VERSION 5.8 ;
BUSBITCHARS "[]" ;
DIVIDERCHAR "/" ;
UNITS
    DATABASE MICRONS 1000 ;
END UNITS

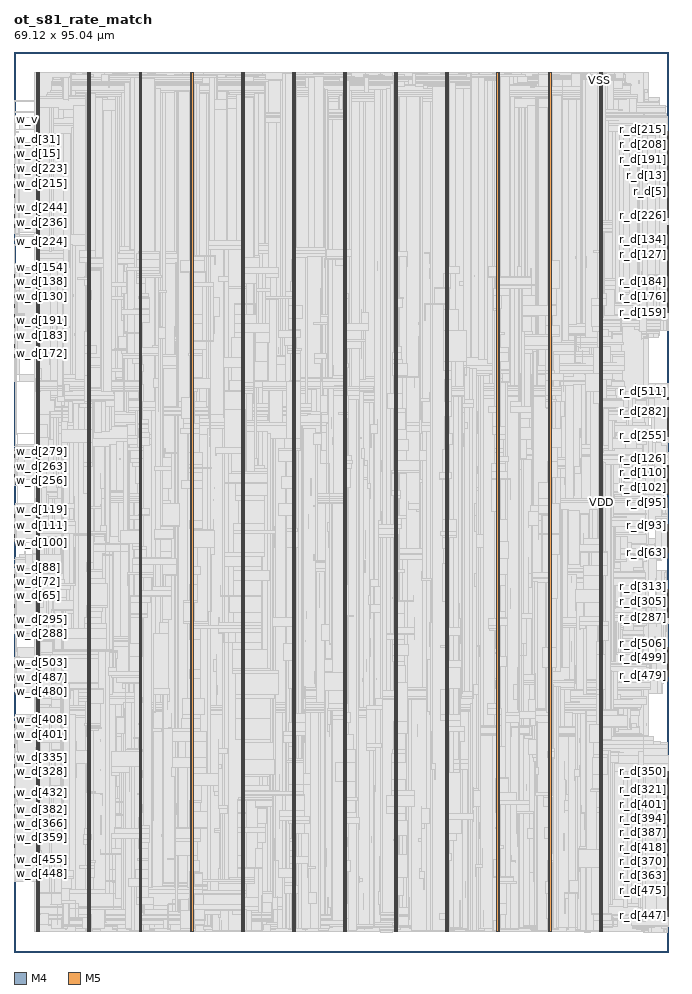
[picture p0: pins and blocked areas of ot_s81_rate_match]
MACRO ot_s81_rate_match
  FOREIGN ot_s81_rate_match 0 0 ;
  CLASS BLOCK ;
  SIZE 69.12 BY 95.04 ;
  PIN fault
    DIRECTION OUTPUT ;
    USE SIGNAL ;
    PORT
      LAYER M4 ;
        RECT  69.036 80.592 69.12 80.616 ;
    END
  END fault
  PIN r_d[0]
    DIRECTION OUTPUT ;
    USE SIGNAL ;
    PORT
      LAYER M4 ;
        RECT  69.036 80.688 69.12 80.712 ;
    END
  END r_d[0]
  PIN r_d[100]
    DIRECTION OUTPUT ;
    USE SIGNAL ;
    PORT
      LAYER M4 ;
        RECT  69.036 48.816 69.12 48.84 ;
    END
  END r_d[100]
  PIN r_d[101]
    DIRECTION OUTPUT ;
    USE SIGNAL ;
    PORT
      LAYER M4 ;
        RECT  69.036 48.912 69.12 48.936 ;
    END
  END r_d[101]
  PIN r_d[102]
    DIRECTION OUTPUT ;
    USE SIGNAL ;
    PORT
      LAYER M4 ;
        RECT  69.036 49.008 69.12 49.032 ;
    END
  END r_d[102]
  PIN r_d[103]
    DIRECTION OUTPUT ;
    USE SIGNAL ;
    PORT
      LAYER M4 ;
        RECT  69.036 49.104 69.12 49.128 ;
    END
  END r_d[103]
  PIN r_d[104]
    DIRECTION OUTPUT ;
    USE SIGNAL ;
    PORT
      LAYER M4 ;
        RECT  69.036 49.2 69.12 49.224 ;
    END
  END r_d[104]
  PIN r_d[105]
    DIRECTION OUTPUT ;
    USE SIGNAL ;
    PORT
      LAYER M4 ;
        RECT  69.036 49.296 69.12 49.32 ;
    END
  END r_d[105]
  PIN r_d[106]
    DIRECTION OUTPUT ;
    USE SIGNAL ;
    PORT
      LAYER M4 ;
        RECT  69.036 49.392 69.12 49.416 ;
    END
  END r_d[106]
  PIN r_d[107]
    DIRECTION OUTPUT ;
    USE SIGNAL ;
    PORT
      LAYER M4 ;
        RECT  69.036 49.488 69.12 49.512 ;
    END
  END r_d[107]
  PIN r_d[108]
    DIRECTION OUTPUT ;
    USE SIGNAL ;
    PORT
      LAYER M4 ;
        RECT  69.036 49.584 69.12 49.608 ;
    END
  END r_d[108]
  PIN r_d[109]
    DIRECTION OUTPUT ;
    USE SIGNAL ;
    PORT
      LAYER M4 ;
        RECT  69.036 49.68 69.12 49.704 ;
    END
  END r_d[109]
  PIN r_d[10]
    DIRECTION OUTPUT ;
    USE SIGNAL ;
    PORT
      LAYER M4 ;
        RECT  69.036 81.648 69.12 81.672 ;
    END
  END r_d[10]
  PIN r_d[110]
    DIRECTION OUTPUT ;
    USE SIGNAL ;
    PORT
      LAYER M4 ;
        RECT  69.036 49.776 69.12 49.8 ;
    END
  END r_d[110]
  PIN r_d[111]
    DIRECTION OUTPUT ;
    USE SIGNAL ;
    PORT
      LAYER M4 ;
        RECT  69.036 49.872 69.12 49.896 ;
    END
  END r_d[111]
  PIN r_d[112]
    DIRECTION OUTPUT ;
    USE SIGNAL ;
    PORT
      LAYER M4 ;
        RECT  69.036 49.968 69.12 49.992 ;
    END
  END r_d[112]
  PIN r_d[113]
    DIRECTION OUTPUT ;
    USE SIGNAL ;
    PORT
      LAYER M4 ;
        RECT  69.036 50.064 69.12 50.088 ;
    END
  END r_d[113]
  PIN r_d[114]
    DIRECTION OUTPUT ;
    USE SIGNAL ;
    PORT
      LAYER M4 ;
        RECT  69.036 50.16 69.12 50.184 ;
    END
  END r_d[114]
  PIN r_d[115]
    DIRECTION OUTPUT ;
    USE SIGNAL ;
    PORT
      LAYER M4 ;
        RECT  69.036 50.256 69.12 50.28 ;
    END
  END r_d[115]
  PIN r_d[116]
    DIRECTION OUTPUT ;
    USE SIGNAL ;
    PORT
      LAYER M4 ;
        RECT  69.036 50.352 69.12 50.376 ;
    END
  END r_d[116]
  PIN r_d[117]
    DIRECTION OUTPUT ;
    USE SIGNAL ;
    PORT
      LAYER M4 ;
        RECT  69.036 50.448 69.12 50.472 ;
    END
  END r_d[117]
  PIN r_d[118]
    DIRECTION OUTPUT ;
    USE SIGNAL ;
    PORT
      LAYER M4 ;
        RECT  69.036 50.544 69.12 50.568 ;
    END
  END r_d[118]
  PIN r_d[119]
    DIRECTION OUTPUT ;
    USE SIGNAL ;
    PORT
      LAYER M4 ;
        RECT  69.036 50.64 69.12 50.664 ;
    END
  END r_d[119]
  PIN r_d[11]
    DIRECTION OUTPUT ;
    USE SIGNAL ;
    PORT
      LAYER M4 ;
        RECT  69.036 81.744 69.12 81.768 ;
    END
  END r_d[11]
  PIN r_d[120]
    DIRECTION OUTPUT ;
    USE SIGNAL ;
    PORT
      LAYER M4 ;
        RECT  69.036 50.736 69.12 50.76 ;
    END
  END r_d[120]
  PIN r_d[121]
    DIRECTION OUTPUT ;
    USE SIGNAL ;
    PORT
      LAYER M4 ;
        RECT  69.036 50.832 69.12 50.856 ;
    END
  END r_d[121]
  PIN r_d[122]
    DIRECTION OUTPUT ;
    USE SIGNAL ;
    PORT
      LAYER M4 ;
        RECT  69.036 50.928 69.12 50.952 ;
    END
  END r_d[122]
  PIN r_d[123]
    DIRECTION OUTPUT ;
    USE SIGNAL ;
    PORT
      LAYER M4 ;
        RECT  69.036 51.024 69.12 51.048 ;
    END
  END r_d[123]
  PIN r_d[124]
    DIRECTION OUTPUT ;
    USE SIGNAL ;
    PORT
      LAYER M4 ;
        RECT  69.036 51.12 69.12 51.144 ;
    END
  END r_d[124]
  PIN r_d[125]
    DIRECTION OUTPUT ;
    USE SIGNAL ;
    PORT
      LAYER M4 ;
        RECT  69.036 51.216 69.12 51.24 ;
    END
  END r_d[125]
  PIN r_d[126]
    DIRECTION OUTPUT ;
    USE SIGNAL ;
    PORT
      LAYER M4 ;
        RECT  69.036 51.312 69.12 51.336 ;
    END
  END r_d[126]
  PIN r_d[127]
    DIRECTION OUTPUT ;
    USE SIGNAL ;
    PORT
      LAYER M4 ;
        RECT  69.036 73.68 69.12 73.704 ;
    END
  END r_d[127]
  PIN r_d[128]
    DIRECTION OUTPUT ;
    USE SIGNAL ;
    PORT
      LAYER M4 ;
        RECT  69.036 73.776 69.12 73.8 ;
    END
  END r_d[128]
  PIN r_d[129]
    DIRECTION OUTPUT ;
    USE SIGNAL ;
    PORT
      LAYER M4 ;
        RECT  69.036 73.872 69.12 73.896 ;
    END
  END r_d[129]
  PIN r_d[12]
    DIRECTION OUTPUT ;
    USE SIGNAL ;
    PORT
      LAYER M4 ;
        RECT  69.036 81.84 69.12 81.864 ;
    END
  END r_d[12]
  PIN r_d[130]
    DIRECTION OUTPUT ;
    USE SIGNAL ;
    PORT
      LAYER M4 ;
        RECT  69.036 73.968 69.12 73.992 ;
    END
  END r_d[130]
  PIN r_d[131]
    DIRECTION OUTPUT ;
    USE SIGNAL ;
    PORT
      LAYER M4 ;
        RECT  69.036 74.064 69.12 74.088 ;
    END
  END r_d[131]
  PIN r_d[132]
    DIRECTION OUTPUT ;
    USE SIGNAL ;
    PORT
      LAYER M4 ;
        RECT  69.036 74.16 69.12 74.184 ;
    END
  END r_d[132]
  PIN r_d[133]
    DIRECTION OUTPUT ;
    USE SIGNAL ;
    PORT
      LAYER M4 ;
        RECT  69.036 74.256 69.12 74.28 ;
    END
  END r_d[133]
  PIN r_d[134]
    DIRECTION OUTPUT ;
    USE SIGNAL ;
    PORT
      LAYER M4 ;
        RECT  69.036 74.352 69.12 74.376 ;
    END
  END r_d[134]
  PIN r_d[135]
    DIRECTION OUTPUT ;
    USE SIGNAL ;
    PORT
      LAYER M4 ;
        RECT  69.036 74.448 69.12 74.472 ;
    END
  END r_d[135]
  PIN r_d[136]
    DIRECTION OUTPUT ;
    USE SIGNAL ;
    PORT
      LAYER M4 ;
        RECT  69.036 74.544 69.12 74.568 ;
    END
  END r_d[136]
  PIN r_d[137]
    DIRECTION OUTPUT ;
    USE SIGNAL ;
    PORT
      LAYER M4 ;
        RECT  69.036 74.64 69.12 74.664 ;
    END
  END r_d[137]
  PIN r_d[138]
    DIRECTION OUTPUT ;
    USE SIGNAL ;
    PORT
      LAYER M4 ;
        RECT  69.036 74.736 69.12 74.76 ;
    END
  END r_d[138]
  PIN r_d[139]
    DIRECTION OUTPUT ;
    USE SIGNAL ;
    PORT
      LAYER M4 ;
        RECT  69.036 74.832 69.12 74.856 ;
    END
  END r_d[139]
  PIN r_d[13]
    DIRECTION OUTPUT ;
    USE SIGNAL ;
    PORT
      LAYER M4 ;
        RECT  69.036 81.936 69.12 81.96 ;
    END
  END r_d[13]
  PIN r_d[140]
    DIRECTION OUTPUT ;
    USE SIGNAL ;
    PORT
      LAYER M4 ;
        RECT  69.036 74.928 69.12 74.952 ;
    END
  END r_d[140]
  PIN r_d[141]
    DIRECTION OUTPUT ;
    USE SIGNAL ;
    PORT
      LAYER M4 ;
        RECT  69.036 75.024 69.12 75.048 ;
    END
  END r_d[141]
  PIN r_d[142]
    DIRECTION OUTPUT ;
    USE SIGNAL ;
    PORT
      LAYER M4 ;
        RECT  69.036 75.12 69.12 75.144 ;
    END
  END r_d[142]
  PIN r_d[143]
    DIRECTION OUTPUT ;
    USE SIGNAL ;
    PORT
      LAYER M4 ;
        RECT  69.036 75.216 69.12 75.24 ;
    END
  END r_d[143]
  PIN r_d[144]
    DIRECTION OUTPUT ;
    USE SIGNAL ;
    PORT
      LAYER M4 ;
        RECT  69.036 75.312 69.12 75.336 ;
    END
  END r_d[144]
  PIN r_d[145]
    DIRECTION OUTPUT ;
    USE SIGNAL ;
    PORT
      LAYER M4 ;
        RECT  69.036 75.408 69.12 75.432 ;
    END
  END r_d[145]
  PIN r_d[146]
    DIRECTION OUTPUT ;
    USE SIGNAL ;
    PORT
      LAYER M4 ;
        RECT  69.036 75.504 69.12 75.528 ;
    END
  END r_d[146]
  PIN r_d[147]
    DIRECTION OUTPUT ;
    USE SIGNAL ;
    PORT
      LAYER M4 ;
        RECT  69.036 75.6 69.12 75.624 ;
    END
  END r_d[147]
  PIN r_d[148]
    DIRECTION OUTPUT ;
    USE SIGNAL ;
    PORT
      LAYER M4 ;
        RECT  69.036 75.696 69.12 75.72 ;
    END
  END r_d[148]
  PIN r_d[149]
    DIRECTION OUTPUT ;
    USE SIGNAL ;
    PORT
      LAYER M4 ;
        RECT  69.036 75.792 69.12 75.816 ;
    END
  END r_d[149]
  PIN r_d[14]
    DIRECTION OUTPUT ;
    USE SIGNAL ;
    PORT
      LAYER M4 ;
        RECT  69.036 82.032 69.12 82.056 ;
    END
  END r_d[14]
  PIN r_d[150]
    DIRECTION OUTPUT ;
    USE SIGNAL ;
    PORT
      LAYER M4 ;
        RECT  69.036 75.888 69.12 75.912 ;
    END
  END r_d[150]
  PIN r_d[151]
    DIRECTION OUTPUT ;
    USE SIGNAL ;
    PORT
      LAYER M4 ;
        RECT  69.036 75.984 69.12 76.008 ;
    END
  END r_d[151]
  PIN r_d[152]
    DIRECTION OUTPUT ;
    USE SIGNAL ;
    PORT
      LAYER M4 ;
        RECT  69.036 76.08 69.12 76.104 ;
    END
  END r_d[152]
  PIN r_d[153]
    DIRECTION OUTPUT ;
    USE SIGNAL ;
    PORT
      LAYER M4 ;
        RECT  69.036 76.176 69.12 76.2 ;
    END
  END r_d[153]
  PIN r_d[154]
    DIRECTION OUTPUT ;
    USE SIGNAL ;
    PORT
      LAYER M4 ;
        RECT  69.036 76.272 69.12 76.296 ;
    END
  END r_d[154]
  PIN r_d[155]
    DIRECTION OUTPUT ;
    USE SIGNAL ;
    PORT
      LAYER M4 ;
        RECT  69.036 76.368 69.12 76.392 ;
    END
  END r_d[155]
  PIN r_d[156]
    DIRECTION OUTPUT ;
    USE SIGNAL ;
    PORT
      LAYER M4 ;
        RECT  69.036 76.464 69.12 76.488 ;
    END
  END r_d[156]
  PIN r_d[157]
    DIRECTION OUTPUT ;
    USE SIGNAL ;
    PORT
      LAYER M4 ;
        RECT  69.036 76.56 69.12 76.584 ;
    END
  END r_d[157]
  PIN r_d[158]
    DIRECTION OUTPUT ;
    USE SIGNAL ;
    PORT
      LAYER M4 ;
        RECT  69.036 76.656 69.12 76.68 ;
    END
  END r_d[158]
  PIN r_d[159]
    DIRECTION OUTPUT ;
    USE SIGNAL ;
    PORT
      LAYER M4 ;
        RECT  69.036 67.536 69.12 67.56 ;
    END
  END r_d[159]
  PIN r_d[15]
    DIRECTION OUTPUT ;
    USE SIGNAL ;
    PORT
      LAYER M4 ;
        RECT  69.036 82.128 69.12 82.152 ;
    END
  END r_d[15]
  PIN r_d[160]
    DIRECTION OUTPUT ;
    USE SIGNAL ;
    PORT
      LAYER M4 ;
        RECT  69.036 67.632 69.12 67.656 ;
    END
  END r_d[160]
  PIN r_d[161]
    DIRECTION OUTPUT ;
    USE SIGNAL ;
    PORT
      LAYER M4 ;
        RECT  69.036 67.728 69.12 67.752 ;
    END
  END r_d[161]
  PIN r_d[162]
    DIRECTION OUTPUT ;
    USE SIGNAL ;
    PORT
      LAYER M4 ;
        RECT  69.036 67.824 69.12 67.848 ;
    END
  END r_d[162]
  PIN r_d[163]
    DIRECTION OUTPUT ;
    USE SIGNAL ;
    PORT
      LAYER M4 ;
        RECT  69.036 67.92 69.12 67.944 ;
    END
  END r_d[163]
  PIN r_d[164]
    DIRECTION OUTPUT ;
    USE SIGNAL ;
    PORT
      LAYER M4 ;
        RECT  69.036 68.016 69.12 68.04 ;
    END
  END r_d[164]
  PIN r_d[165]
    DIRECTION OUTPUT ;
    USE SIGNAL ;
    PORT
      LAYER M4 ;
        RECT  69.036 68.112 69.12 68.136 ;
    END
  END r_d[165]
  PIN r_d[166]
    DIRECTION OUTPUT ;
    USE SIGNAL ;
    PORT
      LAYER M4 ;
        RECT  69.036 68.208 69.12 68.232 ;
    END
  END r_d[166]
  PIN r_d[167]
    DIRECTION OUTPUT ;
    USE SIGNAL ;
    PORT
      LAYER M4 ;
        RECT  69.036 68.304 69.12 68.328 ;
    END
  END r_d[167]
  PIN r_d[168]
    DIRECTION OUTPUT ;
    USE SIGNAL ;
    PORT
      LAYER M4 ;
        RECT  69.036 68.4 69.12 68.424 ;
    END
  END r_d[168]
  PIN r_d[169]
    DIRECTION OUTPUT ;
    USE SIGNAL ;
    PORT
      LAYER M4 ;
        RECT  69.036 68.496 69.12 68.52 ;
    END
  END r_d[169]
  PIN r_d[16]
    DIRECTION OUTPUT ;
    USE SIGNAL ;
    PORT
      LAYER M4 ;
        RECT  69.036 82.224 69.12 82.248 ;
    END
  END r_d[16]
  PIN r_d[170]
    DIRECTION OUTPUT ;
    USE SIGNAL ;
    PORT
      LAYER M4 ;
        RECT  69.036 68.592 69.12 68.616 ;
    END
  END r_d[170]
  PIN r_d[171]
    DIRECTION OUTPUT ;
    USE SIGNAL ;
    PORT
      LAYER M4 ;
        RECT  69.036 68.688 69.12 68.712 ;
    END
  END r_d[171]
  PIN r_d[172]
    DIRECTION OUTPUT ;
    USE SIGNAL ;
    PORT
      LAYER M4 ;
        RECT  69.036 68.784 69.12 68.808 ;
    END
  END r_d[172]
  PIN r_d[173]
    DIRECTION OUTPUT ;
    USE SIGNAL ;
    PORT
      LAYER M4 ;
        RECT  69.036 68.88 69.12 68.904 ;
    END
  END r_d[173]
  PIN r_d[174]
    DIRECTION OUTPUT ;
    USE SIGNAL ;
    PORT
      LAYER M4 ;
        RECT  69.036 68.976 69.12 69 ;
    END
  END r_d[174]
  PIN r_d[175]
    DIRECTION OUTPUT ;
    USE SIGNAL ;
    PORT
      LAYER M4 ;
        RECT  69.036 69.072 69.12 69.096 ;
    END
  END r_d[175]
  PIN r_d[176]
    DIRECTION OUTPUT ;
    USE SIGNAL ;
    PORT
      LAYER M4 ;
        RECT  69.036 69.168 69.12 69.192 ;
    END
  END r_d[176]
  PIN r_d[177]
    DIRECTION OUTPUT ;
    USE SIGNAL ;
    PORT
      LAYER M4 ;
        RECT  69.036 69.264 69.12 69.288 ;
    END
  END r_d[177]
  PIN r_d[178]
    DIRECTION OUTPUT ;
    USE SIGNAL ;
    PORT
      LAYER M4 ;
        RECT  69.036 69.36 69.12 69.384 ;
    END
  END r_d[178]
  PIN r_d[179]
    DIRECTION OUTPUT ;
    USE SIGNAL ;
    PORT
      LAYER M4 ;
        RECT  69.036 69.456 69.12 69.48 ;
    END
  END r_d[179]
  PIN r_d[17]
    DIRECTION OUTPUT ;
    USE SIGNAL ;
    PORT
      LAYER M4 ;
        RECT  69.036 82.32 69.12 82.344 ;
    END
  END r_d[17]
  PIN r_d[180]
    DIRECTION OUTPUT ;
    USE SIGNAL ;
    PORT
      LAYER M4 ;
        RECT  69.036 69.552 69.12 69.576 ;
    END
  END r_d[180]
  PIN r_d[181]
    DIRECTION OUTPUT ;
    USE SIGNAL ;
    PORT
      LAYER M4 ;
        RECT  69.036 69.648 69.12 69.672 ;
    END
  END r_d[181]
  PIN r_d[182]
    DIRECTION OUTPUT ;
    USE SIGNAL ;
    PORT
      LAYER M4 ;
        RECT  69.036 69.744 69.12 69.768 ;
    END
  END r_d[182]
  PIN r_d[183]
    DIRECTION OUTPUT ;
    USE SIGNAL ;
    PORT
      LAYER M4 ;
        RECT  69.036 69.84 69.12 69.864 ;
    END
  END r_d[183]
  PIN r_d[184]
    DIRECTION OUTPUT ;
    USE SIGNAL ;
    PORT
      LAYER M4 ;
        RECT  69.036 69.936 69.12 69.96 ;
    END
  END r_d[184]
  PIN r_d[185]
    DIRECTION OUTPUT ;
    USE SIGNAL ;
    PORT
      LAYER M4 ;
        RECT  69.036 70.032 69.12 70.056 ;
    END
  END r_d[185]
  PIN r_d[186]
    DIRECTION OUTPUT ;
    USE SIGNAL ;
    PORT
      LAYER M4 ;
        RECT  69.036 70.128 69.12 70.152 ;
    END
  END r_d[186]
  PIN r_d[187]
    DIRECTION OUTPUT ;
    USE SIGNAL ;
    PORT
      LAYER M4 ;
        RECT  69.036 70.224 69.12 70.248 ;
    END
  END r_d[187]
  PIN r_d[188]
    DIRECTION OUTPUT ;
    USE SIGNAL ;
    PORT
      LAYER M4 ;
        RECT  69.036 70.32 69.12 70.344 ;
    END
  END r_d[188]
  PIN r_d[189]
    DIRECTION OUTPUT ;
    USE SIGNAL ;
    PORT
      LAYER M4 ;
        RECT  69.036 70.416 69.12 70.44 ;
    END
  END r_d[189]
  PIN r_d[18]
    DIRECTION OUTPUT ;
    USE SIGNAL ;
    PORT
      LAYER M4 ;
        RECT  69.036 82.416 69.12 82.44 ;
    END
  END r_d[18]
  PIN r_d[190]
    DIRECTION OUTPUT ;
    USE SIGNAL ;
    PORT
      LAYER M4 ;
        RECT  69.036 70.512 69.12 70.536 ;
    END
  END r_d[190]
  PIN r_d[191]
    DIRECTION OUTPUT ;
    USE SIGNAL ;
    PORT
      LAYER M4 ;
        RECT  69.036 83.664 69.12 83.688 ;
    END
  END r_d[191]
  PIN r_d[192]
    DIRECTION OUTPUT ;
    USE SIGNAL ;
    PORT
      LAYER M4 ;
        RECT  69.036 83.76 69.12 83.784 ;
    END
  END r_d[192]
  PIN r_d[193]
    DIRECTION OUTPUT ;
    USE SIGNAL ;
    PORT
      LAYER M4 ;
        RECT  69.036 83.856 69.12 83.88 ;
    END
  END r_d[193]
  PIN r_d[194]
    DIRECTION OUTPUT ;
    USE SIGNAL ;
    PORT
      LAYER M4 ;
        RECT  69.036 83.952 69.12 83.976 ;
    END
  END r_d[194]
  PIN r_d[195]
    DIRECTION OUTPUT ;
    USE SIGNAL ;
    PORT
      LAYER M4 ;
        RECT  69.036 84.048 69.12 84.072 ;
    END
  END r_d[195]
  PIN r_d[196]
    DIRECTION OUTPUT ;
    USE SIGNAL ;
    PORT
      LAYER M4 ;
        RECT  69.036 84.144 69.12 84.168 ;
    END
  END r_d[196]
  PIN r_d[197]
    DIRECTION OUTPUT ;
    USE SIGNAL ;
    PORT
      LAYER M4 ;
        RECT  69.036 84.24 69.12 84.264 ;
    END
  END r_d[197]
  PIN r_d[198]
    DIRECTION OUTPUT ;
    USE SIGNAL ;
    PORT
      LAYER M4 ;
        RECT  69.036 84.336 69.12 84.36 ;
    END
  END r_d[198]
  PIN r_d[199]
    DIRECTION OUTPUT ;
    USE SIGNAL ;
    PORT
      LAYER M4 ;
        RECT  69.036 84.432 69.12 84.456 ;
    END
  END r_d[199]
  PIN r_d[19]
    DIRECTION OUTPUT ;
    USE SIGNAL ;
    PORT
      LAYER M4 ;
        RECT  69.036 82.512 69.12 82.536 ;
    END
  END r_d[19]
  PIN r_d[1]
    DIRECTION OUTPUT ;
    USE SIGNAL ;
    PORT
      LAYER M4 ;
        RECT  69.036 80.784 69.12 80.808 ;
    END
  END r_d[1]
  PIN r_d[200]
    DIRECTION OUTPUT ;
    USE SIGNAL ;
    PORT
      LAYER M4 ;
        RECT  69.036 84.528 69.12 84.552 ;
    END
  END r_d[200]
  PIN r_d[201]
    DIRECTION OUTPUT ;
    USE SIGNAL ;
    PORT
      LAYER M4 ;
        RECT  69.036 84.624 69.12 84.648 ;
    END
  END r_d[201]
  PIN r_d[202]
    DIRECTION OUTPUT ;
    USE SIGNAL ;
    PORT
      LAYER M4 ;
        RECT  69.036 84.72 69.12 84.744 ;
    END
  END r_d[202]
  PIN r_d[203]
    DIRECTION OUTPUT ;
    USE SIGNAL ;
    PORT
      LAYER M4 ;
        RECT  69.036 84.816 69.12 84.84 ;
    END
  END r_d[203]
  PIN r_d[204]
    DIRECTION OUTPUT ;
    USE SIGNAL ;
    PORT
      LAYER M4 ;
        RECT  69.036 84.912 69.12 84.936 ;
    END
  END r_d[204]
  PIN r_d[205]
    DIRECTION OUTPUT ;
    USE SIGNAL ;
    PORT
      LAYER M4 ;
        RECT  69.036 85.008 69.12 85.032 ;
    END
  END r_d[205]
  PIN r_d[206]
    DIRECTION OUTPUT ;
    USE SIGNAL ;
    PORT
      LAYER M4 ;
        RECT  69.036 85.104 69.12 85.128 ;
    END
  END r_d[206]
  PIN r_d[207]
    DIRECTION OUTPUT ;
    USE SIGNAL ;
    PORT
      LAYER M4 ;
        RECT  69.036 85.2 69.12 85.224 ;
    END
  END r_d[207]
  PIN r_d[208]
    DIRECTION OUTPUT ;
    USE SIGNAL ;
    PORT
      LAYER M4 ;
        RECT  69.036 85.296 69.12 85.32 ;
    END
  END r_d[208]
  PIN r_d[209]
    DIRECTION OUTPUT ;
    USE SIGNAL ;
    PORT
      LAYER M4 ;
        RECT  69.036 85.392 69.12 85.416 ;
    END
  END r_d[209]
  PIN r_d[20]
    DIRECTION OUTPUT ;
    USE SIGNAL ;
    PORT
      LAYER M4 ;
        RECT  69.036 82.608 69.12 82.632 ;
    END
  END r_d[20]
  PIN r_d[210]
    DIRECTION OUTPUT ;
    USE SIGNAL ;
    PORT
      LAYER M4 ;
        RECT  69.036 85.488 69.12 85.512 ;
    END
  END r_d[210]
  PIN r_d[211]
    DIRECTION OUTPUT ;
    USE SIGNAL ;
    PORT
      LAYER M4 ;
        RECT  69.036 85.584 69.12 85.608 ;
    END
  END r_d[211]
  PIN r_d[212]
    DIRECTION OUTPUT ;
    USE SIGNAL ;
    PORT
      LAYER M4 ;
        RECT  69.036 85.68 69.12 85.704 ;
    END
  END r_d[212]
  PIN r_d[213]
    DIRECTION OUTPUT ;
    USE SIGNAL ;
    PORT
      LAYER M4 ;
        RECT  69.036 85.776 69.12 85.8 ;
    END
  END r_d[213]
  PIN r_d[214]
    DIRECTION OUTPUT ;
    USE SIGNAL ;
    PORT
      LAYER M4 ;
        RECT  69.036 85.872 69.12 85.896 ;
    END
  END r_d[214]
  PIN r_d[215]
    DIRECTION OUTPUT ;
    USE SIGNAL ;
    PORT
      LAYER M4 ;
        RECT  69.036 85.968 69.12 85.992 ;
    END
  END r_d[215]
  PIN r_d[216]
    DIRECTION OUTPUT ;
    USE SIGNAL ;
    PORT
      LAYER M4 ;
        RECT  69.036 86.064 69.12 86.088 ;
    END
  END r_d[216]
  PIN r_d[217]
    DIRECTION OUTPUT ;
    USE SIGNAL ;
    PORT
      LAYER M4 ;
        RECT  69.036 86.16 69.12 86.184 ;
    END
  END r_d[217]
  PIN r_d[218]
    DIRECTION OUTPUT ;
    USE SIGNAL ;
    PORT
      LAYER M4 ;
        RECT  69.036 86.256 69.12 86.28 ;
    END
  END r_d[218]
  PIN r_d[219]
    DIRECTION OUTPUT ;
    USE SIGNAL ;
    PORT
      LAYER M4 ;
        RECT  69.036 86.352 69.12 86.376 ;
    END
  END r_d[219]
  PIN r_d[21]
    DIRECTION OUTPUT ;
    USE SIGNAL ;
    PORT
      LAYER M4 ;
        RECT  69.036 82.704 69.12 82.728 ;
    END
  END r_d[21]
  PIN r_d[220]
    DIRECTION OUTPUT ;
    USE SIGNAL ;
    PORT
      LAYER M4 ;
        RECT  69.036 86.448 69.12 86.472 ;
    END
  END r_d[220]
  PIN r_d[221]
    DIRECTION OUTPUT ;
    USE SIGNAL ;
    PORT
      LAYER M4 ;
        RECT  69.036 86.544 69.12 86.568 ;
    END
  END r_d[221]
  PIN r_d[222]
    DIRECTION OUTPUT ;
    USE SIGNAL ;
    PORT
      LAYER M4 ;
        RECT  69.036 86.64 69.12 86.664 ;
    END
  END r_d[222]
  PIN r_d[223]
    DIRECTION OUTPUT ;
    USE SIGNAL ;
    PORT
      LAYER M4 ;
        RECT  69.036 77.52 69.12 77.544 ;
    END
  END r_d[223]
  PIN r_d[224]
    DIRECTION OUTPUT ;
    USE SIGNAL ;
    PORT
      LAYER M4 ;
        RECT  69.036 77.616 69.12 77.64 ;
    END
  END r_d[224]
  PIN r_d[225]
    DIRECTION OUTPUT ;
    USE SIGNAL ;
    PORT
      LAYER M4 ;
        RECT  69.036 77.712 69.12 77.736 ;
    END
  END r_d[225]
  PIN r_d[226]
    DIRECTION OUTPUT ;
    USE SIGNAL ;
    PORT
      LAYER M4 ;
        RECT  69.036 77.808 69.12 77.832 ;
    END
  END r_d[226]
  PIN r_d[227]
    DIRECTION OUTPUT ;
    USE SIGNAL ;
    PORT
      LAYER M4 ;
        RECT  69.036 77.904 69.12 77.928 ;
    END
  END r_d[227]
  PIN r_d[228]
    DIRECTION OUTPUT ;
    USE SIGNAL ;
    PORT
      LAYER M4 ;
        RECT  69.036 78 69.12 78.024 ;
    END
  END r_d[228]
  PIN r_d[229]
    DIRECTION OUTPUT ;
    USE SIGNAL ;
    PORT
      LAYER M4 ;
        RECT  69.036 78.096 69.12 78.12 ;
    END
  END r_d[229]
  PIN r_d[22]
    DIRECTION OUTPUT ;
    USE SIGNAL ;
    PORT
      LAYER M4 ;
        RECT  69.036 82.8 69.12 82.824 ;
    END
  END r_d[22]
  PIN r_d[230]
    DIRECTION OUTPUT ;
    USE SIGNAL ;
    PORT
      LAYER M4 ;
        RECT  69.036 78.192 69.12 78.216 ;
    END
  END r_d[230]
  PIN r_d[231]
    DIRECTION OUTPUT ;
    USE SIGNAL ;
    PORT
      LAYER M4 ;
        RECT  69.036 78.288 69.12 78.312 ;
    END
  END r_d[231]
  PIN r_d[232]
    DIRECTION OUTPUT ;
    USE SIGNAL ;
    PORT
      LAYER M4 ;
        RECT  69.036 78.384 69.12 78.408 ;
    END
  END r_d[232]
  PIN r_d[233]
    DIRECTION OUTPUT ;
    USE SIGNAL ;
    PORT
      LAYER M4 ;
        RECT  69.036 78.48 69.12 78.504 ;
    END
  END r_d[233]
  PIN r_d[234]
    DIRECTION OUTPUT ;
    USE SIGNAL ;
    PORT
      LAYER M4 ;
        RECT  69.036 78.576 69.12 78.6 ;
    END
  END r_d[234]
  PIN r_d[235]
    DIRECTION OUTPUT ;
    USE SIGNAL ;
    PORT
      LAYER M4 ;
        RECT  69.036 78.672 69.12 78.696 ;
    END
  END r_d[235]
  PIN r_d[236]
    DIRECTION OUTPUT ;
    USE SIGNAL ;
    PORT
      LAYER M4 ;
        RECT  69.036 78.768 69.12 78.792 ;
    END
  END r_d[236]
  PIN r_d[237]
    DIRECTION OUTPUT ;
    USE SIGNAL ;
    PORT
      LAYER M4 ;
        RECT  69.036 78.864 69.12 78.888 ;
    END
  END r_d[237]
  PIN r_d[238]
    DIRECTION OUTPUT ;
    USE SIGNAL ;
    PORT
      LAYER M4 ;
        RECT  69.036 78.96 69.12 78.984 ;
    END
  END r_d[238]
  PIN r_d[239]
    DIRECTION OUTPUT ;
    USE SIGNAL ;
    PORT
      LAYER M4 ;
        RECT  69.036 79.056 69.12 79.08 ;
    END
  END r_d[239]
  PIN r_d[23]
    DIRECTION OUTPUT ;
    USE SIGNAL ;
    PORT
      LAYER M4 ;
        RECT  69.036 82.896 69.12 82.92 ;
    END
  END r_d[23]
  PIN r_d[240]
    DIRECTION OUTPUT ;
    USE SIGNAL ;
    PORT
      LAYER M4 ;
        RECT  69.036 79.152 69.12 79.176 ;
    END
  END r_d[240]
  PIN r_d[241]
    DIRECTION OUTPUT ;
    USE SIGNAL ;
    PORT
      LAYER M4 ;
        RECT  69.036 79.248 69.12 79.272 ;
    END
  END r_d[241]
  PIN r_d[242]
    DIRECTION OUTPUT ;
    USE SIGNAL ;
    PORT
      LAYER M4 ;
        RECT  69.036 79.344 69.12 79.368 ;
    END
  END r_d[242]
  PIN r_d[243]
    DIRECTION OUTPUT ;
    USE SIGNAL ;
    PORT
      LAYER M4 ;
        RECT  69.036 79.44 69.12 79.464 ;
    END
  END r_d[243]
  PIN r_d[244]
    DIRECTION OUTPUT ;
    USE SIGNAL ;
    PORT
      LAYER M4 ;
        RECT  69.036 79.536 69.12 79.56 ;
    END
  END r_d[244]
  PIN r_d[245]
    DIRECTION OUTPUT ;
    USE SIGNAL ;
    PORT
      LAYER M4 ;
        RECT  69.036 79.632 69.12 79.656 ;
    END
  END r_d[245]
  PIN r_d[246]
    DIRECTION OUTPUT ;
    USE SIGNAL ;
    PORT
      LAYER M4 ;
        RECT  69.036 79.728 69.12 79.752 ;
    END
  END r_d[246]
  PIN r_d[247]
    DIRECTION OUTPUT ;
    USE SIGNAL ;
    PORT
      LAYER M4 ;
        RECT  69.036 79.824 69.12 79.848 ;
    END
  END r_d[247]
  PIN r_d[248]
    DIRECTION OUTPUT ;
    USE SIGNAL ;
    PORT
      LAYER M4 ;
        RECT  69.036 79.92 69.12 79.944 ;
    END
  END r_d[248]
  PIN r_d[249]
    DIRECTION OUTPUT ;
    USE SIGNAL ;
    PORT
      LAYER M4 ;
        RECT  69.036 80.016 69.12 80.04 ;
    END
  END r_d[249]
  PIN r_d[24]
    DIRECTION OUTPUT ;
    USE SIGNAL ;
    PORT
      LAYER M4 ;
        RECT  69.036 82.992 69.12 83.016 ;
    END
  END r_d[24]
  PIN r_d[250]
    DIRECTION OUTPUT ;
    USE SIGNAL ;
    PORT
      LAYER M4 ;
        RECT  69.036 80.112 69.12 80.136 ;
    END
  END r_d[250]
  PIN r_d[251]
    DIRECTION OUTPUT ;
    USE SIGNAL ;
    PORT
      LAYER M4 ;
        RECT  69.036 80.208 69.12 80.232 ;
    END
  END r_d[251]
  PIN r_d[252]
    DIRECTION OUTPUT ;
    USE SIGNAL ;
    PORT
      LAYER M4 ;
        RECT  69.036 80.304 69.12 80.328 ;
    END
  END r_d[252]
  PIN r_d[253]
    DIRECTION OUTPUT ;
    USE SIGNAL ;
    PORT
      LAYER M4 ;
        RECT  69.036 80.4 69.12 80.424 ;
    END
  END r_d[253]
  PIN r_d[254]
    DIRECTION OUTPUT ;
    USE SIGNAL ;
    PORT
      LAYER M4 ;
        RECT  69.036 80.496 69.12 80.52 ;
    END
  END r_d[254]
  PIN r_d[255]
    DIRECTION OUTPUT ;
    USE SIGNAL ;
    PORT
      LAYER M4 ;
        RECT  69.036 54.48 69.12 54.504 ;
    END
  END r_d[255]
  PIN r_d[256]
    DIRECTION OUTPUT ;
    USE SIGNAL ;
    PORT
      LAYER M4 ;
        RECT  69.036 54.576 69.12 54.6 ;
    END
  END r_d[256]
  PIN r_d[257]
    DIRECTION OUTPUT ;
    USE SIGNAL ;
    PORT
      LAYER M4 ;
        RECT  69.036 54.672 69.12 54.696 ;
    END
  END r_d[257]
  PIN r_d[258]
    DIRECTION OUTPUT ;
    USE SIGNAL ;
    PORT
      LAYER M4 ;
        RECT  69.036 54.768 69.12 54.792 ;
    END
  END r_d[258]
  PIN r_d[259]
    DIRECTION OUTPUT ;
    USE SIGNAL ;
    PORT
      LAYER M4 ;
        RECT  69.036 54.864 69.12 54.888 ;
    END
  END r_d[259]
  PIN r_d[25]
    DIRECTION OUTPUT ;
    USE SIGNAL ;
    PORT
      LAYER M4 ;
        RECT  69.036 83.088 69.12 83.112 ;
    END
  END r_d[25]
  PIN r_d[260]
    DIRECTION OUTPUT ;
    USE SIGNAL ;
    PORT
      LAYER M4 ;
        RECT  69.036 54.96 69.12 54.984 ;
    END
  END r_d[260]
  PIN r_d[261]
    DIRECTION OUTPUT ;
    USE SIGNAL ;
    PORT
      LAYER M4 ;
        RECT  69.036 55.056 69.12 55.08 ;
    END
  END r_d[261]
  PIN r_d[262]
    DIRECTION OUTPUT ;
    USE SIGNAL ;
    PORT
      LAYER M4 ;
        RECT  69.036 55.152 69.12 55.176 ;
    END
  END r_d[262]
  PIN r_d[263]
    DIRECTION OUTPUT ;
    USE SIGNAL ;
    PORT
      LAYER M4 ;
        RECT  69.036 55.248 69.12 55.272 ;
    END
  END r_d[263]
  PIN r_d[264]
    DIRECTION OUTPUT ;
    USE SIGNAL ;
    PORT
      LAYER M4 ;
        RECT  69.036 55.344 69.12 55.368 ;
    END
  END r_d[264]
  PIN r_d[265]
    DIRECTION OUTPUT ;
    USE SIGNAL ;
    PORT
      LAYER M4 ;
        RECT  69.036 55.44 69.12 55.464 ;
    END
  END r_d[265]
  PIN r_d[266]
    DIRECTION OUTPUT ;
    USE SIGNAL ;
    PORT
      LAYER M4 ;
        RECT  69.036 55.536 69.12 55.56 ;
    END
  END r_d[266]
  PIN r_d[267]
    DIRECTION OUTPUT ;
    USE SIGNAL ;
    PORT
      LAYER M4 ;
        RECT  69.036 55.632 69.12 55.656 ;
    END
  END r_d[267]
  PIN r_d[268]
    DIRECTION OUTPUT ;
    USE SIGNAL ;
    PORT
      LAYER M4 ;
        RECT  69.036 55.728 69.12 55.752 ;
    END
  END r_d[268]
  PIN r_d[269]
    DIRECTION OUTPUT ;
    USE SIGNAL ;
    PORT
      LAYER M4 ;
        RECT  69.036 55.824 69.12 55.848 ;
    END
  END r_d[269]
  PIN r_d[26]
    DIRECTION OUTPUT ;
    USE SIGNAL ;
    PORT
      LAYER M4 ;
        RECT  69.036 83.184 69.12 83.208 ;
    END
  END r_d[26]
  PIN r_d[270]
    DIRECTION OUTPUT ;
    USE SIGNAL ;
    PORT
      LAYER M4 ;
        RECT  69.036 55.92 69.12 55.944 ;
    END
  END r_d[270]
  PIN r_d[271]
    DIRECTION OUTPUT ;
    USE SIGNAL ;
    PORT
      LAYER M4 ;
        RECT  69.036 56.016 69.12 56.04 ;
    END
  END r_d[271]
  PIN r_d[272]
    DIRECTION OUTPUT ;
    USE SIGNAL ;
    PORT
      LAYER M4 ;
        RECT  69.036 56.112 69.12 56.136 ;
    END
  END r_d[272]
  PIN r_d[273]
    DIRECTION OUTPUT ;
    USE SIGNAL ;
    PORT
      LAYER M4 ;
        RECT  69.036 56.208 69.12 56.232 ;
    END
  END r_d[273]
  PIN r_d[274]
    DIRECTION OUTPUT ;
    USE SIGNAL ;
    PORT
      LAYER M4 ;
        RECT  69.036 56.304 69.12 56.328 ;
    END
  END r_d[274]
  PIN r_d[275]
    DIRECTION OUTPUT ;
    USE SIGNAL ;
    PORT
      LAYER M4 ;
        RECT  69.036 56.4 69.12 56.424 ;
    END
  END r_d[275]
  PIN r_d[276]
    DIRECTION OUTPUT ;
    USE SIGNAL ;
    PORT
      LAYER M4 ;
        RECT  69.036 56.496 69.12 56.52 ;
    END
  END r_d[276]
  PIN r_d[277]
    DIRECTION OUTPUT ;
    USE SIGNAL ;
    PORT
      LAYER M4 ;
        RECT  69.036 56.592 69.12 56.616 ;
    END
  END r_d[277]
  PIN r_d[278]
    DIRECTION OUTPUT ;
    USE SIGNAL ;
    PORT
      LAYER M4 ;
        RECT  69.036 56.688 69.12 56.712 ;
    END
  END r_d[278]
  PIN r_d[279]
    DIRECTION OUTPUT ;
    USE SIGNAL ;
    PORT
      LAYER M4 ;
        RECT  69.036 56.784 69.12 56.808 ;
    END
  END r_d[279]
  PIN r_d[27]
    DIRECTION OUTPUT ;
    USE SIGNAL ;
    PORT
      LAYER M4 ;
        RECT  69.036 83.28 69.12 83.304 ;
    END
  END r_d[27]
  PIN r_d[280]
    DIRECTION OUTPUT ;
    USE SIGNAL ;
    PORT
      LAYER M4 ;
        RECT  69.036 56.88 69.12 56.904 ;
    END
  END r_d[280]
  PIN r_d[281]
    DIRECTION OUTPUT ;
    USE SIGNAL ;
    PORT
      LAYER M4 ;
        RECT  69.036 56.976 69.12 57 ;
    END
  END r_d[281]
  PIN r_d[282]
    DIRECTION OUTPUT ;
    USE SIGNAL ;
    PORT
      LAYER M4 ;
        RECT  69.036 57.072 69.12 57.096 ;
    END
  END r_d[282]
  PIN r_d[283]
    DIRECTION OUTPUT ;
    USE SIGNAL ;
    PORT
      LAYER M4 ;
        RECT  69.036 57.168 69.12 57.192 ;
    END
  END r_d[283]
  PIN r_d[284]
    DIRECTION OUTPUT ;
    USE SIGNAL ;
    PORT
      LAYER M4 ;
        RECT  69.036 57.264 69.12 57.288 ;
    END
  END r_d[284]
  PIN r_d[285]
    DIRECTION OUTPUT ;
    USE SIGNAL ;
    PORT
      LAYER M4 ;
        RECT  69.036 57.36 69.12 57.384 ;
    END
  END r_d[285]
  PIN r_d[286]
    DIRECTION OUTPUT ;
    USE SIGNAL ;
    PORT
      LAYER M4 ;
        RECT  69.036 57.456 69.12 57.48 ;
    END
  END r_d[286]
  PIN r_d[287]
    DIRECTION OUTPUT ;
    USE SIGNAL ;
    PORT
      LAYER M4 ;
        RECT  69.036 35.28 69.12 35.304 ;
    END
  END r_d[287]
  PIN r_d[288]
    DIRECTION OUTPUT ;
    USE SIGNAL ;
    PORT
      LAYER M4 ;
        RECT  69.036 35.376 69.12 35.4 ;
    END
  END r_d[288]
  PIN r_d[289]
    DIRECTION OUTPUT ;
    USE SIGNAL ;
    PORT
      LAYER M4 ;
        RECT  69.036 35.472 69.12 35.496 ;
    END
  END r_d[289]
  PIN r_d[28]
    DIRECTION OUTPUT ;
    USE SIGNAL ;
    PORT
      LAYER M4 ;
        RECT  69.036 83.376 69.12 83.4 ;
    END
  END r_d[28]
  PIN r_d[290]
    DIRECTION OUTPUT ;
    USE SIGNAL ;
    PORT
      LAYER M4 ;
        RECT  69.036 35.568 69.12 35.592 ;
    END
  END r_d[290]
  PIN r_d[291]
    DIRECTION OUTPUT ;
    USE SIGNAL ;
    PORT
      LAYER M4 ;
        RECT  69.036 35.664 69.12 35.688 ;
    END
  END r_d[291]
  PIN r_d[292]
    DIRECTION OUTPUT ;
    USE SIGNAL ;
    PORT
      LAYER M4 ;
        RECT  69.036 35.76 69.12 35.784 ;
    END
  END r_d[292]
  PIN r_d[293]
    DIRECTION OUTPUT ;
    USE SIGNAL ;
    PORT
      LAYER M4 ;
        RECT  69.036 35.856 69.12 35.88 ;
    END
  END r_d[293]
  PIN r_d[294]
    DIRECTION OUTPUT ;
    USE SIGNAL ;
    PORT
      LAYER M4 ;
        RECT  69.036 35.952 69.12 35.976 ;
    END
  END r_d[294]
  PIN r_d[295]
    DIRECTION OUTPUT ;
    USE SIGNAL ;
    PORT
      LAYER M4 ;
        RECT  69.036 36.048 69.12 36.072 ;
    END
  END r_d[295]
  PIN r_d[296]
    DIRECTION OUTPUT ;
    USE SIGNAL ;
    PORT
      LAYER M4 ;
        RECT  69.036 36.144 69.12 36.168 ;
    END
  END r_d[296]
  PIN r_d[297]
    DIRECTION OUTPUT ;
    USE SIGNAL ;
    PORT
      LAYER M4 ;
        RECT  69.036 36.24 69.12 36.264 ;
    END
  END r_d[297]
  PIN r_d[298]
    DIRECTION OUTPUT ;
    USE SIGNAL ;
    PORT
      LAYER M4 ;
        RECT  69.036 36.336 69.12 36.36 ;
    END
  END r_d[298]
  PIN r_d[299]
    DIRECTION OUTPUT ;
    USE SIGNAL ;
    PORT
      LAYER M4 ;
        RECT  69.036 36.432 69.12 36.456 ;
    END
  END r_d[299]
  PIN r_d[29]
    DIRECTION OUTPUT ;
    USE SIGNAL ;
    PORT
      LAYER M4 ;
        RECT  69.036 83.472 69.12 83.496 ;
    END
  END r_d[29]
  PIN r_d[2]
    DIRECTION OUTPUT ;
    USE SIGNAL ;
    PORT
      LAYER M4 ;
        RECT  69.036 80.88 69.12 80.904 ;
    END
  END r_d[2]
  PIN r_d[300]
    DIRECTION OUTPUT ;
    USE SIGNAL ;
    PORT
      LAYER M4 ;
        RECT  69.036 36.528 69.12 36.552 ;
    END
  END r_d[300]
  PIN r_d[301]
    DIRECTION OUTPUT ;
    USE SIGNAL ;
    PORT
      LAYER M4 ;
        RECT  69.036 36.624 69.12 36.648 ;
    END
  END r_d[301]
  PIN r_d[302]
    DIRECTION OUTPUT ;
    USE SIGNAL ;
    PORT
      LAYER M4 ;
        RECT  69.036 36.72 69.12 36.744 ;
    END
  END r_d[302]
  PIN r_d[303]
    DIRECTION OUTPUT ;
    USE SIGNAL ;
    PORT
      LAYER M4 ;
        RECT  69.036 36.816 69.12 36.84 ;
    END
  END r_d[303]
  PIN r_d[304]
    DIRECTION OUTPUT ;
    USE SIGNAL ;
    PORT
      LAYER M4 ;
        RECT  69.036 36.912 69.12 36.936 ;
    END
  END r_d[304]
  PIN r_d[305]
    DIRECTION OUTPUT ;
    USE SIGNAL ;
    PORT
      LAYER M4 ;
        RECT  69.036 37.008 69.12 37.032 ;
    END
  END r_d[305]
  PIN r_d[306]
    DIRECTION OUTPUT ;
    USE SIGNAL ;
    PORT
      LAYER M4 ;
        RECT  69.036 37.104 69.12 37.128 ;
    END
  END r_d[306]
  PIN r_d[307]
    DIRECTION OUTPUT ;
    USE SIGNAL ;
    PORT
      LAYER M4 ;
        RECT  69.036 37.2 69.12 37.224 ;
    END
  END r_d[307]
  PIN r_d[308]
    DIRECTION OUTPUT ;
    USE SIGNAL ;
    PORT
      LAYER M4 ;
        RECT  69.036 37.296 69.12 37.32 ;
    END
  END r_d[308]
  PIN r_d[309]
    DIRECTION OUTPUT ;
    USE SIGNAL ;
    PORT
      LAYER M4 ;
        RECT  69.036 37.392 69.12 37.416 ;
    END
  END r_d[309]
  PIN r_d[30]
    DIRECTION OUTPUT ;
    USE SIGNAL ;
    PORT
      LAYER M4 ;
        RECT  69.036 83.568 69.12 83.592 ;
    END
  END r_d[30]
  PIN r_d[310]
    DIRECTION OUTPUT ;
    USE SIGNAL ;
    PORT
      LAYER M4 ;
        RECT  69.036 37.488 69.12 37.512 ;
    END
  END r_d[310]
  PIN r_d[311]
    DIRECTION OUTPUT ;
    USE SIGNAL ;
    PORT
      LAYER M4 ;
        RECT  69.036 37.584 69.12 37.608 ;
    END
  END r_d[311]
  PIN r_d[312]
    DIRECTION OUTPUT ;
    USE SIGNAL ;
    PORT
      LAYER M4 ;
        RECT  69.036 37.68 69.12 37.704 ;
    END
  END r_d[312]
  PIN r_d[313]
    DIRECTION OUTPUT ;
    USE SIGNAL ;
    PORT
      LAYER M4 ;
        RECT  69.036 37.776 69.12 37.8 ;
    END
  END r_d[313]
  PIN r_d[314]
    DIRECTION OUTPUT ;
    USE SIGNAL ;
    PORT
      LAYER M4 ;
        RECT  69.036 37.872 69.12 37.896 ;
    END
  END r_d[314]
  PIN r_d[315]
    DIRECTION OUTPUT ;
    USE SIGNAL ;
    PORT
      LAYER M4 ;
        RECT  69.036 37.968 69.12 37.992 ;
    END
  END r_d[315]
  PIN r_d[316]
    DIRECTION OUTPUT ;
    USE SIGNAL ;
    PORT
      LAYER M4 ;
        RECT  69.036 38.064 69.12 38.088 ;
    END
  END r_d[316]
  PIN r_d[317]
    DIRECTION OUTPUT ;
    USE SIGNAL ;
    PORT
      LAYER M4 ;
        RECT  69.036 38.16 69.12 38.184 ;
    END
  END r_d[317]
  PIN r_d[318]
    DIRECTION OUTPUT ;
    USE SIGNAL ;
    PORT
      LAYER M4 ;
        RECT  69.036 38.256 69.12 38.28 ;
    END
  END r_d[318]
  PIN r_d[319]
    DIRECTION OUTPUT ;
    USE SIGNAL ;
    PORT
      LAYER M4 ;
        RECT  69.036 16.08 69.12 16.104 ;
    END
  END r_d[319]
  PIN r_d[31]
    DIRECTION OUTPUT ;
    USE SIGNAL ;
    PORT
      LAYER M4 ;
        RECT  69.036 70.608 69.12 70.632 ;
    END
  END r_d[31]
  PIN r_d[320]
    DIRECTION OUTPUT ;
    USE SIGNAL ;
    PORT
      LAYER M4 ;
        RECT  69.036 16.176 69.12 16.2 ;
    END
  END r_d[320]
  PIN r_d[321]
    DIRECTION OUTPUT ;
    USE SIGNAL ;
    PORT
      LAYER M4 ;
        RECT  69.036 16.272 69.12 16.296 ;
    END
  END r_d[321]
  PIN r_d[322]
    DIRECTION OUTPUT ;
    USE SIGNAL ;
    PORT
      LAYER M4 ;
        RECT  69.036 16.368 69.12 16.392 ;
    END
  END r_d[322]
  PIN r_d[323]
    DIRECTION OUTPUT ;
    USE SIGNAL ;
    PORT
      LAYER M4 ;
        RECT  69.036 16.464 69.12 16.488 ;
    END
  END r_d[323]
  PIN r_d[324]
    DIRECTION OUTPUT ;
    USE SIGNAL ;
    PORT
      LAYER M4 ;
        RECT  69.036 16.56 69.12 16.584 ;
    END
  END r_d[324]
  PIN r_d[325]
    DIRECTION OUTPUT ;
    USE SIGNAL ;
    PORT
      LAYER M4 ;
        RECT  69.036 16.656 69.12 16.68 ;
    END
  END r_d[325]
  PIN r_d[326]
    DIRECTION OUTPUT ;
    USE SIGNAL ;
    PORT
      LAYER M4 ;
        RECT  69.036 16.752 69.12 16.776 ;
    END
  END r_d[326]
  PIN r_d[327]
    DIRECTION OUTPUT ;
    USE SIGNAL ;
    PORT
      LAYER M4 ;
        RECT  69.036 16.848 69.12 16.872 ;
    END
  END r_d[327]
  PIN r_d[328]
    DIRECTION OUTPUT ;
    USE SIGNAL ;
    PORT
      LAYER M4 ;
        RECT  69.036 16.944 69.12 16.968 ;
    END
  END r_d[328]
  PIN r_d[329]
    DIRECTION OUTPUT ;
    USE SIGNAL ;
    PORT
      LAYER M4 ;
        RECT  69.036 17.04 69.12 17.064 ;
    END
  END r_d[329]
  PIN r_d[32]
    DIRECTION OUTPUT ;
    USE SIGNAL ;
    PORT
      LAYER M4 ;
        RECT  69.036 70.704 69.12 70.728 ;
    END
  END r_d[32]
  PIN r_d[330]
    DIRECTION OUTPUT ;
    USE SIGNAL ;
    PORT
      LAYER M4 ;
        RECT  69.036 17.136 69.12 17.16 ;
    END
  END r_d[330]
  PIN r_d[331]
    DIRECTION OUTPUT ;
    USE SIGNAL ;
    PORT
      LAYER M4 ;
        RECT  69.036 17.232 69.12 17.256 ;
    END
  END r_d[331]
  PIN r_d[332]
    DIRECTION OUTPUT ;
    USE SIGNAL ;
    PORT
      LAYER M4 ;
        RECT  69.036 17.328 69.12 17.352 ;
    END
  END r_d[332]
  PIN r_d[333]
    DIRECTION OUTPUT ;
    USE SIGNAL ;
    PORT
      LAYER M4 ;
        RECT  69.036 17.424 69.12 17.448 ;
    END
  END r_d[333]
  PIN r_d[334]
    DIRECTION OUTPUT ;
    USE SIGNAL ;
    PORT
      LAYER M4 ;
        RECT  69.036 17.52 69.12 17.544 ;
    END
  END r_d[334]
  PIN r_d[335]
    DIRECTION OUTPUT ;
    USE SIGNAL ;
    PORT
      LAYER M4 ;
        RECT  69.036 17.616 69.12 17.64 ;
    END
  END r_d[335]
  PIN r_d[336]
    DIRECTION OUTPUT ;
    USE SIGNAL ;
    PORT
      LAYER M4 ;
        RECT  69.036 17.712 69.12 17.736 ;
    END
  END r_d[336]
  PIN r_d[337]
    DIRECTION OUTPUT ;
    USE SIGNAL ;
    PORT
      LAYER M4 ;
        RECT  69.036 17.808 69.12 17.832 ;
    END
  END r_d[337]
  PIN r_d[338]
    DIRECTION OUTPUT ;
    USE SIGNAL ;
    PORT
      LAYER M4 ;
        RECT  69.036 17.904 69.12 17.928 ;
    END
  END r_d[338]
  PIN r_d[339]
    DIRECTION OUTPUT ;
    USE SIGNAL ;
    PORT
      LAYER M4 ;
        RECT  69.036 18 69.12 18.024 ;
    END
  END r_d[339]
  PIN r_d[33]
    DIRECTION OUTPUT ;
    USE SIGNAL ;
    PORT
      LAYER M4 ;
        RECT  69.036 70.8 69.12 70.824 ;
    END
  END r_d[33]
  PIN r_d[340]
    DIRECTION OUTPUT ;
    USE SIGNAL ;
    PORT
      LAYER M4 ;
        RECT  69.036 18.096 69.12 18.12 ;
    END
  END r_d[340]
  PIN r_d[341]
    DIRECTION OUTPUT ;
    USE SIGNAL ;
    PORT
      LAYER M4 ;
        RECT  69.036 18.192 69.12 18.216 ;
    END
  END r_d[341]
  PIN r_d[342]
    DIRECTION OUTPUT ;
    USE SIGNAL ;
    PORT
      LAYER M4 ;
        RECT  69.036 18.288 69.12 18.312 ;
    END
  END r_d[342]
  PIN r_d[343]
    DIRECTION OUTPUT ;
    USE SIGNAL ;
    PORT
      LAYER M4 ;
        RECT  69.036 18.384 69.12 18.408 ;
    END
  END r_d[343]
  PIN r_d[344]
    DIRECTION OUTPUT ;
    USE SIGNAL ;
    PORT
      LAYER M4 ;
        RECT  69.036 18.48 69.12 18.504 ;
    END
  END r_d[344]
  PIN r_d[345]
    DIRECTION OUTPUT ;
    USE SIGNAL ;
    PORT
      LAYER M4 ;
        RECT  69.036 18.576 69.12 18.6 ;
    END
  END r_d[345]
  PIN r_d[346]
    DIRECTION OUTPUT ;
    USE SIGNAL ;
    PORT
      LAYER M4 ;
        RECT  69.036 18.672 69.12 18.696 ;
    END
  END r_d[346]
  PIN r_d[347]
    DIRECTION OUTPUT ;
    USE SIGNAL ;
    PORT
      LAYER M4 ;
        RECT  69.036 18.768 69.12 18.792 ;
    END
  END r_d[347]
  PIN r_d[348]
    DIRECTION OUTPUT ;
    USE SIGNAL ;
    PORT
      LAYER M4 ;
        RECT  69.036 18.864 69.12 18.888 ;
    END
  END r_d[348]
  PIN r_d[349]
    DIRECTION OUTPUT ;
    USE SIGNAL ;
    PORT
      LAYER M4 ;
        RECT  69.036 18.96 69.12 18.984 ;
    END
  END r_d[349]
  PIN r_d[34]
    DIRECTION OUTPUT ;
    USE SIGNAL ;
    PORT
      LAYER M4 ;
        RECT  69.036 70.896 69.12 70.92 ;
    END
  END r_d[34]
  PIN r_d[350]
    DIRECTION OUTPUT ;
    USE SIGNAL ;
    PORT
      LAYER M4 ;
        RECT  69.036 19.056 69.12 19.08 ;
    END
  END r_d[350]
  PIN r_d[351]
    DIRECTION OUTPUT ;
    USE SIGNAL ;
    PORT
      LAYER M4 ;
        RECT  69.036 6.864 69.12 6.888 ;
    END
  END r_d[351]
  PIN r_d[352]
    DIRECTION OUTPUT ;
    USE SIGNAL ;
    PORT
      LAYER M4 ;
        RECT  69.036 6.96 69.12 6.984 ;
    END
  END r_d[352]
  PIN r_d[353]
    DIRECTION OUTPUT ;
    USE SIGNAL ;
    PORT
      LAYER M4 ;
        RECT  69.036 7.056 69.12 7.08 ;
    END
  END r_d[353]
  PIN r_d[354]
    DIRECTION OUTPUT ;
    USE SIGNAL ;
    PORT
      LAYER M4 ;
        RECT  69.036 7.152 69.12 7.176 ;
    END
  END r_d[354]
  PIN r_d[355]
    DIRECTION OUTPUT ;
    USE SIGNAL ;
    PORT
      LAYER M4 ;
        RECT  69.036 7.248 69.12 7.272 ;
    END
  END r_d[355]
  PIN r_d[356]
    DIRECTION OUTPUT ;
    USE SIGNAL ;
    PORT
      LAYER M4 ;
        RECT  69.036 7.344 69.12 7.368 ;
    END
  END r_d[356]
  PIN r_d[357]
    DIRECTION OUTPUT ;
    USE SIGNAL ;
    PORT
      LAYER M4 ;
        RECT  69.036 7.44 69.12 7.464 ;
    END
  END r_d[357]
  PIN r_d[358]
    DIRECTION OUTPUT ;
    USE SIGNAL ;
    PORT
      LAYER M4 ;
        RECT  69.036 7.536 69.12 7.56 ;
    END
  END r_d[358]
  PIN r_d[359]
    DIRECTION OUTPUT ;
    USE SIGNAL ;
    PORT
      LAYER M4 ;
        RECT  69.036 7.632 69.12 7.656 ;
    END
  END r_d[359]
  PIN r_d[35]
    DIRECTION OUTPUT ;
    USE SIGNAL ;
    PORT
      LAYER M4 ;
        RECT  69.036 70.992 69.12 71.016 ;
    END
  END r_d[35]
  PIN r_d[360]
    DIRECTION OUTPUT ;
    USE SIGNAL ;
    PORT
      LAYER M4 ;
        RECT  69.036 7.728 69.12 7.752 ;
    END
  END r_d[360]
  PIN r_d[361]
    DIRECTION OUTPUT ;
    USE SIGNAL ;
    PORT
      LAYER M4 ;
        RECT  69.036 7.824 69.12 7.848 ;
    END
  END r_d[361]
  PIN r_d[362]
    DIRECTION OUTPUT ;
    USE SIGNAL ;
    PORT
      LAYER M4 ;
        RECT  69.036 7.92 69.12 7.944 ;
    END
  END r_d[362]
  PIN r_d[363]
    DIRECTION OUTPUT ;
    USE SIGNAL ;
    PORT
      LAYER M4 ;
        RECT  69.036 8.016 69.12 8.04 ;
    END
  END r_d[363]
  PIN r_d[364]
    DIRECTION OUTPUT ;
    USE SIGNAL ;
    PORT
      LAYER M4 ;
        RECT  69.036 8.112 69.12 8.136 ;
    END
  END r_d[364]
  PIN r_d[365]
    DIRECTION OUTPUT ;
    USE SIGNAL ;
    PORT
      LAYER M4 ;
        RECT  69.036 8.208 69.12 8.232 ;
    END
  END r_d[365]
  PIN r_d[366]
    DIRECTION OUTPUT ;
    USE SIGNAL ;
    PORT
      LAYER M4 ;
        RECT  69.036 8.304 69.12 8.328 ;
    END
  END r_d[366]
  PIN r_d[367]
    DIRECTION OUTPUT ;
    USE SIGNAL ;
    PORT
      LAYER M4 ;
        RECT  69.036 8.4 69.12 8.424 ;
    END
  END r_d[367]
  PIN r_d[368]
    DIRECTION OUTPUT ;
    USE SIGNAL ;
    PORT
      LAYER M4 ;
        RECT  69.036 8.496 69.12 8.52 ;
    END
  END r_d[368]
  PIN r_d[369]
    DIRECTION OUTPUT ;
    USE SIGNAL ;
    PORT
      LAYER M4 ;
        RECT  69.036 8.592 69.12 8.616 ;
    END
  END r_d[369]
  PIN r_d[36]
    DIRECTION OUTPUT ;
    USE SIGNAL ;
    PORT
      LAYER M4 ;
        RECT  69.036 71.088 69.12 71.112 ;
    END
  END r_d[36]
  PIN r_d[370]
    DIRECTION OUTPUT ;
    USE SIGNAL ;
    PORT
      LAYER M4 ;
        RECT  69.036 8.688 69.12 8.712 ;
    END
  END r_d[370]
  PIN r_d[371]
    DIRECTION OUTPUT ;
    USE SIGNAL ;
    PORT
      LAYER M4 ;
        RECT  69.036 8.784 69.12 8.808 ;
    END
  END r_d[371]
  PIN r_d[372]
    DIRECTION OUTPUT ;
    USE SIGNAL ;
    PORT
      LAYER M4 ;
        RECT  69.036 8.88 69.12 8.904 ;
    END
  END r_d[372]
  PIN r_d[373]
    DIRECTION OUTPUT ;
    USE SIGNAL ;
    PORT
      LAYER M4 ;
        RECT  69.036 8.976 69.12 9 ;
    END
  END r_d[373]
  PIN r_d[374]
    DIRECTION OUTPUT ;
    USE SIGNAL ;
    PORT
      LAYER M4 ;
        RECT  69.036 9.072 69.12 9.096 ;
    END
  END r_d[374]
  PIN r_d[375]
    DIRECTION OUTPUT ;
    USE SIGNAL ;
    PORT
      LAYER M4 ;
        RECT  69.036 9.168 69.12 9.192 ;
    END
  END r_d[375]
  PIN r_d[376]
    DIRECTION OUTPUT ;
    USE SIGNAL ;
    PORT
      LAYER M4 ;
        RECT  69.036 9.264 69.12 9.288 ;
    END
  END r_d[376]
  PIN r_d[377]
    DIRECTION OUTPUT ;
    USE SIGNAL ;
    PORT
      LAYER M4 ;
        RECT  69.036 9.36 69.12 9.384 ;
    END
  END r_d[377]
  PIN r_d[378]
    DIRECTION OUTPUT ;
    USE SIGNAL ;
    PORT
      LAYER M4 ;
        RECT  69.036 9.456 69.12 9.48 ;
    END
  END r_d[378]
  PIN r_d[379]
    DIRECTION OUTPUT ;
    USE SIGNAL ;
    PORT
      LAYER M4 ;
        RECT  69.036 9.552 69.12 9.576 ;
    END
  END r_d[379]
  PIN r_d[37]
    DIRECTION OUTPUT ;
    USE SIGNAL ;
    PORT
      LAYER M4 ;
        RECT  69.036 71.184 69.12 71.208 ;
    END
  END r_d[37]
  PIN r_d[380]
    DIRECTION OUTPUT ;
    USE SIGNAL ;
    PORT
      LAYER M4 ;
        RECT  69.036 9.648 69.12 9.672 ;
    END
  END r_d[380]
  PIN r_d[381]
    DIRECTION OUTPUT ;
    USE SIGNAL ;
    PORT
      LAYER M4 ;
        RECT  69.036 9.744 69.12 9.768 ;
    END
  END r_d[381]
  PIN r_d[382]
    DIRECTION OUTPUT ;
    USE SIGNAL ;
    PORT
      LAYER M4 ;
        RECT  69.036 9.84 69.12 9.864 ;
    END
  END r_d[382]
  PIN r_d[383]
    DIRECTION OUTPUT ;
    USE SIGNAL ;
    PORT
      LAYER M4 ;
        RECT  69.036 13.008 69.12 13.032 ;
    END
  END r_d[383]
  PIN r_d[384]
    DIRECTION OUTPUT ;
    USE SIGNAL ;
    PORT
      LAYER M4 ;
        RECT  69.036 13.104 69.12 13.128 ;
    END
  END r_d[384]
  PIN r_d[385]
    DIRECTION OUTPUT ;
    USE SIGNAL ;
    PORT
      LAYER M4 ;
        RECT  69.036 13.2 69.12 13.224 ;
    END
  END r_d[385]
  PIN r_d[386]
    DIRECTION OUTPUT ;
    USE SIGNAL ;
    PORT
      LAYER M4 ;
        RECT  69.036 13.296 69.12 13.32 ;
    END
  END r_d[386]
  PIN r_d[387]
    DIRECTION OUTPUT ;
    USE SIGNAL ;
    PORT
      LAYER M4 ;
        RECT  69.036 13.392 69.12 13.416 ;
    END
  END r_d[387]
  PIN r_d[388]
    DIRECTION OUTPUT ;
    USE SIGNAL ;
    PORT
      LAYER M4 ;
        RECT  69.036 13.488 69.12 13.512 ;
    END
  END r_d[388]
  PIN r_d[389]
    DIRECTION OUTPUT ;
    USE SIGNAL ;
    PORT
      LAYER M4 ;
        RECT  69.036 13.584 69.12 13.608 ;
    END
  END r_d[389]
  PIN r_d[38]
    DIRECTION OUTPUT ;
    USE SIGNAL ;
    PORT
      LAYER M4 ;
        RECT  69.036 71.28 69.12 71.304 ;
    END
  END r_d[38]
  PIN r_d[390]
    DIRECTION OUTPUT ;
    USE SIGNAL ;
    PORT
      LAYER M4 ;
        RECT  69.036 13.68 69.12 13.704 ;
    END
  END r_d[390]
  PIN r_d[391]
    DIRECTION OUTPUT ;
    USE SIGNAL ;
    PORT
      LAYER M4 ;
        RECT  69.036 13.776 69.12 13.8 ;
    END
  END r_d[391]
  PIN r_d[392]
    DIRECTION OUTPUT ;
    USE SIGNAL ;
    PORT
      LAYER M4 ;
        RECT  69.036 13.872 69.12 13.896 ;
    END
  END r_d[392]
  PIN r_d[393]
    DIRECTION OUTPUT ;
    USE SIGNAL ;
    PORT
      LAYER M4 ;
        RECT  69.036 13.968 69.12 13.992 ;
    END
  END r_d[393]
  PIN r_d[394]
    DIRECTION OUTPUT ;
    USE SIGNAL ;
    PORT
      LAYER M4 ;
        RECT  69.036 14.064 69.12 14.088 ;
    END
  END r_d[394]
  PIN r_d[395]
    DIRECTION OUTPUT ;
    USE SIGNAL ;
    PORT
      LAYER M4 ;
        RECT  69.036 14.16 69.12 14.184 ;
    END
  END r_d[395]
  PIN r_d[396]
    DIRECTION OUTPUT ;
    USE SIGNAL ;
    PORT
      LAYER M4 ;
        RECT  69.036 14.256 69.12 14.28 ;
    END
  END r_d[396]
  PIN r_d[397]
    DIRECTION OUTPUT ;
    USE SIGNAL ;
    PORT
      LAYER M4 ;
        RECT  69.036 14.352 69.12 14.376 ;
    END
  END r_d[397]
  PIN r_d[398]
    DIRECTION OUTPUT ;
    USE SIGNAL ;
    PORT
      LAYER M4 ;
        RECT  69.036 14.448 69.12 14.472 ;
    END
  END r_d[398]
  PIN r_d[399]
    DIRECTION OUTPUT ;
    USE SIGNAL ;
    PORT
      LAYER M4 ;
        RECT  69.036 14.544 69.12 14.568 ;
    END
  END r_d[399]
  PIN r_d[39]
    DIRECTION OUTPUT ;
    USE SIGNAL ;
    PORT
      LAYER M4 ;
        RECT  69.036 71.376 69.12 71.4 ;
    END
  END r_d[39]
  PIN r_d[3]
    DIRECTION OUTPUT ;
    USE SIGNAL ;
    PORT
      LAYER M4 ;
        RECT  69.036 80.976 69.12 81 ;
    END
  END r_d[3]
  PIN r_d[400]
    DIRECTION OUTPUT ;
    USE SIGNAL ;
    PORT
      LAYER M4 ;
        RECT  69.036 14.64 69.12 14.664 ;
    END
  END r_d[400]
  PIN r_d[401]
    DIRECTION OUTPUT ;
    USE SIGNAL ;
    PORT
      LAYER M4 ;
        RECT  69.036 14.736 69.12 14.76 ;
    END
  END r_d[401]
  PIN r_d[402]
    DIRECTION OUTPUT ;
    USE SIGNAL ;
    PORT
      LAYER M4 ;
        RECT  69.036 14.832 69.12 14.856 ;
    END
  END r_d[402]
  PIN r_d[403]
    DIRECTION OUTPUT ;
    USE SIGNAL ;
    PORT
      LAYER M4 ;
        RECT  69.036 14.928 69.12 14.952 ;
    END
  END r_d[403]
  PIN r_d[404]
    DIRECTION OUTPUT ;
    USE SIGNAL ;
    PORT
      LAYER M4 ;
        RECT  69.036 15.024 69.12 15.048 ;
    END
  END r_d[404]
  PIN r_d[405]
    DIRECTION OUTPUT ;
    USE SIGNAL ;
    PORT
      LAYER M4 ;
        RECT  69.036 15.12 69.12 15.144 ;
    END
  END r_d[405]
  PIN r_d[406]
    DIRECTION OUTPUT ;
    USE SIGNAL ;
    PORT
      LAYER M4 ;
        RECT  69.036 15.216 69.12 15.24 ;
    END
  END r_d[406]
  PIN r_d[407]
    DIRECTION OUTPUT ;
    USE SIGNAL ;
    PORT
      LAYER M4 ;
        RECT  69.036 15.312 69.12 15.336 ;
    END
  END r_d[407]
  PIN r_d[408]
    DIRECTION OUTPUT ;
    USE SIGNAL ;
    PORT
      LAYER M4 ;
        RECT  69.036 15.408 69.12 15.432 ;
    END
  END r_d[408]
  PIN r_d[409]
    DIRECTION OUTPUT ;
    USE SIGNAL ;
    PORT
      LAYER M4 ;
        RECT  69.036 15.504 69.12 15.528 ;
    END
  END r_d[409]
  PIN r_d[40]
    DIRECTION OUTPUT ;
    USE SIGNAL ;
    PORT
      LAYER M4 ;
        RECT  69.036 71.472 69.12 71.496 ;
    END
  END r_d[40]
  PIN r_d[410]
    DIRECTION OUTPUT ;
    USE SIGNAL ;
    PORT
      LAYER M4 ;
        RECT  69.036 15.6 69.12 15.624 ;
    END
  END r_d[410]
  PIN r_d[411]
    DIRECTION OUTPUT ;
    USE SIGNAL ;
    PORT
      LAYER M4 ;
        RECT  69.036 15.696 69.12 15.72 ;
    END
  END r_d[411]
  PIN r_d[412]
    DIRECTION OUTPUT ;
    USE SIGNAL ;
    PORT
      LAYER M4 ;
        RECT  69.036 15.792 69.12 15.816 ;
    END
  END r_d[412]
  PIN r_d[413]
    DIRECTION OUTPUT ;
    USE SIGNAL ;
    PORT
      LAYER M4 ;
        RECT  69.036 15.888 69.12 15.912 ;
    END
  END r_d[413]
  PIN r_d[414]
    DIRECTION OUTPUT ;
    USE SIGNAL ;
    PORT
      LAYER M4 ;
        RECT  69.036 15.984 69.12 16.008 ;
    END
  END r_d[414]
  PIN r_d[415]
    DIRECTION OUTPUT ;
    USE SIGNAL ;
    PORT
      LAYER M4 ;
        RECT  69.036 9.936 69.12 9.96 ;
    END
  END r_d[415]
  PIN r_d[416]
    DIRECTION OUTPUT ;
    USE SIGNAL ;
    PORT
      LAYER M4 ;
        RECT  69.036 10.032 69.12 10.056 ;
    END
  END r_d[416]
  PIN r_d[417]
    DIRECTION OUTPUT ;
    USE SIGNAL ;
    PORT
      LAYER M4 ;
        RECT  69.036 10.128 69.12 10.152 ;
    END
  END r_d[417]
  PIN r_d[418]
    DIRECTION OUTPUT ;
    USE SIGNAL ;
    PORT
      LAYER M4 ;
        RECT  69.036 10.224 69.12 10.248 ;
    END
  END r_d[418]
  PIN r_d[419]
    DIRECTION OUTPUT ;
    USE SIGNAL ;
    PORT
      LAYER M4 ;
        RECT  69.036 10.32 69.12 10.344 ;
    END
  END r_d[419]
  PIN r_d[41]
    DIRECTION OUTPUT ;
    USE SIGNAL ;
    PORT
      LAYER M4 ;
        RECT  69.036 71.568 69.12 71.592 ;
    END
  END r_d[41]
  PIN r_d[420]
    DIRECTION OUTPUT ;
    USE SIGNAL ;
    PORT
      LAYER M4 ;
        RECT  69.036 10.416 69.12 10.44 ;
    END
  END r_d[420]
  PIN r_d[421]
    DIRECTION OUTPUT ;
    USE SIGNAL ;
    PORT
      LAYER M4 ;
        RECT  69.036 10.512 69.12 10.536 ;
    END
  END r_d[421]
  PIN r_d[422]
    DIRECTION OUTPUT ;
    USE SIGNAL ;
    PORT
      LAYER M4 ;
        RECT  69.036 10.608 69.12 10.632 ;
    END
  END r_d[422]
  PIN r_d[423]
    DIRECTION OUTPUT ;
    USE SIGNAL ;
    PORT
      LAYER M4 ;
        RECT  69.036 10.704 69.12 10.728 ;
    END
  END r_d[423]
  PIN r_d[424]
    DIRECTION OUTPUT ;
    USE SIGNAL ;
    PORT
      LAYER M4 ;
        RECT  69.036 10.8 69.12 10.824 ;
    END
  END r_d[424]
  PIN r_d[425]
    DIRECTION OUTPUT ;
    USE SIGNAL ;
    PORT
      LAYER M4 ;
        RECT  69.036 10.896 69.12 10.92 ;
    END
  END r_d[425]
  PIN r_d[426]
    DIRECTION OUTPUT ;
    USE SIGNAL ;
    PORT
      LAYER M4 ;
        RECT  69.036 10.992 69.12 11.016 ;
    END
  END r_d[426]
  PIN r_d[427]
    DIRECTION OUTPUT ;
    USE SIGNAL ;
    PORT
      LAYER M4 ;
        RECT  69.036 11.088 69.12 11.112 ;
    END
  END r_d[427]
  PIN r_d[428]
    DIRECTION OUTPUT ;
    USE SIGNAL ;
    PORT
      LAYER M4 ;
        RECT  69.036 11.184 69.12 11.208 ;
    END
  END r_d[428]
  PIN r_d[429]
    DIRECTION OUTPUT ;
    USE SIGNAL ;
    PORT
      LAYER M4 ;
        RECT  69.036 11.28 69.12 11.304 ;
    END
  END r_d[429]
  PIN r_d[42]
    DIRECTION OUTPUT ;
    USE SIGNAL ;
    PORT
      LAYER M4 ;
        RECT  69.036 71.664 69.12 71.688 ;
    END
  END r_d[42]
  PIN r_d[430]
    DIRECTION OUTPUT ;
    USE SIGNAL ;
    PORT
      LAYER M4 ;
        RECT  69.036 11.376 69.12 11.4 ;
    END
  END r_d[430]
  PIN r_d[431]
    DIRECTION OUTPUT ;
    USE SIGNAL ;
    PORT
      LAYER M4 ;
        RECT  69.036 11.472 69.12 11.496 ;
    END
  END r_d[431]
  PIN r_d[432]
    DIRECTION OUTPUT ;
    USE SIGNAL ;
    PORT
      LAYER M4 ;
        RECT  69.036 11.568 69.12 11.592 ;
    END
  END r_d[432]
  PIN r_d[433]
    DIRECTION OUTPUT ;
    USE SIGNAL ;
    PORT
      LAYER M4 ;
        RECT  69.036 11.664 69.12 11.688 ;
    END
  END r_d[433]
  PIN r_d[434]
    DIRECTION OUTPUT ;
    USE SIGNAL ;
    PORT
      LAYER M4 ;
        RECT  69.036 11.76 69.12 11.784 ;
    END
  END r_d[434]
  PIN r_d[435]
    DIRECTION OUTPUT ;
    USE SIGNAL ;
    PORT
      LAYER M4 ;
        RECT  69.036 11.856 69.12 11.88 ;
    END
  END r_d[435]
  PIN r_d[436]
    DIRECTION OUTPUT ;
    USE SIGNAL ;
    PORT
      LAYER M4 ;
        RECT  69.036 11.952 69.12 11.976 ;
    END
  END r_d[436]
  PIN r_d[437]
    DIRECTION OUTPUT ;
    USE SIGNAL ;
    PORT
      LAYER M4 ;
        RECT  69.036 12.048 69.12 12.072 ;
    END
  END r_d[437]
  PIN r_d[438]
    DIRECTION OUTPUT ;
    USE SIGNAL ;
    PORT
      LAYER M4 ;
        RECT  69.036 12.144 69.12 12.168 ;
    END
  END r_d[438]
  PIN r_d[439]
    DIRECTION OUTPUT ;
    USE SIGNAL ;
    PORT
      LAYER M4 ;
        RECT  69.036 12.24 69.12 12.264 ;
    END
  END r_d[439]
  PIN r_d[43]
    DIRECTION OUTPUT ;
    USE SIGNAL ;
    PORT
      LAYER M4 ;
        RECT  69.036 71.76 69.12 71.784 ;
    END
  END r_d[43]
  PIN r_d[440]
    DIRECTION OUTPUT ;
    USE SIGNAL ;
    PORT
      LAYER M4 ;
        RECT  69.036 12.336 69.12 12.36 ;
    END
  END r_d[440]
  PIN r_d[441]
    DIRECTION OUTPUT ;
    USE SIGNAL ;
    PORT
      LAYER M4 ;
        RECT  69.036 12.432 69.12 12.456 ;
    END
  END r_d[441]
  PIN r_d[442]
    DIRECTION OUTPUT ;
    USE SIGNAL ;
    PORT
      LAYER M4 ;
        RECT  69.036 12.528 69.12 12.552 ;
    END
  END r_d[442]
  PIN r_d[443]
    DIRECTION OUTPUT ;
    USE SIGNAL ;
    PORT
      LAYER M4 ;
        RECT  69.036 12.624 69.12 12.648 ;
    END
  END r_d[443]
  PIN r_d[444]
    DIRECTION OUTPUT ;
    USE SIGNAL ;
    PORT
      LAYER M4 ;
        RECT  69.036 12.72 69.12 12.744 ;
    END
  END r_d[444]
  PIN r_d[445]
    DIRECTION OUTPUT ;
    USE SIGNAL ;
    PORT
      LAYER M4 ;
        RECT  69.036 12.816 69.12 12.84 ;
    END
  END r_d[445]
  PIN r_d[446]
    DIRECTION OUTPUT ;
    USE SIGNAL ;
    PORT
      LAYER M4 ;
        RECT  69.036 12.912 69.12 12.936 ;
    END
  END r_d[446]
  PIN r_d[447]
    DIRECTION OUTPUT ;
    USE SIGNAL ;
    PORT
      LAYER M4 ;
        RECT  69.036 3.792 69.12 3.816 ;
    END
  END r_d[447]
  PIN r_d[448]
    DIRECTION OUTPUT ;
    USE SIGNAL ;
    PORT
      LAYER M4 ;
        RECT  69.036 3.888 69.12 3.912 ;
    END
  END r_d[448]
  PIN r_d[449]
    DIRECTION OUTPUT ;
    USE SIGNAL ;
    PORT
      LAYER M4 ;
        RECT  69.036 3.984 69.12 4.008 ;
    END
  END r_d[449]
  PIN r_d[44]
    DIRECTION OUTPUT ;
    USE SIGNAL ;
    PORT
      LAYER M4 ;
        RECT  69.036 71.856 69.12 71.88 ;
    END
  END r_d[44]
  PIN r_d[450]
    DIRECTION OUTPUT ;
    USE SIGNAL ;
    PORT
      LAYER M4 ;
        RECT  69.036 4.08 69.12 4.104 ;
    END
  END r_d[450]
  PIN r_d[451]
    DIRECTION OUTPUT ;
    USE SIGNAL ;
    PORT
      LAYER M4 ;
        RECT  69.036 4.176 69.12 4.2 ;
    END
  END r_d[451]
  PIN r_d[452]
    DIRECTION OUTPUT ;
    USE SIGNAL ;
    PORT
      LAYER M4 ;
        RECT  69.036 4.272 69.12 4.296 ;
    END
  END r_d[452]
  PIN r_d[453]
    DIRECTION OUTPUT ;
    USE SIGNAL ;
    PORT
      LAYER M4 ;
        RECT  69.036 4.368 69.12 4.392 ;
    END
  END r_d[453]
  PIN r_d[454]
    DIRECTION OUTPUT ;
    USE SIGNAL ;
    PORT
      LAYER M4 ;
        RECT  69.036 4.464 69.12 4.488 ;
    END
  END r_d[454]
  PIN r_d[455]
    DIRECTION OUTPUT ;
    USE SIGNAL ;
    PORT
      LAYER M4 ;
        RECT  69.036 4.56 69.12 4.584 ;
    END
  END r_d[455]
  PIN r_d[456]
    DIRECTION OUTPUT ;
    USE SIGNAL ;
    PORT
      LAYER M4 ;
        RECT  69.036 4.656 69.12 4.68 ;
    END
  END r_d[456]
  PIN r_d[457]
    DIRECTION OUTPUT ;
    USE SIGNAL ;
    PORT
      LAYER M4 ;
        RECT  69.036 4.752 69.12 4.776 ;
    END
  END r_d[457]
  PIN r_d[458]
    DIRECTION OUTPUT ;
    USE SIGNAL ;
    PORT
      LAYER M4 ;
        RECT  69.036 4.848 69.12 4.872 ;
    END
  END r_d[458]
  PIN r_d[459]
    DIRECTION OUTPUT ;
    USE SIGNAL ;
    PORT
      LAYER M4 ;
        RECT  69.036 4.944 69.12 4.968 ;
    END
  END r_d[459]
  PIN r_d[45]
    DIRECTION OUTPUT ;
    USE SIGNAL ;
    PORT
      LAYER M4 ;
        RECT  69.036 71.952 69.12 71.976 ;
    END
  END r_d[45]
  PIN r_d[460]
    DIRECTION OUTPUT ;
    USE SIGNAL ;
    PORT
      LAYER M4 ;
        RECT  69.036 5.04 69.12 5.064 ;
    END
  END r_d[460]
  PIN r_d[461]
    DIRECTION OUTPUT ;
    USE SIGNAL ;
    PORT
      LAYER M4 ;
        RECT  69.036 5.136 69.12 5.16 ;
    END
  END r_d[461]
  PIN r_d[462]
    DIRECTION OUTPUT ;
    USE SIGNAL ;
    PORT
      LAYER M4 ;
        RECT  69.036 5.232 69.12 5.256 ;
    END
  END r_d[462]
  PIN r_d[463]
    DIRECTION OUTPUT ;
    USE SIGNAL ;
    PORT
      LAYER M4 ;
        RECT  69.036 5.328 69.12 5.352 ;
    END
  END r_d[463]
  PIN r_d[464]
    DIRECTION OUTPUT ;
    USE SIGNAL ;
    PORT
      LAYER M4 ;
        RECT  69.036 5.424 69.12 5.448 ;
    END
  END r_d[464]
  PIN r_d[465]
    DIRECTION OUTPUT ;
    USE SIGNAL ;
    PORT
      LAYER M4 ;
        RECT  69.036 5.52 69.12 5.544 ;
    END
  END r_d[465]
  PIN r_d[466]
    DIRECTION OUTPUT ;
    USE SIGNAL ;
    PORT
      LAYER M4 ;
        RECT  69.036 5.616 69.12 5.64 ;
    END
  END r_d[466]
  PIN r_d[467]
    DIRECTION OUTPUT ;
    USE SIGNAL ;
    PORT
      LAYER M4 ;
        RECT  69.036 5.712 69.12 5.736 ;
    END
  END r_d[467]
  PIN r_d[468]
    DIRECTION OUTPUT ;
    USE SIGNAL ;
    PORT
      LAYER M4 ;
        RECT  69.036 5.808 69.12 5.832 ;
    END
  END r_d[468]
  PIN r_d[469]
    DIRECTION OUTPUT ;
    USE SIGNAL ;
    PORT
      LAYER M4 ;
        RECT  69.036 5.904 69.12 5.928 ;
    END
  END r_d[469]
  PIN r_d[46]
    DIRECTION OUTPUT ;
    USE SIGNAL ;
    PORT
      LAYER M4 ;
        RECT  69.036 72.048 69.12 72.072 ;
    END
  END r_d[46]
  PIN r_d[470]
    DIRECTION OUTPUT ;
    USE SIGNAL ;
    PORT
      LAYER M4 ;
        RECT  69.036 6 69.12 6.024 ;
    END
  END r_d[470]
  PIN r_d[471]
    DIRECTION OUTPUT ;
    USE SIGNAL ;
    PORT
      LAYER M4 ;
        RECT  69.036 6.096 69.12 6.12 ;
    END
  END r_d[471]
  PIN r_d[472]
    DIRECTION OUTPUT ;
    USE SIGNAL ;
    PORT
      LAYER M4 ;
        RECT  69.036 6.192 69.12 6.216 ;
    END
  END r_d[472]
  PIN r_d[473]
    DIRECTION OUTPUT ;
    USE SIGNAL ;
    PORT
      LAYER M4 ;
        RECT  69.036 6.288 69.12 6.312 ;
    END
  END r_d[473]
  PIN r_d[474]
    DIRECTION OUTPUT ;
    USE SIGNAL ;
    PORT
      LAYER M4 ;
        RECT  69.036 6.384 69.12 6.408 ;
    END
  END r_d[474]
  PIN r_d[475]
    DIRECTION OUTPUT ;
    USE SIGNAL ;
    PORT
      LAYER M4 ;
        RECT  69.036 6.48 69.12 6.504 ;
    END
  END r_d[475]
  PIN r_d[476]
    DIRECTION OUTPUT ;
    USE SIGNAL ;
    PORT
      LAYER M4 ;
        RECT  69.036 6.576 69.12 6.6 ;
    END
  END r_d[476]
  PIN r_d[477]
    DIRECTION OUTPUT ;
    USE SIGNAL ;
    PORT
      LAYER M4 ;
        RECT  69.036 6.672 69.12 6.696 ;
    END
  END r_d[477]
  PIN r_d[478]
    DIRECTION OUTPUT ;
    USE SIGNAL ;
    PORT
      LAYER M4 ;
        RECT  69.036 6.768 69.12 6.792 ;
    END
  END r_d[478]
  PIN r_d[479]
    DIRECTION OUTPUT ;
    USE SIGNAL ;
    PORT
      LAYER M4 ;
        RECT  69.036 29.136 69.12 29.16 ;
    END
  END r_d[479]
  PIN r_d[47]
    DIRECTION OUTPUT ;
    USE SIGNAL ;
    PORT
      LAYER M4 ;
        RECT  69.036 72.144 69.12 72.168 ;
    END
  END r_d[47]
  PIN r_d[480]
    DIRECTION OUTPUT ;
    USE SIGNAL ;
    PORT
      LAYER M4 ;
        RECT  69.036 29.232 69.12 29.256 ;
    END
  END r_d[480]
  PIN r_d[481]
    DIRECTION OUTPUT ;
    USE SIGNAL ;
    PORT
      LAYER M4 ;
        RECT  69.036 29.328 69.12 29.352 ;
    END
  END r_d[481]
  PIN r_d[482]
    DIRECTION OUTPUT ;
    USE SIGNAL ;
    PORT
      LAYER M4 ;
        RECT  69.036 29.424 69.12 29.448 ;
    END
  END r_d[482]
  PIN r_d[483]
    DIRECTION OUTPUT ;
    USE SIGNAL ;
    PORT
      LAYER M4 ;
        RECT  69.036 29.52 69.12 29.544 ;
    END
  END r_d[483]
  PIN r_d[484]
    DIRECTION OUTPUT ;
    USE SIGNAL ;
    PORT
      LAYER M4 ;
        RECT  69.036 29.616 69.12 29.64 ;
    END
  END r_d[484]
  PIN r_d[485]
    DIRECTION OUTPUT ;
    USE SIGNAL ;
    PORT
      LAYER M4 ;
        RECT  69.036 29.712 69.12 29.736 ;
    END
  END r_d[485]
  PIN r_d[486]
    DIRECTION OUTPUT ;
    USE SIGNAL ;
    PORT
      LAYER M4 ;
        RECT  69.036 29.808 69.12 29.832 ;
    END
  END r_d[486]
  PIN r_d[487]
    DIRECTION OUTPUT ;
    USE SIGNAL ;
    PORT
      LAYER M4 ;
        RECT  69.036 29.904 69.12 29.928 ;
    END
  END r_d[487]
  PIN r_d[488]
    DIRECTION OUTPUT ;
    USE SIGNAL ;
    PORT
      LAYER M4 ;
        RECT  69.036 30 69.12 30.024 ;
    END
  END r_d[488]
  PIN r_d[489]
    DIRECTION OUTPUT ;
    USE SIGNAL ;
    PORT
      LAYER M4 ;
        RECT  69.036 30.096 69.12 30.12 ;
    END
  END r_d[489]
  PIN r_d[48]
    DIRECTION OUTPUT ;
    USE SIGNAL ;
    PORT
      LAYER M4 ;
        RECT  69.036 72.24 69.12 72.264 ;
    END
  END r_d[48]
  PIN r_d[490]
    DIRECTION OUTPUT ;
    USE SIGNAL ;
    PORT
      LAYER M4 ;
        RECT  69.036 30.192 69.12 30.216 ;
    END
  END r_d[490]
  PIN r_d[491]
    DIRECTION OUTPUT ;
    USE SIGNAL ;
    PORT
      LAYER M4 ;
        RECT  69.036 30.288 69.12 30.312 ;
    END
  END r_d[491]
  PIN r_d[492]
    DIRECTION OUTPUT ;
    USE SIGNAL ;
    PORT
      LAYER M4 ;
        RECT  69.036 30.384 69.12 30.408 ;
    END
  END r_d[492]
  PIN r_d[493]
    DIRECTION OUTPUT ;
    USE SIGNAL ;
    PORT
      LAYER M4 ;
        RECT  69.036 30.48 69.12 30.504 ;
    END
  END r_d[493]
  PIN r_d[494]
    DIRECTION OUTPUT ;
    USE SIGNAL ;
    PORT
      LAYER M4 ;
        RECT  69.036 30.576 69.12 30.6 ;
    END
  END r_d[494]
  PIN r_d[495]
    DIRECTION OUTPUT ;
    USE SIGNAL ;
    PORT
      LAYER M4 ;
        RECT  69.036 30.672 69.12 30.696 ;
    END
  END r_d[495]
  PIN r_d[496]
    DIRECTION OUTPUT ;
    USE SIGNAL ;
    PORT
      LAYER M4 ;
        RECT  69.036 30.768 69.12 30.792 ;
    END
  END r_d[496]
  PIN r_d[497]
    DIRECTION OUTPUT ;
    USE SIGNAL ;
    PORT
      LAYER M4 ;
        RECT  69.036 30.864 69.12 30.888 ;
    END
  END r_d[497]
  PIN r_d[498]
    DIRECTION OUTPUT ;
    USE SIGNAL ;
    PORT
      LAYER M4 ;
        RECT  69.036 30.96 69.12 30.984 ;
    END
  END r_d[498]
  PIN r_d[499]
    DIRECTION OUTPUT ;
    USE SIGNAL ;
    PORT
      LAYER M4 ;
        RECT  69.036 31.056 69.12 31.08 ;
    END
  END r_d[499]
  PIN r_d[49]
    DIRECTION OUTPUT ;
    USE SIGNAL ;
    PORT
      LAYER M4 ;
        RECT  69.036 72.336 69.12 72.36 ;
    END
  END r_d[49]
  PIN r_d[4]
    DIRECTION OUTPUT ;
    USE SIGNAL ;
    PORT
      LAYER M4 ;
        RECT  69.036 81.072 69.12 81.096 ;
    END
  END r_d[4]
  PIN r_d[500]
    DIRECTION OUTPUT ;
    USE SIGNAL ;
    PORT
      LAYER M4 ;
        RECT  69.036 31.152 69.12 31.176 ;
    END
  END r_d[500]
  PIN r_d[501]
    DIRECTION OUTPUT ;
    USE SIGNAL ;
    PORT
      LAYER M4 ;
        RECT  69.036 31.248 69.12 31.272 ;
    END
  END r_d[501]
  PIN r_d[502]
    DIRECTION OUTPUT ;
    USE SIGNAL ;
    PORT
      LAYER M4 ;
        RECT  69.036 31.344 69.12 31.368 ;
    END
  END r_d[502]
  PIN r_d[503]
    DIRECTION OUTPUT ;
    USE SIGNAL ;
    PORT
      LAYER M4 ;
        RECT  69.036 31.44 69.12 31.464 ;
    END
  END r_d[503]
  PIN r_d[504]
    DIRECTION OUTPUT ;
    USE SIGNAL ;
    PORT
      LAYER M4 ;
        RECT  69.036 31.536 69.12 31.56 ;
    END
  END r_d[504]
  PIN r_d[505]
    DIRECTION OUTPUT ;
    USE SIGNAL ;
    PORT
      LAYER M4 ;
        RECT  69.036 31.632 69.12 31.656 ;
    END
  END r_d[505]
  PIN r_d[506]
    DIRECTION OUTPUT ;
    USE SIGNAL ;
    PORT
      LAYER M4 ;
        RECT  69.036 31.728 69.12 31.752 ;
    END
  END r_d[506]
  PIN r_d[507]
    DIRECTION OUTPUT ;
    USE SIGNAL ;
    PORT
      LAYER M4 ;
        RECT  69.036 31.824 69.12 31.848 ;
    END
  END r_d[507]
  PIN r_d[508]
    DIRECTION OUTPUT ;
    USE SIGNAL ;
    PORT
      LAYER M4 ;
        RECT  69.036 31.92 69.12 31.944 ;
    END
  END r_d[508]
  PIN r_d[509]
    DIRECTION OUTPUT ;
    USE SIGNAL ;
    PORT
      LAYER M4 ;
        RECT  69.036 32.016 69.12 32.04 ;
    END
  END r_d[509]
  PIN r_d[50]
    DIRECTION OUTPUT ;
    USE SIGNAL ;
    PORT
      LAYER M4 ;
        RECT  69.036 72.432 69.12 72.456 ;
    END
  END r_d[50]
  PIN r_d[510]
    DIRECTION OUTPUT ;
    USE SIGNAL ;
    PORT
      LAYER M4 ;
        RECT  69.036 32.112 69.12 32.136 ;
    END
  END r_d[510]
  PIN r_d[511]
    DIRECTION OUTPUT ;
    USE SIGNAL ;
    PORT
      LAYER M4 ;
        RECT  69.036 58.32 69.12 58.344 ;
    END
  END r_d[511]
  PIN r_d[51]
    DIRECTION OUTPUT ;
    USE SIGNAL ;
    PORT
      LAYER M4 ;
        RECT  69.036 72.528 69.12 72.552 ;
    END
  END r_d[51]
  PIN r_d[52]
    DIRECTION OUTPUT ;
    USE SIGNAL ;
    PORT
      LAYER M4 ;
        RECT  69.036 72.624 69.12 72.648 ;
    END
  END r_d[52]
  PIN r_d[53]
    DIRECTION OUTPUT ;
    USE SIGNAL ;
    PORT
      LAYER M4 ;
        RECT  69.036 72.72 69.12 72.744 ;
    END
  END r_d[53]
  PIN r_d[54]
    DIRECTION OUTPUT ;
    USE SIGNAL ;
    PORT
      LAYER M4 ;
        RECT  69.036 72.816 69.12 72.84 ;
    END
  END r_d[54]
  PIN r_d[55]
    DIRECTION OUTPUT ;
    USE SIGNAL ;
    PORT
      LAYER M4 ;
        RECT  69.036 72.912 69.12 72.936 ;
    END
  END r_d[55]
  PIN r_d[56]
    DIRECTION OUTPUT ;
    USE SIGNAL ;
    PORT
      LAYER M4 ;
        RECT  69.036 73.008 69.12 73.032 ;
    END
  END r_d[56]
  PIN r_d[57]
    DIRECTION OUTPUT ;
    USE SIGNAL ;
    PORT
      LAYER M4 ;
        RECT  69.036 73.104 69.12 73.128 ;
    END
  END r_d[57]
  PIN r_d[58]
    DIRECTION OUTPUT ;
    USE SIGNAL ;
    PORT
      LAYER M4 ;
        RECT  69.036 73.2 69.12 73.224 ;
    END
  END r_d[58]
  PIN r_d[59]
    DIRECTION OUTPUT ;
    USE SIGNAL ;
    PORT
      LAYER M4 ;
        RECT  69.036 73.296 69.12 73.32 ;
    END
  END r_d[59]
  PIN r_d[5]
    DIRECTION OUTPUT ;
    USE SIGNAL ;
    PORT
      LAYER M4 ;
        RECT  69.036 81.168 69.12 81.192 ;
    END
  END r_d[5]
  PIN r_d[60]
    DIRECTION OUTPUT ;
    USE SIGNAL ;
    PORT
      LAYER M4 ;
        RECT  69.036 73.392 69.12 73.416 ;
    END
  END r_d[60]
  PIN r_d[61]
    DIRECTION OUTPUT ;
    USE SIGNAL ;
    PORT
      LAYER M4 ;
        RECT  69.036 73.488 69.12 73.512 ;
    END
  END r_d[61]
  PIN r_d[62]
    DIRECTION OUTPUT ;
    USE SIGNAL ;
    PORT
      LAYER M4 ;
        RECT  69.036 73.584 69.12 73.608 ;
    END
  END r_d[62]
  PIN r_d[63]
    DIRECTION OUTPUT ;
    USE SIGNAL ;
    PORT
      LAYER M4 ;
        RECT  69.036 42.192 69.12 42.216 ;
    END
  END r_d[63]
  PIN r_d[64]
    DIRECTION OUTPUT ;
    USE SIGNAL ;
    PORT
      LAYER M4 ;
        RECT  69.036 42.288 69.12 42.312 ;
    END
  END r_d[64]
  PIN r_d[65]
    DIRECTION OUTPUT ;
    USE SIGNAL ;
    PORT
      LAYER M4 ;
        RECT  69.036 42.384 69.12 42.408 ;
    END
  END r_d[65]
  PIN r_d[66]
    DIRECTION OUTPUT ;
    USE SIGNAL ;
    PORT
      LAYER M4 ;
        RECT  69.036 42.48 69.12 42.504 ;
    END
  END r_d[66]
  PIN r_d[67]
    DIRECTION OUTPUT ;
    USE SIGNAL ;
    PORT
      LAYER M4 ;
        RECT  69.036 42.576 69.12 42.6 ;
    END
  END r_d[67]
  PIN r_d[68]
    DIRECTION OUTPUT ;
    USE SIGNAL ;
    PORT
      LAYER M4 ;
        RECT  69.036 42.672 69.12 42.696 ;
    END
  END r_d[68]
  PIN r_d[69]
    DIRECTION OUTPUT ;
    USE SIGNAL ;
    PORT
      LAYER M4 ;
        RECT  69.036 42.768 69.12 42.792 ;
    END
  END r_d[69]
  PIN r_d[6]
    DIRECTION OUTPUT ;
    USE SIGNAL ;
    PORT
      LAYER M4 ;
        RECT  69.036 81.264 69.12 81.288 ;
    END
  END r_d[6]
  PIN r_d[70]
    DIRECTION OUTPUT ;
    USE SIGNAL ;
    PORT
      LAYER M4 ;
        RECT  69.036 42.864 69.12 42.888 ;
    END
  END r_d[70]
  PIN r_d[71]
    DIRECTION OUTPUT ;
    USE SIGNAL ;
    PORT
      LAYER M4 ;
        RECT  69.036 42.96 69.12 42.984 ;
    END
  END r_d[71]
  PIN r_d[72]
    DIRECTION OUTPUT ;
    USE SIGNAL ;
    PORT
      LAYER M4 ;
        RECT  69.036 43.056 69.12 43.08 ;
    END
  END r_d[72]
  PIN r_d[73]
    DIRECTION OUTPUT ;
    USE SIGNAL ;
    PORT
      LAYER M4 ;
        RECT  69.036 43.152 69.12 43.176 ;
    END
  END r_d[73]
  PIN r_d[74]
    DIRECTION OUTPUT ;
    USE SIGNAL ;
    PORT
      LAYER M4 ;
        RECT  69.036 43.248 69.12 43.272 ;
    END
  END r_d[74]
  PIN r_d[75]
    DIRECTION OUTPUT ;
    USE SIGNAL ;
    PORT
      LAYER M4 ;
        RECT  69.036 43.344 69.12 43.368 ;
    END
  END r_d[75]
  PIN r_d[76]
    DIRECTION OUTPUT ;
    USE SIGNAL ;
    PORT
      LAYER M4 ;
        RECT  69.036 43.44 69.12 43.464 ;
    END
  END r_d[76]
  PIN r_d[77]
    DIRECTION OUTPUT ;
    USE SIGNAL ;
    PORT
      LAYER M4 ;
        RECT  69.036 43.536 69.12 43.56 ;
    END
  END r_d[77]
  PIN r_d[78]
    DIRECTION OUTPUT ;
    USE SIGNAL ;
    PORT
      LAYER M4 ;
        RECT  69.036 43.632 69.12 43.656 ;
    END
  END r_d[78]
  PIN r_d[79]
    DIRECTION OUTPUT ;
    USE SIGNAL ;
    PORT
      LAYER M4 ;
        RECT  69.036 43.728 69.12 43.752 ;
    END
  END r_d[79]
  PIN r_d[7]
    DIRECTION OUTPUT ;
    USE SIGNAL ;
    PORT
      LAYER M4 ;
        RECT  69.036 81.36 69.12 81.384 ;
    END
  END r_d[7]
  PIN r_d[80]
    DIRECTION OUTPUT ;
    USE SIGNAL ;
    PORT
      LAYER M4 ;
        RECT  69.036 43.824 69.12 43.848 ;
    END
  END r_d[80]
  PIN r_d[81]
    DIRECTION OUTPUT ;
    USE SIGNAL ;
    PORT
      LAYER M4 ;
        RECT  69.036 43.92 69.12 43.944 ;
    END
  END r_d[81]
  PIN r_d[82]
    DIRECTION OUTPUT ;
    USE SIGNAL ;
    PORT
      LAYER M4 ;
        RECT  69.036 44.016 69.12 44.04 ;
    END
  END r_d[82]
  PIN r_d[83]
    DIRECTION OUTPUT ;
    USE SIGNAL ;
    PORT
      LAYER M4 ;
        RECT  69.036 44.112 69.12 44.136 ;
    END
  END r_d[83]
  PIN r_d[84]
    DIRECTION OUTPUT ;
    USE SIGNAL ;
    PORT
      LAYER M4 ;
        RECT  69.036 44.208 69.12 44.232 ;
    END
  END r_d[84]
  PIN r_d[85]
    DIRECTION OUTPUT ;
    USE SIGNAL ;
    PORT
      LAYER M4 ;
        RECT  69.036 44.304 69.12 44.328 ;
    END
  END r_d[85]
  PIN r_d[86]
    DIRECTION OUTPUT ;
    USE SIGNAL ;
    PORT
      LAYER M4 ;
        RECT  69.036 44.4 69.12 44.424 ;
    END
  END r_d[86]
  PIN r_d[87]
    DIRECTION OUTPUT ;
    USE SIGNAL ;
    PORT
      LAYER M4 ;
        RECT  69.036 44.496 69.12 44.52 ;
    END
  END r_d[87]
  PIN r_d[88]
    DIRECTION OUTPUT ;
    USE SIGNAL ;
    PORT
      LAYER M4 ;
        RECT  69.036 44.592 69.12 44.616 ;
    END
  END r_d[88]
  PIN r_d[89]
    DIRECTION OUTPUT ;
    USE SIGNAL ;
    PORT
      LAYER M4 ;
        RECT  69.036 44.688 69.12 44.712 ;
    END
  END r_d[89]
  PIN r_d[8]
    DIRECTION OUTPUT ;
    USE SIGNAL ;
    PORT
      LAYER M4 ;
        RECT  69.036 81.456 69.12 81.48 ;
    END
  END r_d[8]
  PIN r_d[90]
    DIRECTION OUTPUT ;
    USE SIGNAL ;
    PORT
      LAYER M4 ;
        RECT  69.036 44.784 69.12 44.808 ;
    END
  END r_d[90]
  PIN r_d[91]
    DIRECTION OUTPUT ;
    USE SIGNAL ;
    PORT
      LAYER M4 ;
        RECT  69.036 44.88 69.12 44.904 ;
    END
  END r_d[91]
  PIN r_d[92]
    DIRECTION OUTPUT ;
    USE SIGNAL ;
    PORT
      LAYER M4 ;
        RECT  69.036 44.976 69.12 45 ;
    END
  END r_d[92]
  PIN r_d[93]
    DIRECTION OUTPUT ;
    USE SIGNAL ;
    PORT
      LAYER M4 ;
        RECT  69.036 45.072 69.12 45.096 ;
    END
  END r_d[93]
  PIN r_d[94]
    DIRECTION OUTPUT ;
    USE SIGNAL ;
    PORT
      LAYER M4 ;
        RECT  69.036 45.168 69.12 45.192 ;
    END
  END r_d[94]
  PIN r_d[95]
    DIRECTION OUTPUT ;
    USE SIGNAL ;
    PORT
      LAYER M4 ;
        RECT  69.036 48.336 69.12 48.36 ;
    END
  END r_d[95]
  PIN r_d[96]
    DIRECTION OUTPUT ;
    USE SIGNAL ;
    PORT
      LAYER M4 ;
        RECT  69.036 48.432 69.12 48.456 ;
    END
  END r_d[96]
  PIN r_d[97]
    DIRECTION OUTPUT ;
    USE SIGNAL ;
    PORT
      LAYER M4 ;
        RECT  69.036 48.528 69.12 48.552 ;
    END
  END r_d[97]
  PIN r_d[98]
    DIRECTION OUTPUT ;
    USE SIGNAL ;
    PORT
      LAYER M4 ;
        RECT  69.036 48.624 69.12 48.648 ;
    END
  END r_d[98]
  PIN r_d[99]
    DIRECTION OUTPUT ;
    USE SIGNAL ;
    PORT
      LAYER M4 ;
        RECT  69.036 48.72 69.12 48.744 ;
    END
  END r_d[99]
  PIN r_d[9]
    DIRECTION OUTPUT ;
    USE SIGNAL ;
    PORT
      LAYER M4 ;
        RECT  69.036 81.552 69.12 81.576 ;
    END
  END r_d[9]
  PIN rclk
    DIRECTION INPUT ;
    USE SIGNAL ;
    PORT
      LAYER M4 ;
        RECT  69.036 58.416 69.12 58.44 ;
    END
  END rclk
  PIN rrst_n
    DIRECTION INPUT ;
    USE SIGNAL ;
    PORT
      LAYER M4 ;
        RECT  69.036 58.512 69.12 58.536 ;
    END
  END rrst_n
  PIN w_d[0]
    DIRECTION INPUT ;
    USE SIGNAL ;
    PORT
      LAYER M4 ;
        RECT  0 82.032 0.084 82.056 ;
    END
  END w_d[0]
  PIN w_d[100]
    DIRECTION INPUT ;
    USE SIGNAL ;
    PORT
      LAYER M4 ;
        RECT  0 44.016 0.084 44.04 ;
    END
  END w_d[100]
  PIN w_d[101]
    DIRECTION INPUT ;
    USE SIGNAL ;
    PORT
      LAYER M4 ;
        RECT  0 44.112 0.084 44.136 ;
    END
  END w_d[101]
  PIN w_d[102]
    DIRECTION INPUT ;
    USE SIGNAL ;
    PORT
      LAYER M4 ;
        RECT  0 44.208 0.084 44.232 ;
    END
  END w_d[102]
  PIN w_d[103]
    DIRECTION INPUT ;
    USE SIGNAL ;
    PORT
      LAYER M4 ;
        RECT  0 44.304 0.084 44.328 ;
    END
  END w_d[103]
  PIN w_d[104]
    DIRECTION INPUT ;
    USE SIGNAL ;
    PORT
      LAYER M4 ;
        RECT  0 44.4 0.084 44.424 ;
    END
  END w_d[104]
  PIN w_d[105]
    DIRECTION INPUT ;
    USE SIGNAL ;
    PORT
      LAYER M4 ;
        RECT  0 44.496 0.084 44.52 ;
    END
  END w_d[105]
  PIN w_d[106]
    DIRECTION INPUT ;
    USE SIGNAL ;
    PORT
      LAYER M4 ;
        RECT  0 44.592 0.084 44.616 ;
    END
  END w_d[106]
  PIN w_d[107]
    DIRECTION INPUT ;
    USE SIGNAL ;
    PORT
      LAYER M4 ;
        RECT  0 44.688 0.084 44.712 ;
    END
  END w_d[107]
  PIN w_d[108]
    DIRECTION INPUT ;
    USE SIGNAL ;
    PORT
      LAYER M4 ;
        RECT  0 44.784 0.084 44.808 ;
    END
  END w_d[108]
  PIN w_d[109]
    DIRECTION INPUT ;
    USE SIGNAL ;
    PORT
      LAYER M4 ;
        RECT  0 44.88 0.084 44.904 ;
    END
  END w_d[109]
  PIN w_d[10]
    DIRECTION INPUT ;
    USE SIGNAL ;
    PORT
      LAYER M4 ;
        RECT  0 82.992 0.084 83.016 ;
    END
  END w_d[10]
  PIN w_d[110]
    DIRECTION INPUT ;
    USE SIGNAL ;
    PORT
      LAYER M4 ;
        RECT  0 44.976 0.084 45 ;
    END
  END w_d[110]
  PIN w_d[111]
    DIRECTION INPUT ;
    USE SIGNAL ;
    PORT
      LAYER M4 ;
        RECT  0 45.072 0.084 45.096 ;
    END
  END w_d[111]
  PIN w_d[112]
    DIRECTION INPUT ;
    USE SIGNAL ;
    PORT
      LAYER M4 ;
        RECT  0 45.168 0.084 45.192 ;
    END
  END w_d[112]
  PIN w_d[113]
    DIRECTION INPUT ;
    USE SIGNAL ;
    PORT
      LAYER M4 ;
        RECT  0 45.264 0.084 45.288 ;
    END
  END w_d[113]
  PIN w_d[114]
    DIRECTION INPUT ;
    USE SIGNAL ;
    PORT
      LAYER M4 ;
        RECT  0 45.36 0.084 45.384 ;
    END
  END w_d[114]
  PIN w_d[115]
    DIRECTION INPUT ;
    USE SIGNAL ;
    PORT
      LAYER M4 ;
        RECT  0 45.456 0.084 45.48 ;
    END
  END w_d[115]
  PIN w_d[116]
    DIRECTION INPUT ;
    USE SIGNAL ;
    PORT
      LAYER M4 ;
        RECT  0 45.552 0.084 45.576 ;
    END
  END w_d[116]
  PIN w_d[117]
    DIRECTION INPUT ;
    USE SIGNAL ;
    PORT
      LAYER M4 ;
        RECT  0 45.648 0.084 45.672 ;
    END
  END w_d[117]
  PIN w_d[118]
    DIRECTION INPUT ;
    USE SIGNAL ;
    PORT
      LAYER M4 ;
        RECT  0 45.744 0.084 45.768 ;
    END
  END w_d[118]
  PIN w_d[119]
    DIRECTION INPUT ;
    USE SIGNAL ;
    PORT
      LAYER M4 ;
        RECT  0 45.84 0.084 45.864 ;
    END
  END w_d[119]
  PIN w_d[11]
    DIRECTION INPUT ;
    USE SIGNAL ;
    PORT
      LAYER M4 ;
        RECT  0 83.088 0.084 83.112 ;
    END
  END w_d[11]
  PIN w_d[120]
    DIRECTION INPUT ;
    USE SIGNAL ;
    PORT
      LAYER M4 ;
        RECT  0 45.936 0.084 45.96 ;
    END
  END w_d[120]
  PIN w_d[121]
    DIRECTION INPUT ;
    USE SIGNAL ;
    PORT
      LAYER M4 ;
        RECT  0 46.032 0.084 46.056 ;
    END
  END w_d[121]
  PIN w_d[122]
    DIRECTION INPUT ;
    USE SIGNAL ;
    PORT
      LAYER M4 ;
        RECT  0 46.128 0.084 46.152 ;
    END
  END w_d[122]
  PIN w_d[123]
    DIRECTION INPUT ;
    USE SIGNAL ;
    PORT
      LAYER M4 ;
        RECT  0 46.224 0.084 46.248 ;
    END
  END w_d[123]
  PIN w_d[124]
    DIRECTION INPUT ;
    USE SIGNAL ;
    PORT
      LAYER M4 ;
        RECT  0 46.32 0.084 46.344 ;
    END
  END w_d[124]
  PIN w_d[125]
    DIRECTION INPUT ;
    USE SIGNAL ;
    PORT
      LAYER M4 ;
        RECT  0 46.416 0.084 46.44 ;
    END
  END w_d[125]
  PIN w_d[126]
    DIRECTION INPUT ;
    USE SIGNAL ;
    PORT
      LAYER M4 ;
        RECT  0 46.512 0.084 46.536 ;
    END
  END w_d[126]
  PIN w_d[127]
    DIRECTION INPUT ;
    USE SIGNAL ;
    PORT
      LAYER M4 ;
        RECT  0 46.608 0.084 46.632 ;
    END
  END w_d[127]
  PIN w_d[128]
    DIRECTION INPUT ;
    USE SIGNAL ;
    PORT
      LAYER M4 ;
        RECT  0 68.976 0.084 69 ;
    END
  END w_d[128]
  PIN w_d[129]
    DIRECTION INPUT ;
    USE SIGNAL ;
    PORT
      LAYER M4 ;
        RECT  0 69.072 0.084 69.096 ;
    END
  END w_d[129]
  PIN w_d[12]
    DIRECTION INPUT ;
    USE SIGNAL ;
    PORT
      LAYER M4 ;
        RECT  0 83.184 0.084 83.208 ;
    END
  END w_d[12]
  PIN w_d[130]
    DIRECTION INPUT ;
    USE SIGNAL ;
    PORT
      LAYER M4 ;
        RECT  0 69.168 0.084 69.192 ;
    END
  END w_d[130]
  PIN w_d[131]
    DIRECTION INPUT ;
    USE SIGNAL ;
    PORT
      LAYER M4 ;
        RECT  0 69.264 0.084 69.288 ;
    END
  END w_d[131]
  PIN w_d[132]
    DIRECTION INPUT ;
    USE SIGNAL ;
    PORT
      LAYER M4 ;
        RECT  0 69.36 0.084 69.384 ;
    END
  END w_d[132]
  PIN w_d[133]
    DIRECTION INPUT ;
    USE SIGNAL ;
    PORT
      LAYER M4 ;
        RECT  0 69.456 0.084 69.48 ;
    END
  END w_d[133]
  PIN w_d[134]
    DIRECTION INPUT ;
    USE SIGNAL ;
    PORT
      LAYER M4 ;
        RECT  0 69.552 0.084 69.576 ;
    END
  END w_d[134]
  PIN w_d[135]
    DIRECTION INPUT ;
    USE SIGNAL ;
    PORT
      LAYER M4 ;
        RECT  0 69.648 0.084 69.672 ;
    END
  END w_d[135]
  PIN w_d[136]
    DIRECTION INPUT ;
    USE SIGNAL ;
    PORT
      LAYER M4 ;
        RECT  0 69.744 0.084 69.768 ;
    END
  END w_d[136]
  PIN w_d[137]
    DIRECTION INPUT ;
    USE SIGNAL ;
    PORT
      LAYER M4 ;
        RECT  0 69.84 0.084 69.864 ;
    END
  END w_d[137]
  PIN w_d[138]
    DIRECTION INPUT ;
    USE SIGNAL ;
    PORT
      LAYER M4 ;
        RECT  0 69.936 0.084 69.96 ;
    END
  END w_d[138]
  PIN w_d[139]
    DIRECTION INPUT ;
    USE SIGNAL ;
    PORT
      LAYER M4 ;
        RECT  0 70.032 0.084 70.056 ;
    END
  END w_d[139]
  PIN w_d[13]
    DIRECTION INPUT ;
    USE SIGNAL ;
    PORT
      LAYER M4 ;
        RECT  0 83.28 0.084 83.304 ;
    END
  END w_d[13]
  PIN w_d[140]
    DIRECTION INPUT ;
    USE SIGNAL ;
    PORT
      LAYER M4 ;
        RECT  0 70.128 0.084 70.152 ;
    END
  END w_d[140]
  PIN w_d[141]
    DIRECTION INPUT ;
    USE SIGNAL ;
    PORT
      LAYER M4 ;
        RECT  0 70.224 0.084 70.248 ;
    END
  END w_d[141]
  PIN w_d[142]
    DIRECTION INPUT ;
    USE SIGNAL ;
    PORT
      LAYER M4 ;
        RECT  0 70.32 0.084 70.344 ;
    END
  END w_d[142]
  PIN w_d[143]
    DIRECTION INPUT ;
    USE SIGNAL ;
    PORT
      LAYER M4 ;
        RECT  0 70.416 0.084 70.44 ;
    END
  END w_d[143]
  PIN w_d[144]
    DIRECTION INPUT ;
    USE SIGNAL ;
    PORT
      LAYER M4 ;
        RECT  0 70.512 0.084 70.536 ;
    END
  END w_d[144]
  PIN w_d[145]
    DIRECTION INPUT ;
    USE SIGNAL ;
    PORT
      LAYER M4 ;
        RECT  0 70.608 0.084 70.632 ;
    END
  END w_d[145]
  PIN w_d[146]
    DIRECTION INPUT ;
    USE SIGNAL ;
    PORT
      LAYER M4 ;
        RECT  0 70.704 0.084 70.728 ;
    END
  END w_d[146]
  PIN w_d[147]
    DIRECTION INPUT ;
    USE SIGNAL ;
    PORT
      LAYER M4 ;
        RECT  0 70.8 0.084 70.824 ;
    END
  END w_d[147]
  PIN w_d[148]
    DIRECTION INPUT ;
    USE SIGNAL ;
    PORT
      LAYER M4 ;
        RECT  0 70.896 0.084 70.92 ;
    END
  END w_d[148]
  PIN w_d[149]
    DIRECTION INPUT ;
    USE SIGNAL ;
    PORT
      LAYER M4 ;
        RECT  0 70.992 0.084 71.016 ;
    END
  END w_d[149]
  PIN w_d[14]
    DIRECTION INPUT ;
    USE SIGNAL ;
    PORT
      LAYER M4 ;
        RECT  0 83.376 0.084 83.4 ;
    END
  END w_d[14]
  PIN w_d[150]
    DIRECTION INPUT ;
    USE SIGNAL ;
    PORT
      LAYER M4 ;
        RECT  0 71.088 0.084 71.112 ;
    END
  END w_d[150]
  PIN w_d[151]
    DIRECTION INPUT ;
    USE SIGNAL ;
    PORT
      LAYER M4 ;
        RECT  0 71.184 0.084 71.208 ;
    END
  END w_d[151]
  PIN w_d[152]
    DIRECTION INPUT ;
    USE SIGNAL ;
    PORT
      LAYER M4 ;
        RECT  0 71.28 0.084 71.304 ;
    END
  END w_d[152]
  PIN w_d[153]
    DIRECTION INPUT ;
    USE SIGNAL ;
    PORT
      LAYER M4 ;
        RECT  0 71.376 0.084 71.4 ;
    END
  END w_d[153]
  PIN w_d[154]
    DIRECTION INPUT ;
    USE SIGNAL ;
    PORT
      LAYER M4 ;
        RECT  0 71.472 0.084 71.496 ;
    END
  END w_d[154]
  PIN w_d[155]
    DIRECTION INPUT ;
    USE SIGNAL ;
    PORT
      LAYER M4 ;
        RECT  0 71.568 0.084 71.592 ;
    END
  END w_d[155]
  PIN w_d[156]
    DIRECTION INPUT ;
    USE SIGNAL ;
    PORT
      LAYER M4 ;
        RECT  0 71.664 0.084 71.688 ;
    END
  END w_d[156]
  PIN w_d[157]
    DIRECTION INPUT ;
    USE SIGNAL ;
    PORT
      LAYER M4 ;
        RECT  0 71.76 0.084 71.784 ;
    END
  END w_d[157]
  PIN w_d[158]
    DIRECTION INPUT ;
    USE SIGNAL ;
    PORT
      LAYER M4 ;
        RECT  0 71.856 0.084 71.88 ;
    END
  END w_d[158]
  PIN w_d[159]
    DIRECTION INPUT ;
    USE SIGNAL ;
    PORT
      LAYER M4 ;
        RECT  0 71.952 0.084 71.976 ;
    END
  END w_d[159]
  PIN w_d[15]
    DIRECTION INPUT ;
    USE SIGNAL ;
    PORT
      LAYER M4 ;
        RECT  0 83.472 0.084 83.496 ;
    END
  END w_d[15]
  PIN w_d[160]
    DIRECTION INPUT ;
    USE SIGNAL ;
    PORT
      LAYER M4 ;
        RECT  0 62.832 0.084 62.856 ;
    END
  END w_d[160]
  PIN w_d[161]
    DIRECTION INPUT ;
    USE SIGNAL ;
    PORT
      LAYER M4 ;
        RECT  0 62.928 0.084 62.952 ;
    END
  END w_d[161]
  PIN w_d[162]
    DIRECTION INPUT ;
    USE SIGNAL ;
    PORT
      LAYER M4 ;
        RECT  0 63.024 0.084 63.048 ;
    END
  END w_d[162]
  PIN w_d[163]
    DIRECTION INPUT ;
    USE SIGNAL ;
    PORT
      LAYER M4 ;
        RECT  0 63.12 0.084 63.144 ;
    END
  END w_d[163]
  PIN w_d[164]
    DIRECTION INPUT ;
    USE SIGNAL ;
    PORT
      LAYER M4 ;
        RECT  0 63.216 0.084 63.24 ;
    END
  END w_d[164]
  PIN w_d[165]
    DIRECTION INPUT ;
    USE SIGNAL ;
    PORT
      LAYER M4 ;
        RECT  0 63.312 0.084 63.336 ;
    END
  END w_d[165]
  PIN w_d[166]
    DIRECTION INPUT ;
    USE SIGNAL ;
    PORT
      LAYER M4 ;
        RECT  0 63.408 0.084 63.432 ;
    END
  END w_d[166]
  PIN w_d[167]
    DIRECTION INPUT ;
    USE SIGNAL ;
    PORT
      LAYER M4 ;
        RECT  0 63.504 0.084 63.528 ;
    END
  END w_d[167]
  PIN w_d[168]
    DIRECTION INPUT ;
    USE SIGNAL ;
    PORT
      LAYER M4 ;
        RECT  0 63.6 0.084 63.624 ;
    END
  END w_d[168]
  PIN w_d[169]
    DIRECTION INPUT ;
    USE SIGNAL ;
    PORT
      LAYER M4 ;
        RECT  0 63.696 0.084 63.72 ;
    END
  END w_d[169]
  PIN w_d[16]
    DIRECTION INPUT ;
    USE SIGNAL ;
    PORT
      LAYER M4 ;
        RECT  0 83.568 0.084 83.592 ;
    END
  END w_d[16]
  PIN w_d[170]
    DIRECTION INPUT ;
    USE SIGNAL ;
    PORT
      LAYER M4 ;
        RECT  0 63.792 0.084 63.816 ;
    END
  END w_d[170]
  PIN w_d[171]
    DIRECTION INPUT ;
    USE SIGNAL ;
    PORT
      LAYER M4 ;
        RECT  0 63.888 0.084 63.912 ;
    END
  END w_d[171]
  PIN w_d[172]
    DIRECTION INPUT ;
    USE SIGNAL ;
    PORT
      LAYER M4 ;
        RECT  0 63.984 0.084 64.008 ;
    END
  END w_d[172]
  PIN w_d[173]
    DIRECTION INPUT ;
    USE SIGNAL ;
    PORT
      LAYER M4 ;
        RECT  0 64.08 0.084 64.104 ;
    END
  END w_d[173]
  PIN w_d[174]
    DIRECTION INPUT ;
    USE SIGNAL ;
    PORT
      LAYER M4 ;
        RECT  0 64.176 0.084 64.2 ;
    END
  END w_d[174]
  PIN w_d[175]
    DIRECTION INPUT ;
    USE SIGNAL ;
    PORT
      LAYER M4 ;
        RECT  0 64.272 0.084 64.296 ;
    END
  END w_d[175]
  PIN w_d[176]
    DIRECTION INPUT ;
    USE SIGNAL ;
    PORT
      LAYER M4 ;
        RECT  0 64.368 0.084 64.392 ;
    END
  END w_d[176]
  PIN w_d[177]
    DIRECTION INPUT ;
    USE SIGNAL ;
    PORT
      LAYER M4 ;
        RECT  0 64.464 0.084 64.488 ;
    END
  END w_d[177]
  PIN w_d[178]
    DIRECTION INPUT ;
    USE SIGNAL ;
    PORT
      LAYER M4 ;
        RECT  0 64.56 0.084 64.584 ;
    END
  END w_d[178]
  PIN w_d[179]
    DIRECTION INPUT ;
    USE SIGNAL ;
    PORT
      LAYER M4 ;
        RECT  0 64.656 0.084 64.68 ;
    END
  END w_d[179]
  PIN w_d[17]
    DIRECTION INPUT ;
    USE SIGNAL ;
    PORT
      LAYER M4 ;
        RECT  0 83.664 0.084 83.688 ;
    END
  END w_d[17]
  PIN w_d[180]
    DIRECTION INPUT ;
    USE SIGNAL ;
    PORT
      LAYER M4 ;
        RECT  0 64.752 0.084 64.776 ;
    END
  END w_d[180]
  PIN w_d[181]
    DIRECTION INPUT ;
    USE SIGNAL ;
    PORT
      LAYER M4 ;
        RECT  0 64.848 0.084 64.872 ;
    END
  END w_d[181]
  PIN w_d[182]
    DIRECTION INPUT ;
    USE SIGNAL ;
    PORT
      LAYER M4 ;
        RECT  0 64.944 0.084 64.968 ;
    END
  END w_d[182]
  PIN w_d[183]
    DIRECTION INPUT ;
    USE SIGNAL ;
    PORT
      LAYER M4 ;
        RECT  0 65.04 0.084 65.064 ;
    END
  END w_d[183]
  PIN w_d[184]
    DIRECTION INPUT ;
    USE SIGNAL ;
    PORT
      LAYER M4 ;
        RECT  0 65.136 0.084 65.16 ;
    END
  END w_d[184]
  PIN w_d[185]
    DIRECTION INPUT ;
    USE SIGNAL ;
    PORT
      LAYER M4 ;
        RECT  0 65.232 0.084 65.256 ;
    END
  END w_d[185]
  PIN w_d[186]
    DIRECTION INPUT ;
    USE SIGNAL ;
    PORT
      LAYER M4 ;
        RECT  0 65.328 0.084 65.352 ;
    END
  END w_d[186]
  PIN w_d[187]
    DIRECTION INPUT ;
    USE SIGNAL ;
    PORT
      LAYER M4 ;
        RECT  0 65.424 0.084 65.448 ;
    END
  END w_d[187]
  PIN w_d[188]
    DIRECTION INPUT ;
    USE SIGNAL ;
    PORT
      LAYER M4 ;
        RECT  0 65.52 0.084 65.544 ;
    END
  END w_d[188]
  PIN w_d[189]
    DIRECTION INPUT ;
    USE SIGNAL ;
    PORT
      LAYER M4 ;
        RECT  0 65.616 0.084 65.64 ;
    END
  END w_d[189]
  PIN w_d[18]
    DIRECTION INPUT ;
    USE SIGNAL ;
    PORT
      LAYER M4 ;
        RECT  0 83.76 0.084 83.784 ;
    END
  END w_d[18]
  PIN w_d[190]
    DIRECTION INPUT ;
    USE SIGNAL ;
    PORT
      LAYER M4 ;
        RECT  0 65.712 0.084 65.736 ;
    END
  END w_d[190]
  PIN w_d[191]
    DIRECTION INPUT ;
    USE SIGNAL ;
    PORT
      LAYER M4 ;
        RECT  0 65.808 0.084 65.832 ;
    END
  END w_d[191]
  PIN w_d[192]
    DIRECTION INPUT ;
    USE SIGNAL ;
    PORT
      LAYER M4 ;
        RECT  0 78.96 0.084 78.984 ;
    END
  END w_d[192]
  PIN w_d[193]
    DIRECTION INPUT ;
    USE SIGNAL ;
    PORT
      LAYER M4 ;
        RECT  0 79.056 0.084 79.08 ;
    END
  END w_d[193]
  PIN w_d[194]
    DIRECTION INPUT ;
    USE SIGNAL ;
    PORT
      LAYER M4 ;
        RECT  0 79.152 0.084 79.176 ;
    END
  END w_d[194]
  PIN w_d[195]
    DIRECTION INPUT ;
    USE SIGNAL ;
    PORT
      LAYER M4 ;
        RECT  0 79.248 0.084 79.272 ;
    END
  END w_d[195]
  PIN w_d[196]
    DIRECTION INPUT ;
    USE SIGNAL ;
    PORT
      LAYER M4 ;
        RECT  0 79.344 0.084 79.368 ;
    END
  END w_d[196]
  PIN w_d[197]
    DIRECTION INPUT ;
    USE SIGNAL ;
    PORT
      LAYER M4 ;
        RECT  0 79.44 0.084 79.464 ;
    END
  END w_d[197]
  PIN w_d[198]
    DIRECTION INPUT ;
    USE SIGNAL ;
    PORT
      LAYER M4 ;
        RECT  0 79.536 0.084 79.56 ;
    END
  END w_d[198]
  PIN w_d[199]
    DIRECTION INPUT ;
    USE SIGNAL ;
    PORT
      LAYER M4 ;
        RECT  0 79.632 0.084 79.656 ;
    END
  END w_d[199]
  PIN w_d[19]
    DIRECTION INPUT ;
    USE SIGNAL ;
    PORT
      LAYER M4 ;
        RECT  0 83.856 0.084 83.88 ;
    END
  END w_d[19]
  PIN w_d[1]
    DIRECTION INPUT ;
    USE SIGNAL ;
    PORT
      LAYER M4 ;
        RECT  0 82.128 0.084 82.152 ;
    END
  END w_d[1]
  PIN w_d[200]
    DIRECTION INPUT ;
    USE SIGNAL ;
    PORT
      LAYER M4 ;
        RECT  0 79.728 0.084 79.752 ;
    END
  END w_d[200]
  PIN w_d[201]
    DIRECTION INPUT ;
    USE SIGNAL ;
    PORT
      LAYER M4 ;
        RECT  0 79.824 0.084 79.848 ;
    END
  END w_d[201]
  PIN w_d[202]
    DIRECTION INPUT ;
    USE SIGNAL ;
    PORT
      LAYER M4 ;
        RECT  0 79.92 0.084 79.944 ;
    END
  END w_d[202]
  PIN w_d[203]
    DIRECTION INPUT ;
    USE SIGNAL ;
    PORT
      LAYER M4 ;
        RECT  0 80.016 0.084 80.04 ;
    END
  END w_d[203]
  PIN w_d[204]
    DIRECTION INPUT ;
    USE SIGNAL ;
    PORT
      LAYER M4 ;
        RECT  0 80.112 0.084 80.136 ;
    END
  END w_d[204]
  PIN w_d[205]
    DIRECTION INPUT ;
    USE SIGNAL ;
    PORT
      LAYER M4 ;
        RECT  0 80.208 0.084 80.232 ;
    END
  END w_d[205]
  PIN w_d[206]
    DIRECTION INPUT ;
    USE SIGNAL ;
    PORT
      LAYER M4 ;
        RECT  0 80.304 0.084 80.328 ;
    END
  END w_d[206]
  PIN w_d[207]
    DIRECTION INPUT ;
    USE SIGNAL ;
    PORT
      LAYER M4 ;
        RECT  0 80.4 0.084 80.424 ;
    END
  END w_d[207]
  PIN w_d[208]
    DIRECTION INPUT ;
    USE SIGNAL ;
    PORT
      LAYER M4 ;
        RECT  0 80.496 0.084 80.52 ;
    END
  END w_d[208]
  PIN w_d[209]
    DIRECTION INPUT ;
    USE SIGNAL ;
    PORT
      LAYER M4 ;
        RECT  0 80.592 0.084 80.616 ;
    END
  END w_d[209]
  PIN w_d[20]
    DIRECTION INPUT ;
    USE SIGNAL ;
    PORT
      LAYER M4 ;
        RECT  0 83.952 0.084 83.976 ;
    END
  END w_d[20]
  PIN w_d[210]
    DIRECTION INPUT ;
    USE SIGNAL ;
    PORT
      LAYER M4 ;
        RECT  0 80.688 0.084 80.712 ;
    END
  END w_d[210]
  PIN w_d[211]
    DIRECTION INPUT ;
    USE SIGNAL ;
    PORT
      LAYER M4 ;
        RECT  0 80.784 0.084 80.808 ;
    END
  END w_d[211]
  PIN w_d[212]
    DIRECTION INPUT ;
    USE SIGNAL ;
    PORT
      LAYER M4 ;
        RECT  0 80.88 0.084 80.904 ;
    END
  END w_d[212]
  PIN w_d[213]
    DIRECTION INPUT ;
    USE SIGNAL ;
    PORT
      LAYER M4 ;
        RECT  0 80.976 0.084 81 ;
    END
  END w_d[213]
  PIN w_d[214]
    DIRECTION INPUT ;
    USE SIGNAL ;
    PORT
      LAYER M4 ;
        RECT  0 81.072 0.084 81.096 ;
    END
  END w_d[214]
  PIN w_d[215]
    DIRECTION INPUT ;
    USE SIGNAL ;
    PORT
      LAYER M4 ;
        RECT  0 81.168 0.084 81.192 ;
    END
  END w_d[215]
  PIN w_d[216]
    DIRECTION INPUT ;
    USE SIGNAL ;
    PORT
      LAYER M4 ;
        RECT  0 81.264 0.084 81.288 ;
    END
  END w_d[216]
  PIN w_d[217]
    DIRECTION INPUT ;
    USE SIGNAL ;
    PORT
      LAYER M4 ;
        RECT  0 81.36 0.084 81.384 ;
    END
  END w_d[217]
  PIN w_d[218]
    DIRECTION INPUT ;
    USE SIGNAL ;
    PORT
      LAYER M4 ;
        RECT  0 81.456 0.084 81.48 ;
    END
  END w_d[218]
  PIN w_d[219]
    DIRECTION INPUT ;
    USE SIGNAL ;
    PORT
      LAYER M4 ;
        RECT  0 81.552 0.084 81.576 ;
    END
  END w_d[219]
  PIN w_d[21]
    DIRECTION INPUT ;
    USE SIGNAL ;
    PORT
      LAYER M4 ;
        RECT  0 84.048 0.084 84.072 ;
    END
  END w_d[21]
  PIN w_d[220]
    DIRECTION INPUT ;
    USE SIGNAL ;
    PORT
      LAYER M4 ;
        RECT  0 81.648 0.084 81.672 ;
    END
  END w_d[220]
  PIN w_d[221]
    DIRECTION INPUT ;
    USE SIGNAL ;
    PORT
      LAYER M4 ;
        RECT  0 81.744 0.084 81.768 ;
    END
  END w_d[221]
  PIN w_d[222]
    DIRECTION INPUT ;
    USE SIGNAL ;
    PORT
      LAYER M4 ;
        RECT  0 81.84 0.084 81.864 ;
    END
  END w_d[222]
  PIN w_d[223]
    DIRECTION INPUT ;
    USE SIGNAL ;
    PORT
      LAYER M4 ;
        RECT  0 81.936 0.084 81.96 ;
    END
  END w_d[223]
  PIN w_d[224]
    DIRECTION INPUT ;
    USE SIGNAL ;
    PORT
      LAYER M4 ;
        RECT  0 75.888 0.084 75.912 ;
    END
  END w_d[224]
  PIN w_d[225]
    DIRECTION INPUT ;
    USE SIGNAL ;
    PORT
      LAYER M4 ;
        RECT  0 75.984 0.084 76.008 ;
    END
  END w_d[225]
  PIN w_d[226]
    DIRECTION INPUT ;
    USE SIGNAL ;
    PORT
      LAYER M4 ;
        RECT  0 76.08 0.084 76.104 ;
    END
  END w_d[226]
  PIN w_d[227]
    DIRECTION INPUT ;
    USE SIGNAL ;
    PORT
      LAYER M4 ;
        RECT  0 76.176 0.084 76.2 ;
    END
  END w_d[227]
  PIN w_d[228]
    DIRECTION INPUT ;
    USE SIGNAL ;
    PORT
      LAYER M4 ;
        RECT  0 76.272 0.084 76.296 ;
    END
  END w_d[228]
  PIN w_d[229]
    DIRECTION INPUT ;
    USE SIGNAL ;
    PORT
      LAYER M4 ;
        RECT  0 76.368 0.084 76.392 ;
    END
  END w_d[229]
  PIN w_d[22]
    DIRECTION INPUT ;
    USE SIGNAL ;
    PORT
      LAYER M4 ;
        RECT  0 84.144 0.084 84.168 ;
    END
  END w_d[22]
  PIN w_d[230]
    DIRECTION INPUT ;
    USE SIGNAL ;
    PORT
      LAYER M4 ;
        RECT  0 76.464 0.084 76.488 ;
    END
  END w_d[230]
  PIN w_d[231]
    DIRECTION INPUT ;
    USE SIGNAL ;
    PORT
      LAYER M4 ;
        RECT  0 76.56 0.084 76.584 ;
    END
  END w_d[231]
  PIN w_d[232]
    DIRECTION INPUT ;
    USE SIGNAL ;
    PORT
      LAYER M4 ;
        RECT  0 76.656 0.084 76.68 ;
    END
  END w_d[232]
  PIN w_d[233]
    DIRECTION INPUT ;
    USE SIGNAL ;
    PORT
      LAYER M4 ;
        RECT  0 76.752 0.084 76.776 ;
    END
  END w_d[233]
  PIN w_d[234]
    DIRECTION INPUT ;
    USE SIGNAL ;
    PORT
      LAYER M4 ;
        RECT  0 76.848 0.084 76.872 ;
    END
  END w_d[234]
  PIN w_d[235]
    DIRECTION INPUT ;
    USE SIGNAL ;
    PORT
      LAYER M4 ;
        RECT  0 76.944 0.084 76.968 ;
    END
  END w_d[235]
  PIN w_d[236]
    DIRECTION INPUT ;
    USE SIGNAL ;
    PORT
      LAYER M4 ;
        RECT  0 77.04 0.084 77.064 ;
    END
  END w_d[236]
  PIN w_d[237]
    DIRECTION INPUT ;
    USE SIGNAL ;
    PORT
      LAYER M4 ;
        RECT  0 77.136 0.084 77.16 ;
    END
  END w_d[237]
  PIN w_d[238]
    DIRECTION INPUT ;
    USE SIGNAL ;
    PORT
      LAYER M4 ;
        RECT  0 77.232 0.084 77.256 ;
    END
  END w_d[238]
  PIN w_d[239]
    DIRECTION INPUT ;
    USE SIGNAL ;
    PORT
      LAYER M4 ;
        RECT  0 77.328 0.084 77.352 ;
    END
  END w_d[239]
  PIN w_d[23]
    DIRECTION INPUT ;
    USE SIGNAL ;
    PORT
      LAYER M4 ;
        RECT  0 84.24 0.084 84.264 ;
    END
  END w_d[23]
  PIN w_d[240]
    DIRECTION INPUT ;
    USE SIGNAL ;
    PORT
      LAYER M4 ;
        RECT  0 77.424 0.084 77.448 ;
    END
  END w_d[240]
  PIN w_d[241]
    DIRECTION INPUT ;
    USE SIGNAL ;
    PORT
      LAYER M4 ;
        RECT  0 77.52 0.084 77.544 ;
    END
  END w_d[241]
  PIN w_d[242]
    DIRECTION INPUT ;
    USE SIGNAL ;
    PORT
      LAYER M4 ;
        RECT  0 77.616 0.084 77.64 ;
    END
  END w_d[242]
  PIN w_d[243]
    DIRECTION INPUT ;
    USE SIGNAL ;
    PORT
      LAYER M4 ;
        RECT  0 77.712 0.084 77.736 ;
    END
  END w_d[243]
  PIN w_d[244]
    DIRECTION INPUT ;
    USE SIGNAL ;
    PORT
      LAYER M4 ;
        RECT  0 77.808 0.084 77.832 ;
    END
  END w_d[244]
  PIN w_d[245]
    DIRECTION INPUT ;
    USE SIGNAL ;
    PORT
      LAYER M4 ;
        RECT  0 77.904 0.084 77.928 ;
    END
  END w_d[245]
  PIN w_d[246]
    DIRECTION INPUT ;
    USE SIGNAL ;
    PORT
      LAYER M4 ;
        RECT  0 78 0.084 78.024 ;
    END
  END w_d[246]
  PIN w_d[247]
    DIRECTION INPUT ;
    USE SIGNAL ;
    PORT
      LAYER M4 ;
        RECT  0 78.096 0.084 78.12 ;
    END
  END w_d[247]
  PIN w_d[248]
    DIRECTION INPUT ;
    USE SIGNAL ;
    PORT
      LAYER M4 ;
        RECT  0 78.192 0.084 78.216 ;
    END
  END w_d[248]
  PIN w_d[249]
    DIRECTION INPUT ;
    USE SIGNAL ;
    PORT
      LAYER M4 ;
        RECT  0 78.288 0.084 78.312 ;
    END
  END w_d[249]
  PIN w_d[24]
    DIRECTION INPUT ;
    USE SIGNAL ;
    PORT
      LAYER M4 ;
        RECT  0 84.336 0.084 84.36 ;
    END
  END w_d[24]
  PIN w_d[250]
    DIRECTION INPUT ;
    USE SIGNAL ;
    PORT
      LAYER M4 ;
        RECT  0 78.384 0.084 78.408 ;
    END
  END w_d[250]
  PIN w_d[251]
    DIRECTION INPUT ;
    USE SIGNAL ;
    PORT
      LAYER M4 ;
        RECT  0 78.48 0.084 78.504 ;
    END
  END w_d[251]
  PIN w_d[252]
    DIRECTION INPUT ;
    USE SIGNAL ;
    PORT
      LAYER M4 ;
        RECT  0 78.576 0.084 78.6 ;
    END
  END w_d[252]
  PIN w_d[253]
    DIRECTION INPUT ;
    USE SIGNAL ;
    PORT
      LAYER M4 ;
        RECT  0 78.672 0.084 78.696 ;
    END
  END w_d[253]
  PIN w_d[254]
    DIRECTION INPUT ;
    USE SIGNAL ;
    PORT
      LAYER M4 ;
        RECT  0 78.768 0.084 78.792 ;
    END
  END w_d[254]
  PIN w_d[255]
    DIRECTION INPUT ;
    USE SIGNAL ;
    PORT
      LAYER M4 ;
        RECT  0 78.864 0.084 78.888 ;
    END
  END w_d[255]
  PIN w_d[256]
    DIRECTION INPUT ;
    USE SIGNAL ;
    PORT
      LAYER M4 ;
        RECT  0 49.776 0.084 49.8 ;
    END
  END w_d[256]
  PIN w_d[257]
    DIRECTION INPUT ;
    USE SIGNAL ;
    PORT
      LAYER M4 ;
        RECT  0 49.872 0.084 49.896 ;
    END
  END w_d[257]
  PIN w_d[258]
    DIRECTION INPUT ;
    USE SIGNAL ;
    PORT
      LAYER M4 ;
        RECT  0 49.968 0.084 49.992 ;
    END
  END w_d[258]
  PIN w_d[259]
    DIRECTION INPUT ;
    USE SIGNAL ;
    PORT
      LAYER M4 ;
        RECT  0 50.064 0.084 50.088 ;
    END
  END w_d[259]
  PIN w_d[25]
    DIRECTION INPUT ;
    USE SIGNAL ;
    PORT
      LAYER M4 ;
        RECT  0 84.432 0.084 84.456 ;
    END
  END w_d[25]
  PIN w_d[260]
    DIRECTION INPUT ;
    USE SIGNAL ;
    PORT
      LAYER M4 ;
        RECT  0 50.16 0.084 50.184 ;
    END
  END w_d[260]
  PIN w_d[261]
    DIRECTION INPUT ;
    USE SIGNAL ;
    PORT
      LAYER M4 ;
        RECT  0 50.256 0.084 50.28 ;
    END
  END w_d[261]
  PIN w_d[262]
    DIRECTION INPUT ;
    USE SIGNAL ;
    PORT
      LAYER M4 ;
        RECT  0 50.352 0.084 50.376 ;
    END
  END w_d[262]
  PIN w_d[263]
    DIRECTION INPUT ;
    USE SIGNAL ;
    PORT
      LAYER M4 ;
        RECT  0 50.448 0.084 50.472 ;
    END
  END w_d[263]
  PIN w_d[264]
    DIRECTION INPUT ;
    USE SIGNAL ;
    PORT
      LAYER M4 ;
        RECT  0 50.544 0.084 50.568 ;
    END
  END w_d[264]
  PIN w_d[265]
    DIRECTION INPUT ;
    USE SIGNAL ;
    PORT
      LAYER M4 ;
        RECT  0 50.64 0.084 50.664 ;
    END
  END w_d[265]
  PIN w_d[266]
    DIRECTION INPUT ;
    USE SIGNAL ;
    PORT
      LAYER M4 ;
        RECT  0 50.736 0.084 50.76 ;
    END
  END w_d[266]
  PIN w_d[267]
    DIRECTION INPUT ;
    USE SIGNAL ;
    PORT
      LAYER M4 ;
        RECT  0 50.832 0.084 50.856 ;
    END
  END w_d[267]
  PIN w_d[268]
    DIRECTION INPUT ;
    USE SIGNAL ;
    PORT
      LAYER M4 ;
        RECT  0 50.928 0.084 50.952 ;
    END
  END w_d[268]
  PIN w_d[269]
    DIRECTION INPUT ;
    USE SIGNAL ;
    PORT
      LAYER M4 ;
        RECT  0 51.024 0.084 51.048 ;
    END
  END w_d[269]
  PIN w_d[26]
    DIRECTION INPUT ;
    USE SIGNAL ;
    PORT
      LAYER M4 ;
        RECT  0 84.528 0.084 84.552 ;
    END
  END w_d[26]
  PIN w_d[270]
    DIRECTION INPUT ;
    USE SIGNAL ;
    PORT
      LAYER M4 ;
        RECT  0 51.12 0.084 51.144 ;
    END
  END w_d[270]
  PIN w_d[271]
    DIRECTION INPUT ;
    USE SIGNAL ;
    PORT
      LAYER M4 ;
        RECT  0 51.216 0.084 51.24 ;
    END
  END w_d[271]
  PIN w_d[272]
    DIRECTION INPUT ;
    USE SIGNAL ;
    PORT
      LAYER M4 ;
        RECT  0 51.312 0.084 51.336 ;
    END
  END w_d[272]
  PIN w_d[273]
    DIRECTION INPUT ;
    USE SIGNAL ;
    PORT
      LAYER M4 ;
        RECT  0 51.408 0.084 51.432 ;
    END
  END w_d[273]
  PIN w_d[274]
    DIRECTION INPUT ;
    USE SIGNAL ;
    PORT
      LAYER M4 ;
        RECT  0 51.504 0.084 51.528 ;
    END
  END w_d[274]
  PIN w_d[275]
    DIRECTION INPUT ;
    USE SIGNAL ;
    PORT
      LAYER M4 ;
        RECT  0 51.6 0.084 51.624 ;
    END
  END w_d[275]
  PIN w_d[276]
    DIRECTION INPUT ;
    USE SIGNAL ;
    PORT
      LAYER M4 ;
        RECT  0 51.696 0.084 51.72 ;
    END
  END w_d[276]
  PIN w_d[277]
    DIRECTION INPUT ;
    USE SIGNAL ;
    PORT
      LAYER M4 ;
        RECT  0 51.792 0.084 51.816 ;
    END
  END w_d[277]
  PIN w_d[278]
    DIRECTION INPUT ;
    USE SIGNAL ;
    PORT
      LAYER M4 ;
        RECT  0 51.888 0.084 51.912 ;
    END
  END w_d[278]
  PIN w_d[279]
    DIRECTION INPUT ;
    USE SIGNAL ;
    PORT
      LAYER M4 ;
        RECT  0 51.984 0.084 52.008 ;
    END
  END w_d[279]
  PIN w_d[27]
    DIRECTION INPUT ;
    USE SIGNAL ;
    PORT
      LAYER M4 ;
        RECT  0 84.624 0.084 84.648 ;
    END
  END w_d[27]
  PIN w_d[280]
    DIRECTION INPUT ;
    USE SIGNAL ;
    PORT
      LAYER M4 ;
        RECT  0 52.08 0.084 52.104 ;
    END
  END w_d[280]
  PIN w_d[281]
    DIRECTION INPUT ;
    USE SIGNAL ;
    PORT
      LAYER M4 ;
        RECT  0 52.176 0.084 52.2 ;
    END
  END w_d[281]
  PIN w_d[282]
    DIRECTION INPUT ;
    USE SIGNAL ;
    PORT
      LAYER M4 ;
        RECT  0 52.272 0.084 52.296 ;
    END
  END w_d[282]
  PIN w_d[283]
    DIRECTION INPUT ;
    USE SIGNAL ;
    PORT
      LAYER M4 ;
        RECT  0 52.368 0.084 52.392 ;
    END
  END w_d[283]
  PIN w_d[284]
    DIRECTION INPUT ;
    USE SIGNAL ;
    PORT
      LAYER M4 ;
        RECT  0 52.464 0.084 52.488 ;
    END
  END w_d[284]
  PIN w_d[285]
    DIRECTION INPUT ;
    USE SIGNAL ;
    PORT
      LAYER M4 ;
        RECT  0 52.56 0.084 52.584 ;
    END
  END w_d[285]
  PIN w_d[286]
    DIRECTION INPUT ;
    USE SIGNAL ;
    PORT
      LAYER M4 ;
        RECT  0 52.656 0.084 52.68 ;
    END
  END w_d[286]
  PIN w_d[287]
    DIRECTION INPUT ;
    USE SIGNAL ;
    PORT
      LAYER M4 ;
        RECT  0 52.752 0.084 52.776 ;
    END
  END w_d[287]
  PIN w_d[288]
    DIRECTION INPUT ;
    USE SIGNAL ;
    PORT
      LAYER M4 ;
        RECT  0 33.648 0.084 33.672 ;
    END
  END w_d[288]
  PIN w_d[289]
    DIRECTION INPUT ;
    USE SIGNAL ;
    PORT
      LAYER M4 ;
        RECT  0 33.744 0.084 33.768 ;
    END
  END w_d[289]
  PIN w_d[28]
    DIRECTION INPUT ;
    USE SIGNAL ;
    PORT
      LAYER M4 ;
        RECT  0 84.72 0.084 84.744 ;
    END
  END w_d[28]
  PIN w_d[290]
    DIRECTION INPUT ;
    USE SIGNAL ;
    PORT
      LAYER M4 ;
        RECT  0 33.84 0.084 33.864 ;
    END
  END w_d[290]
  PIN w_d[291]
    DIRECTION INPUT ;
    USE SIGNAL ;
    PORT
      LAYER M4 ;
        RECT  0 33.936 0.084 33.96 ;
    END
  END w_d[291]
  PIN w_d[292]
    DIRECTION INPUT ;
    USE SIGNAL ;
    PORT
      LAYER M4 ;
        RECT  0 34.032 0.084 34.056 ;
    END
  END w_d[292]
  PIN w_d[293]
    DIRECTION INPUT ;
    USE SIGNAL ;
    PORT
      LAYER M4 ;
        RECT  0 34.128 0.084 34.152 ;
    END
  END w_d[293]
  PIN w_d[294]
    DIRECTION INPUT ;
    USE SIGNAL ;
    PORT
      LAYER M4 ;
        RECT  0 34.224 0.084 34.248 ;
    END
  END w_d[294]
  PIN w_d[295]
    DIRECTION INPUT ;
    USE SIGNAL ;
    PORT
      LAYER M4 ;
        RECT  0 34.32 0.084 34.344 ;
    END
  END w_d[295]
  PIN w_d[296]
    DIRECTION INPUT ;
    USE SIGNAL ;
    PORT
      LAYER M4 ;
        RECT  0 34.416 0.084 34.44 ;
    END
  END w_d[296]
  PIN w_d[297]
    DIRECTION INPUT ;
    USE SIGNAL ;
    PORT
      LAYER M4 ;
        RECT  0 34.512 0.084 34.536 ;
    END
  END w_d[297]
  PIN w_d[298]
    DIRECTION INPUT ;
    USE SIGNAL ;
    PORT
      LAYER M4 ;
        RECT  0 34.608 0.084 34.632 ;
    END
  END w_d[298]
  PIN w_d[299]
    DIRECTION INPUT ;
    USE SIGNAL ;
    PORT
      LAYER M4 ;
        RECT  0 34.704 0.084 34.728 ;
    END
  END w_d[299]
  PIN w_d[29]
    DIRECTION INPUT ;
    USE SIGNAL ;
    PORT
      LAYER M4 ;
        RECT  0 84.816 0.084 84.84 ;
    END
  END w_d[29]
  PIN w_d[2]
    DIRECTION INPUT ;
    USE SIGNAL ;
    PORT
      LAYER M4 ;
        RECT  0 82.224 0.084 82.248 ;
    END
  END w_d[2]
  PIN w_d[300]
    DIRECTION INPUT ;
    USE SIGNAL ;
    PORT
      LAYER M4 ;
        RECT  0 34.8 0.084 34.824 ;
    END
  END w_d[300]
  PIN w_d[301]
    DIRECTION INPUT ;
    USE SIGNAL ;
    PORT
      LAYER M4 ;
        RECT  0 34.896 0.084 34.92 ;
    END
  END w_d[301]
  PIN w_d[302]
    DIRECTION INPUT ;
    USE SIGNAL ;
    PORT
      LAYER M4 ;
        RECT  0 34.992 0.084 35.016 ;
    END
  END w_d[302]
  PIN w_d[303]
    DIRECTION INPUT ;
    USE SIGNAL ;
    PORT
      LAYER M4 ;
        RECT  0 35.088 0.084 35.112 ;
    END
  END w_d[303]
  PIN w_d[304]
    DIRECTION INPUT ;
    USE SIGNAL ;
    PORT
      LAYER M4 ;
        RECT  0 35.184 0.084 35.208 ;
    END
  END w_d[304]
  PIN w_d[305]
    DIRECTION INPUT ;
    USE SIGNAL ;
    PORT
      LAYER M4 ;
        RECT  0 35.28 0.084 35.304 ;
    END
  END w_d[305]
  PIN w_d[306]
    DIRECTION INPUT ;
    USE SIGNAL ;
    PORT
      LAYER M4 ;
        RECT  0 35.376 0.084 35.4 ;
    END
  END w_d[306]
  PIN w_d[307]
    DIRECTION INPUT ;
    USE SIGNAL ;
    PORT
      LAYER M4 ;
        RECT  0 35.472 0.084 35.496 ;
    END
  END w_d[307]
  PIN w_d[308]
    DIRECTION INPUT ;
    USE SIGNAL ;
    PORT
      LAYER M4 ;
        RECT  0 35.568 0.084 35.592 ;
    END
  END w_d[308]
  PIN w_d[309]
    DIRECTION INPUT ;
    USE SIGNAL ;
    PORT
      LAYER M4 ;
        RECT  0 35.664 0.084 35.688 ;
    END
  END w_d[309]
  PIN w_d[30]
    DIRECTION INPUT ;
    USE SIGNAL ;
    PORT
      LAYER M4 ;
        RECT  0 84.912 0.084 84.936 ;
    END
  END w_d[30]
  PIN w_d[310]
    DIRECTION INPUT ;
    USE SIGNAL ;
    PORT
      LAYER M4 ;
        RECT  0 35.76 0.084 35.784 ;
    END
  END w_d[310]
  PIN w_d[311]
    DIRECTION INPUT ;
    USE SIGNAL ;
    PORT
      LAYER M4 ;
        RECT  0 35.856 0.084 35.88 ;
    END
  END w_d[311]
  PIN w_d[312]
    DIRECTION INPUT ;
    USE SIGNAL ;
    PORT
      LAYER M4 ;
        RECT  0 35.952 0.084 35.976 ;
    END
  END w_d[312]
  PIN w_d[313]
    DIRECTION INPUT ;
    USE SIGNAL ;
    PORT
      LAYER M4 ;
        RECT  0 36.048 0.084 36.072 ;
    END
  END w_d[313]
  PIN w_d[314]
    DIRECTION INPUT ;
    USE SIGNAL ;
    PORT
      LAYER M4 ;
        RECT  0 36.144 0.084 36.168 ;
    END
  END w_d[314]
  PIN w_d[315]
    DIRECTION INPUT ;
    USE SIGNAL ;
    PORT
      LAYER M4 ;
        RECT  0 36.24 0.084 36.264 ;
    END
  END w_d[315]
  PIN w_d[316]
    DIRECTION INPUT ;
    USE SIGNAL ;
    PORT
      LAYER M4 ;
        RECT  0 36.336 0.084 36.36 ;
    END
  END w_d[316]
  PIN w_d[317]
    DIRECTION INPUT ;
    USE SIGNAL ;
    PORT
      LAYER M4 ;
        RECT  0 36.432 0.084 36.456 ;
    END
  END w_d[317]
  PIN w_d[318]
    DIRECTION INPUT ;
    USE SIGNAL ;
    PORT
      LAYER M4 ;
        RECT  0 36.528 0.084 36.552 ;
    END
  END w_d[318]
  PIN w_d[319]
    DIRECTION INPUT ;
    USE SIGNAL ;
    PORT
      LAYER M4 ;
        RECT  0 36.624 0.084 36.648 ;
    END
  END w_d[319]
  PIN w_d[31]
    DIRECTION INPUT ;
    USE SIGNAL ;
    PORT
      LAYER M4 ;
        RECT  0 85.008 0.084 85.032 ;
    END
  END w_d[31]
  PIN w_d[320]
    DIRECTION INPUT ;
    USE SIGNAL ;
    PORT
      LAYER M4 ;
        RECT  0 18.288 0.084 18.312 ;
    END
  END w_d[320]
  PIN w_d[321]
    DIRECTION INPUT ;
    USE SIGNAL ;
    PORT
      LAYER M4 ;
        RECT  0 18.384 0.084 18.408 ;
    END
  END w_d[321]
  PIN w_d[322]
    DIRECTION INPUT ;
    USE SIGNAL ;
    PORT
      LAYER M4 ;
        RECT  0 18.48 0.084 18.504 ;
    END
  END w_d[322]
  PIN w_d[323]
    DIRECTION INPUT ;
    USE SIGNAL ;
    PORT
      LAYER M4 ;
        RECT  0 18.576 0.084 18.6 ;
    END
  END w_d[323]
  PIN w_d[324]
    DIRECTION INPUT ;
    USE SIGNAL ;
    PORT
      LAYER M4 ;
        RECT  0 18.672 0.084 18.696 ;
    END
  END w_d[324]
  PIN w_d[325]
    DIRECTION INPUT ;
    USE SIGNAL ;
    PORT
      LAYER M4 ;
        RECT  0 18.768 0.084 18.792 ;
    END
  END w_d[325]
  PIN w_d[326]
    DIRECTION INPUT ;
    USE SIGNAL ;
    PORT
      LAYER M4 ;
        RECT  0 18.864 0.084 18.888 ;
    END
  END w_d[326]
  PIN w_d[327]
    DIRECTION INPUT ;
    USE SIGNAL ;
    PORT
      LAYER M4 ;
        RECT  0 18.96 0.084 18.984 ;
    END
  END w_d[327]
  PIN w_d[328]
    DIRECTION INPUT ;
    USE SIGNAL ;
    PORT
      LAYER M4 ;
        RECT  0 19.056 0.084 19.08 ;
    END
  END w_d[328]
  PIN w_d[329]
    DIRECTION INPUT ;
    USE SIGNAL ;
    PORT
      LAYER M4 ;
        RECT  0 19.152 0.084 19.176 ;
    END
  END w_d[329]
  PIN w_d[32]
    DIRECTION INPUT ;
    USE SIGNAL ;
    PORT
      LAYER M4 ;
        RECT  0 65.904 0.084 65.928 ;
    END
  END w_d[32]
  PIN w_d[330]
    DIRECTION INPUT ;
    USE SIGNAL ;
    PORT
      LAYER M4 ;
        RECT  0 19.248 0.084 19.272 ;
    END
  END w_d[330]
  PIN w_d[331]
    DIRECTION INPUT ;
    USE SIGNAL ;
    PORT
      LAYER M4 ;
        RECT  0 19.344 0.084 19.368 ;
    END
  END w_d[331]
  PIN w_d[332]
    DIRECTION INPUT ;
    USE SIGNAL ;
    PORT
      LAYER M4 ;
        RECT  0 19.44 0.084 19.464 ;
    END
  END w_d[332]
  PIN w_d[333]
    DIRECTION INPUT ;
    USE SIGNAL ;
    PORT
      LAYER M4 ;
        RECT  0 19.536 0.084 19.56 ;
    END
  END w_d[333]
  PIN w_d[334]
    DIRECTION INPUT ;
    USE SIGNAL ;
    PORT
      LAYER M4 ;
        RECT  0 19.632 0.084 19.656 ;
    END
  END w_d[334]
  PIN w_d[335]
    DIRECTION INPUT ;
    USE SIGNAL ;
    PORT
      LAYER M4 ;
        RECT  0 19.728 0.084 19.752 ;
    END
  END w_d[335]
  PIN w_d[336]
    DIRECTION INPUT ;
    USE SIGNAL ;
    PORT
      LAYER M4 ;
        RECT  0 19.824 0.084 19.848 ;
    END
  END w_d[336]
  PIN w_d[337]
    DIRECTION INPUT ;
    USE SIGNAL ;
    PORT
      LAYER M4 ;
        RECT  0 19.92 0.084 19.944 ;
    END
  END w_d[337]
  PIN w_d[338]
    DIRECTION INPUT ;
    USE SIGNAL ;
    PORT
      LAYER M4 ;
        RECT  0 20.016 0.084 20.04 ;
    END
  END w_d[338]
  PIN w_d[339]
    DIRECTION INPUT ;
    USE SIGNAL ;
    PORT
      LAYER M4 ;
        RECT  0 20.112 0.084 20.136 ;
    END
  END w_d[339]
  PIN w_d[33]
    DIRECTION INPUT ;
    USE SIGNAL ;
    PORT
      LAYER M4 ;
        RECT  0 66 0.084 66.024 ;
    END
  END w_d[33]
  PIN w_d[340]
    DIRECTION INPUT ;
    USE SIGNAL ;
    PORT
      LAYER M4 ;
        RECT  0 20.208 0.084 20.232 ;
    END
  END w_d[340]
  PIN w_d[341]
    DIRECTION INPUT ;
    USE SIGNAL ;
    PORT
      LAYER M4 ;
        RECT  0 20.304 0.084 20.328 ;
    END
  END w_d[341]
  PIN w_d[342]
    DIRECTION INPUT ;
    USE SIGNAL ;
    PORT
      LAYER M4 ;
        RECT  0 20.4 0.084 20.424 ;
    END
  END w_d[342]
  PIN w_d[343]
    DIRECTION INPUT ;
    USE SIGNAL ;
    PORT
      LAYER M4 ;
        RECT  0 20.496 0.084 20.52 ;
    END
  END w_d[343]
  PIN w_d[344]
    DIRECTION INPUT ;
    USE SIGNAL ;
    PORT
      LAYER M4 ;
        RECT  0 20.592 0.084 20.616 ;
    END
  END w_d[344]
  PIN w_d[345]
    DIRECTION INPUT ;
    USE SIGNAL ;
    PORT
      LAYER M4 ;
        RECT  0 20.688 0.084 20.712 ;
    END
  END w_d[345]
  PIN w_d[346]
    DIRECTION INPUT ;
    USE SIGNAL ;
    PORT
      LAYER M4 ;
        RECT  0 20.784 0.084 20.808 ;
    END
  END w_d[346]
  PIN w_d[347]
    DIRECTION INPUT ;
    USE SIGNAL ;
    PORT
      LAYER M4 ;
        RECT  0 20.88 0.084 20.904 ;
    END
  END w_d[347]
  PIN w_d[348]
    DIRECTION INPUT ;
    USE SIGNAL ;
    PORT
      LAYER M4 ;
        RECT  0 20.976 0.084 21 ;
    END
  END w_d[348]
  PIN w_d[349]
    DIRECTION INPUT ;
    USE SIGNAL ;
    PORT
      LAYER M4 ;
        RECT  0 21.072 0.084 21.096 ;
    END
  END w_d[349]
  PIN w_d[34]
    DIRECTION INPUT ;
    USE SIGNAL ;
    PORT
      LAYER M4 ;
        RECT  0 66.096 0.084 66.12 ;
    END
  END w_d[34]
  PIN w_d[350]
    DIRECTION INPUT ;
    USE SIGNAL ;
    PORT
      LAYER M4 ;
        RECT  0 21.168 0.084 21.192 ;
    END
  END w_d[350]
  PIN w_d[351]
    DIRECTION INPUT ;
    USE SIGNAL ;
    PORT
      LAYER M4 ;
        RECT  0 21.264 0.084 21.288 ;
    END
  END w_d[351]
  PIN w_d[352]
    DIRECTION INPUT ;
    USE SIGNAL ;
    PORT
      LAYER M4 ;
        RECT  0 11.376 0.084 11.4 ;
    END
  END w_d[352]
  PIN w_d[353]
    DIRECTION INPUT ;
    USE SIGNAL ;
    PORT
      LAYER M4 ;
        RECT  0 11.472 0.084 11.496 ;
    END
  END w_d[353]
  PIN w_d[354]
    DIRECTION INPUT ;
    USE SIGNAL ;
    PORT
      LAYER M4 ;
        RECT  0 11.568 0.084 11.592 ;
    END
  END w_d[354]
  PIN w_d[355]
    DIRECTION INPUT ;
    USE SIGNAL ;
    PORT
      LAYER M4 ;
        RECT  0 11.664 0.084 11.688 ;
    END
  END w_d[355]
  PIN w_d[356]
    DIRECTION INPUT ;
    USE SIGNAL ;
    PORT
      LAYER M4 ;
        RECT  0 11.76 0.084 11.784 ;
    END
  END w_d[356]
  PIN w_d[357]
    DIRECTION INPUT ;
    USE SIGNAL ;
    PORT
      LAYER M4 ;
        RECT  0 11.856 0.084 11.88 ;
    END
  END w_d[357]
  PIN w_d[358]
    DIRECTION INPUT ;
    USE SIGNAL ;
    PORT
      LAYER M4 ;
        RECT  0 11.952 0.084 11.976 ;
    END
  END w_d[358]
  PIN w_d[359]
    DIRECTION INPUT ;
    USE SIGNAL ;
    PORT
      LAYER M4 ;
        RECT  0 12.048 0.084 12.072 ;
    END
  END w_d[359]
  PIN w_d[35]
    DIRECTION INPUT ;
    USE SIGNAL ;
    PORT
      LAYER M4 ;
        RECT  0 66.192 0.084 66.216 ;
    END
  END w_d[35]
  PIN w_d[360]
    DIRECTION INPUT ;
    USE SIGNAL ;
    PORT
      LAYER M4 ;
        RECT  0 12.144 0.084 12.168 ;
    END
  END w_d[360]
  PIN w_d[361]
    DIRECTION INPUT ;
    USE SIGNAL ;
    PORT
      LAYER M4 ;
        RECT  0 12.24 0.084 12.264 ;
    END
  END w_d[361]
  PIN w_d[362]
    DIRECTION INPUT ;
    USE SIGNAL ;
    PORT
      LAYER M4 ;
        RECT  0 12.336 0.084 12.36 ;
    END
  END w_d[362]
  PIN w_d[363]
    DIRECTION INPUT ;
    USE SIGNAL ;
    PORT
      LAYER M4 ;
        RECT  0 12.432 0.084 12.456 ;
    END
  END w_d[363]
  PIN w_d[364]
    DIRECTION INPUT ;
    USE SIGNAL ;
    PORT
      LAYER M4 ;
        RECT  0 12.528 0.084 12.552 ;
    END
  END w_d[364]
  PIN w_d[365]
    DIRECTION INPUT ;
    USE SIGNAL ;
    PORT
      LAYER M4 ;
        RECT  0 12.624 0.084 12.648 ;
    END
  END w_d[365]
  PIN w_d[366]
    DIRECTION INPUT ;
    USE SIGNAL ;
    PORT
      LAYER M4 ;
        RECT  0 12.72 0.084 12.744 ;
    END
  END w_d[366]
  PIN w_d[367]
    DIRECTION INPUT ;
    USE SIGNAL ;
    PORT
      LAYER M4 ;
        RECT  0 12.816 0.084 12.84 ;
    END
  END w_d[367]
  PIN w_d[368]
    DIRECTION INPUT ;
    USE SIGNAL ;
    PORT
      LAYER M4 ;
        RECT  0 12.912 0.084 12.936 ;
    END
  END w_d[368]
  PIN w_d[369]
    DIRECTION INPUT ;
    USE SIGNAL ;
    PORT
      LAYER M4 ;
        RECT  0 13.008 0.084 13.032 ;
    END
  END w_d[369]
  PIN w_d[36]
    DIRECTION INPUT ;
    USE SIGNAL ;
    PORT
      LAYER M4 ;
        RECT  0 66.288 0.084 66.312 ;
    END
  END w_d[36]
  PIN w_d[370]
    DIRECTION INPUT ;
    USE SIGNAL ;
    PORT
      LAYER M4 ;
        RECT  0 13.104 0.084 13.128 ;
    END
  END w_d[370]
  PIN w_d[371]
    DIRECTION INPUT ;
    USE SIGNAL ;
    PORT
      LAYER M4 ;
        RECT  0 13.2 0.084 13.224 ;
    END
  END w_d[371]
  PIN w_d[372]
    DIRECTION INPUT ;
    USE SIGNAL ;
    PORT
      LAYER M4 ;
        RECT  0 13.296 0.084 13.32 ;
    END
  END w_d[372]
  PIN w_d[373]
    DIRECTION INPUT ;
    USE SIGNAL ;
    PORT
      LAYER M4 ;
        RECT  0 13.392 0.084 13.416 ;
    END
  END w_d[373]
  PIN w_d[374]
    DIRECTION INPUT ;
    USE SIGNAL ;
    PORT
      LAYER M4 ;
        RECT  0 13.488 0.084 13.512 ;
    END
  END w_d[374]
  PIN w_d[375]
    DIRECTION INPUT ;
    USE SIGNAL ;
    PORT
      LAYER M4 ;
        RECT  0 13.584 0.084 13.608 ;
    END
  END w_d[375]
  PIN w_d[376]
    DIRECTION INPUT ;
    USE SIGNAL ;
    PORT
      LAYER M4 ;
        RECT  0 13.68 0.084 13.704 ;
    END
  END w_d[376]
  PIN w_d[377]
    DIRECTION INPUT ;
    USE SIGNAL ;
    PORT
      LAYER M4 ;
        RECT  0 13.776 0.084 13.8 ;
    END
  END w_d[377]
  PIN w_d[378]
    DIRECTION INPUT ;
    USE SIGNAL ;
    PORT
      LAYER M4 ;
        RECT  0 13.872 0.084 13.896 ;
    END
  END w_d[378]
  PIN w_d[379]
    DIRECTION INPUT ;
    USE SIGNAL ;
    PORT
      LAYER M4 ;
        RECT  0 13.968 0.084 13.992 ;
    END
  END w_d[379]
  PIN w_d[37]
    DIRECTION INPUT ;
    USE SIGNAL ;
    PORT
      LAYER M4 ;
        RECT  0 66.384 0.084 66.408 ;
    END
  END w_d[37]
  PIN w_d[380]
    DIRECTION INPUT ;
    USE SIGNAL ;
    PORT
      LAYER M4 ;
        RECT  0 14.064 0.084 14.088 ;
    END
  END w_d[380]
  PIN w_d[381]
    DIRECTION INPUT ;
    USE SIGNAL ;
    PORT
      LAYER M4 ;
        RECT  0 14.16 0.084 14.184 ;
    END
  END w_d[381]
  PIN w_d[382]
    DIRECTION INPUT ;
    USE SIGNAL ;
    PORT
      LAYER M4 ;
        RECT  0 14.256 0.084 14.28 ;
    END
  END w_d[382]
  PIN w_d[383]
    DIRECTION INPUT ;
    USE SIGNAL ;
    PORT
      LAYER M4 ;
        RECT  0 14.352 0.084 14.376 ;
    END
  END w_d[383]
  PIN w_d[384]
    DIRECTION INPUT ;
    USE SIGNAL ;
    PORT
      LAYER M4 ;
        RECT  0 21.36 0.084 21.384 ;
    END
  END w_d[384]
  PIN w_d[385]
    DIRECTION INPUT ;
    USE SIGNAL ;
    PORT
      LAYER M4 ;
        RECT  0 21.456 0.084 21.48 ;
    END
  END w_d[385]
  PIN w_d[386]
    DIRECTION INPUT ;
    USE SIGNAL ;
    PORT
      LAYER M4 ;
        RECT  0 21.552 0.084 21.576 ;
    END
  END w_d[386]
  PIN w_d[387]
    DIRECTION INPUT ;
    USE SIGNAL ;
    PORT
      LAYER M4 ;
        RECT  0 21.648 0.084 21.672 ;
    END
  END w_d[387]
  PIN w_d[388]
    DIRECTION INPUT ;
    USE SIGNAL ;
    PORT
      LAYER M4 ;
        RECT  0 21.744 0.084 21.768 ;
    END
  END w_d[388]
  PIN w_d[389]
    DIRECTION INPUT ;
    USE SIGNAL ;
    PORT
      LAYER M4 ;
        RECT  0 21.84 0.084 21.864 ;
    END
  END w_d[389]
  PIN w_d[38]
    DIRECTION INPUT ;
    USE SIGNAL ;
    PORT
      LAYER M4 ;
        RECT  0 66.48 0.084 66.504 ;
    END
  END w_d[38]
  PIN w_d[390]
    DIRECTION INPUT ;
    USE SIGNAL ;
    PORT
      LAYER M4 ;
        RECT  0 21.936 0.084 21.96 ;
    END
  END w_d[390]
  PIN w_d[391]
    DIRECTION INPUT ;
    USE SIGNAL ;
    PORT
      LAYER M4 ;
        RECT  0 22.032 0.084 22.056 ;
    END
  END w_d[391]
  PIN w_d[392]
    DIRECTION INPUT ;
    USE SIGNAL ;
    PORT
      LAYER M4 ;
        RECT  0 22.128 0.084 22.152 ;
    END
  END w_d[392]
  PIN w_d[393]
    DIRECTION INPUT ;
    USE SIGNAL ;
    PORT
      LAYER M4 ;
        RECT  0 22.224 0.084 22.248 ;
    END
  END w_d[393]
  PIN w_d[394]
    DIRECTION INPUT ;
    USE SIGNAL ;
    PORT
      LAYER M4 ;
        RECT  0 22.32 0.084 22.344 ;
    END
  END w_d[394]
  PIN w_d[395]
    DIRECTION INPUT ;
    USE SIGNAL ;
    PORT
      LAYER M4 ;
        RECT  0 22.416 0.084 22.44 ;
    END
  END w_d[395]
  PIN w_d[396]
    DIRECTION INPUT ;
    USE SIGNAL ;
    PORT
      LAYER M4 ;
        RECT  0 22.512 0.084 22.536 ;
    END
  END w_d[396]
  PIN w_d[397]
    DIRECTION INPUT ;
    USE SIGNAL ;
    PORT
      LAYER M4 ;
        RECT  0 22.608 0.084 22.632 ;
    END
  END w_d[397]
  PIN w_d[398]
    DIRECTION INPUT ;
    USE SIGNAL ;
    PORT
      LAYER M4 ;
        RECT  0 22.704 0.084 22.728 ;
    END
  END w_d[398]
  PIN w_d[399]
    DIRECTION INPUT ;
    USE SIGNAL ;
    PORT
      LAYER M4 ;
        RECT  0 22.8 0.084 22.824 ;
    END
  END w_d[399]
  PIN w_d[39]
    DIRECTION INPUT ;
    USE SIGNAL ;
    PORT
      LAYER M4 ;
        RECT  0 66.576 0.084 66.6 ;
    END
  END w_d[39]
  PIN w_d[3]
    DIRECTION INPUT ;
    USE SIGNAL ;
    PORT
      LAYER M4 ;
        RECT  0 82.32 0.084 82.344 ;
    END
  END w_d[3]
  PIN w_d[400]
    DIRECTION INPUT ;
    USE SIGNAL ;
    PORT
      LAYER M4 ;
        RECT  0 22.896 0.084 22.92 ;
    END
  END w_d[400]
  PIN w_d[401]
    DIRECTION INPUT ;
    USE SIGNAL ;
    PORT
      LAYER M4 ;
        RECT  0 22.992 0.084 23.016 ;
    END
  END w_d[401]
  PIN w_d[402]
    DIRECTION INPUT ;
    USE SIGNAL ;
    PORT
      LAYER M4 ;
        RECT  0 23.088 0.084 23.112 ;
    END
  END w_d[402]
  PIN w_d[403]
    DIRECTION INPUT ;
    USE SIGNAL ;
    PORT
      LAYER M4 ;
        RECT  0 23.184 0.084 23.208 ;
    END
  END w_d[403]
  PIN w_d[404]
    DIRECTION INPUT ;
    USE SIGNAL ;
    PORT
      LAYER M4 ;
        RECT  0 23.28 0.084 23.304 ;
    END
  END w_d[404]
  PIN w_d[405]
    DIRECTION INPUT ;
    USE SIGNAL ;
    PORT
      LAYER M4 ;
        RECT  0 23.376 0.084 23.4 ;
    END
  END w_d[405]
  PIN w_d[406]
    DIRECTION INPUT ;
    USE SIGNAL ;
    PORT
      LAYER M4 ;
        RECT  0 23.472 0.084 23.496 ;
    END
  END w_d[406]
  PIN w_d[407]
    DIRECTION INPUT ;
    USE SIGNAL ;
    PORT
      LAYER M4 ;
        RECT  0 23.568 0.084 23.592 ;
    END
  END w_d[407]
  PIN w_d[408]
    DIRECTION INPUT ;
    USE SIGNAL ;
    PORT
      LAYER M4 ;
        RECT  0 23.664 0.084 23.688 ;
    END
  END w_d[408]
  PIN w_d[409]
    DIRECTION INPUT ;
    USE SIGNAL ;
    PORT
      LAYER M4 ;
        RECT  0 23.76 0.084 23.784 ;
    END
  END w_d[409]
  PIN w_d[40]
    DIRECTION INPUT ;
    USE SIGNAL ;
    PORT
      LAYER M4 ;
        RECT  0 66.672 0.084 66.696 ;
    END
  END w_d[40]
  PIN w_d[410]
    DIRECTION INPUT ;
    USE SIGNAL ;
    PORT
      LAYER M4 ;
        RECT  0 23.856 0.084 23.88 ;
    END
  END w_d[410]
  PIN w_d[411]
    DIRECTION INPUT ;
    USE SIGNAL ;
    PORT
      LAYER M4 ;
        RECT  0 23.952 0.084 23.976 ;
    END
  END w_d[411]
  PIN w_d[412]
    DIRECTION INPUT ;
    USE SIGNAL ;
    PORT
      LAYER M4 ;
        RECT  0 24.048 0.084 24.072 ;
    END
  END w_d[412]
  PIN w_d[413]
    DIRECTION INPUT ;
    USE SIGNAL ;
    PORT
      LAYER M4 ;
        RECT  0 24.144 0.084 24.168 ;
    END
  END w_d[413]
  PIN w_d[414]
    DIRECTION INPUT ;
    USE SIGNAL ;
    PORT
      LAYER M4 ;
        RECT  0 24.24 0.084 24.264 ;
    END
  END w_d[414]
  PIN w_d[415]
    DIRECTION INPUT ;
    USE SIGNAL ;
    PORT
      LAYER M4 ;
        RECT  0 24.336 0.084 24.36 ;
    END
  END w_d[415]
  PIN w_d[416]
    DIRECTION INPUT ;
    USE SIGNAL ;
    PORT
      LAYER M4 ;
        RECT  0 14.448 0.084 14.472 ;
    END
  END w_d[416]
  PIN w_d[417]
    DIRECTION INPUT ;
    USE SIGNAL ;
    PORT
      LAYER M4 ;
        RECT  0 14.544 0.084 14.568 ;
    END
  END w_d[417]
  PIN w_d[418]
    DIRECTION INPUT ;
    USE SIGNAL ;
    PORT
      LAYER M4 ;
        RECT  0 14.64 0.084 14.664 ;
    END
  END w_d[418]
  PIN w_d[419]
    DIRECTION INPUT ;
    USE SIGNAL ;
    PORT
      LAYER M4 ;
        RECT  0 14.736 0.084 14.76 ;
    END
  END w_d[419]
  PIN w_d[41]
    DIRECTION INPUT ;
    USE SIGNAL ;
    PORT
      LAYER M4 ;
        RECT  0 66.768 0.084 66.792 ;
    END
  END w_d[41]
  PIN w_d[420]
    DIRECTION INPUT ;
    USE SIGNAL ;
    PORT
      LAYER M4 ;
        RECT  0 14.832 0.084 14.856 ;
    END
  END w_d[420]
  PIN w_d[421]
    DIRECTION INPUT ;
    USE SIGNAL ;
    PORT
      LAYER M4 ;
        RECT  0 14.928 0.084 14.952 ;
    END
  END w_d[421]
  PIN w_d[422]
    DIRECTION INPUT ;
    USE SIGNAL ;
    PORT
      LAYER M4 ;
        RECT  0 15.024 0.084 15.048 ;
    END
  END w_d[422]
  PIN w_d[423]
    DIRECTION INPUT ;
    USE SIGNAL ;
    PORT
      LAYER M4 ;
        RECT  0 15.12 0.084 15.144 ;
    END
  END w_d[423]
  PIN w_d[424]
    DIRECTION INPUT ;
    USE SIGNAL ;
    PORT
      LAYER M4 ;
        RECT  0 15.216 0.084 15.24 ;
    END
  END w_d[424]
  PIN w_d[425]
    DIRECTION INPUT ;
    USE SIGNAL ;
    PORT
      LAYER M4 ;
        RECT  0 15.312 0.084 15.336 ;
    END
  END w_d[425]
  PIN w_d[426]
    DIRECTION INPUT ;
    USE SIGNAL ;
    PORT
      LAYER M4 ;
        RECT  0 15.408 0.084 15.432 ;
    END
  END w_d[426]
  PIN w_d[427]
    DIRECTION INPUT ;
    USE SIGNAL ;
    PORT
      LAYER M4 ;
        RECT  0 15.504 0.084 15.528 ;
    END
  END w_d[427]
  PIN w_d[428]
    DIRECTION INPUT ;
    USE SIGNAL ;
    PORT
      LAYER M4 ;
        RECT  0 15.6 0.084 15.624 ;
    END
  END w_d[428]
  PIN w_d[429]
    DIRECTION INPUT ;
    USE SIGNAL ;
    PORT
      LAYER M4 ;
        RECT  0 15.696 0.084 15.72 ;
    END
  END w_d[429]
  PIN w_d[42]
    DIRECTION INPUT ;
    USE SIGNAL ;
    PORT
      LAYER M4 ;
        RECT  0 66.864 0.084 66.888 ;
    END
  END w_d[42]
  PIN w_d[430]
    DIRECTION INPUT ;
    USE SIGNAL ;
    PORT
      LAYER M4 ;
        RECT  0 15.792 0.084 15.816 ;
    END
  END w_d[430]
  PIN w_d[431]
    DIRECTION INPUT ;
    USE SIGNAL ;
    PORT
      LAYER M4 ;
        RECT  0 15.888 0.084 15.912 ;
    END
  END w_d[431]
  PIN w_d[432]
    DIRECTION INPUT ;
    USE SIGNAL ;
    PORT
      LAYER M4 ;
        RECT  0 15.984 0.084 16.008 ;
    END
  END w_d[432]
  PIN w_d[433]
    DIRECTION INPUT ;
    USE SIGNAL ;
    PORT
      LAYER M4 ;
        RECT  0 16.08 0.084 16.104 ;
    END
  END w_d[433]
  PIN w_d[434]
    DIRECTION INPUT ;
    USE SIGNAL ;
    PORT
      LAYER M4 ;
        RECT  0 16.176 0.084 16.2 ;
    END
  END w_d[434]
  PIN w_d[435]
    DIRECTION INPUT ;
    USE SIGNAL ;
    PORT
      LAYER M4 ;
        RECT  0 16.272 0.084 16.296 ;
    END
  END w_d[435]
  PIN w_d[436]
    DIRECTION INPUT ;
    USE SIGNAL ;
    PORT
      LAYER M4 ;
        RECT  0 16.368 0.084 16.392 ;
    END
  END w_d[436]
  PIN w_d[437]
    DIRECTION INPUT ;
    USE SIGNAL ;
    PORT
      LAYER M4 ;
        RECT  0 16.464 0.084 16.488 ;
    END
  END w_d[437]
  PIN w_d[438]
    DIRECTION INPUT ;
    USE SIGNAL ;
    PORT
      LAYER M4 ;
        RECT  0 16.56 0.084 16.584 ;
    END
  END w_d[438]
  PIN w_d[439]
    DIRECTION INPUT ;
    USE SIGNAL ;
    PORT
      LAYER M4 ;
        RECT  0 16.656 0.084 16.68 ;
    END
  END w_d[439]
  PIN w_d[43]
    DIRECTION INPUT ;
    USE SIGNAL ;
    PORT
      LAYER M4 ;
        RECT  0 66.96 0.084 66.984 ;
    END
  END w_d[43]
  PIN w_d[440]
    DIRECTION INPUT ;
    USE SIGNAL ;
    PORT
      LAYER M4 ;
        RECT  0 16.752 0.084 16.776 ;
    END
  END w_d[440]
  PIN w_d[441]
    DIRECTION INPUT ;
    USE SIGNAL ;
    PORT
      LAYER M4 ;
        RECT  0 16.848 0.084 16.872 ;
    END
  END w_d[441]
  PIN w_d[442]
    DIRECTION INPUT ;
    USE SIGNAL ;
    PORT
      LAYER M4 ;
        RECT  0 16.944 0.084 16.968 ;
    END
  END w_d[442]
  PIN w_d[443]
    DIRECTION INPUT ;
    USE SIGNAL ;
    PORT
      LAYER M4 ;
        RECT  0 17.04 0.084 17.064 ;
    END
  END w_d[443]
  PIN w_d[444]
    DIRECTION INPUT ;
    USE SIGNAL ;
    PORT
      LAYER M4 ;
        RECT  0 17.136 0.084 17.16 ;
    END
  END w_d[444]
  PIN w_d[445]
    DIRECTION INPUT ;
    USE SIGNAL ;
    PORT
      LAYER M4 ;
        RECT  0 17.232 0.084 17.256 ;
    END
  END w_d[445]
  PIN w_d[446]
    DIRECTION INPUT ;
    USE SIGNAL ;
    PORT
      LAYER M4 ;
        RECT  0 17.328 0.084 17.352 ;
    END
  END w_d[446]
  PIN w_d[447]
    DIRECTION INPUT ;
    USE SIGNAL ;
    PORT
      LAYER M4 ;
        RECT  0 17.424 0.084 17.448 ;
    END
  END w_d[447]
  PIN w_d[448]
    DIRECTION INPUT ;
    USE SIGNAL ;
    PORT
      LAYER M4 ;
        RECT  0 8.304 0.084 8.328 ;
    END
  END w_d[448]
  PIN w_d[449]
    DIRECTION INPUT ;
    USE SIGNAL ;
    PORT
      LAYER M4 ;
        RECT  0 8.4 0.084 8.424 ;
    END
  END w_d[449]
  PIN w_d[44]
    DIRECTION INPUT ;
    USE SIGNAL ;
    PORT
      LAYER M4 ;
        RECT  0 67.056 0.084 67.08 ;
    END
  END w_d[44]
  PIN w_d[450]
    DIRECTION INPUT ;
    USE SIGNAL ;
    PORT
      LAYER M4 ;
        RECT  0 8.496 0.084 8.52 ;
    END
  END w_d[450]
  PIN w_d[451]
    DIRECTION INPUT ;
    USE SIGNAL ;
    PORT
      LAYER M4 ;
        RECT  0 8.592 0.084 8.616 ;
    END
  END w_d[451]
  PIN w_d[452]
    DIRECTION INPUT ;
    USE SIGNAL ;
    PORT
      LAYER M4 ;
        RECT  0 8.688 0.084 8.712 ;
    END
  END w_d[452]
  PIN w_d[453]
    DIRECTION INPUT ;
    USE SIGNAL ;
    PORT
      LAYER M4 ;
        RECT  0 8.784 0.084 8.808 ;
    END
  END w_d[453]
  PIN w_d[454]
    DIRECTION INPUT ;
    USE SIGNAL ;
    PORT
      LAYER M4 ;
        RECT  0 8.88 0.084 8.904 ;
    END
  END w_d[454]
  PIN w_d[455]
    DIRECTION INPUT ;
    USE SIGNAL ;
    PORT
      LAYER M4 ;
        RECT  0 8.976 0.084 9 ;
    END
  END w_d[455]
  PIN w_d[456]
    DIRECTION INPUT ;
    USE SIGNAL ;
    PORT
      LAYER M4 ;
        RECT  0 9.072 0.084 9.096 ;
    END
  END w_d[456]
  PIN w_d[457]
    DIRECTION INPUT ;
    USE SIGNAL ;
    PORT
      LAYER M4 ;
        RECT  0 9.168 0.084 9.192 ;
    END
  END w_d[457]
  PIN w_d[458]
    DIRECTION INPUT ;
    USE SIGNAL ;
    PORT
      LAYER M4 ;
        RECT  0 9.264 0.084 9.288 ;
    END
  END w_d[458]
  PIN w_d[459]
    DIRECTION INPUT ;
    USE SIGNAL ;
    PORT
      LAYER M4 ;
        RECT  0 9.36 0.084 9.384 ;
    END
  END w_d[459]
  PIN w_d[45]
    DIRECTION INPUT ;
    USE SIGNAL ;
    PORT
      LAYER M4 ;
        RECT  0 67.152 0.084 67.176 ;
    END
  END w_d[45]
  PIN w_d[460]
    DIRECTION INPUT ;
    USE SIGNAL ;
    PORT
      LAYER M4 ;
        RECT  0 9.456 0.084 9.48 ;
    END
  END w_d[460]
  PIN w_d[461]
    DIRECTION INPUT ;
    USE SIGNAL ;
    PORT
      LAYER M4 ;
        RECT  0 9.552 0.084 9.576 ;
    END
  END w_d[461]
  PIN w_d[462]
    DIRECTION INPUT ;
    USE SIGNAL ;
    PORT
      LAYER M4 ;
        RECT  0 9.648 0.084 9.672 ;
    END
  END w_d[462]
  PIN w_d[463]
    DIRECTION INPUT ;
    USE SIGNAL ;
    PORT
      LAYER M4 ;
        RECT  0 9.744 0.084 9.768 ;
    END
  END w_d[463]
  PIN w_d[464]
    DIRECTION INPUT ;
    USE SIGNAL ;
    PORT
      LAYER M4 ;
        RECT  0 9.84 0.084 9.864 ;
    END
  END w_d[464]
  PIN w_d[465]
    DIRECTION INPUT ;
    USE SIGNAL ;
    PORT
      LAYER M4 ;
        RECT  0 9.936 0.084 9.96 ;
    END
  END w_d[465]
  PIN w_d[466]
    DIRECTION INPUT ;
    USE SIGNAL ;
    PORT
      LAYER M4 ;
        RECT  0 10.032 0.084 10.056 ;
    END
  END w_d[466]
  PIN w_d[467]
    DIRECTION INPUT ;
    USE SIGNAL ;
    PORT
      LAYER M4 ;
        RECT  0 10.128 0.084 10.152 ;
    END
  END w_d[467]
  PIN w_d[468]
    DIRECTION INPUT ;
    USE SIGNAL ;
    PORT
      LAYER M4 ;
        RECT  0 10.224 0.084 10.248 ;
    END
  END w_d[468]
  PIN w_d[469]
    DIRECTION INPUT ;
    USE SIGNAL ;
    PORT
      LAYER M4 ;
        RECT  0 10.32 0.084 10.344 ;
    END
  END w_d[469]
  PIN w_d[46]
    DIRECTION INPUT ;
    USE SIGNAL ;
    PORT
      LAYER M4 ;
        RECT  0 67.248 0.084 67.272 ;
    END
  END w_d[46]
  PIN w_d[470]
    DIRECTION INPUT ;
    USE SIGNAL ;
    PORT
      LAYER M4 ;
        RECT  0 10.416 0.084 10.44 ;
    END
  END w_d[470]
  PIN w_d[471]
    DIRECTION INPUT ;
    USE SIGNAL ;
    PORT
      LAYER M4 ;
        RECT  0 10.512 0.084 10.536 ;
    END
  END w_d[471]
  PIN w_d[472]
    DIRECTION INPUT ;
    USE SIGNAL ;
    PORT
      LAYER M4 ;
        RECT  0 10.608 0.084 10.632 ;
    END
  END w_d[472]
  PIN w_d[473]
    DIRECTION INPUT ;
    USE SIGNAL ;
    PORT
      LAYER M4 ;
        RECT  0 10.704 0.084 10.728 ;
    END
  END w_d[473]
  PIN w_d[474]
    DIRECTION INPUT ;
    USE SIGNAL ;
    PORT
      LAYER M4 ;
        RECT  0 10.8 0.084 10.824 ;
    END
  END w_d[474]
  PIN w_d[475]
    DIRECTION INPUT ;
    USE SIGNAL ;
    PORT
      LAYER M4 ;
        RECT  0 10.896 0.084 10.92 ;
    END
  END w_d[475]
  PIN w_d[476]
    DIRECTION INPUT ;
    USE SIGNAL ;
    PORT
      LAYER M4 ;
        RECT  0 10.992 0.084 11.016 ;
    END
  END w_d[476]
  PIN w_d[477]
    DIRECTION INPUT ;
    USE SIGNAL ;
    PORT
      LAYER M4 ;
        RECT  0 11.088 0.084 11.112 ;
    END
  END w_d[477]
  PIN w_d[478]
    DIRECTION INPUT ;
    USE SIGNAL ;
    PORT
      LAYER M4 ;
        RECT  0 11.184 0.084 11.208 ;
    END
  END w_d[478]
  PIN w_d[479]
    DIRECTION INPUT ;
    USE SIGNAL ;
    PORT
      LAYER M4 ;
        RECT  0 11.28 0.084 11.304 ;
    END
  END w_d[479]
  PIN w_d[47]
    DIRECTION INPUT ;
    USE SIGNAL ;
    PORT
      LAYER M4 ;
        RECT  0 67.344 0.084 67.368 ;
    END
  END w_d[47]
  PIN w_d[480]
    DIRECTION INPUT ;
    USE SIGNAL ;
    PORT
      LAYER M4 ;
        RECT  0 27.504 0.084 27.528 ;
    END
  END w_d[480]
  PIN w_d[481]
    DIRECTION INPUT ;
    USE SIGNAL ;
    PORT
      LAYER M4 ;
        RECT  0 27.6 0.084 27.624 ;
    END
  END w_d[481]
  PIN w_d[482]
    DIRECTION INPUT ;
    USE SIGNAL ;
    PORT
      LAYER M4 ;
        RECT  0 27.696 0.084 27.72 ;
    END
  END w_d[482]
  PIN w_d[483]
    DIRECTION INPUT ;
    USE SIGNAL ;
    PORT
      LAYER M4 ;
        RECT  0 27.792 0.084 27.816 ;
    END
  END w_d[483]
  PIN w_d[484]
    DIRECTION INPUT ;
    USE SIGNAL ;
    PORT
      LAYER M4 ;
        RECT  0 27.888 0.084 27.912 ;
    END
  END w_d[484]
  PIN w_d[485]
    DIRECTION INPUT ;
    USE SIGNAL ;
    PORT
      LAYER M4 ;
        RECT  0 27.984 0.084 28.008 ;
    END
  END w_d[485]
  PIN w_d[486]
    DIRECTION INPUT ;
    USE SIGNAL ;
    PORT
      LAYER M4 ;
        RECT  0 28.08 0.084 28.104 ;
    END
  END w_d[486]
  PIN w_d[487]
    DIRECTION INPUT ;
    USE SIGNAL ;
    PORT
      LAYER M4 ;
        RECT  0 28.176 0.084 28.2 ;
    END
  END w_d[487]
  PIN w_d[488]
    DIRECTION INPUT ;
    USE SIGNAL ;
    PORT
      LAYER M4 ;
        RECT  0 28.272 0.084 28.296 ;
    END
  END w_d[488]
  PIN w_d[489]
    DIRECTION INPUT ;
    USE SIGNAL ;
    PORT
      LAYER M4 ;
        RECT  0 28.368 0.084 28.392 ;
    END
  END w_d[489]
  PIN w_d[48]
    DIRECTION INPUT ;
    USE SIGNAL ;
    PORT
      LAYER M4 ;
        RECT  0 67.44 0.084 67.464 ;
    END
  END w_d[48]
  PIN w_d[490]
    DIRECTION INPUT ;
    USE SIGNAL ;
    PORT
      LAYER M4 ;
        RECT  0 28.464 0.084 28.488 ;
    END
  END w_d[490]
  PIN w_d[491]
    DIRECTION INPUT ;
    USE SIGNAL ;
    PORT
      LAYER M4 ;
        RECT  0 28.56 0.084 28.584 ;
    END
  END w_d[491]
  PIN w_d[492]
    DIRECTION INPUT ;
    USE SIGNAL ;
    PORT
      LAYER M4 ;
        RECT  0 28.656 0.084 28.68 ;
    END
  END w_d[492]
  PIN w_d[493]
    DIRECTION INPUT ;
    USE SIGNAL ;
    PORT
      LAYER M4 ;
        RECT  0 28.752 0.084 28.776 ;
    END
  END w_d[493]
  PIN w_d[494]
    DIRECTION INPUT ;
    USE SIGNAL ;
    PORT
      LAYER M4 ;
        RECT  0 28.848 0.084 28.872 ;
    END
  END w_d[494]
  PIN w_d[495]
    DIRECTION INPUT ;
    USE SIGNAL ;
    PORT
      LAYER M4 ;
        RECT  0 28.944 0.084 28.968 ;
    END
  END w_d[495]
  PIN w_d[496]
    DIRECTION INPUT ;
    USE SIGNAL ;
    PORT
      LAYER M4 ;
        RECT  0 29.04 0.084 29.064 ;
    END
  END w_d[496]
  PIN w_d[497]
    DIRECTION INPUT ;
    USE SIGNAL ;
    PORT
      LAYER M4 ;
        RECT  0 29.136 0.084 29.16 ;
    END
  END w_d[497]
  PIN w_d[498]
    DIRECTION INPUT ;
    USE SIGNAL ;
    PORT
      LAYER M4 ;
        RECT  0 29.232 0.084 29.256 ;
    END
  END w_d[498]
  PIN w_d[499]
    DIRECTION INPUT ;
    USE SIGNAL ;
    PORT
      LAYER M4 ;
        RECT  0 29.328 0.084 29.352 ;
    END
  END w_d[499]
  PIN w_d[49]
    DIRECTION INPUT ;
    USE SIGNAL ;
    PORT
      LAYER M4 ;
        RECT  0 67.536 0.084 67.56 ;
    END
  END w_d[49]
  PIN w_d[4]
    DIRECTION INPUT ;
    USE SIGNAL ;
    PORT
      LAYER M4 ;
        RECT  0 82.416 0.084 82.44 ;
    END
  END w_d[4]
  PIN w_d[500]
    DIRECTION INPUT ;
    USE SIGNAL ;
    PORT
      LAYER M4 ;
        RECT  0 29.424 0.084 29.448 ;
    END
  END w_d[500]
  PIN w_d[501]
    DIRECTION INPUT ;
    USE SIGNAL ;
    PORT
      LAYER M4 ;
        RECT  0 29.52 0.084 29.544 ;
    END
  END w_d[501]
  PIN w_d[502]
    DIRECTION INPUT ;
    USE SIGNAL ;
    PORT
      LAYER M4 ;
        RECT  0 29.616 0.084 29.64 ;
    END
  END w_d[502]
  PIN w_d[503]
    DIRECTION INPUT ;
    USE SIGNAL ;
    PORT
      LAYER M4 ;
        RECT  0 29.712 0.084 29.736 ;
    END
  END w_d[503]
  PIN w_d[504]
    DIRECTION INPUT ;
    USE SIGNAL ;
    PORT
      LAYER M4 ;
        RECT  0 29.808 0.084 29.832 ;
    END
  END w_d[504]
  PIN w_d[505]
    DIRECTION INPUT ;
    USE SIGNAL ;
    PORT
      LAYER M4 ;
        RECT  0 29.904 0.084 29.928 ;
    END
  END w_d[505]
  PIN w_d[506]
    DIRECTION INPUT ;
    USE SIGNAL ;
    PORT
      LAYER M4 ;
        RECT  0 30 0.084 30.024 ;
    END
  END w_d[506]
  PIN w_d[507]
    DIRECTION INPUT ;
    USE SIGNAL ;
    PORT
      LAYER M4 ;
        RECT  0 30.096 0.084 30.12 ;
    END
  END w_d[507]
  PIN w_d[508]
    DIRECTION INPUT ;
    USE SIGNAL ;
    PORT
      LAYER M4 ;
        RECT  0 30.192 0.084 30.216 ;
    END
  END w_d[508]
  PIN w_d[509]
    DIRECTION INPUT ;
    USE SIGNAL ;
    PORT
      LAYER M4 ;
        RECT  0 30.288 0.084 30.312 ;
    END
  END w_d[509]
  PIN w_d[50]
    DIRECTION INPUT ;
    USE SIGNAL ;
    PORT
      LAYER M4 ;
        RECT  0 67.632 0.084 67.656 ;
    END
  END w_d[50]
  PIN w_d[510]
    DIRECTION INPUT ;
    USE SIGNAL ;
    PORT
      LAYER M4 ;
        RECT  0 30.384 0.084 30.408 ;
    END
  END w_d[510]
  PIN w_d[511]
    DIRECTION INPUT ;
    USE SIGNAL ;
    PORT
      LAYER M4 ;
        RECT  0 30.48 0.084 30.504 ;
    END
  END w_d[511]
  PIN w_d[51]
    DIRECTION INPUT ;
    USE SIGNAL ;
    PORT
      LAYER M4 ;
        RECT  0 67.728 0.084 67.752 ;
    END
  END w_d[51]
  PIN w_d[52]
    DIRECTION INPUT ;
    USE SIGNAL ;
    PORT
      LAYER M4 ;
        RECT  0 67.824 0.084 67.848 ;
    END
  END w_d[52]
  PIN w_d[53]
    DIRECTION INPUT ;
    USE SIGNAL ;
    PORT
      LAYER M4 ;
        RECT  0 67.92 0.084 67.944 ;
    END
  END w_d[53]
  PIN w_d[54]
    DIRECTION INPUT ;
    USE SIGNAL ;
    PORT
      LAYER M4 ;
        RECT  0 68.016 0.084 68.04 ;
    END
  END w_d[54]
  PIN w_d[55]
    DIRECTION INPUT ;
    USE SIGNAL ;
    PORT
      LAYER M4 ;
        RECT  0 68.112 0.084 68.136 ;
    END
  END w_d[55]
  PIN w_d[56]
    DIRECTION INPUT ;
    USE SIGNAL ;
    PORT
      LAYER M4 ;
        RECT  0 68.208 0.084 68.232 ;
    END
  END w_d[56]
  PIN w_d[57]
    DIRECTION INPUT ;
    USE SIGNAL ;
    PORT
      LAYER M4 ;
        RECT  0 68.304 0.084 68.328 ;
    END
  END w_d[57]
  PIN w_d[58]
    DIRECTION INPUT ;
    USE SIGNAL ;
    PORT
      LAYER M4 ;
        RECT  0 68.4 0.084 68.424 ;
    END
  END w_d[58]
  PIN w_d[59]
    DIRECTION INPUT ;
    USE SIGNAL ;
    PORT
      LAYER M4 ;
        RECT  0 68.496 0.084 68.52 ;
    END
  END w_d[59]
  PIN w_d[5]
    DIRECTION INPUT ;
    USE SIGNAL ;
    PORT
      LAYER M4 ;
        RECT  0 82.512 0.084 82.536 ;
    END
  END w_d[5]
  PIN w_d[60]
    DIRECTION INPUT ;
    USE SIGNAL ;
    PORT
      LAYER M4 ;
        RECT  0 68.592 0.084 68.616 ;
    END
  END w_d[60]
  PIN w_d[61]
    DIRECTION INPUT ;
    USE SIGNAL ;
    PORT
      LAYER M4 ;
        RECT  0 68.688 0.084 68.712 ;
    END
  END w_d[61]
  PIN w_d[62]
    DIRECTION INPUT ;
    USE SIGNAL ;
    PORT
      LAYER M4 ;
        RECT  0 68.784 0.084 68.808 ;
    END
  END w_d[62]
  PIN w_d[63]
    DIRECTION INPUT ;
    USE SIGNAL ;
    PORT
      LAYER M4 ;
        RECT  0 68.88 0.084 68.904 ;
    END
  END w_d[63]
  PIN w_d[64]
    DIRECTION INPUT ;
    USE SIGNAL ;
    PORT
      LAYER M4 ;
        RECT  0 37.488 0.084 37.512 ;
    END
  END w_d[64]
  PIN w_d[65]
    DIRECTION INPUT ;
    USE SIGNAL ;
    PORT
      LAYER M4 ;
        RECT  0 37.584 0.084 37.608 ;
    END
  END w_d[65]
  PIN w_d[66]
    DIRECTION INPUT ;
    USE SIGNAL ;
    PORT
      LAYER M4 ;
        RECT  0 37.68 0.084 37.704 ;
    END
  END w_d[66]
  PIN w_d[67]
    DIRECTION INPUT ;
    USE SIGNAL ;
    PORT
      LAYER M4 ;
        RECT  0 37.776 0.084 37.8 ;
    END
  END w_d[67]
  PIN w_d[68]
    DIRECTION INPUT ;
    USE SIGNAL ;
    PORT
      LAYER M4 ;
        RECT  0 37.872 0.084 37.896 ;
    END
  END w_d[68]
  PIN w_d[69]
    DIRECTION INPUT ;
    USE SIGNAL ;
    PORT
      LAYER M4 ;
        RECT  0 37.968 0.084 37.992 ;
    END
  END w_d[69]
  PIN w_d[6]
    DIRECTION INPUT ;
    USE SIGNAL ;
    PORT
      LAYER M4 ;
        RECT  0 82.608 0.084 82.632 ;
    END
  END w_d[6]
  PIN w_d[70]
    DIRECTION INPUT ;
    USE SIGNAL ;
    PORT
      LAYER M4 ;
        RECT  0 38.064 0.084 38.088 ;
    END
  END w_d[70]
  PIN w_d[71]
    DIRECTION INPUT ;
    USE SIGNAL ;
    PORT
      LAYER M4 ;
        RECT  0 38.16 0.084 38.184 ;
    END
  END w_d[71]
  PIN w_d[72]
    DIRECTION INPUT ;
    USE SIGNAL ;
    PORT
      LAYER M4 ;
        RECT  0 38.256 0.084 38.28 ;
    END
  END w_d[72]
  PIN w_d[73]
    DIRECTION INPUT ;
    USE SIGNAL ;
    PORT
      LAYER M4 ;
        RECT  0 38.352 0.084 38.376 ;
    END
  END w_d[73]
  PIN w_d[74]
    DIRECTION INPUT ;
    USE SIGNAL ;
    PORT
      LAYER M4 ;
        RECT  0 38.448 0.084 38.472 ;
    END
  END w_d[74]
  PIN w_d[75]
    DIRECTION INPUT ;
    USE SIGNAL ;
    PORT
      LAYER M4 ;
        RECT  0 38.544 0.084 38.568 ;
    END
  END w_d[75]
  PIN w_d[76]
    DIRECTION INPUT ;
    USE SIGNAL ;
    PORT
      LAYER M4 ;
        RECT  0 38.64 0.084 38.664 ;
    END
  END w_d[76]
  PIN w_d[77]
    DIRECTION INPUT ;
    USE SIGNAL ;
    PORT
      LAYER M4 ;
        RECT  0 38.736 0.084 38.76 ;
    END
  END w_d[77]
  PIN w_d[78]
    DIRECTION INPUT ;
    USE SIGNAL ;
    PORT
      LAYER M4 ;
        RECT  0 38.832 0.084 38.856 ;
    END
  END w_d[78]
  PIN w_d[79]
    DIRECTION INPUT ;
    USE SIGNAL ;
    PORT
      LAYER M4 ;
        RECT  0 38.928 0.084 38.952 ;
    END
  END w_d[79]
  PIN w_d[7]
    DIRECTION INPUT ;
    USE SIGNAL ;
    PORT
      LAYER M4 ;
        RECT  0 82.704 0.084 82.728 ;
    END
  END w_d[7]
  PIN w_d[80]
    DIRECTION INPUT ;
    USE SIGNAL ;
    PORT
      LAYER M4 ;
        RECT  0 39.024 0.084 39.048 ;
    END
  END w_d[80]
  PIN w_d[81]
    DIRECTION INPUT ;
    USE SIGNAL ;
    PORT
      LAYER M4 ;
        RECT  0 39.12 0.084 39.144 ;
    END
  END w_d[81]
  PIN w_d[82]
    DIRECTION INPUT ;
    USE SIGNAL ;
    PORT
      LAYER M4 ;
        RECT  0 39.216 0.084 39.24 ;
    END
  END w_d[82]
  PIN w_d[83]
    DIRECTION INPUT ;
    USE SIGNAL ;
    PORT
      LAYER M4 ;
        RECT  0 39.312 0.084 39.336 ;
    END
  END w_d[83]
  PIN w_d[84]
    DIRECTION INPUT ;
    USE SIGNAL ;
    PORT
      LAYER M4 ;
        RECT  0 39.408 0.084 39.432 ;
    END
  END w_d[84]
  PIN w_d[85]
    DIRECTION INPUT ;
    USE SIGNAL ;
    PORT
      LAYER M4 ;
        RECT  0 39.504 0.084 39.528 ;
    END
  END w_d[85]
  PIN w_d[86]
    DIRECTION INPUT ;
    USE SIGNAL ;
    PORT
      LAYER M4 ;
        RECT  0 39.6 0.084 39.624 ;
    END
  END w_d[86]
  PIN w_d[87]
    DIRECTION INPUT ;
    USE SIGNAL ;
    PORT
      LAYER M4 ;
        RECT  0 39.696 0.084 39.72 ;
    END
  END w_d[87]
  PIN w_d[88]
    DIRECTION INPUT ;
    USE SIGNAL ;
    PORT
      LAYER M4 ;
        RECT  0 39.792 0.084 39.816 ;
    END
  END w_d[88]
  PIN w_d[89]
    DIRECTION INPUT ;
    USE SIGNAL ;
    PORT
      LAYER M4 ;
        RECT  0 39.888 0.084 39.912 ;
    END
  END w_d[89]
  PIN w_d[8]
    DIRECTION INPUT ;
    USE SIGNAL ;
    PORT
      LAYER M4 ;
        RECT  0 82.8 0.084 82.824 ;
    END
  END w_d[8]
  PIN w_d[90]
    DIRECTION INPUT ;
    USE SIGNAL ;
    PORT
      LAYER M4 ;
        RECT  0 39.984 0.084 40.008 ;
    END
  END w_d[90]
  PIN w_d[91]
    DIRECTION INPUT ;
    USE SIGNAL ;
    PORT
      LAYER M4 ;
        RECT  0 40.08 0.084 40.104 ;
    END
  END w_d[91]
  PIN w_d[92]
    DIRECTION INPUT ;
    USE SIGNAL ;
    PORT
      LAYER M4 ;
        RECT  0 40.176 0.084 40.2 ;
    END
  END w_d[92]
  PIN w_d[93]
    DIRECTION INPUT ;
    USE SIGNAL ;
    PORT
      LAYER M4 ;
        RECT  0 40.272 0.084 40.296 ;
    END
  END w_d[93]
  PIN w_d[94]
    DIRECTION INPUT ;
    USE SIGNAL ;
    PORT
      LAYER M4 ;
        RECT  0 40.368 0.084 40.392 ;
    END
  END w_d[94]
  PIN w_d[95]
    DIRECTION INPUT ;
    USE SIGNAL ;
    PORT
      LAYER M4 ;
        RECT  0 40.464 0.084 40.488 ;
    END
  END w_d[95]
  PIN w_d[96]
    DIRECTION INPUT ;
    USE SIGNAL ;
    PORT
      LAYER M4 ;
        RECT  0 43.632 0.084 43.656 ;
    END
  END w_d[96]
  PIN w_d[97]
    DIRECTION INPUT ;
    USE SIGNAL ;
    PORT
      LAYER M4 ;
        RECT  0 43.728 0.084 43.752 ;
    END
  END w_d[97]
  PIN w_d[98]
    DIRECTION INPUT ;
    USE SIGNAL ;
    PORT
      LAYER M4 ;
        RECT  0 43.824 0.084 43.848 ;
    END
  END w_d[98]
  PIN w_d[99]
    DIRECTION INPUT ;
    USE SIGNAL ;
    PORT
      LAYER M4 ;
        RECT  0 43.92 0.084 43.944 ;
    END
  END w_d[99]
  PIN w_d[9]
    DIRECTION INPUT ;
    USE SIGNAL ;
    PORT
      LAYER M4 ;
        RECT  0 82.896 0.084 82.92 ;
    END
  END w_d[9]
  PIN w_v
    DIRECTION INPUT ;
    USE SIGNAL ;
    PORT
      LAYER M4 ;
        RECT  0 87.888 0.084 87.912 ;
    END
  END w_v
  PIN wclk
    DIRECTION INPUT ;
    USE SIGNAL ;
    PORT
      LAYER M4 ;
        RECT  0 87.984 0.084 88.008 ;
    END
  END wclk
  PIN wrst_n
    DIRECTION INPUT ;
    USE SIGNAL ;
    PORT
      LAYER M4 ;
        RECT  0 88.08 0.084 88.104 ;
    END
  END wrst_n
  PIN VDD
    DIRECTION INOUT ;
    USE POWER ;
    PORT
      LAYER M5 ;
        RECT  61.992 2.151 62.112 92.889 ;
        RECT  56.592 2.151 56.712 92.889 ;
        RECT  51.192 2.151 51.312 92.889 ;
        RECT  45.792 2.151 45.912 92.889 ;
        RECT  40.392 2.151 40.512 92.889 ;
        RECT  34.992 2.151 35.112 92.889 ;
        RECT  29.592 2.151 29.712 92.889 ;
        RECT  24.192 2.151 24.312 92.889 ;
        RECT  18.792 2.151 18.912 92.889 ;
        RECT  13.392 2.151 13.512 92.889 ;
        RECT  7.992 2.151 8.112 92.889 ;
        RECT  2.592 2.151 2.712 92.889 ;
    END
  END VDD
  PIN VSS
    DIRECTION INOUT ;
    USE GROUND ;
    PORT
      LAYER M5 ;
        RECT  61.8 2.137 61.92 92.903 ;
        RECT  56.4 2.137 56.52 92.903 ;
        RECT  51 2.137 51.12 92.903 ;
        RECT  45.6 2.137 45.72 92.903 ;
        RECT  40.2 2.137 40.32 92.903 ;
        RECT  34.8 2.137 34.92 92.903 ;
        RECT  29.4 2.137 29.52 92.903 ;
        RECT  24 2.137 24.12 92.903 ;
        RECT  18.6 2.137 18.72 92.903 ;
        RECT  13.2 2.137 13.32 92.903 ;
        RECT  7.8 2.137 7.92 92.903 ;
        RECT  2.4 2.137 2.52 92.903 ;
    END
  END VSS
  OBS
    LAYER RVTN ;
     RECT  2.16 2.16 66.96 2.295 ;
     RECT  2.16 2.565 66.96 2.835 ;
     RECT  2.16 3.105 66.96 3.375 ;
     RECT  2.16 3.645 66.96 3.915 ;
     RECT  2.16 4.185 66.96 4.455 ;
     RECT  2.16 4.725 66.96 4.995 ;
     RECT  2.16 5.265 66.96 5.535 ;
     RECT  2.16 5.805 66.96 6.075 ;
     RECT  2.16 6.345 66.96 6.615 ;
     RECT  2.16 6.885 66.96 7.155 ;
     RECT  2.16 7.425 66.96 7.695 ;
     RECT  2.16 7.965 66.96 8.235 ;
     RECT  2.16 8.505 66.96 8.775 ;
     RECT  2.16 9.045 66.96 9.315 ;
     RECT  2.16 9.585 66.96 9.855 ;
     RECT  2.16 10.125 66.96 10.395 ;
     RECT  2.16 10.665 66.96 10.935 ;
     RECT  2.16 11.205 66.96 11.475 ;
     RECT  2.16 11.745 66.96 12.015 ;
     RECT  2.16 12.285 66.96 12.555 ;
     RECT  2.16 12.825 66.96 13.095 ;
     RECT  2.16 13.365 66.96 13.635 ;
     RECT  2.16 13.905 66.96 14.175 ;
     RECT  2.16 14.445 66.96 14.715 ;
     RECT  2.16 14.985 66.96 15.255 ;
     RECT  2.16 15.525 66.96 15.795 ;
     RECT  2.16 16.065 66.96 16.335 ;
     RECT  2.16 16.605 66.96 16.875 ;
     RECT  2.16 17.145 66.96 17.415 ;
     RECT  2.16 17.685 66.96 17.955 ;
     RECT  2.16 18.225 66.96 18.495 ;
     RECT  2.16 18.765 66.96 19.035 ;
     RECT  2.16 19.305 66.96 19.575 ;
     RECT  2.16 19.845 66.96 20.115 ;
     RECT  2.16 20.385 66.96 20.655 ;
     RECT  2.16 20.925 66.96 21.195 ;
     RECT  2.16 21.465 66.96 21.735 ;
     RECT  2.16 22.005 66.96 22.275 ;
     RECT  2.16 22.545 66.96 22.815 ;
     RECT  2.16 23.085 66.96 23.355 ;
     RECT  2.16 23.625 66.96 23.895 ;
     RECT  2.16 24.165 66.96 24.435 ;
     RECT  2.16 24.705 66.96 24.975 ;
     RECT  2.16 25.245 66.96 25.515 ;
     RECT  2.16 25.785 66.96 26.055 ;
     RECT  2.16 26.325 66.96 26.595 ;
     RECT  2.16 26.865 66.96 27.135 ;
     RECT  2.16 27.405 66.96 27.675 ;
     RECT  2.16 27.945 66.96 28.215 ;
     RECT  2.16 28.485 66.96 28.755 ;
     RECT  2.16 29.025 66.96 29.295 ;
     RECT  2.16 29.565 66.96 29.835 ;
     RECT  2.16 30.105 66.96 30.375 ;
     RECT  2.16 30.645 66.96 30.915 ;
     RECT  2.16 31.185 66.96 31.455 ;
     RECT  2.16 31.725 66.96 31.995 ;
     RECT  2.16 32.265 66.96 32.535 ;
     RECT  2.16 32.805 66.96 33.075 ;
     RECT  2.16 33.345 66.96 33.615 ;
     RECT  2.16 33.885 66.96 34.155 ;
     RECT  2.16 34.425 66.96 34.695 ;
     RECT  2.16 34.965 66.96 35.235 ;
     RECT  2.16 35.505 66.96 35.775 ;
     RECT  2.16 36.045 66.96 36.315 ;
     RECT  2.16 36.585 66.96 36.855 ;
     RECT  2.16 37.125 66.96 37.395 ;
     RECT  2.16 37.665 66.96 37.935 ;
     RECT  2.16 38.205 66.96 38.475 ;
     RECT  2.16 38.745 66.96 39.015 ;
     RECT  2.16 39.285 66.96 39.555 ;
     RECT  2.16 39.825 66.96 40.095 ;
     RECT  2.16 40.365 66.96 40.635 ;
     RECT  2.16 40.905 66.96 41.175 ;
     RECT  2.16 41.445 66.96 41.715 ;
     RECT  2.16 41.985 66.96 42.255 ;
     RECT  2.16 42.525 66.96 42.795 ;
     RECT  2.16 43.065 66.96 43.335 ;
     RECT  2.16 43.605 66.96 43.875 ;
     RECT  2.16 44.145 66.96 44.415 ;
     RECT  2.16 44.685 66.96 44.955 ;
     RECT  2.16 45.225 66.96 45.495 ;
     RECT  2.16 45.765 66.96 46.035 ;
     RECT  2.16 46.305 66.96 46.575 ;
     RECT  2.16 46.845 66.96 47.115 ;
     RECT  2.16 47.385 66.96 47.655 ;
     RECT  2.16 47.925 66.96 48.195 ;
     RECT  2.16 48.465 66.96 48.735 ;
     RECT  2.16 49.005 66.96 49.275 ;
     RECT  2.16 49.545 66.96 49.815 ;
     RECT  2.16 50.085 66.96 50.355 ;
     RECT  2.16 50.625 66.96 50.895 ;
     RECT  2.16 51.165 66.96 51.435 ;
     RECT  2.16 51.705 66.96 51.975 ;
     RECT  2.16 52.245 66.96 52.515 ;
     RECT  2.16 52.785 66.96 53.055 ;
     RECT  2.16 53.325 66.96 53.595 ;
     RECT  2.16 53.865 66.96 54.135 ;
     RECT  2.16 54.405 66.96 54.675 ;
     RECT  2.16 54.945 66.96 55.215 ;
     RECT  2.16 55.485 66.96 55.755 ;
     RECT  2.16 56.025 66.96 56.295 ;
     RECT  2.16 56.565 66.96 56.835 ;
     RECT  2.16 57.105 66.96 57.375 ;
     RECT  2.16 57.645 66.96 57.915 ;
     RECT  2.16 58.185 66.96 58.455 ;
     RECT  2.16 58.725 66.96 58.995 ;
     RECT  2.16 59.265 66.96 59.535 ;
     RECT  2.16 59.805 66.96 60.075 ;
     RECT  2.16 60.345 66.96 60.615 ;
     RECT  2.16 60.885 66.96 61.155 ;
     RECT  2.16 61.425 66.96 61.695 ;
     RECT  2.16 61.965 66.96 62.235 ;
     RECT  2.16 62.505 66.96 62.775 ;
     RECT  2.16 63.045 66.96 63.315 ;
     RECT  2.16 63.585 66.96 63.855 ;
     RECT  2.16 64.125 66.96 64.395 ;
     RECT  2.16 64.665 66.96 64.935 ;
     RECT  2.16 65.205 66.96 65.475 ;
     RECT  2.16 65.745 66.96 66.015 ;
     RECT  2.16 66.285 66.96 66.555 ;
     RECT  2.16 66.825 66.96 67.095 ;
     RECT  2.16 67.365 66.96 67.635 ;
     RECT  2.16 67.905 66.96 68.175 ;
     RECT  2.16 68.445 66.96 68.715 ;
     RECT  2.16 68.985 66.96 69.255 ;
     RECT  2.16 69.525 66.96 69.795 ;
     RECT  2.16 70.065 66.96 70.335 ;
     RECT  2.16 70.605 66.96 70.875 ;
     RECT  2.16 71.145 66.96 71.415 ;
     RECT  2.16 71.685 66.96 71.955 ;
     RECT  2.16 72.225 66.96 72.495 ;
     RECT  2.16 72.765 66.96 73.035 ;
     RECT  2.16 73.305 66.96 73.575 ;
     RECT  2.16 73.845 66.96 74.115 ;
     RECT  2.16 74.385 66.96 74.655 ;
     RECT  2.16 74.925 66.96 75.195 ;
     RECT  2.16 75.465 66.96 75.735 ;
     RECT  2.16 76.005 66.96 76.275 ;
     RECT  2.16 76.545 66.96 76.815 ;
     RECT  2.16 77.085 66.96 77.355 ;
     RECT  2.16 77.625 66.96 77.895 ;
     RECT  2.16 78.165 66.96 78.435 ;
     RECT  2.16 78.705 66.96 78.975 ;
     RECT  2.16 79.245 66.96 79.515 ;
     RECT  2.16 79.785 66.96 80.055 ;
     RECT  2.16 80.325 66.96 80.595 ;
     RECT  2.16 80.865 66.96 81.135 ;
     RECT  2.16 81.405 66.96 81.675 ;
     RECT  2.16 81.945 66.96 82.215 ;
     RECT  2.16 82.485 66.96 82.755 ;
     RECT  2.16 83.025 66.96 83.295 ;
     RECT  2.16 83.565 66.96 83.835 ;
     RECT  2.16 84.105 66.96 84.375 ;
     RECT  2.16 84.645 66.96 84.915 ;
     RECT  2.16 85.185 66.96 85.455 ;
     RECT  2.16 85.725 66.96 85.995 ;
     RECT  2.16 86.265 66.96 86.535 ;
     RECT  2.16 86.805 66.96 87.075 ;
     RECT  2.16 87.345 66.96 87.615 ;
     RECT  2.16 87.885 66.96 88.155 ;
     RECT  2.16 88.425 66.96 88.695 ;
     RECT  2.16 88.965 66.96 89.235 ;
     RECT  2.16 89.505 66.96 89.775 ;
     RECT  2.16 90.045 66.96 90.315 ;
     RECT  2.16 90.585 66.96 90.855 ;
     RECT  2.16 91.125 66.96 91.395 ;
     RECT  2.16 91.665 66.96 91.935 ;
     RECT  2.16 92.205 66.96 92.475 ;
     RECT  2.16 92.745 66.96 92.88 ;
    LAYER RVTP ;
     RECT  2.16 2.295 66.96 2.565 ;
     RECT  2.16 2.835 66.96 3.105 ;
     RECT  2.16 3.375 66.96 3.645 ;
     RECT  2.16 3.915 66.96 4.185 ;
     RECT  2.16 4.455 66.96 4.725 ;
     RECT  2.16 4.995 66.96 5.265 ;
     RECT  2.16 5.535 66.96 5.805 ;
     RECT  2.16 6.075 66.96 6.345 ;
     RECT  2.16 6.615 66.96 6.885 ;
     RECT  2.16 7.155 66.96 7.425 ;
     RECT  2.16 7.695 66.96 7.965 ;
     RECT  2.16 8.235 66.96 8.505 ;
     RECT  2.16 8.775 66.96 9.045 ;
     RECT  2.16 9.315 66.96 9.585 ;
     RECT  2.16 9.855 66.96 10.125 ;
     RECT  2.16 10.395 66.96 10.665 ;
     RECT  2.16 10.935 66.96 11.205 ;
     RECT  2.16 11.475 66.96 11.745 ;
     RECT  2.16 12.015 66.96 12.285 ;
     RECT  2.16 12.555 66.96 12.825 ;
     RECT  2.16 13.095 66.96 13.365 ;
     RECT  2.16 13.635 66.96 13.905 ;
     RECT  2.16 14.175 66.96 14.445 ;
     RECT  2.16 14.715 66.96 14.985 ;
     RECT  2.16 15.255 66.96 15.525 ;
     RECT  2.16 15.795 66.96 16.065 ;
     RECT  2.16 16.335 66.96 16.605 ;
     RECT  2.16 16.875 66.96 17.145 ;
     RECT  2.16 17.415 66.96 17.685 ;
     RECT  2.16 17.955 66.96 18.225 ;
     RECT  2.16 18.495 66.96 18.765 ;
     RECT  2.16 19.035 66.96 19.305 ;
     RECT  2.16 19.575 66.96 19.845 ;
     RECT  2.16 20.115 66.96 20.385 ;
     RECT  2.16 20.655 66.96 20.925 ;
     RECT  2.16 21.195 66.96 21.465 ;
     RECT  2.16 21.735 66.96 22.005 ;
     RECT  2.16 22.275 66.96 22.545 ;
     RECT  2.16 22.815 66.96 23.085 ;
     RECT  2.16 23.355 66.96 23.625 ;
     RECT  2.16 23.895 66.96 24.165 ;
     RECT  2.16 24.435 66.96 24.705 ;
     RECT  2.16 24.975 66.96 25.245 ;
     RECT  2.16 25.515 66.96 25.785 ;
     RECT  2.16 26.055 66.96 26.325 ;
     RECT  2.16 26.595 66.96 26.865 ;
     RECT  2.16 27.135 66.96 27.405 ;
     RECT  2.16 27.675 66.96 27.945 ;
     RECT  2.16 28.215 66.96 28.485 ;
     RECT  2.16 28.755 66.96 29.025 ;
     RECT  2.16 29.295 66.96 29.565 ;
     RECT  2.16 29.835 66.96 30.105 ;
     RECT  2.16 30.375 66.96 30.645 ;
     RECT  2.16 30.915 66.96 31.185 ;
     RECT  2.16 31.455 66.96 31.725 ;
     RECT  2.16 31.995 66.96 32.265 ;
     RECT  2.16 32.535 66.96 32.805 ;
     RECT  2.16 33.075 66.96 33.345 ;
     RECT  2.16 33.615 66.96 33.885 ;
     RECT  2.16 34.155 66.96 34.425 ;
     RECT  2.16 34.695 66.96 34.965 ;
     RECT  2.16 35.235 66.96 35.505 ;
     RECT  2.16 35.775 66.96 36.045 ;
     RECT  2.16 36.315 66.96 36.585 ;
     RECT  2.16 36.855 66.96 37.125 ;
     RECT  2.16 37.395 66.96 37.665 ;
     RECT  2.16 37.935 66.96 38.205 ;
     RECT  2.16 38.475 66.96 38.745 ;
     RECT  2.16 39.015 66.96 39.285 ;
     RECT  2.16 39.555 66.96 39.825 ;
     RECT  2.16 40.095 66.96 40.365 ;
     RECT  2.16 40.635 66.96 40.905 ;
     RECT  2.16 41.175 66.96 41.445 ;
     RECT  2.16 41.715 66.96 41.985 ;
     RECT  2.16 42.255 66.96 42.525 ;
     RECT  2.16 42.795 66.96 43.065 ;
     RECT  2.16 43.335 66.96 43.605 ;
     RECT  2.16 43.875 66.96 44.145 ;
     RECT  2.16 44.415 66.96 44.685 ;
     RECT  2.16 44.955 66.96 45.225 ;
     RECT  2.16 45.495 66.96 45.765 ;
     RECT  2.16 46.035 66.96 46.305 ;
     RECT  2.16 46.575 66.96 46.845 ;
     RECT  2.16 47.115 66.96 47.385 ;
     RECT  2.16 47.655 66.96 47.925 ;
     RECT  2.16 48.195 66.96 48.465 ;
     RECT  2.16 48.735 66.96 49.005 ;
     RECT  2.16 49.275 66.96 49.545 ;
     RECT  2.16 49.815 66.96 50.085 ;
     RECT  2.16 50.355 66.96 50.625 ;
     RECT  2.16 50.895 66.96 51.165 ;
     RECT  2.16 51.435 66.96 51.705 ;
     RECT  2.16 51.975 66.96 52.245 ;
     RECT  2.16 52.515 66.96 52.785 ;
     RECT  2.16 53.055 66.96 53.325 ;
     RECT  2.16 53.595 66.96 53.865 ;
     RECT  2.16 54.135 66.96 54.405 ;
     RECT  2.16 54.675 66.96 54.945 ;
     RECT  2.16 55.215 66.96 55.485 ;
     RECT  2.16 55.755 66.96 56.025 ;
     RECT  2.16 56.295 66.96 56.565 ;
     RECT  2.16 56.835 66.96 57.105 ;
     RECT  2.16 57.375 66.96 57.645 ;
     RECT  2.16 57.915 66.96 58.185 ;
     RECT  2.16 58.455 66.96 58.725 ;
     RECT  2.16 58.995 66.96 59.265 ;
     RECT  2.16 59.535 66.96 59.805 ;
     RECT  2.16 60.075 66.96 60.345 ;
     RECT  2.16 60.615 66.96 60.885 ;
     RECT  2.16 61.155 66.96 61.425 ;
     RECT  2.16 61.695 66.96 61.965 ;
     RECT  2.16 62.235 66.96 62.505 ;
     RECT  2.16 62.775 66.96 63.045 ;
     RECT  2.16 63.315 66.96 63.585 ;
     RECT  2.16 63.855 66.96 64.125 ;
     RECT  2.16 64.395 66.96 64.665 ;
     RECT  2.16 64.935 66.96 65.205 ;
     RECT  2.16 65.475 66.96 65.745 ;
     RECT  2.16 66.015 66.96 66.285 ;
     RECT  2.16 66.555 66.96 66.825 ;
     RECT  2.16 67.095 66.96 67.365 ;
     RECT  2.16 67.635 66.96 67.905 ;
     RECT  2.16 68.175 66.96 68.445 ;
     RECT  2.16 68.715 66.96 68.985 ;
     RECT  2.16 69.255 66.96 69.525 ;
     RECT  2.16 69.795 66.96 70.065 ;
     RECT  2.16 70.335 66.96 70.605 ;
     RECT  2.16 70.875 66.96 71.145 ;
     RECT  2.16 71.415 66.96 71.685 ;
     RECT  2.16 71.955 66.96 72.225 ;
     RECT  2.16 72.495 66.96 72.765 ;
     RECT  2.16 73.035 66.96 73.305 ;
     RECT  2.16 73.575 66.96 73.845 ;
     RECT  2.16 74.115 66.96 74.385 ;
     RECT  2.16 74.655 66.96 74.925 ;
     RECT  2.16 75.195 66.96 75.465 ;
     RECT  2.16 75.735 66.96 76.005 ;
     RECT  2.16 76.275 66.96 76.545 ;
     RECT  2.16 76.815 66.96 77.085 ;
     RECT  2.16 77.355 66.96 77.625 ;
     RECT  2.16 77.895 66.96 78.165 ;
     RECT  2.16 78.435 66.96 78.705 ;
     RECT  2.16 78.975 66.96 79.245 ;
     RECT  2.16 79.515 66.96 79.785 ;
     RECT  2.16 80.055 66.96 80.325 ;
     RECT  2.16 80.595 66.96 80.865 ;
     RECT  2.16 81.135 66.96 81.405 ;
     RECT  2.16 81.675 66.96 81.945 ;
     RECT  2.16 82.215 66.96 82.485 ;
     RECT  2.16 82.755 66.96 83.025 ;
     RECT  2.16 83.295 66.96 83.565 ;
     RECT  2.16 83.835 66.96 84.105 ;
     RECT  2.16 84.375 66.96 84.645 ;
     RECT  2.16 84.915 66.96 85.185 ;
     RECT  2.16 85.455 66.96 85.725 ;
     RECT  2.16 85.995 66.96 86.265 ;
     RECT  2.16 86.535 66.96 86.805 ;
     RECT  2.16 87.075 66.96 87.345 ;
     RECT  2.16 87.615 66.96 87.885 ;
     RECT  2.16 88.155 66.96 88.425 ;
     RECT  2.16 88.695 66.96 88.965 ;
     RECT  2.16 89.235 66.96 89.505 ;
     RECT  2.16 89.775 66.96 90.045 ;
     RECT  2.16 90.315 66.96 90.585 ;
     RECT  2.16 90.855 66.96 91.125 ;
     RECT  2.16 91.395 66.96 91.665 ;
     RECT  2.16 91.935 66.96 92.205 ;
     RECT  2.16 92.475 66.96 92.745 ;
    LAYER M1 ;
     RECT  2.16 2.151 66.96 92.889 ;
    LAYER M2 ;
     RECT  0.031 10.836 0.103 10.854 ;
     RECT  0.067 30.771 0.103 31.104 ;
     RECT  0.067 37.908 0.103 37.926 ;
     RECT  0.067 64.134 0.103 64.152 ;
     RECT  0.067 80.532 0.103 80.55 ;
     RECT  0.031 74.664 0.131 74.682 ;
     RECT  0.103 15.3 0.139 15.318 ;
     RECT  0.103 23.634 0.139 23.652 ;
     RECT  0.103 24.786 0.139 24.804 ;
     RECT  0.103 29.466 0.139 31.104 ;
     RECT  0.103 41.454 0.139 41.472 ;
     RECT  0.103 46.008 0.139 46.026 ;
     RECT  0.067 68.841 0.167 68.859 ;
     RECT  0.103 79.866 0.167 81.126 ;
     RECT  0.103 10.476 0.175 10.854 ;
     RECT  0.103 13.878 0.175 13.896 ;
     RECT  0.139 23.634 0.175 24.804 ;
     RECT  0.103 27.576 0.175 27.594 ;
     RECT  0.103 36.486 0.175 36.504 ;
     RECT  0.067 40.176 0.175 40.194 ;
     RECT  0.103 63.054 0.175 63.072 ;
     RECT  0.139 28.836 0.203 31.752 ;
     RECT  0.103 37.908 0.203 38.304 ;
     RECT  0.103 44.586 0.203 44.784 ;
     RECT  0.103 50.211 0.203 51.354 ;
     RECT  0.103 71.541 0.203 71.712 ;
     RECT  0.175 21.816 0.211 21.834 ;
     RECT  0.103 34.506 0.211 34.524 ;
     RECT  0.175 40.176 0.211 40.509 ;
     RECT  0.139 41.454 0.211 41.67 ;
     RECT  0.103 53.334 0.211 53.352 ;
     RECT  0.103 67.446 0.211 68.004 ;
     RECT  0.031 83.88 0.211 83.898 ;
     RECT  0.103 18.81 0.239 19.098 ;
     RECT  0.139 46.008 0.239 46.602 ;
     RECT  0.167 81.108 0.239 81.126 ;
     RECT  0.139 15.3 0.247 16.02 ;
     RECT  0.103 17.082 0.247 17.1 ;
     RECT  0.203 28.836 0.247 30.249 ;
     RECT  0.211 40.176 0.247 41.67 ;
     RECT  0.247 33.246 0.283 33.264 ;
     RECT  0.211 34.506 0.283 34.65 ;
     RECT  0.211 83.196 0.283 83.898 ;
     RECT  0.203 31.086 0.319 31.752 ;
     RECT  0.203 50.868 0.319 51.354 ;
     RECT  0.175 52.254 0.319 52.272 ;
     RECT  0.239 18.972 0.347 19.098 ;
     RECT  0.247 28.764 0.347 30.249 ;
     RECT  0.239 46.584 0.347 46.602 ;
     RECT  0.211 67.14 0.347 68.004 ;
     RECT  0.203 71.541 0.347 71.559 ;
     RECT  0.167 79.866 0.347 80.118 ;
     RECT  0.347 18.972 0.383 18.99 ;
     RECT  0.211 21.672 0.383 21.834 ;
     RECT  0.319 50.868 0.383 52.272 ;
     RECT  0.139 65.448 0.383 65.466 ;
     RECT  0.103 8.586 0.391 9.648 ;
     RECT  0.383 50.904 0.419 52.272 ;
     RECT  0.103 13.032 0.463 13.05 ;
     RECT  0.175 13.878 0.463 14.4 ;
     RECT  0.211 76.86 0.499 76.878 ;
     RECT  0.175 10.476 0.527 11.466 ;
     RECT  0.527 10.476 0.535 10.62 ;
     RECT  0.247 12.222 0.535 12.24 ;
     RECT  0.463 13.032 0.535 14.4 ;
     RECT  0.247 15.3 0.535 17.1 ;
     RECT  0.175 27.486 0.535 27.594 ;
     RECT  0.283 33.246 0.535 34.65 ;
     RECT  0.175 36.486 0.535 36.774 ;
     RECT  0.031 60.246 0.535 60.264 ;
     RECT  0.499 66.636 0.535 66.654 ;
     RECT  0.499 75.708 0.535 75.726 ;
     RECT  0.103 86.886 0.535 86.904 ;
     RECT  0.535 27.414 0.563 27.594 ;
     RECT  0.247 40.176 0.571 41.706 ;
     RECT  0.175 63.054 0.571 63.27 ;
     RECT  0.103 64.134 0.571 64.656 ;
     RECT  0.499 78.516 0.571 78.534 ;
     RECT  0.535 79.56 0.571 79.578 ;
     RECT  0.347 30.231 0.599 30.249 ;
     RECT  0.535 33.246 0.635 36.774 ;
     RECT  0.635 36.486 0.851 36.774 ;
     RECT  0.535 66.024 1.111 66.654 ;
     RECT  0.347 67.446 1.111 68.004 ;
     RECT  0.571 40.176 1.147 41.94 ;
     RECT  0.535 43.236 1.147 43.254 ;
     RECT  1.183 39.294 1.219 39.312 ;
     RECT  1.219 39.222 1.319 39.312 ;
     RECT  1.319 39.294 1.355 39.312 ;
     RECT  1.111 22.356 1.723 22.374 ;
     RECT  0.175 23.634 1.723 25.074 ;
     RECT  0.419 50.904 1.723 51.354 ;
     RECT  0.419 52.254 1.723 52.272 ;
     RECT  0.391 8.046 1.975 9.648 ;
     RECT  0.535 10.404 1.975 10.62 ;
     RECT  0.203 44.586 1.975 44.604 ;
     RECT  0.499 76.86 1.975 77.382 ;
     RECT  1.399 81.342 1.975 81.36 ;
     RECT  1.723 82.152 1.975 82.17 ;
     RECT  1.975 81.342 2.047 82.17 ;
     RECT  1.975 8.046 2.16 10.62 ;
     RECT  0.527 11.448 2.16 11.466 ;
     RECT  0.535 12.222 2.16 14.4 ;
     RECT  0.535 15.228 2.16 17.1 ;
     RECT  1.723 20.052 2.16 20.07 ;
     RECT  1.723 22.356 2.16 25.074 ;
     RECT  0.563 27.414 2.16 27.432 ;
     RECT  0.347 28.764 2.16 29.484 ;
     RECT  0.319 31.086 2.16 32.184 ;
     RECT  0.635 33.246 2.16 35.19 ;
     RECT  0.851 36.756 2.16 36.774 ;
     RECT  0.203 38.25 2.16 38.304 ;
     RECT  1.147 40.068 2.16 41.94 ;
     RECT  1.147 43.236 2.16 43.29 ;
     RECT  1.975 44.586 2.16 44.91 ;
     RECT  0.031 49.284 2.16 49.302 ;
     RECT  1.723 50.904 2.16 52.272 ;
     RECT  0.211 53.334 2.16 53.622 ;
     RECT  0.175 54.756 2.16 54.774 ;
     RECT  0.535 60.246 2.16 60.984 ;
     RECT  0.571 63.054 2.16 64.656 ;
     RECT  1.111 66.024 2.16 68.004 ;
     RECT  0.535 69.804 2.16 69.822 ;
     RECT  0.535 75.546 2.16 75.726 ;
     RECT  1.975 76.86 2.16 77.652 ;
     RECT  0.571 78.516 2.16 79.578 ;
     RECT  2.047 80.802 2.16 82.17 ;
     RECT  0.283 83.196 2.16 84.366 ;
     RECT  0.535 86.886 2.16 87.534 ;
     RECT  0.067 88.704 2.16 88.722 ;
     RECT  0.031 89.856 2.16 89.874 ;
     RECT  2.16 2.151 38.731 92.889 ;
     RECT  38.731 2.106 39.947 92.889 ;
     RECT  39.947 2.151 60.295 92.889 ;
     RECT  60.295 2.106 60.899 92.889 ;
     RECT  60.899 2.151 66.523 92.889 ;
     RECT  66.523 2.106 66.96 92.889 ;
     RECT  66.96 86.274 66.983 90.774 ;
     RECT  66.96 8.01 67.019 18.792 ;
     RECT  66.96 19.548 67.019 22.806 ;
     RECT  66.96 84.006 67.019 85.284 ;
     RECT  67.019 8.01 67.307 18.594 ;
     RECT  66.96 2.106 67.343 6.984 ;
     RECT  66.96 51.336 67.379 55.512 ;
     RECT  67.019 19.548 67.559 22.734 ;
     RECT  66.96 64.944 67.559 72.594 ;
     RECT  66.96 57.312 67.739 59.994 ;
     RECT  67.379 51.336 67.775 53.856 ;
     RECT  67.739 57.312 67.775 58.104 ;
     RECT  66.96 44.586 67.811 44.604 ;
     RECT  66.96 75.708 67.811 80.118 ;
     RECT  67.019 84.006 67.811 84.834 ;
     RECT  67.307 8.01 67.847 9.072 ;
     RECT  66.96 38.448 67.847 43.632 ;
     RECT  67.847 41.148 67.883 43.632 ;
     RECT  67.379 54.684 67.883 55.512 ;
     RECT  66.96 27.306 67.919 30.474 ;
     RECT  67.883 41.346 67.919 43.632 ;
     RECT  67.559 64.944 68.099 68.67 ;
     RECT  66.983 86.274 68.135 90.234 ;
     RECT  68.135 86.274 68.143 89.424 ;
     RECT  68.099 65.106 68.171 68.67 ;
     RECT  68.135 90.216 68.171 90.234 ;
     RECT  68.143 86.04 68.207 89.424 ;
     RECT  68.207 86.04 68.215 88.524 ;
     RECT  68.207 89.316 68.243 89.424 ;
     RECT  67.559 19.548 68.279 22.23 ;
     RECT  68.279 20.7 68.315 22.23 ;
     RECT  67.919 27.306 68.387 29.556 ;
     RECT  67.919 30.456 68.387 30.474 ;
     RECT  66.96 32.166 68.387 36.612 ;
     RECT  67.847 38.448 68.387 40.284 ;
     RECT  67.883 55.026 68.387 55.512 ;
     RECT  67.775 57.312 68.387 57.942 ;
     RECT  68.387 29.538 68.423 29.556 ;
     RECT  68.387 32.346 68.423 36.612 ;
     RECT  67.919 41.346 68.423 42.246 ;
     RECT  67.919 43.038 68.423 43.632 ;
     RECT  66.96 45.468 68.423 49.608 ;
     RECT  67.559 69.498 68.423 72.594 ;
     RECT  68.215 85.464 68.423 88.524 ;
     RECT  68.387 27.306 68.459 28.746 ;
     RECT  68.423 43.614 68.459 43.632 ;
     RECT  68.387 55.116 68.459 55.512 ;
     RECT  68.423 69.498 68.459 72.522 ;
     RECT  67.811 75.906 68.459 80.118 ;
     RECT  68.423 85.464 68.459 85.482 ;
     RECT  67.307 10.098 68.495 18.594 ;
     RECT  68.459 27.306 68.495 27.324 ;
     RECT  68.423 41.454 68.495 42.246 ;
     RECT  68.423 45.468 68.495 48.69 ;
     RECT  68.459 69.498 68.495 71.946 ;
     RECT  67.343 5.706 68.531 6.984 ;
     RECT  68.495 10.098 68.531 11.808 ;
     RECT  68.459 28.386 68.531 28.746 ;
     RECT  68.495 69.498 68.531 71.334 ;
     RECT  68.531 11.79 68.567 11.808 ;
     RECT  68.531 28.386 68.567 28.674 ;
     RECT  68.423 32.346 68.567 36.414 ;
     RECT  68.495 48.096 68.567 48.69 ;
     RECT  68.567 28.656 68.603 28.674 ;
     RECT  68.495 41.922 68.603 42.246 ;
     RECT  68.567 48.546 68.603 48.69 ;
     RECT  68.171 65.646 68.603 68.67 ;
     RECT  67.343 2.106 68.639 4.824 ;
     RECT  68.603 42.066 68.639 42.246 ;
     RECT  68.603 48.672 68.639 48.69 ;
     RECT  68.531 69.498 68.639 70.668 ;
     RECT  68.639 42.066 68.675 42.084 ;
     RECT  68.639 2.106 68.711 4.212 ;
     RECT  68.639 70.308 68.747 70.668 ;
     RECT  66.96 81.414 68.755 82.944 ;
     RECT  68.567 32.346 68.783 35.064 ;
     RECT  68.495 12.6 68.819 18.594 ;
     RECT  68.495 45.468 68.819 47.034 ;
     RECT  68.387 57.726 68.819 57.942 ;
     RECT  68.423 86.274 68.819 88.524 ;
     RECT  68.755 81.414 68.827 83.016 ;
     RECT  68.711 3.816 68.855 4.212 ;
     RECT  68.819 15.804 68.855 18.594 ;
     RECT  68.387 38.754 68.855 40.284 ;
     RECT  68.603 68.616 68.855 68.67 ;
     RECT  68.243 89.316 68.855 89.334 ;
     RECT  68.315 20.7 68.891 22.104 ;
     RECT  68.855 38.754 68.891 40.194 ;
     RECT  68.603 65.646 68.891 67.464 ;
     RECT  68.819 12.6 68.927 14.589 ;
     RECT  68.855 15.804 68.927 17.442 ;
     RECT  68.279 19.548 68.927 19.602 ;
     RECT  68.783 32.436 68.927 35.064 ;
     RECT  68.891 38.754 68.927 39.582 ;
     RECT  68.819 45.468 68.927 46.836 ;
     RECT  67.775 51.48 68.927 53.856 ;
     RECT  67.811 84.006 68.927 84.672 ;
     RECT  68.819 87.516 68.927 88.524 ;
     RECT  67.847 8.514 68.935 9.072 ;
     RECT  68.531 10.098 68.935 10.926 ;
     RECT  68.827 81.414 68.935 83.088 ;
     RECT  68.927 84.006 68.935 84.402 ;
     RECT  68.927 15.804 68.963 17.172 ;
     RECT  68.855 18.234 68.963 18.594 ;
     RECT  68.891 21.474 68.963 22.104 ;
     RECT  68.927 32.436 68.963 33.174 ;
     RECT  68.927 46.818 68.963 46.836 ;
     RECT  68.927 52.686 68.963 53.856 ;
     RECT  68.819 57.726 68.963 57.744 ;
     RECT  67.739 59.166 68.963 59.994 ;
     RECT  68.747 70.65 68.963 70.668 ;
     RECT  66.96 73.548 68.963 74.916 ;
     RECT  68.935 81.414 68.963 84.402 ;
     RECT  68.819 86.274 68.963 86.526 ;
     RECT  68.927 87.516 68.963 88.182 ;
     RECT  68.639 69.498 68.971 69.552 ;
     RECT  68.711 2.106 68.999 3.024 ;
     RECT  68.531 5.886 68.999 6.984 ;
     RECT  68.963 16.344 68.999 17.172 ;
     RECT  68.963 21.474 68.999 21.492 ;
     RECT  68.963 32.436 68.999 32.454 ;
     RECT  68.927 38.754 68.999 39.276 ;
     RECT  68.927 45.468 68.999 45.756 ;
     RECT  68.963 52.686 68.999 52.974 ;
     RECT  68.359 56.421 68.999 56.439 ;
     RECT  68.891 65.646 68.999 67.194 ;
     RECT  68.963 73.548 68.999 74.844 ;
     RECT  68.459 75.906 68.999 79.776 ;
     RECT  68.963 81.414 68.999 84.024 ;
     RECT  68.963 86.508 68.999 86.526 ;
     RECT  68.459 55.26 69.007 55.512 ;
     RECT  68.999 2.106 69.035 2.862 ;
     RECT  68.855 4.194 69.035 4.212 ;
     RECT  68.999 5.886 69.035 6.876 ;
     RECT  68.935 8.046 69.035 10.926 ;
     RECT  68.927 12.6 69.035 13.122 ;
     RECT  68.927 13.95 69.035 14.589 ;
     RECT  68.999 16.344 69.035 16.974 ;
     RECT  68.963 18.234 69.035 18.252 ;
     RECT  68.927 19.584 69.035 19.602 ;
     RECT  68.927 34.164 69.035 35.064 ;
     RECT  68.567 36.126 69.035 36.414 ;
     RECT  68.999 38.754 69.035 38.772 ;
     RECT  68.999 45.468 69.035 45.486 ;
     RECT  68.927 51.48 69.035 51.498 ;
     RECT  69.007 55.26 69.035 56.016 ;
     RECT  68.963 59.31 69.035 59.994 ;
     RECT  68.999 65.646 69.035 66.852 ;
     RECT  68.971 68.76 69.035 69.552 ;
     RECT  68.999 73.548 69.035 73.989 ;
     RECT  68.999 74.826 69.035 74.844 ;
     RECT  68.999 77.166 69.035 79.776 ;
     RECT  68.999 82.224 69.035 83.52 ;
     RECT  68.963 87.516 69.035 87.534 ;
     RECT  69.035 59.976 69.071 59.994 ;
     RECT  69.035 65.646 69.071 66.276 ;
     RECT  69.035 68.76 69.071 69.444 ;
     RECT  69.035 2.646 69.107 2.664 ;
     RECT  69.035 6.156 69.107 6.174 ;
     RECT  69.035 10.404 69.107 10.422 ;
     RECT  69.035 13.104 69.107 13.122 ;
     RECT  69.035 16.956 69.107 16.974 ;
     RECT  68.891 20.7 69.107 20.718 ;
     RECT  69.035 34.668 69.107 34.686 ;
     RECT  69.035 36.126 69.107 36.144 ;
     RECT  68.971 50.562 69.107 50.58 ;
     RECT  68.999 52.686 69.107 52.704 ;
     RECT  68.963 53.838 69.107 53.856 ;
     RECT  69.035 55.998 69.107 56.016 ;
     RECT  69.071 65.646 69.107 65.664 ;
     RECT  69.071 69.426 69.107 69.444 ;
     RECT  69.035 73.971 69.107 73.989 ;
     RECT  68.999 75.906 69.107 75.924 ;
    LAYER M3 ;
     RECT  39.924 2.101 39.942 2.143 ;
     RECT  13.215 2.143 13.305 2.191 ;
     RECT  18.615 2.143 18.705 2.191 ;
     RECT  34.815 2.143 34.905 2.191 ;
     RECT  45.615 2.143 45.705 2.191 ;
     RECT  60.3 2.101 60.894 2.191 ;
     RECT  61.815 2.143 61.905 2.191 ;
     RECT  69.012 2.101 69.03 2.191 ;
     RECT  13.215 2.191 13.77 2.227 ;
     RECT  17.244 2.191 17.262 2.227 ;
     RECT  18.468 2.191 18.705 2.227 ;
     RECT  24.015 2.143 24.105 2.227 ;
     RECT  33.228 2.191 33.246 2.227 ;
     RECT  34.815 2.191 35.334 2.227 ;
     RECT  45.615 2.191 46.242 2.227 ;
     RECT  48.816 2.191 48.834 2.227 ;
     RECT  49.716 2.191 49.734 2.227 ;
     RECT  51.015 2.143 51.105 2.227 ;
     RECT  56.415 2.143 56.505 2.227 ;
     RECT  66.528 2.101 66.546 2.227 ;
     RECT  12.168 2.191 12.186 2.251 ;
     RECT  7.815 2.143 7.905 2.263 ;
     RECT  12.168 2.251 12.438 2.263 ;
     RECT  13.215 2.227 14.886 2.263 ;
     RECT  18.18 2.227 19.062 2.263 ;
     RECT  24.015 2.227 25.002 2.263 ;
     RECT  32.544 2.227 33.246 2.263 ;
     RECT  38.736 2.101 38.754 2.263 ;
     RECT  39.924 2.143 40.305 2.263 ;
     RECT  41.94 2.227 41.958 2.263 ;
     RECT  42.912 2.191 43.11 2.263 ;
     RECT  47.88 2.227 47.898 2.263 ;
     RECT  54.684 2.227 55.242 2.263 ;
     RECT  60.3 2.191 61.905 2.263 ;
     RECT  66.312 2.227 66.546 2.263 ;
     RECT  7.776 2.263 8.298 2.299 ;
     RECT  21.672 2.263 21.906 2.299 ;
     RECT  22.86 2.227 22.878 2.299 ;
     RECT  26.136 2.251 26.154 2.299 ;
     RECT  41.94 2.263 43.11 2.299 ;
     RECT  45 2.227 46.242 2.299 ;
     RECT  47.88 2.263 48.042 2.299 ;
     RECT  7.56 2.299 8.298 2.335 ;
     RECT  12.168 2.263 14.886 2.335 ;
     RECT  16.56 2.227 17.262 2.335 ;
     RECT  30.78 2.191 30.798 2.335 ;
     RECT  45 2.299 46.53 2.335 ;
     RECT  47.7 2.299 48.042 2.335 ;
     RECT  5.472 2.335 5.49 2.371 ;
     RECT  7.56 2.335 8.37 2.371 ;
     RECT  9.108 2.227 9.126 2.371 ;
     RECT  10.836 2.251 10.854 2.371 ;
     RECT  20.16 2.227 20.178 2.371 ;
     RECT  20.952 2.299 21.906 2.371 ;
     RECT  22.86 2.299 23.094 2.371 ;
     RECT  24.015 2.263 25.29 2.371 ;
     RECT  26.064 2.299 26.154 2.371 ;
     RECT  27.072 2.227 27.09 2.371 ;
     RECT  29.415 2.143 29.505 2.371 ;
     RECT  34.815 2.227 36.126 2.371 ;
     RECT  38.628 2.263 40.305 2.371 ;
     RECT  45 2.335 46.854 2.371 ;
     RECT  47.628 2.335 48.042 2.371 ;
     RECT  50.58 2.227 51.105 2.371 ;
     RECT  54.684 2.263 55.314 2.371 ;
     RECT  56.304 2.227 56.505 2.371 ;
     RECT  58.356 2.299 58.374 2.371 ;
     RECT  66.312 2.263 66.906 2.371 ;
     RECT  68.94 2.191 69.03 2.371 ;
     RECT  2.415 2.143 2.505 2.413 ;
     RECT  29.016 2.371 29.505 2.413 ;
     RECT  59.328 2.263 61.905 2.413 ;
     RECT  50.58 2.371 53.226 2.443 ;
     RECT  5.472 2.371 5.562 2.461 ;
     RECT  6.444 2.299 6.462 2.461 ;
     RECT  7.56 2.371 9.126 2.461 ;
     RECT  34.815 2.371 36.27 2.461 ;
     RECT  37.044 2.371 37.062 2.461 ;
     RECT  41.94 2.299 43.578 2.461 ;
     RECT  48.816 2.227 49.734 2.461 ;
     RECT  50.58 2.443 53.298 2.461 ;
     RECT  54.504 2.371 55.314 2.461 ;
     RECT  56.16 2.371 57.546 2.461 ;
     RECT  65.772 2.371 66.906 2.461 ;
     RECT  5.472 2.461 5.67 2.488 ;
     RECT  16.2 2.335 17.262 2.488 ;
     RECT  29.016 2.413 29.697 2.488 ;
     RECT  30.456 2.335 31.014 2.488 ;
     RECT  6.444 2.461 9.126 2.491 ;
     RECT  10.44 2.371 10.962 2.491 ;
     RECT  11.844 2.335 14.886 2.491 ;
     RECT  27.072 2.371 27.594 2.491 ;
     RECT  28.98 2.488 31.014 2.491 ;
     RECT  32.148 2.263 33.246 2.491 ;
     RECT  41.724 2.461 43.902 2.497 ;
     RECT  44.784 2.371 48.042 2.497 ;
     RECT  48.816 2.461 57.546 2.497 ;
     RECT  58.32 2.371 58.554 2.497 ;
     RECT  34.815 2.461 37.062 2.533 ;
     RECT  68.796 2.371 69.03 2.533 ;
     RECT  15.912 2.488 17.262 2.569 ;
     RECT  18.18 2.263 19.134 2.569 ;
     RECT  28.98 2.491 33.354 2.569 ;
     RECT  38.628 2.371 40.842 2.569 ;
     RECT  41.724 2.497 57.546 2.569 ;
     RECT  65.304 2.461 66.906 2.569 ;
     RECT  58.32 2.497 58.59 2.587 ;
     RECT  59.328 2.413 62.097 2.587 ;
     RECT  34.815 2.533 37.854 2.605 ;
     RECT  38.628 2.569 57.546 2.605 ;
     RECT  58.32 2.587 62.097 2.605 ;
     RECT  3.996 2.461 4.014 2.641 ;
     RECT  5.148 2.488 5.67 2.641 ;
     RECT  6.444 2.491 9.558 2.641 ;
     RECT  10.44 2.491 14.886 2.641 ;
     RECT  15.912 2.569 19.134 2.641 ;
     RECT  19.98 2.371 22.086 2.641 ;
     RECT  22.86 2.371 23.166 2.641 ;
     RECT  24.015 2.371 26.298 2.641 ;
     RECT  27.072 2.491 27.81 2.641 ;
     RECT  28.98 2.569 33.606 2.641 ;
     RECT  34.815 2.605 63.234 2.641 ;
     RECT  68.4 2.533 69.03 2.641 ;
     RECT  3.996 2.641 9.594 2.731 ;
     RECT  10.44 2.641 19.134 2.731 ;
     RECT  65.304 2.569 67.59 2.731 ;
     RECT  68.4 2.641 69.102 2.731 ;
     RECT  3.996 2.731 19.134 2.803 ;
     RECT  19.98 2.641 26.298 2.803 ;
     RECT  65.304 2.731 69.102 2.803 ;
     RECT  3.636 2.803 26.298 2.875 ;
     RECT  27.072 2.641 63.774 2.875 ;
     RECT  3.492 2.875 63.774 3.379 ;
     RECT  2.415 2.413 2.697 3.415 ;
     RECT  3.492 3.379 64.206 3.415 ;
     RECT  2.415 3.415 64.206 3.451 ;
     RECT  2.415 3.451 64.278 3.541 ;
     RECT  65.16 2.803 69.102 3.541 ;
     RECT  2.415 3.541 69.102 3.847 ;
     RECT  2.376 3.847 69.102 3.983 ;
     RECT  2.376 3.983 18.99 4.649 ;
     RECT  2.415 4.649 18.99 4.765 ;
     RECT  19.8 3.983 69.102 4.765 ;
     RECT  2.415 4.765 69.102 6.179 ;
     RECT  2.415 6.179 69.03 6.571 ;
     RECT  2.376 6.571 69.03 6.881 ;
     RECT  2.376 6.881 68.994 6.989 ;
     RECT  2.376 6.989 68.958 7.181 ;
     RECT  2.376 7.181 66.906 7.357 ;
     RECT  2.34 7.357 66.906 7.897 ;
     RECT  68.076 7.181 68.958 8.005 ;
     RECT  67.824 8.005 68.958 8.011 ;
     RECT  0.036 7.435 0.054 8.041 ;
     RECT  0.036 8.041 0.414 8.131 ;
     RECT  67.824 8.011 69.03 8.141 ;
     RECT  68.4 8.141 69.03 8.621 ;
     RECT  0.036 8.131 0.558 8.971 ;
     RECT  0.036 8.971 0.666 9.101 ;
     RECT  2.304 7.897 66.906 9.121 ;
     RECT  2.268 9.121 66.906 9.643 ;
     RECT  0.036 9.101 0.594 9.677 ;
     RECT  2.268 9.643 67.302 9.689 ;
     RECT  2.268 9.689 66.906 9.895 ;
     RECT  68.76 8.621 69.03 10.027 ;
     RECT  68.364 10.027 69.03 10.123 ;
     RECT  67.788 10.123 69.03 10.399 ;
     RECT  67.788 10.399 69.102 10.603 ;
     RECT  1.98 9.895 66.906 10.795 ;
     RECT  67.752 10.603 69.102 10.795 ;
     RECT  0.036 9.677 0.558 10.859 ;
     RECT  1.98 10.795 69.102 11.201 ;
     RECT  67.752 11.201 69.102 11.399 ;
     RECT  0.108 10.859 0.558 11.597 ;
     RECT  1.98 11.201 66.726 11.669 ;
     RECT  0.144 11.597 0.558 11.789 ;
     RECT  1.98 11.669 66.654 11.939 ;
     RECT  1.98 11.939 66.618 12.077 ;
     RECT  2.088 12.077 66.618 12.269 ;
     RECT  1.116 11.851 1.134 12.317 ;
     RECT  0.144 11.789 0.27 12.559 ;
     RECT  2.232 12.269 66.618 12.749 ;
     RECT  2.304 12.749 66.618 12.785 ;
     RECT  2.376 12.785 66.618 12.811 ;
     RECT  0.144 12.559 0.558 13.027 ;
     RECT  2.376 12.811 66.69 13.063 ;
     RECT  68.328 11.399 69.102 13.127 ;
     RECT  68.328 13.127 69.03 13.163 ;
     RECT  2.376 13.063 66.726 13.289 ;
     RECT  2.376 13.289 66.618 13.567 ;
     RECT  0.108 13.027 0.558 13.675 ;
     RECT  0.108 13.675 1.278 14.045 ;
     RECT  68.4 13.163 69.03 14.155 ;
     RECT  0.108 14.045 1.206 14.171 ;
     RECT  68.364 14.155 69.03 14.635 ;
     RECT  2.304 13.567 66.618 14.675 ;
     RECT  2.376 14.675 66.618 14.881 ;
     RECT  68.328 14.635 69.03 15.179 ;
     RECT  2.376 14.881 66.654 15.211 ;
     RECT  0.108 14.171 0.558 15.437 ;
     RECT  2.376 15.211 66.69 15.601 ;
     RECT  0.144 15.437 0.558 15.725 ;
     RECT  2.376 15.601 66.762 15.871 ;
     RECT  68.688 15.179 69.03 15.979 ;
     RECT  67.788 15.307 67.806 16.075 ;
     RECT  68.652 15.979 69.03 16.075 ;
     RECT  2.376 15.871 66.798 16.219 ;
     RECT  0.144 15.725 0.342 16.301 ;
     RECT  2.376 16.219 66.834 16.375 ;
     RECT  1.152 16.267 1.278 16.397 ;
     RECT  2.376 16.375 66.87 16.459 ;
     RECT  2.376 16.459 66.978 16.747 ;
     RECT  67.788 16.075 69.03 16.747 ;
     RECT  0.144 16.301 0.27 16.781 ;
     RECT  2.376 16.747 69.03 16.951 ;
     RECT  0.144 16.781 0.234 17.068 ;
     RECT  0.108 17.068 0.234 17.117 ;
     RECT  1.152 16.397 1.17 17.117 ;
     RECT  2.376 16.951 69.102 17.227 ;
     RECT  0.108 17.117 0.126 17.357 ;
     RECT  0.216 18.523 0.234 18.571 ;
     RECT  0.108 18.571 0.234 18.667 ;
     RECT  0.108 18.667 0.342 18.967 ;
     RECT  0.108 18.967 0.378 19.085 ;
     RECT  0.108 19.085 0.342 19.103 ;
     RECT  0.144 19.103 0.342 19.277 ;
     RECT  2.304 17.227 69.102 19.915 ;
     RECT  0.144 19.277 0.234 20.011 ;
     RECT  0.144 20.011 0.378 20.141 ;
     RECT  0.144 20.141 0.234 20.285 ;
     RECT  0.216 20.285 0.234 20.525 ;
     RECT  1.728 19.915 69.102 20.723 ;
     RECT  0.108 21.067 0.162 21.259 ;
     RECT  1.728 20.723 68.994 21.497 ;
     RECT  1.728 21.497 68.958 21.929 ;
     RECT  68.292 21.929 68.958 22.109 ;
     RECT  0.108 21.259 0.378 22.157 ;
     RECT  68.292 22.109 68.31 22.235 ;
     RECT  1.728 21.929 67.554 22.351 ;
     RECT  0.108 22.157 0.342 22.541 ;
     RECT  0.108 22.541 0.198 22.589 ;
     RECT  1.116 22.351 67.554 22.739 ;
     RECT  1.116 22.739 67.014 22.811 ;
     RECT  1.116 22.811 66.51 22.925 ;
     RECT  1.728 22.925 66.51 23.009 ;
     RECT  1.728 23.009 66.258 23.045 ;
     RECT  0.108 22.589 0.162 23.659 ;
     RECT  1.764 23.045 66.006 23.693 ;
     RECT  2.232 23.693 66.006 23.819 ;
     RECT  0.108 23.659 0.342 23.885 ;
     RECT  0.108 23.885 0.27 23.933 ;
     RECT  66.816 23.971 66.834 24.161 ;
     RECT  0.108 23.933 0.234 24.233 ;
     RECT  0.108 24.233 0.198 24.809 ;
     RECT  2.232 23.819 65.97 24.979 ;
     RECT  0.18 24.809 0.198 25.079 ;
     RECT  2.232 24.979 66.006 25.555 ;
     RECT  2.232 25.555 66.042 25.591 ;
     RECT  2.232 25.591 66.15 25.861 ;
     RECT  2.232 25.861 66.294 26.131 ;
     RECT  2.232 26.131 66.834 26.789 ;
     RECT  2.304 26.789 66.834 26.933 ;
     RECT  0.216 27.403 0.234 27.409 ;
     RECT  0.216 27.409 0.558 27.481 ;
     RECT  0.18 27.481 0.558 27.571 ;
     RECT  0.108 27.571 0.558 27.599 ;
     RECT  2.304 26.933 66.222 27.599 ;
     RECT  2.34 27.599 66.222 27.715 ;
     RECT  0.108 27.599 0.342 27.725 ;
     RECT  2.34 27.715 66.654 27.751 ;
     RECT  68.472 27.301 68.49 27.841 ;
     RECT  2.34 27.751 67.23 27.913 ;
     RECT  0.108 27.725 0.306 28.013 ;
     RECT  0.18 28.013 0.306 28.109 ;
     RECT  68.436 27.841 68.49 28.183 ;
     RECT  68.4 28.183 68.49 28.381 ;
     RECT  2.34 27.913 67.266 28.417 ;
     RECT  68.4 28.381 68.562 28.651 ;
     RECT  2.304 28.417 67.266 28.687 ;
     RECT  68.4 28.651 68.598 28.687 ;
     RECT  2.304 28.687 68.598 28.688 ;
     RECT  0.18 28.109 0.27 28.747 ;
     RECT  0.108 28.747 0.27 29.131 ;
     RECT  0.108 29.131 0.414 29.261 ;
     RECT  2.34 28.688 68.598 30.181 ;
     RECT  0.108 29.261 0.342 30.226 ;
     RECT  2.304 30.181 68.598 30.317 ;
     RECT  2.34 30.317 68.598 30.509 ;
     RECT  67.824 30.509 68.598 30.571 ;
     RECT  67.824 30.571 68.994 30.763 ;
     RECT  0.108 30.226 0.594 30.766 ;
     RECT  0.072 30.766 0.594 31.109 ;
     RECT  0.144 31.109 0.594 31.217 ;
     RECT  2.34 30.509 66.834 31.379 ;
     RECT  2.34 31.379 66.654 31.415 ;
     RECT  67.824 30.763 69.03 31.627 ;
     RECT  2.415 31.415 66.654 31.649 ;
     RECT  67.788 31.627 69.03 31.723 ;
     RECT  0.144 31.217 0.342 31.757 ;
     RECT  67.752 31.723 69.03 31.819 ;
     RECT  67.716 31.819 69.03 32.107 ;
     RECT  0.252 31.757 0.342 32.189 ;
     RECT  67.68 32.107 69.03 32.189 ;
     RECT  68.76 32.189 69.03 32.369 ;
     RECT  2.415 31.649 66.33 32.809 ;
     RECT  67.68 32.189 67.806 32.837 ;
     RECT  2.415 32.809 66.402 32.881 ;
     RECT  67.68 32.837 67.77 32.999 ;
     RECT  2.415 32.881 66.474 33.151 ;
     RECT  0.252 32.189 0.27 33.269 ;
     RECT  67.68 32.999 67.734 33.269 ;
     RECT  67.68 33.269 67.698 33.341 ;
     RECT  2.376 33.151 66.474 33.385 ;
     RECT  2.376 33.385 66.618 33.413 ;
     RECT  2.376 33.413 43.47 33.539 ;
     RECT  44.208 33.413 66.618 33.539 ;
     RECT  2.376 33.539 43.434 33.575 ;
     RECT  68.796 32.369 69.03 33.809 ;
     RECT  2.376 33.575 43.362 33.931 ;
     RECT  0.288 33.835 0.486 33.961 ;
     RECT  44.208 33.539 66.51 33.989 ;
     RECT  44.208 33.989 64.35 34.231 ;
     RECT  0.288 33.961 0.558 34.253 ;
     RECT  65.376 33.989 66.51 34.321 ;
     RECT  0.288 34.253 0.342 34.459 ;
     RECT  2.304 33.931 43.362 34.459 ;
     RECT  44.172 34.231 64.35 34.459 ;
     RECT  65.376 34.321 66.546 34.465 ;
     RECT  0.18 34.459 0.342 34.501 ;
     RECT  65.376 34.465 66.69 34.501 ;
     RECT  2.304 34.459 64.35 34.637 ;
     RECT  68.868 33.809 69.03 34.663 ;
     RECT  67.824 34.393 67.842 34.699 ;
     RECT  68.868 34.663 69.102 34.699 ;
     RECT  2.34 34.637 64.35 34.735 ;
     RECT  65.376 34.501 66.834 34.735 ;
     RECT  67.824 34.699 69.102 34.735 ;
     RECT  0.108 34.501 0.342 35.167 ;
     RECT  2.34 34.735 69.102 35.371 ;
     RECT  1.98 35.371 69.102 35.549 ;
     RECT  0.108 35.167 0.558 35.803 ;
     RECT  2.304 35.549 69.102 35.885 ;
     RECT  67.824 35.885 69.102 35.981 ;
     RECT  67.86 35.981 69.102 36.149 ;
     RECT  67.86 36.149 69.03 36.269 ;
     RECT  2.304 35.885 66.726 36.365 ;
     RECT  0.108 35.803 0.63 36.481 ;
     RECT  0.108 36.481 0.846 36.509 ;
     RECT  2.304 36.365 66.69 36.509 ;
     RECT  67.896 36.269 69.03 36.941 ;
     RECT  2.304 36.509 66.654 37.363 ;
     RECT  0.18 36.509 0.846 37.483 ;
     RECT  0.108 37.483 0.846 37.903 ;
     RECT  68.364 36.941 69.03 37.963 ;
     RECT  67.752 37.963 69.03 38.059 ;
     RECT  0.072 37.903 0.846 38.155 ;
     RECT  2.304 37.363 66.726 38.165 ;
     RECT  67.716 38.059 69.03 38.471 ;
     RECT  68.688 38.471 69.03 38.777 ;
     RECT  67.716 38.471 67.77 38.939 ;
     RECT  0.072 38.155 0.882 39.208 ;
     RECT  0.072 39.208 1.242 39.211 ;
     RECT  68.688 38.777 68.994 39.281 ;
     RECT  0.072 39.211 1.35 39.317 ;
     RECT  0.072 39.317 1.314 39.341 ;
     RECT  2.34 38.165 66.726 39.403 ;
     RECT  67.716 38.939 67.734 39.479 ;
     RECT  2.304 39.403 66.726 39.515 ;
     RECT  68.688 39.281 68.922 39.587 ;
     RECT  68.688 39.587 68.886 40.055 ;
     RECT  0.072 39.341 0.882 40.063 ;
     RECT  2.376 39.515 66.726 40.064 ;
     RECT  2.376 40.064 66.618 40.163 ;
     RECT  0.072 40.063 1.17 40.199 ;
     RECT  68.832 40.055 68.886 40.199 ;
     RECT  68.832 40.199 68.85 40.289 ;
     RECT  65.376 40.163 66.618 40.325 ;
     RECT  2.376 40.163 64.026 40.459 ;
     RECT  65.376 40.325 66.438 40.559 ;
     RECT  65.376 40.559 65.394 40.595 ;
     RECT  67.824 40.801 67.842 41.143 ;
     RECT  1.98 40.459 64.026 41.179 ;
     RECT  66.42 40.559 66.438 41.215 ;
     RECT  1.98 41.179 64.098 41.251 ;
     RECT  66.42 41.215 66.618 41.251 ;
     RECT  67.824 41.143 67.878 41.341 ;
     RECT  66.42 41.251 66.834 41.419 ;
     RECT  67.824 41.341 68.418 41.449 ;
     RECT  0.108 40.199 1.17 41.477 ;
     RECT  66.42 41.419 66.87 41.485 ;
     RECT  65.808 41.485 66.87 41.521 ;
     RECT  67.824 41.449 68.49 41.521 ;
     RECT  0.144 41.477 1.17 41.675 ;
     RECT  0.252 41.675 1.17 41.711 ;
     RECT  65.448 41.521 68.49 41.917 ;
     RECT  0.576 41.711 1.17 41.945 ;
     RECT  1.98 41.251 64.674 41.989 ;
     RECT  65.448 41.917 68.598 41.989 ;
     RECT  1.98 41.989 68.598 42.061 ;
     RECT  1.98 42.061 68.67 42.989 ;
     RECT  1.98 42.989 66.834 43.085 ;
     RECT  67.644 42.989 68.67 43.181 ;
     RECT  1.152 41.945 1.17 43.231 ;
     RECT  0.54 43.231 1.17 43.295 ;
     RECT  0.54 43.295 0.558 43.853 ;
     RECT  0.18 43.915 0.342 44.011 ;
     RECT  67.824 43.181 68.67 44.011 ;
     RECT  1.98 43.085 66.798 44.069 ;
     RECT  67.824 44.011 69.03 44.107 ;
     RECT  1.98 44.069 66.726 44.339 ;
     RECT  0.108 44.011 0.342 44.429 ;
     RECT  67.788 44.107 69.03 44.587 ;
     RECT  0.108 44.429 0.234 44.909 ;
     RECT  1.98 44.339 66.474 44.915 ;
     RECT  67.752 44.587 69.03 45.067 ;
     RECT  67.716 45.067 69.03 45.491 ;
     RECT  2.304 44.915 66.474 45.571 ;
     RECT  67.716 45.491 68.994 45.689 ;
     RECT  0.144 44.909 0.162 45.691 ;
     RECT  0.144 45.691 0.234 45.739 ;
     RECT  67.752 45.689 68.994 45.761 ;
     RECT  67.752 45.761 68.958 45.959 ;
     RECT  0.144 45.739 0.342 46.003 ;
     RECT  2.304 45.571 66.726 46.201 ;
     RECT  68.364 45.959 68.958 46.229 ;
     RECT  2.304 46.201 66.762 46.301 ;
     RECT  68.4 46.229 68.958 46.301 ;
     RECT  0.108 46.003 0.342 46.637 ;
     RECT  0.108 46.637 0.234 46.733 ;
     RECT  68.796 46.301 68.958 46.841 ;
     RECT  68.796 46.841 68.814 47.039 ;
     RECT  0.108 46.733 0.126 47.165 ;
     RECT  2.304 46.301 66.726 47.461 ;
     RECT  2.304 47.461 66.798 47.659 ;
     RECT  2.304 47.659 67.23 47.695 ;
     RECT  68.472 47.623 68.49 47.695 ;
     RECT  2.304 47.695 68.49 47.885 ;
     RECT  2.376 47.885 68.49 48.091 ;
     RECT  2.376 48.091 68.562 48.541 ;
     RECT  2.376 48.541 68.598 48.667 ;
     RECT  2.376 48.667 68.634 49.549 ;
     RECT  0.036 49.279 0.054 49.963 ;
     RECT  2.34 49.549 68.634 49.997 ;
     RECT  0.036 49.963 0.126 50.011 ;
     RECT  2.34 49.997 66.726 50.093 ;
     RECT  2.34 50.093 66.474 50.152 ;
     RECT  67.752 49.997 68.634 50.155 ;
     RECT  2.304 50.152 66.474 50.189 ;
     RECT  0.036 50.011 0.198 50.251 ;
     RECT  0.036 50.251 0.234 50.539 ;
     RECT  67.752 50.155 69.03 50.557 ;
     RECT  67.752 50.557 69.102 50.731 ;
     RECT  67.716 50.731 69.102 50.827 ;
     RECT  0.036 50.539 0.342 50.86 ;
     RECT  0.036 50.86 0.378 50.957 ;
     RECT  67.68 50.827 69.102 51.211 ;
     RECT  2.34 50.189 66.474 51.241 ;
     RECT  2.34 51.241 66.726 51.331 ;
     RECT  0.036 50.957 0.342 51.739 ;
     RECT  0.036 51.739 0.414 51.809 ;
     RECT  67.644 51.211 69.102 51.899 ;
     RECT  1.728 51.331 66.726 51.971 ;
     RECT  67.68 51.899 69.102 52.169 ;
     RECT  1.152 52.027 1.278 52.205 ;
     RECT  67.716 52.169 69.102 52.277 ;
     RECT  68.364 52.277 69.102 52.439 ;
     RECT  2.304 51.971 66.726 52.475 ;
     RECT  2.304 52.475 66.366 52.493 ;
     RECT  68.94 52.439 69.102 52.709 ;
     RECT  0.036 51.809 0.342 52.781 ;
     RECT  1.26 52.205 1.278 52.781 ;
     RECT  0.036 52.781 0.234 52.877 ;
     RECT  68.94 52.709 68.994 52.979 ;
     RECT  2.415 52.493 66.366 53.123 ;
     RECT  0.108 52.877 0.234 53.357 ;
     RECT  68.94 52.979 68.958 53.491 ;
     RECT  65.736 53.123 66.366 53.563 ;
     RECT  0.18 53.357 0.234 53.627 ;
     RECT  68.4 53.491 68.958 53.797 ;
     RECT  67.824 53.797 68.958 53.833 ;
     RECT  65.736 53.563 66.834 53.905 ;
     RECT  65.628 53.905 66.834 54.103 ;
     RECT  67.824 53.833 69.102 54.103 ;
     RECT  65.628 54.103 69.102 54.175 ;
     RECT  2.415 53.123 64.566 54.211 ;
     RECT  65.376 54.175 69.102 54.211 ;
     RECT  0.18 53.627 0.198 54.779 ;
     RECT  2.415 54.211 69.102 55.565 ;
     RECT  2.415 55.565 66.654 55.949 ;
     RECT  67.788 55.565 69.102 56.021 ;
     RECT  67.788 56.021 69.03 56.491 ;
     RECT  67.752 56.491 69.03 56.587 ;
     RECT  2.415 55.949 66.582 56.765 ;
     RECT  67.716 56.587 69.03 56.971 ;
     RECT  3.816 56.765 66.582 57.065 ;
     RECT  4.32 57.065 66.582 57.181 ;
     RECT  67.68 56.971 69.03 57.335 ;
     RECT  67.68 57.335 67.806 57.451 ;
     RECT  4.32 57.181 66.762 57.541 ;
     RECT  68.796 57.335 69.03 57.547 ;
     RECT  67.644 57.451 67.806 57.839 ;
     RECT  68.796 57.547 69.066 57.947 ;
     RECT  67.644 57.839 67.77 58.109 ;
     RECT  4.32 57.541 66.798 58.225 ;
     RECT  3.888 58.225 66.798 58.379 ;
     RECT  67.644 58.109 67.734 58.379 ;
     RECT  64.548 58.379 66.798 58.459 ;
     RECT  67.716 58.379 67.734 58.649 ;
     RECT  3.888 58.379 63.594 58.721 ;
     RECT  2.415 56.765 2.697 59.161 ;
     RECT  64.548 58.459 66.834 59.189 ;
     RECT  2.415 59.161 2.79 59.269 ;
     RECT  3.888 58.721 63.486 59.269 ;
     RECT  2.415 59.269 63.486 59.503 ;
     RECT  64.548 59.189 64.602 59.503 ;
     RECT  65.448 59.189 66.834 59.531 ;
     RECT  65.52 59.531 66.762 59.603 ;
     RECT  68.868 57.947 69.066 59.639 ;
     RECT  65.52 59.603 66.366 59.729 ;
     RECT  68.976 59.639 69.066 59.729 ;
     RECT  2.415 59.503 64.602 59.765 ;
     RECT  65.628 59.729 66.366 59.765 ;
     RECT  69.048 59.729 69.066 59.999 ;
     RECT  65.628 59.765 65.646 60.035 ;
     RECT  2.415 59.765 64.422 60.269 ;
     RECT  52.344 60.269 64.35 60.305 ;
     RECT  2.415 60.269 51.57 60.523 ;
     RECT  2.304 60.523 51.57 60.575 ;
     RECT  0.036 60.241 0.054 60.961 ;
     RECT  2.376 60.575 51.57 61.051 ;
     RECT  52.344 60.305 64.278 61.051 ;
     RECT  2.376 61.051 64.278 61.393 ;
     RECT  2.376 61.393 64.494 61.889 ;
     RECT  2.376 61.889 64.422 62.923 ;
     RECT  0.036 60.961 0.558 63.019 ;
     RECT  2.304 62.923 64.422 63.085 ;
     RECT  0.036 63.019 0.666 63.149 ;
     RECT  2.304 63.085 64.458 63.419 ;
     RECT  2.304 63.419 64.17 64.201 ;
     RECT  2.304 64.201 64.35 64.355 ;
     RECT  0.036 63.149 0.594 64.589 ;
     RECT  66.276 64.705 66.294 64.741 ;
     RECT  68.076 64.939 68.094 65.101 ;
     RECT  2.304 64.355 64.242 65.227 ;
     RECT  66.276 64.741 66.87 65.245 ;
     RECT  2.268 65.227 64.242 65.273 ;
     RECT  2.304 65.273 64.242 65.281 ;
     RECT  66.24 65.245 66.87 65.281 ;
     RECT  68.076 65.101 68.166 65.281 ;
     RECT  0.036 64.589 0.342 65.443 ;
     RECT  66.24 65.281 68.166 65.509 ;
     RECT  66.06 65.509 68.166 65.641 ;
     RECT  65.988 65.641 68.166 65.713 ;
     RECT  65.988 65.713 68.238 65.785 ;
     RECT  0.036 65.443 0.378 66.019 ;
     RECT  2.304 65.281 64.278 66.091 ;
     RECT  65.484 65.785 68.238 66.091 ;
     RECT  69.084 65.641 69.102 66.253 ;
     RECT  2.304 66.091 68.238 66.379 ;
     RECT  69.048 66.253 69.102 66.451 ;
     RECT  2.268 66.379 68.238 66.676 ;
     RECT  68.976 66.451 69.102 66.676 ;
     RECT  2.268 66.676 69.102 66.785 ;
     RECT  0.036 66.019 0.558 66.829 ;
     RECT  0.036 66.829 1.134 67.003 ;
     RECT  0.036 67.003 1.17 67.667 ;
     RECT  2.304 66.785 69.102 68.251 ;
     RECT  0.036 67.667 0.558 68.429 ;
     RECT  2.268 68.251 69.102 68.491 ;
     RECT  2.232 68.491 69.102 68.675 ;
     RECT  2.268 68.675 69.102 68.819 ;
     RECT  2.304 68.819 69.102 69.449 ;
     RECT  2.304 69.449 69.03 69.593 ;
     RECT  0.036 68.429 0.162 69.739 ;
     RECT  0.036 69.739 0.342 69.799 ;
     RECT  0.036 69.799 0.558 70.157 ;
     RECT  2.304 69.593 5.382 70.375 ;
     RECT  6.156 69.593 69.03 70.375 ;
     RECT  2.304 70.375 69.03 70.891 ;
     RECT  2.268 70.891 69.03 71.405 ;
     RECT  0.036 70.157 0.342 71.597 ;
     RECT  0.036 71.597 0.234 71.789 ;
     RECT  2.268 71.405 67.554 71.915 ;
     RECT  0.036 71.789 0.198 71.933 ;
     RECT  68.4 71.405 69.03 72.077 ;
     RECT  68.4 72.077 68.958 72.139 ;
     RECT  68.364 72.139 68.958 72.427 ;
     RECT  2.304 71.915 67.554 72.725 ;
     RECT  68.328 72.427 68.958 73.037 ;
     RECT  68.94 73.037 68.958 73.099 ;
     RECT  2.376 72.725 67.554 73.229 ;
     RECT  67.536 73.229 67.554 73.709 ;
     RECT  2.376 73.229 66.762 73.769 ;
     RECT  67.788 73.741 67.806 73.805 ;
     RECT  68.94 73.099 69.03 73.867 ;
     RECT  68.364 73.867 69.03 73.966 ;
     RECT  2.415 73.769 66.762 74.083 ;
     RECT  2.415 74.083 66.798 74.573 ;
     RECT  68.364 73.966 69.102 74.579 ;
     RECT  68.904 74.579 69.102 74.621 ;
     RECT  2.415 74.573 66.762 74.651 ;
     RECT  0.036 71.933 0.054 74.659 ;
     RECT  0.036 74.659 0.126 74.687 ;
     RECT  67.788 74.731 67.806 75.307 ;
     RECT  68.94 74.621 69.102 75.355 ;
     RECT  67.752 75.307 67.806 75.499 ;
     RECT  0.108 74.687 0.126 75.541 ;
     RECT  67.716 75.499 67.806 75.547 ;
     RECT  68.904 75.355 69.102 75.547 ;
     RECT  0.108 75.541 0.558 75.787 ;
     RECT  2.415 74.651 66.69 75.811 ;
     RECT  67.716 75.547 69.102 75.929 ;
     RECT  2.415 75.811 66.762 76.045 ;
     RECT  2.376 76.045 66.762 76.073 ;
     RECT  2.376 76.073 66.582 76.363 ;
     RECT  67.716 75.929 69.03 76.505 ;
     RECT  0.108 75.787 0.594 76.555 ;
     RECT  0.108 76.555 0.702 76.685 ;
     RECT  2.304 76.363 66.582 76.819 ;
     RECT  2.304 76.819 66.726 77.045 ;
     RECT  2.304 77.045 5.274 77.611 ;
     RECT  67.788 76.505 69.03 77.611 ;
     RECT  1.98 77.611 5.274 77.863 ;
     RECT  6.084 77.045 66.726 77.863 ;
     RECT  1.98 77.863 66.726 78.187 ;
     RECT  1.404 78.187 66.726 78.283 ;
     RECT  1.404 78.283 66.762 78.359 ;
     RECT  1.404 78.359 66.726 78.665 ;
     RECT  0.108 76.685 0.594 78.893 ;
     RECT  0.54 78.893 0.594 78.935 ;
     RECT  67.716 77.611 69.03 78.971 ;
     RECT  0.54 78.935 0.558 79.583 ;
     RECT  1.404 78.665 66.69 79.753 ;
     RECT  68.364 78.971 69.03 79.757 ;
     RECT  1.404 79.753 66.762 80.329 ;
     RECT  0.108 79.723 0.342 80.527 ;
     RECT  0.072 80.527 0.342 80.587 ;
     RECT  68.4 79.757 69.03 80.621 ;
     RECT  0.072 80.587 0.522 80.717 ;
     RECT  1.404 80.329 66.834 80.717 ;
     RECT  68.4 80.621 68.994 80.813 ;
     RECT  1.404 80.717 66.726 81.365 ;
     RECT  1.728 81.365 66.726 81.571 ;
     RECT  68.832 80.813 68.994 81.643 ;
     RECT  1.728 81.571 66.762 81.671 ;
     RECT  68.364 81.643 68.994 81.679 ;
     RECT  1.728 81.671 66.618 81.869 ;
     RECT  67.824 81.679 68.994 81.931 ;
     RECT  67.536 81.931 68.994 82.123 ;
     RECT  1.728 81.869 66.474 82.175 ;
     RECT  0.072 80.717 0.234 82.315 ;
     RECT  0.072 82.315 0.846 82.651 ;
     RECT  2.232 82.175 66.474 82.759 ;
     RECT  0.072 82.651 1.17 82.877 ;
     RECT  2.232 82.759 66.726 83.641 ;
     RECT  67.536 82.123 69.03 83.641 ;
     RECT  2.232 83.641 69.03 83.836 ;
     RECT  0.072 82.877 0.846 83.867 ;
     RECT  0.072 83.867 0.306 83.875 ;
     RECT  2.196 83.836 69.03 83.933 ;
     RECT  2.232 83.933 69.03 84.371 ;
     RECT  0.036 83.875 0.306 84.811 ;
     RECT  1.152 84.571 1.17 84.893 ;
     RECT  0.036 84.811 0.342 84.941 ;
     RECT  2.268 84.371 69.03 84.947 ;
     RECT  0.036 84.941 0.306 85.037 ;
     RECT  2.304 84.947 69.03 85.145 ;
     RECT  0.036 85.037 0.162 85.469 ;
     RECT  2.34 85.145 69.03 86.225 ;
     RECT  2.376 86.225 69.03 87.269 ;
     RECT  0.036 85.469 0.126 87.511 ;
     RECT  2.415 87.269 69.03 87.539 ;
     RECT  0.036 87.511 0.558 87.917 ;
     RECT  2.415 87.539 68.958 88.171 ;
     RECT  2.376 88.171 68.958 88.187 ;
     RECT  2.376 88.187 68.922 88.349 ;
     RECT  2.415 88.349 68.922 88.529 ;
     RECT  2.415 88.529 68.85 88.655 ;
     RECT  0.036 87.917 0.09 88.727 ;
     RECT  65.736 88.655 68.85 89.195 ;
     RECT  65.772 89.195 68.85 89.339 ;
     RECT  65.772 89.339 68.238 89.429 ;
     RECT  65.772 89.429 68.166 89.735 ;
     RECT  66.564 89.735 68.166 89.807 ;
     RECT  0.036 88.727 0.054 89.879 ;
     RECT  68.112 89.807 68.166 89.969 ;
     RECT  66.564 89.807 66.978 90.005 ;
     RECT  2.415 88.655 64.962 90.121 ;
     RECT  65.772 89.735 65.79 90.121 ;
     RECT  68.148 89.969 68.166 90.239 ;
     RECT  2.415 90.121 65.79 90.383 ;
     RECT  3.456 90.383 65.79 90.509 ;
     RECT  3.456 90.509 65.142 90.545 ;
     RECT  66.6 90.005 66.978 90.779 ;
     RECT  3.528 90.545 65.07 90.815 ;
     RECT  3.852 90.815 65.07 90.959 ;
     RECT  66.6 90.779 66.906 91.049 ;
     RECT  66.6 91.049 66.618 91.085 ;
     RECT  3.96 90.959 65.07 91.471 ;
     RECT  3.96 91.471 65.214 91.589 ;
     RECT  3.96 91.589 65.07 91.661 ;
     RECT  3.996 91.661 65.07 91.757 ;
     RECT  3.996 91.757 64.674 91.859 ;
     RECT  3.996 91.859 64.602 91.967 ;
     RECT  65.988 91.741 66.006 92.003 ;
     RECT  4.068 91.967 64.602 92.129 ;
     RECT  5.724 92.129 64.602 92.165 ;
     RECT  28.404 92.165 64.602 92.273 ;
     RECT  5.724 92.165 26.514 92.309 ;
     RECT  4.068 92.129 4.158 92.399 ;
     RECT  4.932 92.129 4.95 92.399 ;
     RECT  5.904 92.309 26.514 92.399 ;
     RECT  28.404 92.273 63.522 92.399 ;
     RECT  5.904 92.399 8.406 92.435 ;
     RECT  28.404 92.399 35.946 92.435 ;
     RECT  36.864 92.399 63.522 92.435 ;
     RECT  36.864 92.435 39.33 92.471 ;
     RECT  9.216 92.399 21.402 92.507 ;
     RECT  36.864 92.471 39.078 92.507 ;
     RECT  54.792 92.435 63.522 92.507 ;
     RECT  38.34 92.507 39.078 92.525 ;
     RECT  38.34 92.525 38.97 92.543 ;
     RECT  58.824 92.507 63.522 92.543 ;
     RECT  23.4 92.399 26.514 92.579 ;
     RECT  38.484 92.543 38.97 92.579 ;
     RECT  16.92 92.507 21.402 92.621 ;
     RECT  22.284 92.399 22.482 92.621 ;
     RECT  2.415 90.383 2.697 92.627 ;
     RECT  5.976 92.435 8.406 92.669 ;
     RECT  9.216 92.507 16.146 92.669 ;
     RECT  16.92 92.621 20.934 92.669 ;
     RECT  22.284 92.621 22.302 92.669 ;
     RECT  23.832 92.579 26.514 92.669 ;
     RECT  28.404 92.435 35.622 92.669 ;
     RECT  36.864 92.507 37.422 92.669 ;
     RECT  38.484 92.579 38.862 92.669 ;
     RECT  40.215 92.435 41.202 92.669 ;
     RECT  42.048 92.435 54.018 92.669 ;
     RECT  54.792 92.507 57.654 92.669 ;
     RECT  58.896 92.543 63.522 92.669 ;
     RECT  5.976 92.669 7.905 92.705 ;
     RECT  9.216 92.669 9.558 92.705 ;
     RECT  10.404 92.669 12.114 92.705 ;
     RECT  13.215 92.669 15.642 92.705 ;
     RECT  17.784 92.669 18.705 92.705 ;
     RECT  26.244 92.669 26.442 92.705 ;
     RECT  33.444 92.669 35.622 92.705 ;
     RECT  36.864 92.669 37.134 92.705 ;
     RECT  38.484 92.669 38.502 92.705 ;
     RECT  40.215 92.669 40.374 92.705 ;
     RECT  43.056 92.669 43.686 92.705 ;
     RECT  49.032 92.669 49.662 92.705 ;
     RECT  51.84 92.669 52.65 92.705 ;
     RECT  53.604 92.669 54.018 92.705 ;
     RECT  54.792 92.669 55.386 92.705 ;
     RECT  61.596 92.669 63.414 92.705 ;
     RECT  64.404 92.273 64.602 92.705 ;
     RECT  56.415 92.669 56.79 92.717 ;
     RECT  5.976 92.705 6.462 92.728 ;
     RECT  55.368 92.705 55.386 92.728 ;
     RECT  7.2 92.705 7.905 92.741 ;
     RECT  10.404 92.705 12.006 92.741 ;
     RECT  17.784 92.705 17.802 92.741 ;
     RECT  45.036 92.669 45.705 92.741 ;
     RECT  46.98 92.669 48.294 92.741 ;
     RECT  59.94 92.669 60.534 92.741 ;
     RECT  47.376 92.741 48.294 92.765 ;
     RECT  14.112 92.705 14.994 92.777 ;
     RECT  31.608 92.669 32.634 92.777 ;
     RECT  34.776 92.705 35.622 92.777 ;
     RECT  37.116 92.705 37.134 92.777 ;
     RECT  47.376 92.765 48.006 92.777 ;
     RECT  51.84 92.705 52.578 92.777 ;
     RECT  53.604 92.705 53.622 92.777 ;
     RECT  6.444 92.728 6.462 92.813 ;
     RECT  9.54 92.705 9.558 92.813 ;
     RECT  10.836 92.741 12.006 92.813 ;
     RECT  19.98 92.669 19.998 92.813 ;
     RECT  26.244 92.705 26.262 92.813 ;
     RECT  28.404 92.669 28.422 92.813 ;
     RECT  30.744 92.669 30.762 92.813 ;
     RECT  34.776 92.777 34.905 92.813 ;
     RECT  42.048 92.669 42.066 92.813 ;
     RECT  43.668 92.705 43.686 92.813 ;
     RECT  45.396 92.741 45.705 92.813 ;
     RECT  47.412 92.777 48.006 92.813 ;
     RECT  49.032 92.705 49.122 92.813 ;
     RECT  50.508 92.669 51.105 92.813 ;
     RECT  51.84 92.777 52.398 92.813 ;
     RECT  59.94 92.741 59.958 92.813 ;
     RECT  61.596 92.705 62.586 92.813 ;
     RECT  63.396 92.705 63.414 92.813 ;
     RECT  29.412 92.669 29.505 92.819 ;
     RECT  58.896 92.669 58.914 92.819 ;
     RECT  10.836 92.813 10.854 92.849 ;
     RECT  14.256 92.777 14.994 92.849 ;
     RECT  32.22 92.777 32.238 92.849 ;
     RECT  33.948 92.705 33.966 92.849 ;
     RECT  47.988 92.813 48.006 92.849 ;
     RECT  52.38 92.813 52.398 92.849 ;
     RECT  61.815 92.813 62.586 92.849 ;
     RECT  64.404 92.705 64.422 92.849 ;
     RECT  2.415 92.627 2.505 92.897 ;
     RECT  7.815 92.741 7.905 92.897 ;
     RECT  13.215 92.705 13.305 92.897 ;
     RECT  18.615 92.705 18.705 92.897 ;
     RECT  24.015 92.669 24.105 92.897 ;
     RECT  29.415 92.819 29.505 92.897 ;
     RECT  34.815 92.813 34.905 92.897 ;
     RECT  40.215 92.705 40.305 92.897 ;
     RECT  45.615 92.813 45.705 92.897 ;
     RECT  51.015 92.813 51.105 92.897 ;
     RECT  56.415 92.717 56.505 92.897 ;
     RECT  61.815 92.849 61.905 92.897 ;
    LAYER M4 ;
     RECT  0.025 7.44 0.06 7.464 ;
     RECT  0.025 52.848 0.06 52.872 ;
     RECT  0.06 43.632 0.097 46.632 ;
     RECT  0.06 7.44 0.133 24.36 ;
     RECT  0.06 27.504 0.133 30.504 ;
     RECT  0.06 33.648 0.133 40.488 ;
     RECT  0.097 43.632 0.133 47.16 ;
     RECT  0.06 62.832 0.133 71.976 ;
     RECT  0.06 75.888 0.133 85.032 ;
     RECT  0.06 49.776 0.179 52.872 ;
     RECT  0.133 62.832 0.181 72.024 ;
     RECT  0.133 27.504 0.205 30.6 ;
     RECT  0.181 62.736 0.229 72.024 ;
     RECT  0.205 27.408 0.275 30.6 ;
     RECT  0.133 33.072 0.275 40.488 ;
     RECT  0.181 74.64 0.323 74.76 ;
     RECT  0.181 54.672 0.419 54.696 ;
     RECT  0.229 62.736 0.419 72.264 ;
     RECT  0.323 74.64 0.419 74.664 ;
     RECT  0.181 86.592 0.515 86.616 ;
     RECT  0.133 75.888 0.524 85.464 ;
     RECT  0.06 87.888 0.569 88.104 ;
     RECT  0.524 75.792 0.611 85.464 ;
     RECT  0.179 49.872 1.141 52.776 ;
     RECT  0.275 33.648 2.293 40.488 ;
     RECT  2.252 60.528 2.293 60.552 ;
     RECT  0.133 7.44 2.365 24.648 ;
     RECT  0.569 88.08 2.365 88.104 ;
     RECT  2.365 6.576 2.408 24.648 ;
     RECT  0.275 27.408 2.408 30.456 ;
     RECT  2.293 33.552 2.408 40.488 ;
     RECT  0.133 43.632 2.408 47.4 ;
     RECT  2.365 48.432 2.408 48.456 ;
     RECT  1.141 49.872 2.408 53.016 ;
     RECT  2.293 59.232 2.408 59.256 ;
     RECT  2.293 60.384 2.408 60.552 ;
     RECT  0.419 62.832 2.408 72.264 ;
     RECT  0.611 75.936 2.408 85.464 ;
     RECT  2.365 88.08 2.408 88.2 ;
     RECT  2.408 2.148 2.512 92.892 ;
     RECT  2.512 2.418 2.704 92.622 ;
     RECT  2.704 27.168 2.819 32.04 ;
     RECT  2.819 27.168 2.837 31.416 ;
     RECT  2.704 33.024 3.443 52.872 ;
     RECT  3.443 33.024 3.593 48.264 ;
     RECT  2.704 2.88 3.665 4.104 ;
     RECT  2.704 75.6 3.697 89.16 ;
     RECT  2.704 6.24 3.733 25.8 ;
     RECT  2.704 54.096 3.788 56.76 ;
     RECT  2.704 60.384 3.841 72.456 ;
     RECT  3.788 54.096 3.875 57.048 ;
     RECT  3.697 74.016 3.953 89.16 ;
     RECT  3.665 2.88 3.985 3.432 ;
     RECT  3.733 6.24 3.985 26.04 ;
     RECT  2.837 27.312 3.985 31.416 ;
     RECT  3.593 33.024 4.057 47.928 ;
     RECT  3.953 74.064 4.169 89.16 ;
     RECT  3.443 49.872 4.201 52.872 ;
     RECT  3.875 54.096 4.201 56.472 ;
     RECT  3.985 6.24 4.237 31.416 ;
     RECT  4.057 32.4 4.237 47.928 ;
     RECT  3.985 58.56 4.345 58.584 ;
     RECT  4.201 49.872 4.517 56.472 ;
     RECT  3.841 60.384 4.597 72.84 ;
     RECT  4.517 49.056 4.709 56.472 ;
     RECT  4.169 87.984 4.709 89.16 ;
     RECT  3.985 2.496 4.993 3.432 ;
     RECT  3.864 4.992 5.029 5.016 ;
     RECT  4.237 6.24 5.029 47.928 ;
     RECT  4.709 49.056 5.029 54.792 ;
     RECT  4.057 92.304 5.065 92.328 ;
     RECT  5.029 6.24 5.075 54.792 ;
     RECT  4.345 57.6 5.077 58.584 ;
     RECT  4.597 59.856 5.077 72.84 ;
     RECT  5.065 91.392 5.137 92.328 ;
     RECT  4.993 2.496 5.173 3.672 ;
     RECT  5.029 4.992 5.173 5.112 ;
     RECT  5.137 90.528 5.173 92.328 ;
     RECT  5.173 2.496 5.177 5.112 ;
     RECT  4.709 87.984 5.177 88.92 ;
     RECT  5.077 57.6 5.209 72.84 ;
     RECT  4.169 74.064 5.209 86.472 ;
     RECT  5.173 90.288 5.245 92.328 ;
     RECT  5.075 6.576 5.249 54.792 ;
     RECT  5.209 57.6 5.249 86.472 ;
     RECT  5.249 57.6 5.363 59.88 ;
     RECT  5.245 90.048 5.708 92.328 ;
     RECT  4.709 55.968 5.749 56.472 ;
     RECT  5.363 57.6 5.749 58.152 ;
     RECT  5.177 2.88 5.756 5.112 ;
     RECT  5.708 89.952 5.795 92.328 ;
     RECT  5.756 2.88 5.843 5.544 ;
     RECT  5.843 2.88 5.897 5.448 ;
     RECT  5.249 6.576 5.897 54.696 ;
     RECT  5.363 59.232 5.897 59.88 ;
     RECT  5.249 60.96 5.933 86.472 ;
     RECT  5.795 90.48 5.965 92.328 ;
     RECT  5.965 90.48 6.041 92.712 ;
     RECT  5.933 75.744 6.073 86.472 ;
     RECT  5.749 55.968 6.149 58.152 ;
     RECT  5.897 59.232 6.149 59.256 ;
     RECT  5.933 60.96 6.149 74.664 ;
     RECT  5.897 26.016 6.253 54.696 ;
     RECT  6.149 55.968 6.253 57.96 ;
     RECT  5.177 88.08 6.253 88.92 ;
     RECT  6.073 75.744 6.325 87.096 ;
     RECT  6.253 88.08 6.325 89.352 ;
     RECT  6.149 60.96 6.505 74.568 ;
     RECT  5.897 6.576 6.509 25.032 ;
     RECT  5.897 3.696 6.515 5.448 ;
     RECT  6.041 90.48 6.545 90.936 ;
     RECT  6.515 3.696 6.761 5.112 ;
     RECT  6.253 26.016 6.833 57.96 ;
     RECT  7.045 2.496 7.225 2.52 ;
     RECT  6.761 3.696 7.225 4.632 ;
     RECT  6.509 6.576 7.513 24.744 ;
     RECT  6.833 26.016 7.513 26.424 ;
     RECT  6.505 60.432 7.549 74.568 ;
     RECT  6.325 75.744 7.549 89.352 ;
     RECT  6.545 90.48 7.549 90.648 ;
     RECT  7.549 60.432 7.657 90.648 ;
     RECT  7.436 59.04 7.693 59.064 ;
     RECT  7.657 60.336 7.693 90.648 ;
     RECT  6.833 27.408 7.765 57.96 ;
     RECT  7.693 59.04 7.765 90.648 ;
     RECT  7.225 2.496 7.808 4.632 ;
     RECT  7.513 6.576 7.808 26.424 ;
     RECT  7.765 27.408 7.808 90.648 ;
     RECT  6.041 92.16 7.808 92.712 ;
     RECT  7.808 2.148 7.912 92.892 ;
     RECT  7.912 2.418 8.104 92.622 ;
     RECT  8.104 54.384 8.381 58.248 ;
     RECT  8.104 6.576 8.387 53.352 ;
     RECT  8.381 54.912 8.453 58.248 ;
     RECT  8.387 43.344 8.525 53.352 ;
     RECT  8.104 73.344 8.579 90.648 ;
     RECT  8.104 59.568 9.169 61.752 ;
     RECT  8.104 62.784 9.169 72.264 ;
     RECT  8.104 91.92 9.205 91.944 ;
     RECT  8.453 54.912 9.245 58.152 ;
     RECT  9.169 59.568 9.277 72.264 ;
     RECT  8.579 73.344 9.317 90.264 ;
     RECT  9.277 59.184 9.493 72.264 ;
     RECT  9.317 73.344 9.493 88.872 ;
     RECT  8.525 43.872 9.565 53.352 ;
     RECT  8.104 2.496 9.569 4.488 ;
     RECT  9.245 54.96 9.677 58.152 ;
     RECT  9.565 43.488 9.685 53.352 ;
     RECT  8.387 6.576 9.709 42.264 ;
     RECT  9.569 3.12 9.713 4.488 ;
     RECT  9.713 3.12 9.785 3.144 ;
     RECT  9.317 90.048 9.853 90.264 ;
     RECT  9.205 91.92 10.028 92.664 ;
     RECT  9.709 6.144 10.037 42.264 ;
     RECT  9.685 43.296 10.105 53.352 ;
     RECT  10.037 6.144 10.109 26.232 ;
     RECT  10.105 43.296 10.109 53.592 ;
     RECT  9.677 54.96 10.109 57.624 ;
     RECT  10.028 91.296 10.115 92.664 ;
     RECT  10.109 43.872 10.217 53.592 ;
     RECT  10.109 55.2 10.253 57.624 ;
     RECT  9.493 59.184 10.289 88.872 ;
     RECT  10.115 92.112 10.325 92.136 ;
     RECT  10.037 27.216 10.397 42.264 ;
     RECT  9.713 4.464 10.465 4.488 ;
     RECT  10.397 27.408 10.469 42.264 ;
     RECT  10.289 59.184 10.537 59.208 ;
     RECT  10.253 55.488 10.577 57.624 ;
     RECT  10.577 57.12 10.645 57.624 ;
     RECT  10.537 58.992 10.645 59.208 ;
     RECT  10.289 60.384 10.681 88.872 ;
     RECT  9.853 90.048 10.681 90.312 ;
     RECT  10.109 6.144 10.753 26.184 ;
     RECT  10.681 60.384 10.753 90.312 ;
     RECT  10.217 48.72 10.825 53.592 ;
     RECT  10.825 2.256 10.933 2.28 ;
     RECT  10.753 60.384 10.937 90.36 ;
     RECT  10.933 2.256 10.979 2.904 ;
     RECT  10.217 43.872 11.077 47.496 ;
     RECT  10.937 73.824 11.153 90.36 ;
     RECT  10.469 33.36 11.221 42.264 ;
     RECT  11.153 74.544 11.324 90.36 ;
     RECT  10.465 4.464 11.329 4.536 ;
     RECT  10.753 5.616 11.329 26.184 ;
     RECT  11.077 43.344 11.516 47.496 ;
     RECT  10.825 48.72 11.516 53.928 ;
     RECT  11.329 4.464 11.545 26.184 ;
     RECT  10.645 57.12 11.612 59.208 ;
     RECT  10.937 60.384 11.612 72.552 ;
     RECT  11.324 74.544 11.617 90.744 ;
     RECT  11.324 91.824 11.617 91.848 ;
     RECT  11.612 57.12 11.699 72.552 ;
     RECT  10.979 2.496 11.761 2.904 ;
     RECT  11.545 4.464 11.761 26.376 ;
     RECT  10.577 55.488 11.869 55.512 ;
     RECT  11.699 57.12 11.905 59.208 ;
     RECT  11.699 60.336 11.977 72.552 ;
     RECT  11.516 43.344 11.989 53.928 ;
     RECT  11.869 55.488 11.989 55.752 ;
     RECT  11.989 43.344 12.035 55.752 ;
     RECT  10.469 27.408 12.049 32.28 ;
     RECT  11.221 33.36 12.049 42.312 ;
     RECT  11.905 57.024 12.053 59.208 ;
     RECT  12.049 27.408 12.133 42.312 ;
     RECT  12.035 43.344 12.133 53.592 ;
     RECT  12.133 27.408 12.197 53.592 ;
     RECT  11.617 74.544 12.229 91.848 ;
     RECT  12.229 74.16 12.301 91.848 ;
     RECT  11.761 2.496 12.409 26.376 ;
     RECT  12.197 27.408 12.625 47.448 ;
     RECT  12.409 2.256 12.733 26.376 ;
     RECT  12.625 27.36 12.733 47.448 ;
     RECT  11.977 60.336 12.733 72.744 ;
     RECT  12.733 60.336 12.769 73.032 ;
     RECT  12.301 74.16 12.769 92.376 ;
     RECT  12.035 54.576 12.841 55.752 ;
     RECT  12.053 57.024 12.841 57.144 ;
     RECT  12.197 48.432 13.093 53.592 ;
     RECT  12.841 54.576 13.093 57.144 ;
     RECT  12.053 58.464 13.165 59.208 ;
     RECT  12.733 2.256 13.208 47.448 ;
     RECT  13.093 48.432 13.208 57.144 ;
     RECT  13.165 58.464 13.208 59.256 ;
     RECT  12.769 60.336 13.208 92.376 ;
     RECT  13.208 2.148 13.312 92.892 ;
     RECT  13.312 2.256 13.504 92.622 ;
     RECT  13.504 2.256 13.637 2.904 ;
     RECT  13.504 3.888 13.637 53.592 ;
     RECT  13.637 3.888 13.817 5.88 ;
     RECT  13.637 2.256 14.357 2.856 ;
     RECT  13.637 6.864 14.537 53.592 ;
     RECT  14.537 26.352 14.569 53.592 ;
     RECT  13.504 54.624 14.569 57.144 ;
     RECT  14.537 6.864 14.645 25.368 ;
     RECT  13.817 4.464 14.771 5.736 ;
     RECT  13.504 58.128 14.867 92.28 ;
     RECT  14.867 58.128 14.905 91.752 ;
     RECT  14.569 26.352 14.965 57.144 ;
     RECT  14.905 58.128 14.965 91.176 ;
     RECT  14.965 26.352 15.509 91.176 ;
     RECT  14.645 6.912 15.649 25.368 ;
     RECT  15.509 26.352 15.649 90.744 ;
     RECT  15.649 6.912 15.653 90.744 ;
     RECT  15.653 7.392 15.725 90.744 ;
     RECT  15.725 7.392 15.761 61.608 ;
     RECT  14.357 2.496 15.829 2.856 ;
     RECT  15.725 63.12 15.977 90.744 ;
     RECT  15.829 2.496 16.189 3.432 ;
     RECT  14.771 4.464 16.189 4.872 ;
     RECT  16.189 2.496 16.261 4.872 ;
     RECT  16.261 2.496 16.355 5.064 ;
     RECT  16.355 2.496 16.549 2.904 ;
     RECT  16.355 4.272 16.729 5.064 ;
     RECT  15.977 74.016 16.945 90.744 ;
     RECT  15.761 7.392 16.981 56.616 ;
     RECT  16.729 4.272 17.053 5.544 ;
     RECT  16.981 6.864 17.053 56.616 ;
     RECT  17.053 4.272 17.089 56.616 ;
     RECT  15.977 63.12 17.089 72.744 ;
     RECT  15.761 57.648 17.161 61.608 ;
     RECT  17.089 63.12 17.161 72.792 ;
     RECT  16.945 74.016 17.161 90.888 ;
     RECT  17.089 4.272 17.237 56.664 ;
     RECT  17.161 73.92 17.237 90.888 ;
     RECT  17.161 57.648 17.305 72.792 ;
     RECT  17.237 73.92 17.305 90.84 ;
     RECT  17.237 6.864 17.345 56.664 ;
     RECT  17.237 4.272 17.377 5.544 ;
     RECT  17.305 57.648 17.381 90.84 ;
     RECT  17.377 4.176 17.449 5.544 ;
     RECT  16.549 2.256 17.605 2.904 ;
     RECT  17.449 4.128 17.605 5.544 ;
     RECT  17.345 7.392 18.349 56.664 ;
     RECT  17.605 2.256 18.469 5.544 ;
     RECT  17.381 58.176 18.529 90.84 ;
     RECT  18.469 2.256 18.608 5.64 ;
     RECT  18.349 6.864 18.608 56.664 ;
     RECT  18.529 58.128 18.608 90.84 ;
     RECT  15.973 92.352 18.608 92.376 ;
     RECT  18.608 2.148 18.712 92.892 ;
     RECT  18.712 2.418 18.904 92.622 ;
     RECT  18.904 2.496 18.965 91.752 ;
     RECT  18.965 7.104 19.043 91.752 ;
     RECT  18.965 2.496 19.073 6.12 ;
     RECT  19.043 58.128 19.253 91.752 ;
     RECT  19.253 58.176 19.541 91.752 ;
     RECT  19.043 55.728 19.619 56.616 ;
     RECT  19.541 91.728 19.925 91.752 ;
     RECT  19.073 3.408 20.108 6.12 ;
     RECT  20.108 3.36 20.149 6.12 ;
     RECT  19.541 58.176 20.293 90.696 ;
     RECT  20.149 2.832 20.401 6.12 ;
     RECT  19.043 7.104 20.401 54.696 ;
     RECT  19.619 56.304 20.581 56.616 ;
     RECT  20.293 57.648 20.581 90.696 ;
     RECT  20.581 56.304 20.585 90.696 ;
     RECT  20.585 75.168 20.689 90.696 ;
     RECT  19.925 91.728 20.689 92.376 ;
     RECT  20.585 56.304 20.723 74.184 ;
     RECT  20.401 2.832 20.765 55.272 ;
     RECT  20.765 2.832 20.905 5.304 ;
     RECT  20.905 2.64 20.941 5.304 ;
     RECT  20.689 75.168 21.197 92.376 ;
     RECT  21.197 90 21.373 92.376 ;
     RECT  21.373 90 21.484 92.616 ;
     RECT  20.941 2.304 21.74 5.304 ;
     RECT  20.765 6.432 22.057 25.08 ;
     RECT  20.765 26.064 22.057 55.272 ;
     RECT  20.723 56.736 22.165 74.184 ;
     RECT  22.057 6.432 22.201 55.272 ;
     RECT  22.165 56.4 22.201 74.184 ;
     RECT  21.484 92.352 22.357 92.616 ;
     RECT  21.197 75.168 22.453 88.968 ;
     RECT  21.484 90 22.453 90.888 ;
     RECT  22.453 75.168 22.499 90.888 ;
     RECT  22.499 90.576 22.637 90.888 ;
     RECT  21.74 2.304 22.669 5.448 ;
     RECT  22.201 6.432 22.669 74.184 ;
     RECT  22.637 90.576 22.781 90.792 ;
     RECT  22.499 75.168 23.497 89.112 ;
     RECT  22.781 90.576 23.497 90.6 ;
     RECT  22.669 2.304 24.008 74.184 ;
     RECT  23.497 75.168 24.008 90.6 ;
     RECT  22.357 92.592 24.008 92.616 ;
     RECT  24.008 2.148 24.112 92.892 ;
     RECT  24.112 2.304 24.304 92.622 ;
     RECT  24.304 5.712 24.509 58.968 ;
     RECT  24.304 2.304 24.581 4.488 ;
     RECT  24.581 2.304 25.085 4.392 ;
     RECT  24.509 56.16 25.229 58.968 ;
     RECT  25.229 57.888 25.292 58.968 ;
     RECT  24.304 60.096 25.292 90.264 ;
     RECT  24.304 91.92 25.337 92.424 ;
     RECT  25.292 57.888 25.405 90.264 ;
     RECT  25.337 92.4 25.769 92.424 ;
     RECT  25.085 4.176 25.801 4.392 ;
     RECT  24.509 5.712 25.801 54.936 ;
     RECT  25.405 57.888 25.805 90.648 ;
     RECT  25.085 2.304 26.108 3.192 ;
     RECT  26.108 2.256 26.195 3.192 ;
     RECT  25.801 4.176 26.195 54.936 ;
     RECT  25.805 57.888 26.243 73.8 ;
     RECT  25.805 74.832 26.444 90.648 ;
     RECT  26.444 74.832 26.485 91.368 ;
     RECT  26.485 74.832 26.597 91.896 ;
     RECT  26.195 2.88 26.633 3.192 ;
     RECT  25.229 56.16 26.773 56.52 ;
     RECT  26.195 6.384 26.813 54.936 ;
     RECT  26.597 88.704 26.845 91.896 ;
     RECT  26.773 56.16 26.881 56.808 ;
     RECT  26.243 57.888 26.881 59.256 ;
     RECT  26.243 60.24 26.917 73.8 ;
     RECT  26.597 74.832 26.917 87.624 ;
     RECT  26.881 56.16 27.025 59.256 ;
     RECT  26.813 6.384 27.065 54.744 ;
     RECT  26.633 3.072 27.241 3.192 ;
     RECT  26.195 4.176 27.241 5.208 ;
     RECT  27.241 3.072 27.277 5.208 ;
     RECT  27.065 6.384 27.277 54.216 ;
     RECT  27.277 3.072 27.361 54.216 ;
     RECT  27.361 3.072 27.389 4.824 ;
     RECT  27.361 5.808 27.605 54.216 ;
     RECT  26.917 60.24 27.713 87.624 ;
     RECT  27.389 3.072 27.781 4.488 ;
     RECT  27.713 63.024 28.117 87.624 ;
     RECT  26.845 88.704 28.117 91.992 ;
     RECT  27.781 2.496 28.357 4.488 ;
     RECT  27.605 5.808 28.357 25.32 ;
     RECT  27.025 55.872 28.361 59.256 ;
     RECT  28.117 63.024 28.393 91.992 ;
     RECT  28.357 2.496 28.681 25.32 ;
     RECT  27.605 26.304 28.681 54.216 ;
     RECT  27.713 60.24 28.717 62.04 ;
     RECT  28.393 63.024 28.717 92.808 ;
     RECT  28.681 2.496 28.825 54.216 ;
     RECT  28.825 2.496 29.041 54.36 ;
     RECT  29.041 2.496 29.269 54.744 ;
     RECT  28.361 55.872 29.269 56.616 ;
     RECT  29.269 2.496 29.408 56.616 ;
     RECT  28.361 57.648 29.408 59.256 ;
     RECT  28.717 60.24 29.408 92.808 ;
     RECT  29.408 2.148 29.512 92.892 ;
     RECT  29.512 2.418 29.704 92.622 ;
     RECT  29.704 2.496 29.801 58.968 ;
     RECT  29.704 74.448 29.801 91.464 ;
     RECT  29.801 2.496 30.089 56.856 ;
     RECT  30.089 2.496 30.341 55.56 ;
     RECT  30.341 18.816 30.485 55.56 ;
     RECT  30.485 18.816 30.521 55.32 ;
     RECT  29.704 60.624 30.733 73.368 ;
     RECT  29.801 91.344 30.733 91.464 ;
     RECT  30.521 18.816 30.755 26.808 ;
     RECT  29.801 57.936 30.769 58.968 ;
     RECT  30.769 57.936 30.805 59.352 ;
     RECT  30.733 60.384 30.805 73.368 ;
     RECT  30.805 57.936 30.949 73.368 ;
     RECT  30.949 57.936 30.953 73.416 ;
     RECT  30.089 56.64 30.989 56.856 ;
     RECT  30.953 60.384 30.989 73.416 ;
     RECT  29.801 74.448 31.093 90.36 ;
     RECT  30.733 91.344 31.093 92.328 ;
     RECT  30.341 2.496 31.309 17.688 ;
     RECT  30.755 18.816 31.309 25.272 ;
     RECT  30.989 56.832 31.349 56.856 ;
     RECT  30.953 57.936 31.453 59.352 ;
     RECT  31.093 74.448 31.705 92.328 ;
     RECT  30.521 27.984 31.817 55.32 ;
     RECT  31.817 27.984 31.853 54.888 ;
     RECT  30.755 26.304 31.957 26.808 ;
     RECT  31.853 27.984 31.957 40.152 ;
     RECT  31.453 57.072 31.957 59.352 ;
     RECT  31.853 41.376 32.033 54.888 ;
     RECT  31.309 2.496 32.173 25.272 ;
     RECT  32.173 2.496 32.357 25.32 ;
     RECT  31.957 57.072 32.492 59.496 ;
     RECT  30.989 60.624 32.492 73.416 ;
     RECT  32.492 57.072 32.579 73.416 ;
     RECT  32.579 57.072 32.677 59.496 ;
     RECT  31.705 74.448 32.717 92.472 ;
     RECT  32.357 3.936 32.749 25.32 ;
     RECT  31.957 26.304 32.749 40.152 ;
     RECT  32.717 74.448 32.771 91.224 ;
     RECT  32.749 3.936 32.857 40.152 ;
     RECT  32.033 41.376 32.857 47.4 ;
     RECT  32.579 60.624 32.857 73.416 ;
     RECT  32.771 74.448 32.857 91.032 ;
     RECT  32.033 48.432 33.037 54.888 ;
     RECT  32.677 57.024 33.145 59.496 ;
     RECT  32.857 60.624 33.149 91.032 ;
     RECT  33.037 48.432 33.253 55.848 ;
     RECT  33.145 56.88 33.253 59.496 ;
     RECT  33.149 60.624 33.257 90.264 ;
     RECT  32.717 92.352 33.257 92.472 ;
     RECT  32.357 2.496 33.365 2.808 ;
     RECT  32.857 3.936 33.577 47.4 ;
     RECT  33.257 60.624 33.581 87.912 ;
     RECT  33.577 3.312 33.617 47.4 ;
     RECT  33.253 48.432 33.725 59.496 ;
     RECT  33.257 88.944 34.261 89.784 ;
     RECT  33.257 92.352 34.405 92.376 ;
     RECT  34.261 88.944 34.412 90.264 ;
     RECT  34.412 88.944 34.729 90.408 ;
     RECT  33.617 3.312 34.808 24.504 ;
     RECT  33.617 25.488 34.808 47.4 ;
     RECT  33.725 48.432 34.808 58.776 ;
     RECT  33.829 59.76 34.808 59.784 ;
     RECT  33.581 60.864 34.808 87.912 ;
     RECT  34.729 88.944 34.808 90.648 ;
     RECT  34.405 91.968 34.808 92.376 ;
     RECT  34.808 2.148 34.912 92.892 ;
     RECT  34.912 2.304 35.104 92.622 ;
     RECT  35.104 2.304 35.363 58.728 ;
     RECT  35.104 59.76 35.381 91.992 ;
     RECT  35.381 59.76 35.597 90.936 ;
     RECT  35.363 2.304 36.137 58.392 ;
     RECT  36.137 2.928 36.353 58.392 ;
     RECT  36.353 25.776 36.457 58.392 ;
     RECT  35.597 59.76 36.457 89.784 ;
     RECT  36.457 25.776 36.497 89.784 ;
     RECT  36.497 60.432 36.893 89.784 ;
     RECT  36.497 25.776 36.929 59.16 ;
     RECT  35.381 91.968 36.961 91.992 ;
     RECT  35.597 90.816 37.033 90.936 ;
     RECT  36.961 91.968 37.033 92.328 ;
     RECT  36.893 60.48 37.109 89.784 ;
     RECT  37.033 90.816 37.475 92.328 ;
     RECT  36.353 2.928 37.537 24.792 ;
     RECT  36.929 25.776 37.537 58.056 ;
     RECT  36.929 59.136 37.969 59.16 ;
     RECT  37.537 2.928 38.012 58.056 ;
     RECT  37.969 59.136 38.077 59.64 ;
     RECT  37.109 60.768 38.077 89.784 ;
     RECT  38.012 2.64 38.099 58.056 ;
     RECT  38.099 3.072 38.113 58.056 ;
     RECT  38.077 59.136 38.113 89.784 ;
     RECT  37.475 90.816 38.113 91.08 ;
     RECT  37.475 92.304 38.581 92.328 ;
     RECT  38.581 92.304 38.621 92.52 ;
     RECT  38.113 3.072 38.675 91.08 ;
     RECT  38.675 3.072 38.909 3.144 ;
     RECT  38.675 4.128 38.963 91.08 ;
     RECT  38.621 92.496 39.089 92.52 ;
     RECT  38.963 27.6 39.301 91.08 ;
     RECT  39.301 27.6 39.805 91.224 ;
     RECT  38.909 3.12 40.021 3.144 ;
     RECT  39.805 27.6 40.069 91.752 ;
     RECT  40.021 2.784 40.208 3.144 ;
     RECT  38.963 4.128 40.208 26.616 ;
     RECT  40.069 27.6 40.208 92.52 ;
     RECT  40.208 2.148 40.312 92.892 ;
     RECT  40.312 2.418 40.504 92.622 ;
     RECT  40.504 2.784 40.565 90.312 ;
     RECT  40.565 4.704 40.709 90.312 ;
     RECT  40.709 4.704 41.027 41.496 ;
     RECT  40.504 91.44 41.213 91.896 ;
     RECT  41.027 4.704 41.452 26.76 ;
     RECT  40.709 42.624 41.493 90.312 ;
     RECT  41.027 27.888 41.573 41.496 ;
     RECT  41.213 91.632 41.641 91.896 ;
     RECT  40.565 2.784 41.66 3.72 ;
     RECT  41.452 4.704 41.66 26.712 ;
     RECT  41.66 2.784 41.929 26.712 ;
     RECT  41.641 91.632 42.037 92.184 ;
     RECT  42.037 91.632 42.401 92.808 ;
     RECT  42.401 91.632 42.428 91.704 ;
     RECT  41.493 42.624 42.853 54.984 ;
     RECT  41.493 55.968 42.853 90.312 ;
     RECT  42.853 42.624 42.941 90.312 ;
     RECT  42.941 55.968 43.157 90.312 ;
     RECT  41.573 27.936 43.189 41.496 ;
     RECT  42.941 42.624 43.189 54.984 ;
     RECT  42.428 91.44 43.261 91.704 ;
     RECT  43.261 91.2 43.265 91.704 ;
     RECT  41.929 2.256 43.549 26.712 ;
     RECT  43.189 27.936 43.549 54.984 ;
     RECT  43.265 91.2 43.625 91.464 ;
     RECT  42.401 92.784 43.697 92.808 ;
     RECT  43.549 2.256 43.957 54.984 ;
     RECT  43.157 55.968 43.957 89.832 ;
     RECT  43.957 2.256 44.233 89.832 ;
     RECT  43.625 91.2 44.233 91.368 ;
     RECT  44.233 2.256 45.608 91.368 ;
     RECT  45.608 2.148 45.712 92.892 ;
     RECT  45.712 2.418 45.904 92.622 ;
     RECT  45.904 2.592 46.019 92.376 ;
     RECT  46.019 59.76 46.037 92.376 ;
     RECT  46.019 2.592 46.361 58.68 ;
     RECT  46.037 59.76 46.595 91.848 ;
     RECT  46.361 20.304 46.937 58.68 ;
     RECT  46.937 20.304 47.045 25.464 ;
     RECT  46.937 26.736 47.225 58.68 ;
     RECT  47.225 27.312 47.333 58.68 ;
     RECT  46.361 2.592 47.365 19.32 ;
     RECT  46.595 59.76 47.477 91.224 ;
     RECT  47.333 27.552 47.617 58.68 ;
     RECT  47.477 59.76 47.617 61.752 ;
     RECT  47.329 92.352 47.833 92.376 ;
     RECT  47.365 2.496 47.869 19.32 ;
     RECT  47.869 2.256 47.977 19.32 ;
     RECT  47.045 20.304 47.977 25.416 ;
     RECT  47.617 27.552 48.125 61.752 ;
     RECT  47.977 2.256 48.193 25.416 ;
     RECT  47.477 62.736 48.229 91.224 ;
     RECT  47.833 92.352 48.229 92.76 ;
     RECT  48.229 62.736 48.305 92.76 ;
     RECT  48.305 62.736 48.341 92.52 ;
     RECT  48.193 2.256 48.437 26.232 ;
     RECT  48.125 27.552 48.437 61.608 ;
     RECT  48.437 2.256 48.851 61.608 ;
     RECT  48.851 2.256 49.061 60.888 ;
     RECT  48.341 62.736 49.093 92.376 ;
     RECT  49.061 2.496 49.277 60.888 ;
     RECT  49.277 23.904 49.529 60.888 ;
     RECT  49.093 62.592 49.673 92.376 ;
     RECT  49.673 62.592 49.993 91.992 ;
     RECT  49.529 60 50.209 60.888 ;
     RECT  50.209 60 50.533 60.984 ;
     RECT  49.993 62.16 50.533 91.992 ;
     RECT  49.277 2.496 50.569 22.872 ;
     RECT  49.529 23.904 50.749 58.44 ;
     RECT  50.533 60 50.749 91.992 ;
     RECT  50.569 2.256 51.008 22.872 ;
     RECT  50.749 23.904 51.008 91.992 ;
     RECT  51.008 2.148 51.112 92.892 ;
     RECT  51.112 2.4 51.149 92.622 ;
     RECT  51.149 2.418 51.304 92.622 ;
     RECT  51.304 2.496 51.401 92.424 ;
     RECT  51.401 2.496 51.941 60.12 ;
     RECT  51.941 25.248 52.121 60.12 ;
     RECT  51.401 61.536 52.345 92.424 ;
     RECT  52.345 61.536 52.369 90.36 ;
     RECT  51.941 2.496 52.405 24.264 ;
     RECT  52.121 59.808 52.441 60.12 ;
     RECT  52.369 61.152 52.441 90.36 ;
     RECT  52.345 91.584 52.733 92.424 ;
     RECT  52.441 59.808 52.883 90.36 ;
     RECT  52.733 91.68 53.165 92.424 ;
     RECT  52.121 25.248 53.269 58.68 ;
     RECT  52.883 59.808 53.269 89.208 ;
     RECT  52.405 2.448 53.309 24.264 ;
     RECT  53.309 2.544 53.365 24.264 ;
     RECT  53.269 25.248 53.365 89.208 ;
     RECT  53.365 2.544 53.411 89.208 ;
     RECT  53.411 23.952 53.561 89.208 ;
     RECT  52.883 90.288 53.561 90.36 ;
     RECT  53.411 2.544 53.813 22.968 ;
     RECT  53.561 23.952 53.849 52.056 ;
     RECT  53.561 53.136 53.921 89.208 ;
     RECT  53.921 64.416 54.065 89.208 ;
     RECT  53.165 91.872 54.173 92.424 ;
     RECT  54.065 64.608 54.277 89.208 ;
     RECT  54.173 92.4 54.281 92.424 ;
     RECT  53.813 2.784 54.421 22.968 ;
     RECT  53.849 23.952 54.421 28.296 ;
     RECT  53.849 29.328 54.611 52.056 ;
     RECT  53.921 53.136 54.637 63.384 ;
     RECT  54.611 29.328 54.713 45.576 ;
     RECT  54.611 47.136 54.745 52.056 ;
     RECT  54.637 53.088 54.745 63.384 ;
     RECT  54.745 47.136 54.857 63.384 ;
     RECT  54.421 2.784 54.925 28.296 ;
     RECT  54.713 29.328 54.925 39.096 ;
     RECT  54.925 2.784 54.929 39.096 ;
     RECT  54.493 91.344 55.001 91.416 ;
     RECT  54.277 64.608 55.069 89.352 ;
     RECT  53.561 90.336 55.069 90.36 ;
     RECT  54.857 59.856 55.141 63.384 ;
     RECT  55.069 64.608 55.141 90.36 ;
     RECT  54.929 2.784 55.213 24.36 ;
     RECT  55.001 91.392 55.213 91.416 ;
     RECT  54.929 25.728 55.253 39.096 ;
     RECT  55.213 2.256 55.325 24.36 ;
     RECT  55.141 59.856 55.325 90.36 ;
     RECT  55.213 91.392 55.357 91.752 ;
     RECT  55.325 61.92 55.361 90.36 ;
     RECT  54.713 40.08 55.681 45.576 ;
     RECT  55.681 40.08 55.789 46.056 ;
     RECT  55.253 25.728 56.149 39.048 ;
     RECT  56.149 25.488 56.257 39.048 ;
     RECT  55.325 59.856 56.329 60.936 ;
     RECT  55.361 61.92 56.329 89.16 ;
     RECT  55.325 2.256 56.408 24.216 ;
     RECT  56.257 25.296 56.408 39.048 ;
     RECT  55.789 40.08 56.408 46.104 ;
     RECT  54.857 47.136 56.408 58.68 ;
     RECT  56.329 59.856 56.408 89.16 ;
     RECT  55.361 90.24 56.408 90.36 ;
     RECT  55.357 91.392 56.408 92.712 ;
     RECT  56.408 2.148 56.512 92.892 ;
     RECT  56.512 2.418 56.704 92.712 ;
     RECT  56.704 91.392 56.865 92.712 ;
     RECT  56.704 2.496 56.867 58.728 ;
     RECT  56.704 59.76 56.915 90.408 ;
     RECT  56.915 59.76 56.945 63.384 ;
     RECT  56.867 2.496 56.981 28.296 ;
     RECT  56.867 29.616 57.233 58.728 ;
     RECT  56.981 2.496 57.305 28.008 ;
     RECT  57.305 2.592 57.485 28.008 ;
     RECT  56.945 59.76 57.557 63.048 ;
     RECT  57.485 23.856 57.665 28.008 ;
     RECT  57.233 29.616 57.665 51.096 ;
     RECT  57.557 59.76 57.701 61.08 ;
     RECT  57.665 30 57.737 51.096 ;
     RECT  57.233 52.176 57.769 58.728 ;
     RECT  57.701 59.76 57.769 59.832 ;
     RECT  57.737 30 57.773 46.776 ;
     RECT  56.915 64.368 57.845 90.408 ;
     RECT  57.773 30 57.881 46.68 ;
     RECT  57.845 64.56 57.884 90.408 ;
     RECT  56.865 91.392 57.884 92.184 ;
     RECT  57.884 64.56 57.953 92.184 ;
     RECT  57.953 91.056 57.971 92.184 ;
     RECT  57.665 23.856 58.169 27.768 ;
     RECT  57.737 47.856 58.237 51.096 ;
     RECT  57.769 52.176 58.237 59.832 ;
     RECT  57.881 35.28 58.457 46.68 ;
     RECT  58.457 40.944 58.529 46.68 ;
     RECT  57.485 2.592 58.561 22.776 ;
     RECT  57.953 64.56 58.601 90.072 ;
     RECT  58.129 28.8 58.633 28.824 ;
     RECT  57.881 30 58.633 34.248 ;
     RECT  58.169 26.4 58.745 27.768 ;
     RECT  57.971 91.392 58.885 92.184 ;
     RECT  58.169 23.856 58.925 25.32 ;
     RECT  58.925 23.856 58.997 25.272 ;
     RECT  57.701 60.816 59.033 61.08 ;
     RECT  58.237 47.856 59.101 59.832 ;
     RECT  57.557 62.16 59.173 63.048 ;
     RECT  58.601 64.56 59.173 65.112 ;
     RECT  58.745 27.744 59.18 27.768 ;
     RECT  58.633 28.8 59.18 34.248 ;
     RECT  59.173 62.16 59.249 65.112 ;
     RECT  58.561 2.544 59.281 22.776 ;
     RECT  58.997 23.856 59.281 25.224 ;
     RECT  58.601 66.288 59.357 90.072 ;
     RECT  59.18 27.744 59.389 34.248 ;
     RECT  58.457 35.28 59.389 39.912 ;
     RECT  59.389 27.744 59.393 39.912 ;
     RECT  59.249 63.456 59.429 65.112 ;
     RECT  59.281 2.544 59.533 25.224 ;
     RECT  59.429 63.456 59.573 63.912 ;
     RECT  58.745 26.4 59.681 26.424 ;
     RECT  58.529 40.944 59.681 46.584 ;
     RECT  59.681 40.944 59.785 46.2 ;
     RECT  59.249 62.16 59.825 62.28 ;
     RECT  59.357 66.384 59.845 90.072 ;
     RECT  58.885 91.392 59.845 92.808 ;
     RECT  59.533 2.4 59.857 25.224 ;
     RECT  59.101 47.856 59.932 59.976 ;
     RECT  59.845 66.384 59.969 92.808 ;
     RECT  59.969 66.384 60.013 92.376 ;
     RECT  59.393 27.744 60.109 39.048 ;
     RECT  59.033 61.056 60.253 61.08 ;
     RECT  59.857 2.304 60.325 25.224 ;
     RECT  59.825 62.16 60.329 62.184 ;
     RECT  59.932 53.568 60.373 59.976 ;
     RECT  60.253 61.008 60.373 61.08 ;
     RECT  59.429 64.896 60.397 65.112 ;
     RECT  60.013 66.384 60.397 92.184 ;
     RECT  60.325 2.304 60.437 25.512 ;
     RECT  60.109 27.168 60.473 39.048 ;
     RECT  60.373 53.568 60.473 61.08 ;
     RECT  60.473 28.32 60.508 39.048 ;
     RECT  59.785 40.704 60.685 46.2 ;
     RECT  60.437 25.488 60.725 25.512 ;
     RECT  60.473 60.528 60.757 61.08 ;
     RECT  60.685 40.56 60.793 46.2 ;
     RECT  59.573 63.456 60.793 63.816 ;
     RECT  59.932 47.856 60.901 52.344 ;
     RECT  60.473 53.568 60.901 59.544 ;
     RECT  60.793 63.072 60.937 63.816 ;
     RECT  60.793 40.56 61.045 46.728 ;
     RECT  60.473 27.168 61.477 27.336 ;
     RECT  60.437 2.304 61.525 24.36 ;
     RECT  60.508 28.752 61.573 39.048 ;
     RECT  61.045 40.128 61.573 46.728 ;
     RECT  60.937 63.072 61.58 63.864 ;
     RECT  60.397 64.896 61.58 92.184 ;
     RECT  61.58 63.072 61.621 92.184 ;
     RECT  60.901 47.856 61.729 59.544 ;
     RECT  61.573 28.752 61.765 46.728 ;
     RECT  61.729 47.712 61.765 59.544 ;
     RECT  61.525 2.304 61.808 25.224 ;
     RECT  61.477 26.544 61.808 27.336 ;
     RECT  61.765 28.752 61.808 59.544 ;
     RECT  60.757 60.528 61.808 61.128 ;
     RECT  61.621 63.072 61.808 92.28 ;
     RECT  61.808 2.148 61.912 92.892 ;
     RECT  61.912 2.418 62.104 92.622 ;
     RECT  62.104 52.752 62.129 60.408 ;
     RECT  62.104 67.056 62.201 75.96 ;
     RECT  62.104 25.632 62.273 51.768 ;
     RECT  62.129 52.752 62.273 57.432 ;
     RECT  62.201 67.248 62.309 75.96 ;
     RECT  62.273 25.632 62.417 51.672 ;
     RECT  62.104 77.28 62.489 92.376 ;
     RECT  62.129 58.416 62.525 60.408 ;
     RECT  62.489 88.944 62.675 92.376 ;
     RECT  62.104 64.992 62.741 65.736 ;
     RECT  62.489 77.28 62.741 87.816 ;
     RECT  62.104 3.312 62.777 21.24 ;
     RECT  62.273 52.944 62.813 57.432 ;
     RECT  62.741 87.648 62.813 87.816 ;
     RECT  62.777 5.04 62.957 21.24 ;
     RECT  62.957 21.072 62.993 21.24 ;
     RECT  62.417 25.632 62.993 51.432 ;
     RECT  62.104 62.208 63.029 63.96 ;
     RECT  62.104 22.464 63.065 23.688 ;
     RECT  62.993 30.72 63.065 51.432 ;
     RECT  62.741 64.992 63.068 65.544 ;
     RECT  62.993 25.632 63.137 29.736 ;
     RECT  62.525 59.808 63.137 60.408 ;
     RECT  63.068 64.752 63.155 65.544 ;
     RECT  63.137 60.384 63.157 60.408 ;
     RECT  62.777 3.312 63.205 4.008 ;
     RECT  63.205 2.832 63.209 4.008 ;
     RECT  62.957 5.04 63.209 20.04 ;
     RECT  62.309 71.088 63.241 75.96 ;
     RECT  62.741 77.28 63.241 86.616 ;
     RECT  63.157 60.384 63.244 61.032 ;
     RECT  63.029 62.208 63.245 63.096 ;
     RECT  62.813 52.944 63.251 56.088 ;
     RECT  63.065 45.936 63.281 51.432 ;
     RECT  63.209 2.832 63.289 3.624 ;
     RECT  63.289 3.6 63.317 3.624 ;
     RECT  62.675 88.944 63.317 91.992 ;
     RECT  63.137 25.632 63.353 29.592 ;
     RECT  63.065 30.72 63.353 44.952 ;
     RECT  63.251 54.336 63.389 56.088 ;
     RECT  62.309 67.248 63.389 70.008 ;
     RECT  63.353 30.72 63.425 38.712 ;
     RECT  63.251 52.944 63.425 53.16 ;
     RECT  63.244 60.384 63.425 60.408 ;
     RECT  63.209 5.52 63.461 20.04 ;
     RECT  63.353 40.56 63.461 44.952 ;
     RECT  63.281 47.856 63.461 48.264 ;
     RECT  63.389 68.592 63.493 70.008 ;
     RECT  63.241 71.088 63.493 86.616 ;
     RECT  63.389 54.336 63.497 54.888 ;
     RECT  62.813 57.408 63.497 57.432 ;
     RECT  63.065 22.752 63.533 23.688 ;
     RECT  63.425 36.288 63.533 38.712 ;
     RECT  63.425 30.72 63.569 34.92 ;
     RECT  63.461 41.424 63.569 44.952 ;
     RECT  63.569 31.44 63.605 34.92 ;
     RECT  63.245 62.208 63.605 62.232 ;
     RECT  63.497 54.576 63.641 54.888 ;
     RECT  63.389 56.064 63.641 56.088 ;
     RECT  63.353 26.688 63.677 29.592 ;
     RECT  63.353 25.632 63.781 25.704 ;
     RECT  63.605 31.584 63.785 34.92 ;
     RECT  63.533 23.328 63.821 23.688 ;
     RECT  63.461 20.016 63.827 20.04 ;
     RECT  63.317 88.944 63.853 90.072 ;
     RECT  62.813 87.792 63.857 87.816 ;
     RECT  63.853 88.896 63.857 90.072 ;
     RECT  62.993 21.072 63.893 21.192 ;
     RECT  63.677 28.464 63.893 29.592 ;
     RECT  63.281 49.488 63.961 51.432 ;
     RECT  63.493 68.592 63.965 86.616 ;
     RECT  63.677 26.688 64.001 27.24 ;
     RECT  63.569 41.424 64.001 43.848 ;
     RECT  63.425 53.136 64.001 53.16 ;
     RECT  63.965 68.592 64.001 68.904 ;
     RECT  63.785 31.68 64.037 34.92 ;
     RECT  63.155 65.52 64.069 65.544 ;
     RECT  63.533 37.008 64.073 38.712 ;
     RECT  63.461 48.144 64.109 48.264 ;
     RECT  63.961 49.488 64.109 51.96 ;
     RECT  63.641 54.864 64.109 54.888 ;
     RECT  64.069 65.52 64.115 66.12 ;
     RECT  63.389 67.248 64.137 67.32 ;
     RECT  64.001 68.88 64.145 68.904 ;
     RECT  64.115 66.096 64.156 66.12 ;
     RECT  64.073 37.008 64.181 38.664 ;
     RECT  64.037 32.208 64.217 34.008 ;
     RECT  64.217 32.208 64.253 33.096 ;
     RECT  63.857 88.896 64.253 88.92 ;
     RECT  64.253 33.072 64.289 33.096 ;
     RECT  63.317 91.2 64.289 91.992 ;
     RECT  63.461 5.52 64.321 19.032 ;
     RECT  63.781 25.056 64.321 25.704 ;
     RECT  62.525 58.416 64.321 58.44 ;
     RECT  63.965 70.512 64.325 86.616 ;
     RECT  64.109 49.488 64.357 51.432 ;
     RECT  63.893 21.072 64.361 21.096 ;
     RECT  64.289 91.728 64.433 91.992 ;
     RECT  64.357 48.912 64.469 51.432 ;
     RECT  63.893 28.464 64.505 29.448 ;
     RECT  63.569 44.928 64.505 44.952 ;
     RECT  64.001 41.424 64.541 41.448 ;
     RECT  63.857 90.048 64.649 90.072 ;
     RECT  63.281 45.936 64.721 45.96 ;
     RECT  63.821 23.52 64.753 23.688 ;
     RECT  64.001 42.576 64.757 43.848 ;
     RECT  64.753 23.52 64.789 23.928 ;
     RECT  64.321 25.008 64.789 25.704 ;
     RECT  64.321 4.656 64.793 19.032 ;
     RECT  64.505 28.464 64.793 28.488 ;
     RECT  64.681 55.632 64.933 56.424 ;
     RECT  64.321 57.456 64.933 58.44 ;
     RECT  64.469 51.12 64.973 51.432 ;
     RECT  64.325 70.512 65.005 86.184 ;
     RECT  64.717 36.576 65.077 36.6 ;
     RECT  64.973 51.408 65.081 51.432 ;
     RECT  64.137 67.296 65.081 67.32 ;
     RECT  64.433 91.728 65.081 91.752 ;
     RECT  64.789 23.52 65.153 25.704 ;
     RECT  64.793 5.088 65.185 19.032 ;
     RECT  65.153 23.52 65.189 24.168 ;
     RECT  64.757 42.576 65.225 43.272 ;
     RECT  64.933 55.632 65.261 58.44 ;
     RECT  64.001 26.688 65.333 26.712 ;
     RECT  64.357 22.32 65.477 22.344 ;
     RECT  64.181 37.92 65.549 38.664 ;
     RECT  65.261 56.4 65.585 58.44 ;
     RECT  65.225 42.576 65.621 42.6 ;
     RECT  64.469 48.912 65.621 49.608 ;
     RECT  65.585 57.456 65.621 58.44 ;
     RECT  65.189 23.712 65.693 24.168 ;
     RECT  65.005 69.456 65.797 86.184 ;
     RECT  64.933 3.648 65.833 3.672 ;
     RECT  65.077 36.24 65.837 36.6 ;
     RECT  65.693 23.712 65.873 23.736 ;
     RECT  65.153 25.68 65.873 25.704 ;
     RECT  65.549 38.64 65.873 38.664 ;
     RECT  65.185 5.088 65.905 19.08 ;
     RECT  65.797 69.456 65.908 86.664 ;
     RECT  65.905 21.12 65.989 21.144 ;
     RECT  65.908 69.456 66.089 86.712 ;
     RECT  65.977 66.816 66.121 66.84 ;
     RECT  66.044 65.52 66.131 65.544 ;
     RECT  65.833 3.168 66.179 3.672 ;
     RECT  66.121 66.72 66.229 66.84 ;
     RECT  66.179 3.264 66.373 3.672 ;
     RECT  65.905 4.752 66.373 19.08 ;
     RECT  65.293 68.016 66.373 68.04 ;
     RECT  66.089 69.456 66.373 86.184 ;
     RECT  66.229 66.624 66.377 66.84 ;
     RECT  65.621 48.912 66.445 49.128 ;
     RECT  66.437 22.8 66.521 22.824 ;
     RECT  66.445 88.368 66.529 88.392 ;
     RECT  65.621 58.416 66.589 58.44 ;
     RECT  66.373 3.264 66.665 19.08 ;
     RECT  66.445 48.336 66.697 49.128 ;
     RECT  66.697 55.152 66.733 55.176 ;
     RECT  66.409 40.032 66.737 40.056 ;
     RECT  66.373 30.384 66.769 30.408 ;
     RECT  65.837 36.24 66.805 36.36 ;
     RECT  66.661 41.424 66.805 41.448 ;
     RECT  66.377 66.72 66.809 66.84 ;
     RECT  66.481 64.944 66.851 64.968 ;
     RECT  66.805 41.424 66.881 43.08 ;
     RECT  66.373 68.016 66.889 86.184 ;
     RECT  66.809 66.72 66.917 66.744 ;
     RECT  66.769 30 67.129 30.408 ;
     RECT  67.129 29.904 67.165 30.408 ;
     RECT  67.165 29.424 67.201 30.408 ;
     RECT  67.201 29.232 67.237 30.408 ;
     RECT  67.237 29.136 67.273 30.408 ;
     RECT  66.805 35.76 67.273 36.36 ;
     RECT  66.733 54.864 67.273 55.176 ;
     RECT  65.585 56.4 67.273 56.424 ;
     RECT  66.889 68.016 67.525 70.536 ;
     RECT  66.881 42.192 67.633 43.08 ;
     RECT  66.589 58.416 67.633 58.536 ;
     RECT  66.697 48.336 67.669 50.088 ;
     RECT  67.633 51.216 67.669 51.24 ;
     RECT  67.273 54.48 67.669 56.424 ;
     RECT  67.633 57.456 67.669 58.536 ;
     RECT  67.669 32.112 67.705 32.136 ;
     RECT  66.013 37.392 67.705 37.416 ;
     RECT  66.889 71.568 67.705 86.184 ;
     RECT  67.705 31.824 67.741 32.136 ;
     RECT  67.705 45.072 67.741 45.096 ;
     RECT  67.741 31.728 67.777 32.136 ;
     RECT  67.633 42.192 67.777 43.176 ;
     RECT  67.741 44.592 67.777 45.096 ;
     RECT  67.705 71.568 67.777 86.376 ;
     RECT  66.665 3.984 67.813 19.08 ;
     RECT  67.273 29.136 67.813 30.504 ;
     RECT  67.777 31.632 67.813 32.136 ;
     RECT  67.273 35.472 67.813 36.36 ;
     RECT  67.525 67.824 67.813 70.536 ;
     RECT  67.813 35.28 67.885 36.36 ;
     RECT  67.705 37.392 67.885 38.088 ;
     RECT  67.813 67.536 68.173 70.536 ;
     RECT  67.777 71.568 68.173 86.664 ;
     RECT  67.777 42.192 68.353 45.096 ;
     RECT  67.885 35.28 68.677 38.088 ;
     RECT  67.669 48.336 68.857 51.24 ;
     RECT  67.813 3.792 69.084 19.08 ;
     RECT  67.813 29.136 69.084 32.136 ;
     RECT  68.677 35.28 69.084 38.28 ;
     RECT  68.353 42.192 69.084 45.192 ;
     RECT  68.857 48.336 69.084 51.336 ;
     RECT  67.669 54.48 69.084 58.536 ;
     RECT  68.173 67.536 69.084 86.664 ;
    LAYER M5 ;
     RECT  2.4 2.137 2.52 2.151 ;
     RECT  7.8 2.137 7.92 2.151 ;
     RECT  13.2 2.137 13.32 2.151 ;
     RECT  18.6 2.137 18.72 2.151 ;
     RECT  24 2.137 24.12 2.151 ;
     RECT  29.4 2.137 29.52 2.151 ;
     RECT  34.8 2.137 34.92 2.151 ;
     RECT  40.2 2.137 40.32 2.151 ;
     RECT  45.6 2.137 45.72 2.151 ;
     RECT  51 2.137 51.12 2.151 ;
     RECT  56.4 2.137 56.52 2.151 ;
     RECT  61.8 2.137 61.92 2.151 ;
     RECT  18.6 2.151 18.912 2.245 ;
     RECT  51 2.151 51.312 2.245 ;
     RECT  56.4 2.151 56.712 2.245 ;
     RECT  61.8 2.151 62.112 2.293 ;
     RECT  7.8 2.151 8.112 2.485 ;
     RECT  17.616 2.245 18.912 2.485 ;
     RECT  14.832 2.725 14.856 2.867 ;
     RECT  10.944 2.245 10.968 2.915 ;
     RECT  21.936 2.293 21.96 3.299 ;
     RECT  61.152 2.293 62.112 3.301 ;
     RECT  63.216 2.821 63.24 3.301 ;
     RECT  50.592 2.245 51.312 3.347 ;
     RECT  61.152 3.301 63.24 3.347 ;
     RECT  45.6 2.151 45.912 3.397 ;
     RECT  38.064 2.629 38.088 3.443 ;
     RECT  28.368 2.485 28.392 3.587 ;
     RECT  34.8 2.151 35.112 3.589 ;
     RECT  56.304 2.245 56.712 3.589 ;
     RECT  7.8 2.485 8.232 3.685 ;
     RECT  32.112 2.485 32.136 3.875 ;
     RECT  2.4 2.151 2.712 3.925 ;
     RECT  20.16 3.349 20.184 3.925 ;
     RECT  21.648 3.685 21.768 3.925 ;
     RECT  24 2.151 24.312 3.925 ;
     RECT  51 3.347 51.312 3.925 ;
     RECT  6.816 3.685 8.232 3.971 ;
     RECT  61.152 3.347 63.048 3.973 ;
     RECT  61.008 3.973 63.048 4.019 ;
     RECT  2.4 3.925 2.808 4.115 ;
     RECT  44.976 3.397 45.912 4.115 ;
     RECT  13.2 2.151 13.512 4.165 ;
     RECT  26.16 2.245 26.184 4.165 ;
     RECT  26.16 4.165 26.28 4.307 ;
     RECT  49.536 2.677 49.56 4.355 ;
     RECT  20.16 3.925 21.768 4.357 ;
     RECT  23.088 3.925 24.312 4.357 ;
     RECT  17.616 2.485 19.032 4.403 ;
     RECT  18.48 4.403 19.032 4.453 ;
     RECT  20.16 4.357 24.312 4.453 ;
     RECT  27.312 4.405 27.336 4.453 ;
     RECT  5.808 4.453 5.832 4.597 ;
     RECT  6.816 3.971 8.112 4.597 ;
     RECT  5.808 4.597 8.112 4.643 ;
     RECT  33.072 3.925 33.432 4.691 ;
     RECT  18.48 4.453 24.312 4.979 ;
     RECT  4.56 2.869 4.584 4.981 ;
     RECT  13.2 4.165 13.608 4.981 ;
     RECT  3.936 4.981 4.584 5.027 ;
     RECT  12.96 4.981 13.608 5.029 ;
     RECT  14.736 4.837 14.76 5.029 ;
     RECT  16.32 3.397 16.344 5.029 ;
     RECT  38.64 3.925 38.664 5.029 ;
     RECT  16.32 5.029 17.064 5.075 ;
     RECT  5.808 4.643 6.504 5.077 ;
     RECT  51 3.925 51.96 5.125 ;
     RECT  34.8 3.589 35.352 5.171 ;
     RECT  5.04 5.077 6.504 5.459 ;
     RECT  47.088 2.629 47.112 5.459 ;
     RECT  58.176 4.069 58.2 5.605 ;
     RECT  12.96 5.029 14.76 5.747 ;
     RECT  27.312 4.453 27.864 5.747 ;
     RECT  33.072 4.691 33.192 5.747 ;
     RECT  41.712 3.397 41.736 5.747 ;
     RECT  33.168 5.747 33.192 5.795 ;
     RECT  27.84 5.747 27.864 5.843 ;
     RECT  26.16 4.307 26.184 5.987 ;
     RECT  40.2 2.151 40.512 5.989 ;
     RECT  19.968 4.979 24.312 6.085 ;
     RECT  36.864 4.501 36.888 6.131 ;
     RECT  19.92 6.085 24.312 6.133 ;
     RECT  29.4 2.151 29.712 6.133 ;
     RECT  28.608 6.133 29.712 6.229 ;
     RECT  56.256 3.589 56.712 6.229 ;
     RECT  58.176 5.605 58.536 6.229 ;
     RECT  59.568 5.653 59.592 6.229 ;
     RECT  31.056 5.077 31.944 6.323 ;
     RECT  58.176 6.229 59.592 6.323 ;
     RECT  38.448 5.029 38.664 6.419 ;
     RECT  19.92 6.133 24.504 6.467 ;
     RECT  5.04 5.459 5.832 6.757 ;
     RECT  12.96 5.747 14.232 6.901 ;
     RECT  28.608 6.229 30.072 7.043 ;
     RECT  21.648 6.467 24.504 7.189 ;
     RECT  51 5.125 52.056 7.189 ;
     RECT  10.512 4.501 10.536 7.381 ;
     RECT  28.608 7.043 29.712 7.381 ;
     RECT  47.664 5.797 47.688 7.427 ;
     RECT  49.008 7.285 49.032 7.427 ;
     RECT  51 7.189 53.016 7.427 ;
     RECT  56.16 6.229 56.712 7.427 ;
     RECT  10.416 7.381 10.728 7.429 ;
     RECT  19.92 6.467 19.944 7.429 ;
     RECT  21.648 7.189 25.368 7.429 ;
     RECT  36.48 7.381 36.504 7.429 ;
     RECT  58.656 6.323 59.592 7.523 ;
     RECT  9.744 7.429 10.728 7.571 ;
     RECT  19.92 7.429 25.368 7.619 ;
     RECT  19.92 7.619 21.768 7.667 ;
     RECT  36.48 7.429 36.84 7.715 ;
     RECT  5.04 6.757 6.024 7.765 ;
     RECT  43.296 6.613 43.32 7.765 ;
     RECT  12.096 6.901 14.232 7.811 ;
     RECT  28.512 7.381 29.712 7.861 ;
     RECT  40.2 5.989 41.112 7.861 ;
     RECT  22.8 7.619 25.368 7.907 ;
     RECT  7.8 4.643 8.112 7.909 ;
     RECT  31.056 6.323 31.08 7.909 ;
     RECT  51 7.427 52.776 7.909 ;
     RECT  50.592 7.909 52.776 7.955 ;
     RECT  5.04 7.765 6.312 7.957 ;
     RECT  36.48 7.715 36.504 8.003 ;
     RECT  52.752 7.955 52.776 8.003 ;
     RECT  66.144 3.157 66.168 8.003 ;
     RECT  18.48 4.979 18.912 8.341 ;
     RECT  19.92 7.667 19.944 8.341 ;
     RECT  18.48 8.341 19.944 8.435 ;
     RECT  54.864 7.429 54.888 8.437 ;
     RECT  18.48 8.435 19.56 8.483 ;
     RECT  34.8 5.171 35.256 8.485 ;
     RECT  59.568 7.523 59.592 8.485 ;
     RECT  42.864 7.765 43.32 8.531 ;
     RECT  4.944 7.957 6.312 8.579 ;
     RECT  10.416 7.571 10.728 8.675 ;
     RECT  10.416 8.675 10.44 8.677 ;
     RECT  12.816 7.811 14.232 8.723 ;
     RECT  21.648 7.667 21.768 8.771 ;
     RECT  27.936 7.861 29.712 8.771 ;
     RECT  7.8 7.909 8.52 8.773 ;
     RECT  23.616 7.907 25.368 8.773 ;
     RECT  17.04 5.075 17.064 8.821 ;
     RECT  42.864 8.531 43.032 8.867 ;
     RECT  30.96 7.909 31.08 8.869 ;
     RECT  59.568 8.485 59.688 8.917 ;
     RECT  61.008 4.019 62.112 8.917 ;
     RECT  23.616 8.773 26.232 8.963 ;
     RECT  2.4 4.115 2.712 8.965 ;
     RECT  48.72 7.957 48.744 8.965 ;
     RECT  30.96 8.869 31.8 9.011 ;
     RECT  6.864 8.773 8.52 9.107 ;
     RECT  48.72 8.965 49.512 9.251 ;
     RECT  38.64 6.419 38.664 9.301 ;
     RECT  2.4 8.965 2.904 9.347 ;
     RECT  29.136 8.771 29.712 9.349 ;
     RECT  30.96 9.011 31.08 9.349 ;
     RECT  38.592 9.301 38.664 9.443 ;
     RECT  7.8 9.107 8.52 9.493 ;
     RECT  56.304 7.427 56.712 9.493 ;
     RECT  52.944 9.493 52.968 9.589 ;
     RECT  7.8 9.493 8.616 9.635 ;
     RECT  52.464 9.589 52.968 9.635 ;
     RECT  27.936 8.771 27.96 9.637 ;
     RECT  45.6 4.115 45.912 9.637 ;
     RECT  18.6 8.483 19.56 9.683 ;
     RECT  27.552 9.637 27.96 9.683 ;
     RECT  34.8 8.485 35.496 9.683 ;
     RECT  56.304 9.493 57 9.683 ;
     RECT  13.2 8.723 14.232 9.685 ;
     RECT  50.592 7.955 51.312 9.731 ;
     RECT  16.944 8.821 17.064 9.781 ;
     RECT  13.008 9.685 14.232 9.827 ;
     RECT  16.224 9.781 17.064 9.923 ;
     RECT  3.936 5.027 3.96 9.925 ;
     RECT  4.944 8.579 5.832 9.925 ;
     RECT  29.136 9.349 31.08 10.067 ;
     RECT  38.64 9.443 38.664 10.067 ;
     RECT  52.464 9.635 52.488 10.163 ;
     RECT  23.616 8.963 24.312 10.165 ;
     RECT  17.04 9.923 17.064 10.213 ;
     RECT  18.6 9.683 19.416 10.213 ;
     RECT  10.08 8.677 10.44 10.261 ;
     RECT  40.2 7.861 41.544 10.307 ;
     RECT  2.4 9.347 2.712 10.309 ;
     RECT  9.12 10.261 10.44 10.309 ;
     RECT  9.12 10.309 11.4 10.355 ;
     RECT  45.6 9.637 46.2 10.355 ;
     RECT  56.4 9.683 57 10.451 ;
     RECT  29.136 10.067 29.712 10.693 ;
     RECT  2.4 10.309 2.856 10.739 ;
     RECT  59.568 8.917 62.112 10.787 ;
     RECT  9.12 10.355 9.144 10.835 ;
     RECT  25.488 8.963 26.232 10.883 ;
     RECT  33.024 9.061 33.048 10.883 ;
     RECT  49.488 9.251 49.512 10.883 ;
     RECT  59.568 10.787 60.408 10.883 ;
     RECT  10.272 10.355 11.4 10.931 ;
     RECT  13.2 9.827 14.232 10.933 ;
     RECT  51 9.731 51.312 10.981 ;
     RECT  59.664 10.883 60.408 11.123 ;
     RECT  34.8 9.683 35.112 11.125 ;
     RECT  49.008 10.981 49.032 11.171 ;
     RECT  51 10.981 51.672 11.267 ;
     RECT  7.8 9.635 8.112 11.365 ;
     RECT  25.728 10.883 26.232 11.557 ;
     RECT  13.104 10.933 14.232 11.605 ;
     RECT  17.04 10.213 19.416 11.653 ;
     RECT  29.088 10.693 29.712 11.699 ;
     RECT  43.008 8.867 43.032 11.701 ;
     RECT  40.2 10.307 40.512 11.749 ;
     RECT  45.6 10.355 46.008 11.749 ;
     RECT  7.344 11.365 8.112 11.845 ;
     RECT  40.08 11.749 40.512 11.891 ;
     RECT  2.4 10.739 2.808 11.939 ;
     RECT  42.768 11.701 43.032 11.939 ;
     RECT  54.432 8.437 54.888 11.941 ;
     RECT  56.4 10.451 56.712 11.941 ;
     RECT  10.272 10.931 10.296 11.989 ;
     RECT  11.376 10.931 11.4 11.989 ;
     RECT  3.936 9.925 5.832 12.035 ;
     RECT  27.552 9.683 27.576 12.035 ;
     RECT  29.136 11.699 29.712 12.035 ;
     RECT  10.272 11.989 11.4 12.037 ;
     RECT  13.104 11.605 14.28 12.037 ;
     RECT  17.04 11.653 19.656 12.037 ;
     RECT  34.8 11.125 35.208 12.083 ;
     RECT  37.728 11.605 37.752 12.227 ;
     RECT  40.2 11.891 40.512 12.277 ;
     RECT  41.52 10.307 41.544 12.277 ;
     RECT  7.344 11.845 8.232 12.371 ;
     RECT  15.6 12.229 15.624 12.371 ;
     RECT  0.528 11.701 0.552 12.467 ;
     RECT  29.4 12.035 29.712 12.469 ;
     RECT  31.056 10.067 31.08 12.469 ;
     RECT  3.936 12.035 5.016 12.515 ;
     RECT  45.6 11.749 46.728 12.517 ;
     RECT  53.184 11.173 53.208 12.517 ;
     RECT  10.272 12.037 14.28 12.563 ;
     RECT  29.4 12.469 31.08 12.563 ;
     RECT  58.08 10.693 58.104 12.563 ;
     RECT  21.744 8.771 21.768 12.613 ;
     RECT  23.568 10.165 24.312 12.613 ;
     RECT  25.728 11.557 26.568 12.613 ;
     RECT  21.216 12.613 21.768 12.853 ;
     RECT  60.384 11.123 60.408 12.949 ;
     RECT  10.656 12.563 14.28 12.995 ;
     RECT  54.192 11.941 54.888 12.995 ;
     RECT  60.24 12.949 60.408 12.995 ;
     RECT  51 11.267 51.312 12.997 ;
     RECT  7.392 12.371 8.112 13.043 ;
     RECT  21.12 12.853 21.768 13.043 ;
     RECT  17.04 12.037 19.704 13.045 ;
     RECT  43.008 11.939 43.032 13.045 ;
     RECT  10.656 12.995 11.4 13.139 ;
     RECT  17.04 13.045 20.472 13.139 ;
     RECT  23.568 12.613 26.568 13.139 ;
     RECT  50.88 12.997 51.312 13.139 ;
     RECT  55.968 11.941 56.712 13.139 ;
     RECT  13.104 12.995 14.28 13.331 ;
     RECT  9.168 12.373 9.192 13.573 ;
     RECT  2.4 11.939 2.712 13.621 ;
     RECT  4.176 12.515 5.016 13.621 ;
     RECT  25.728 13.139 26.568 13.621 ;
     RECT  29.4 12.563 30.696 13.621 ;
     RECT  34.8 12.083 35.112 13.621 ;
     RECT  36.432 12.901 36.456 13.621 ;
     RECT  43.008 13.045 43.32 13.621 ;
     RECT  49.2 11.941 49.224 13.715 ;
     RECT  9.168 13.573 9.288 13.811 ;
     RECT  0.144 12.997 0.168 13.861 ;
     RECT  40.2 12.277 41.544 13.907 ;
     RECT  27.984 13.045 28.008 13.909 ;
     RECT  29.04 13.621 31.224 13.909 ;
     RECT  45.6 12.517 47.304 14.005 ;
     RECT  48.48 13.765 48.504 14.005 ;
     RECT  0.144 13.861 0.264 14.195 ;
     RECT  13.104 13.331 13.512 14.243 ;
     RECT  34.8 13.621 36.456 14.243 ;
     RECT  27.984 13.909 31.224 14.291 ;
     RECT  9.168 13.811 9.192 14.387 ;
     RECT  10.752 13.139 11.4 14.389 ;
     RECT  17.04 13.139 17.064 14.485 ;
     RECT  10.752 14.389 11.544 14.531 ;
     RECT  10.752 14.531 11.4 14.579 ;
     RECT  45.6 14.005 48.504 14.579 ;
     RECT  0.24 14.195 0.264 14.627 ;
     RECT  21.744 13.043 21.768 14.629 ;
     RECT  23.568 13.139 24.504 14.629 ;
     RECT  53.04 12.517 53.208 14.629 ;
     RECT  54.432 12.995 54.888 14.629 ;
     RECT  10.752 14.579 11.208 14.675 ;
     RECT  40.2 13.907 41.352 14.677 ;
     RECT  60.24 12.995 60.264 14.677 ;
     RECT  59.856 14.677 60.264 14.723 ;
     RECT  13.2 14.243 13.512 14.725 ;
     RECT  23.568 14.629 24.6 14.771 ;
     RECT  34.8 14.243 36.12 14.771 ;
     RECT  51 13.139 51.312 14.773 ;
     RECT  61.8 10.787 62.112 14.773 ;
     RECT  18.48 13.139 20.472 14.819 ;
     RECT  53.04 14.629 54.888 14.867 ;
     RECT  27.984 14.291 30.696 14.915 ;
     RECT  48.48 14.579 48.504 14.915 ;
     RECT  58.128 14.773 58.152 14.917 ;
     RECT  2.4 13.621 2.808 14.963 ;
     RECT  21.744 14.629 22.536 15.109 ;
     RECT  25.728 13.621 26.616 15.109 ;
     RECT  43.008 13.621 43.896 15.155 ;
     RECT  61.536 14.773 62.112 15.251 ;
     RECT  25.728 15.109 26.808 15.301 ;
     RECT  43.008 15.155 43.032 15.347 ;
     RECT  25.488 15.301 26.808 15.349 ;
     RECT  39.36 14.677 41.352 15.349 ;
     RECT  48.528 15.301 48.552 15.349 ;
     RECT  56.4 13.139 56.712 15.349 ;
     RECT  59.856 14.723 59.88 15.443 ;
     RECT  21.6 15.109 22.536 15.491 ;
     RECT  13.2 14.725 13.608 15.587 ;
     RECT  50.88 14.773 51.312 15.589 ;
     RECT  53.04 14.867 54.456 15.589 ;
     RECT  17.04 14.485 17.208 15.683 ;
     RECT  10.752 14.675 11.112 15.781 ;
     RECT  18.48 14.819 19.656 15.829 ;
     RECT  0.336 15.589 0.36 15.877 ;
     RECT  10.752 15.781 11.496 15.923 ;
     RECT  23.568 14.771 24.504 15.973 ;
     RECT  25.488 15.349 27.288 15.973 ;
     RECT  0.24 15.877 0.36 16.019 ;
     RECT  18.48 15.829 19.8 16.019 ;
     RECT  50.88 15.589 54.456 16.019 ;
     RECT  58.128 14.917 58.536 16.019 ;
     RECT  34.8 14.771 36.072 16.021 ;
     RECT  0.24 16.019 0.264 16.067 ;
     RECT  23.568 15.973 27.288 16.115 ;
     RECT  10.752 15.923 11.112 16.211 ;
     RECT  23.664 16.115 27.288 16.307 ;
     RECT  55.872 15.349 56.712 16.309 ;
     RECT  34.8 16.021 36.264 16.355 ;
     RECT  54.432 16.019 54.456 16.355 ;
     RECT  39.36 15.349 42.312 16.499 ;
     RECT  14.688 13.909 14.712 16.501 ;
     RECT  21.6 15.491 21.624 16.501 ;
     RECT  24 16.307 27.288 16.501 ;
     RECT  28.704 14.915 30.696 16.501 ;
     RECT  55.872 16.309 57 16.501 ;
     RECT  55.104 16.501 57 16.547 ;
     RECT  4.176 13.621 5.064 16.595 ;
     RECT  24 16.501 30.696 16.595 ;
     RECT  58.224 16.019 58.536 16.595 ;
     RECT  0.144 16.261 0.168 16.643 ;
     RECT  9.312 15.445 9.336 16.645 ;
     RECT  13.2 15.587 13.512 16.645 ;
     RECT  9.12 16.645 9.336 16.691 ;
     RECT  7.8 13.043 8.112 16.693 ;
     RECT  9.12 16.691 9.144 16.693 ;
     RECT  7.8 16.693 9.144 16.787 ;
     RECT  13.056 16.645 13.512 16.787 ;
     RECT  50.88 16.019 53.064 16.835 ;
     RECT  55.104 16.547 56.808 16.835 ;
     RECT  7.8 16.787 8.616 16.885 ;
     RECT  7.632 16.885 8.616 16.931 ;
     RECT  24 16.595 30.552 16.931 ;
     RECT  21.12 16.501 21.624 16.981 ;
     RECT  61.8 15.251 62.112 16.981 ;
     RECT  24 16.931 28.008 17.027 ;
     RECT  4.848 16.595 5.064 17.075 ;
     RECT  39.888 16.499 42.312 17.075 ;
     RECT  48.528 15.349 49.272 17.075 ;
     RECT  60.912 16.981 62.112 17.123 ;
     RECT  48.528 17.075 49.032 17.219 ;
     RECT  61.008 17.123 62.112 17.219 ;
     RECT  48.528 17.219 48.552 17.363 ;
     RECT  66.48 17.317 66.504 17.413 ;
     RECT  10.896 16.211 11.112 17.509 ;
     RECT  24 17.027 26.952 17.555 ;
     RECT  4.848 17.075 4.872 17.605 ;
     RECT  18.6 16.019 19.8 17.605 ;
     RECT  21.072 16.981 21.624 17.605 ;
     RECT  38.16 16.981 38.184 17.605 ;
     RECT  28.992 16.931 30.552 17.651 ;
     RECT  32.112 16.021 32.136 17.651 ;
     RECT  33.648 15.925 33.672 17.651 ;
     RECT  54.096 17.029 54.12 17.699 ;
     RECT  34.8 16.355 36.072 18.037 ;
     RECT  58.224 16.595 58.296 18.083 ;
     RECT  58.224 18.083 58.248 18.179 ;
     RECT  39.888 17.075 41.352 18.181 ;
     RECT  50.88 16.835 52.2 18.275 ;
     RECT  51 18.275 52.2 18.467 ;
     RECT  13.2 16.787 13.512 18.469 ;
     RECT  17.04 15.683 17.064 18.565 ;
     RECT  24 17.555 25.944 18.565 ;
     RECT  26.928 17.555 26.952 18.565 ;
     RECT  59.232 18.133 59.256 18.565 ;
     RECT  0.144 18.469 0.168 18.613 ;
     RECT  10.8 17.509 11.112 18.661 ;
     RECT  27.984 17.027 28.008 18.707 ;
     RECT  0.144 18.613 0.216 18.709 ;
     RECT  24 18.565 26.952 18.757 ;
     RECT  55.104 16.835 55.128 18.757 ;
     RECT  61.056 17.219 62.112 18.757 ;
     RECT  18.6 17.605 21.624 18.851 ;
     RECT  56.4 16.835 56.808 18.853 ;
     RECT  10.272 18.661 11.112 18.949 ;
     RECT  12.192 16.933 12.216 18.949 ;
     RECT  45.6 14.579 47.112 18.995 ;
     RECT  2.4 14.963 2.712 19.045 ;
     RECT  13.2 18.469 13.608 19.139 ;
     RECT  59.232 18.565 59.688 19.235 ;
     RECT  44.448 18.181 44.472 19.237 ;
     RECT  2.4 19.045 2.856 19.283 ;
     RECT  9.12 19.141 9.144 19.283 ;
     RECT  21.6 18.851 21.624 19.333 ;
     RECT  3.888 17.605 4.872 19.379 ;
     RECT  16.608 18.565 17.064 19.477 ;
     RECT  18.6 18.851 20.376 19.477 ;
     RECT  16.608 19.477 20.376 19.523 ;
     RECT  55.104 18.757 55.368 19.523 ;
     RECT  10.272 18.949 12.216 19.621 ;
     RECT  13.2 19.139 13.512 19.621 ;
     RECT  59.664 19.235 59.688 19.667 ;
     RECT  21.6 19.333 21.864 19.811 ;
     RECT  6.528 18.421 6.552 19.909 ;
     RECT  7.632 16.931 8.112 19.909 ;
     RECT  44.064 19.237 44.472 19.955 ;
     RECT  33.936 18.037 36.072 20.003 ;
     RECT  39.888 18.181 41.4 20.003 ;
     RECT  53.232 18.757 53.256 20.003 ;
     RECT  29.04 17.651 30.552 20.053 ;
     RECT  58.128 18.229 58.152 20.099 ;
     RECT  55.104 19.523 55.128 20.149 ;
     RECT  28.8 20.053 30.552 20.243 ;
     RECT  24 18.757 27.528 20.339 ;
     RECT  14.688 16.501 14.76 20.341 ;
     RECT  14.64 20.341 14.76 20.387 ;
     RECT  29.04 20.243 30.552 20.387 ;
     RECT  56.4 18.853 56.856 20.389 ;
     RECT  54.864 20.149 55.128 20.533 ;
     RECT  56.4 20.389 57.096 20.533 ;
     RECT  16.704 19.523 20.376 20.579 ;
     RECT  61.056 18.757 62.712 20.579 ;
     RECT  0.144 18.709 0.312 20.725 ;
     RECT  61.152 20.579 62.712 20.819 ;
     RECT  54.768 20.533 55.128 20.821 ;
     RECT  0.144 20.725 0.36 20.965 ;
     RECT  4.416 19.379 4.872 20.965 ;
     RECT  39.888 20.003 41.352 21.011 ;
     RECT  21.6 19.811 21.624 21.013 ;
     RECT  63.792 20.005 63.816 21.107 ;
     RECT  10.272 19.621 13.512 21.155 ;
     RECT  56.304 20.533 57.096 21.155 ;
     RECT  65.952 17.413 66.504 21.155 ;
     RECT  2.4 19.283 2.712 21.157 ;
     RECT  0.144 20.965 0.456 21.203 ;
     RECT  11.808 21.155 13.512 21.205 ;
     RECT  3.984 20.965 4.872 21.253 ;
     RECT  6.528 19.909 8.112 21.299 ;
     RECT  37.968 17.605 38.184 21.301 ;
     RECT  39.984 21.011 41.352 21.347 ;
     RECT  3.984 21.253 5.016 21.395 ;
     RECT  11.808 21.205 13.608 21.395 ;
     RECT  34.8 20.003 36.072 21.395 ;
     RECT  2.4 21.157 2.808 21.397 ;
     RECT  12 21.395 13.512 21.491 ;
     RECT  56.4 21.155 57.096 21.491 ;
     RECT  12 21.491 12.024 21.539 ;
     RECT  21.6 21.013 22.584 21.539 ;
     RECT  2.304 21.397 2.808 21.587 ;
     RECT  37.248 21.301 38.184 21.637 ;
     RECT  29.04 20.387 29.832 21.683 ;
     RECT  45.6 18.995 46.008 21.731 ;
     RECT  51 18.467 51.864 21.731 ;
     RECT  0.144 21.203 0.408 22.019 ;
     RECT  37.248 21.637 38.808 22.019 ;
     RECT  0.192 22.019 0.408 22.115 ;
     RECT  24 20.339 27.432 22.115 ;
     RECT  2.4 21.587 2.808 22.165 ;
     RECT  3.984 21.395 4.92 22.165 ;
     RECT  29.04 21.683 29.712 22.165 ;
     RECT  61.152 20.819 62.112 22.165 ;
     RECT  16.704 20.579 17.064 22.213 ;
     RECT  18.096 20.579 20.376 22.213 ;
     RECT  47.088 18.995 47.112 22.213 ;
     RECT  6.528 21.299 6.552 22.259 ;
     RECT  0.24 22.115 0.408 22.307 ;
     RECT  0.384 22.307 0.408 22.355 ;
     RECT  9.12 22.261 9.144 22.403 ;
     RECT  21.6 21.539 21.624 22.451 ;
     RECT  54.288 20.821 55.128 22.451 ;
     RECT  24 22.115 27.048 22.453 ;
     RECT  2.4 22.165 4.92 22.499 ;
     RECT  59.664 22.117 59.688 22.499 ;
     RECT  54.288 22.451 54.744 22.501 ;
     RECT  13.104 21.491 13.512 22.549 ;
     RECT  12.624 22.549 13.512 22.691 ;
     RECT  7.8 21.299 8.112 22.741 ;
     RECT  10.8 21.155 10.824 22.789 ;
     RECT  53.952 22.501 54.744 22.835 ;
     RECT  66.48 21.155 66.504 22.835 ;
     RECT  28.464 22.165 29.712 22.837 ;
     RECT  30.72 22.165 30.744 22.837 ;
     RECT  34.8 21.395 35.88 22.931 ;
     RECT  10.8 22.789 11.304 23.029 ;
     RECT  40.032 21.347 41.352 23.029 ;
     RECT  44.064 19.955 44.088 23.269 ;
     RECT  45.6 21.731 45.912 23.269 ;
     RECT  47.088 22.213 47.544 23.269 ;
     RECT  16.704 22.213 20.376 23.315 ;
     RECT  28.464 22.837 30.744 23.315 ;
     RECT  43.968 23.269 44.088 23.315 ;
     RECT  14.64 20.387 14.712 23.317 ;
     RECT  33.312 22.741 33.336 23.317 ;
     RECT  7.68 22.741 8.112 23.413 ;
     RECT  16.704 23.315 19.656 23.555 ;
     RECT  7.68 23.413 8.904 23.557 ;
     RECT  14.64 23.317 15.528 23.557 ;
     RECT  14.64 23.557 16.68 23.603 ;
     RECT  0.144 23.461 0.168 23.605 ;
     RECT  16.272 23.603 16.68 23.699 ;
     RECT  56.4 21.491 56.856 23.699 ;
     RECT  63.36 22.885 63.384 23.699 ;
     RECT  7.68 23.557 9.288 23.747 ;
     RECT  52.464 22.741 52.488 23.749 ;
     RECT  45.6 23.269 47.544 23.795 ;
     RECT  52.464 23.749 53.4 23.795 ;
     RECT  7.68 23.747 9.144 23.843 ;
     RECT  54.624 22.835 54.744 23.845 ;
     RECT  0.144 23.605 0.216 23.891 ;
     RECT  54.576 23.845 54.744 23.893 ;
     RECT  7.68 23.843 9.096 23.941 ;
     RECT  51 21.731 51.48 23.941 ;
     RECT  42.576 22.741 42.6 23.987 ;
     RECT  60.816 22.165 62.112 23.987 ;
     RECT  13.2 22.691 13.512 23.989 ;
     RECT  33.072 23.317 33.336 23.989 ;
     RECT  7.44 23.941 9.096 24.083 ;
     RECT  13.104 23.989 13.512 24.179 ;
     RECT  28.944 23.315 30.744 24.227 ;
     RECT  34.8 22.931 35.112 24.229 ;
     RECT  40.032 23.029 41.592 24.371 ;
     RECT  2.4 22.499 2.952 24.469 ;
     RECT  3.984 22.499 4.92 24.469 ;
     RECT  45.6 23.795 47.112 24.469 ;
     RECT  0.144 23.891 0.168 24.659 ;
     RECT  23.376 22.453 27.048 24.659 ;
     RECT  65.04 23.701 65.064 24.659 ;
     RECT  17.664 23.555 19.656 24.707 ;
     RECT  53.376 23.795 53.4 24.709 ;
     RECT  54.576 23.893 55.032 24.709 ;
     RECT  10.8 23.029 11.64 24.757 ;
     RECT  10.8 24.757 11.736 24.899 ;
     RECT  17.808 24.707 19.656 25.045 ;
     RECT  43.968 23.315 43.992 25.045 ;
     RECT  50.736 23.941 51.48 25.045 ;
     RECT  45.072 24.469 47.112 25.091 ;
     RECT  16.656 23.699 16.68 25.187 ;
     RECT  29.4 24.227 30.744 25.187 ;
     RECT  34.8 24.229 35.544 25.283 ;
     RECT  56.4 23.699 56.808 25.285 ;
     RECT  14.64 23.603 14.76 25.333 ;
     RECT  14.64 25.333 14.904 25.379 ;
     RECT  53.376 24.709 55.032 25.427 ;
     RECT  43.92 25.045 43.992 25.429 ;
     RECT  33.072 23.989 33.432 25.477 ;
     RECT  34.8 25.283 35.112 25.477 ;
     RECT  30.72 25.187 30.744 25.571 ;
     RECT  37.248 22.019 38.184 25.621 ;
     RECT  50.016 25.045 51.48 25.667 ;
     RECT  63.792 25.045 63.816 25.667 ;
     RECT  11.712 24.899 11.736 25.715 ;
     RECT  33.072 25.477 35.112 25.715 ;
     RECT  2.4 24.469 4.92 25.811 ;
     RECT  37.248 25.621 38.952 26.051 ;
     RECT  7.8 24.083 9.096 26.197 ;
     RECT  50.016 25.667 51.312 26.291 ;
     RECT  33.216 25.715 35.112 26.293 ;
     RECT  13.2 24.179 13.512 26.341 ;
     RECT  16.176 25.573 16.2 26.437 ;
     RECT  58.128 24.181 58.152 26.579 ;
     RECT  3.984 25.811 4.92 26.627 ;
     RECT  54.288 25.427 55.032 26.627 ;
     RECT  53.136 25.621 53.16 26.629 ;
     RECT  23.424 24.659 27.048 26.773 ;
     RECT  17.808 25.045 20.136 26.819 ;
     RECT  38.16 26.051 38.952 26.819 ;
     RECT  13.2 26.341 13.608 26.915 ;
     RECT  38.928 26.819 38.952 26.915 ;
     RECT  2.4 25.811 2.712 27.157 ;
     RECT  14.688 25.379 14.904 27.205 ;
     RECT  16.176 26.437 16.44 27.205 ;
     RECT  21.36 26.053 21.384 27.205 ;
     RECT  23.424 26.773 27.48 27.205 ;
     RECT  48.48 26.725 48.504 27.205 ;
     RECT  61.536 23.987 62.112 27.205 ;
     RECT  33.216 26.293 35.256 27.589 ;
     RECT  5.904 26.725 5.928 27.637 ;
     RECT  45.072 25.091 45.912 27.683 ;
     RECT  61.536 27.205 62.232 27.685 ;
     RECT  56.4 25.285 56.856 27.731 ;
     RECT  5.904 27.637 6.168 27.733 ;
     RECT  7.8 26.197 9.432 27.733 ;
     RECT  45.6 27.683 45.912 27.781 ;
     RECT  47.088 25.091 47.112 27.781 ;
     RECT  5.904 27.733 9.432 27.875 ;
     RECT  14.688 27.205 16.44 27.875 ;
     RECT  11.76 25.813 11.784 27.877 ;
     RECT  29.4 25.187 29.712 27.877 ;
     RECT  51 26.291 51.312 27.877 ;
     RECT  0.288 27.781 0.312 28.019 ;
     RECT  30.72 26.773 30.744 28.019 ;
     RECT  21.36 27.205 21.48 28.163 ;
     RECT  48.48 27.205 49.032 28.211 ;
     RECT  52.704 26.629 53.16 28.259 ;
     RECT  3.984 26.627 4.872 28.309 ;
     RECT  5.904 27.875 8.904 28.309 ;
     RECT  11.472 27.877 11.784 28.405 ;
     RECT  13.2 26.915 13.512 28.405 ;
     RECT  11.472 28.405 13.512 28.453 ;
     RECT  3.984 28.309 8.904 28.499 ;
     RECT  40.2 24.371 41.592 28.499 ;
     RECT  50.88 27.877 51.312 28.693 ;
     RECT  36.768 28.597 36.792 28.835 ;
     RECT  50.736 28.693 51.312 28.835 ;
     RECT  18.6 26.819 19.656 28.837 ;
     RECT  38.256 28.741 38.28 28.883 ;
     RECT  10.8 28.453 13.512 28.981 ;
     RECT  56.4 27.731 56.808 28.981 ;
     RECT  49.008 28.211 49.032 29.075 ;
     RECT  10.32 28.981 13.512 29.221 ;
     RECT  55.008 26.627 55.032 29.459 ;
     RECT  23.424 27.205 27.912 29.461 ;
     RECT  32.832 27.589 35.256 29.507 ;
     RECT  21.36 28.163 21.384 29.509 ;
     RECT  2.4 27.157 2.808 29.555 ;
     RECT  21.36 29.509 21.432 29.605 ;
     RECT  10.032 29.221 13.512 29.651 ;
     RECT  21.072 29.605 21.432 29.651 ;
     RECT  31.776 28.357 31.8 29.651 ;
     RECT  32.832 29.507 33.672 29.651 ;
     RECT  23.088 29.461 27.912 29.699 ;
     RECT  18.48 28.837 19.656 29.795 ;
     RECT  23.088 29.699 27.048 29.939 ;
     RECT  10.032 29.651 10.824 30.035 ;
     RECT  45.6 27.781 47.112 30.037 ;
     RECT  56.4 28.981 56.856 30.037 ;
     RECT  53.136 28.259 53.16 30.083 ;
     RECT  56.4 30.037 57.336 30.085 ;
     RECT  51 28.835 51.312 30.181 ;
     RECT  59.232 28.309 59.256 30.227 ;
     RECT  40.2 28.499 41.304 30.275 ;
     RECT  3.984 28.499 4.2 30.421 ;
     RECT  0.144 28.357 0.168 30.469 ;
     RECT  0.144 30.469 0.264 30.611 ;
     RECT  40.2 30.275 41.208 30.709 ;
     RECT  29.04 27.877 29.712 30.757 ;
     RECT  45.6 30.037 47.304 30.803 ;
     RECT  2.4 29.555 2.712 30.805 ;
     RECT  21.072 29.651 21.384 30.851 ;
     RECT  32.832 29.651 33.624 30.851 ;
     RECT  37.2 29.605 37.224 30.851 ;
     RECT  38.88 29.893 38.904 30.851 ;
     RECT  43.632 25.429 43.992 30.851 ;
     RECT  32.88 30.851 33.624 30.947 ;
     RECT  3.84 30.421 4.2 30.949 ;
     RECT  5.184 28.499 8.904 30.949 ;
     RECT  10.704 30.035 10.824 30.997 ;
     RECT  54.768 30.757 54.792 31.187 ;
     RECT  51 30.181 52.008 31.235 ;
     RECT  12.144 29.651 13.512 31.237 ;
     RECT  39.984 30.709 41.208 31.285 ;
     RECT  53.376 30.133 53.4 31.285 ;
     RECT  53.376 31.285 54.12 31.331 ;
     RECT  21.36 30.851 21.384 31.379 ;
     RECT  61.536 27.685 62.472 31.379 ;
     RECT  3.84 30.949 8.904 31.427 ;
     RECT  51 31.235 51.312 31.525 ;
     RECT  60.432 28.309 60.456 31.571 ;
     RECT  10.704 30.997 10.92 31.621 ;
     RECT  50.88 31.525 51.312 31.621 ;
     RECT  4.032 31.427 8.904 31.765 ;
     RECT  10.224 31.621 10.92 31.765 ;
     RECT  4.032 31.765 10.92 31.811 ;
     RECT  4.032 31.811 10.248 31.907 ;
     RECT  5.184 31.907 10.248 31.955 ;
     RECT  23.088 29.939 26.808 31.955 ;
     RECT  43.968 30.851 43.992 32.051 ;
     RECT  50.736 31.621 51.312 32.051 ;
     RECT  45.6 30.803 45.912 32.149 ;
     RECT  54.096 31.331 54.12 32.149 ;
     RECT  55.824 30.085 57.336 32.195 ;
     RECT  49.152 31.237 49.176 32.245 ;
     RECT  45.024 32.149 45.912 32.339 ;
     RECT  48.816 32.245 49.176 32.387 ;
     RECT  39.984 31.285 41.688 32.483 ;
     RECT  33.6 30.947 33.624 32.485 ;
     RECT  33.264 32.485 33.624 32.531 ;
     RECT  47.088 30.803 47.304 32.531 ;
     RECT  28.464 30.757 29.712 32.579 ;
     RECT  54.096 32.149 54.168 32.581 ;
     RECT  12.144 31.237 13.608 32.627 ;
     RECT  50.832 32.051 51.312 32.627 ;
     RECT  23.088 31.955 26.136 32.677 ;
     RECT  22.128 32.677 26.136 32.723 ;
     RECT  58.848 30.661 58.872 32.771 ;
     RECT  61.536 31.379 62.112 32.771 ;
     RECT  30.768 32.773 30.792 32.915 ;
     RECT  33.264 32.531 33.288 32.917 ;
     RECT  61.8 32.771 62.112 32.917 ;
     RECT  18.6 29.795 19.656 33.013 ;
     RECT  39.984 32.483 41.208 33.013 ;
     RECT  2.4 30.805 2.808 33.059 ;
     RECT  37.584 31.237 37.608 33.059 ;
     RECT  0.144 30.611 0.168 33.061 ;
     RECT  5.184 31.955 9.72 33.061 ;
     RECT  0.144 33.061 0.264 33.107 ;
     RECT  45.6 32.339 45.912 33.397 ;
     RECT  47.088 32.531 47.112 33.397 ;
     RECT  2.4 33.059 2.712 33.541 ;
     RECT  39.312 33.013 41.208 33.541 ;
     RECT  42.24 33.013 42.264 33.541 ;
     RECT  22.128 32.723 22.152 33.589 ;
     RECT  14.688 27.875 16.296 33.683 ;
     RECT  39.312 33.541 42.264 33.683 ;
     RECT  21.648 33.589 22.152 33.781 ;
     RECT  23.424 32.723 26.136 33.781 ;
     RECT  50.88 32.627 51.312 33.973 ;
     RECT  5.184 33.061 9.768 34.115 ;
     RECT  18.48 33.013 19.656 34.117 ;
     RECT  5.472 34.115 9.768 34.163 ;
     RECT  50.256 33.973 51.312 34.165 ;
     RECT  59.76 34.021 59.784 34.165 ;
     RECT  18.48 34.117 20.568 34.213 ;
     RECT  21.648 33.781 26.136 34.213 ;
     RECT  40.2 33.683 42.264 34.259 ;
     RECT  45.6 33.397 47.112 34.259 ;
     RECT  27.264 32.437 27.288 34.357 ;
     RECT  28.752 32.579 29.712 34.357 ;
     RECT  18.48 34.213 26.136 34.451 ;
     RECT  50.112 34.165 51.312 34.501 ;
     RECT  59.76 34.165 60.312 34.501 ;
     RECT  61.8 32.917 62.76 34.501 ;
     RECT  32.496 32.917 33.288 34.547 ;
     RECT  7.44 34.163 9.768 34.643 ;
     RECT  18.48 34.451 20.568 34.693 ;
     RECT  18.096 34.693 20.568 34.741 ;
     RECT  43.92 32.293 43.944 34.789 ;
     RECT  15.36 33.683 16.296 34.835 ;
     RECT  21.648 34.451 26.136 34.835 ;
     RECT  43.92 34.789 44.04 34.835 ;
     RECT  17.904 34.741 20.568 34.931 ;
     RECT  59.76 34.501 62.76 34.931 ;
     RECT  55.296 33.013 55.32 34.979 ;
     RECT  15.648 34.835 16.296 35.077 ;
     RECT  50.112 34.501 52.152 35.219 ;
     RECT  46.896 34.259 47.112 35.267 ;
     RECT  0.24 33.107 0.264 35.269 ;
     RECT  53.568 32.581 54.168 35.269 ;
     RECT  21.648 34.835 21.672 35.315 ;
     RECT  51 35.219 52.152 35.315 ;
     RECT  12.288 32.627 13.608 35.317 ;
     RECT  7.44 34.643 9.24 35.363 ;
     RECT  27.264 34.357 29.712 35.363 ;
     RECT  42.24 34.259 42.264 35.363 ;
     RECT  27.264 35.363 27.288 35.411 ;
     RECT  4.032 31.907 4.2 35.413 ;
     RECT  34.8 29.507 35.256 35.413 ;
     RECT  59.76 34.931 62.112 35.459 ;
     RECT  34.8 35.413 35.832 35.555 ;
     RECT  12.288 35.317 14.088 35.653 ;
     RECT  40.2 34.259 41.208 35.701 ;
     RECT  53.568 35.269 54.792 35.747 ;
     RECT  12.048 35.653 14.088 35.795 ;
     RECT  5.472 34.163 6.12 35.797 ;
     RECT  23.136 34.835 26.136 35.845 ;
     RECT  37.632 35.269 37.656 35.845 ;
     RECT  38.688 35.173 38.712 35.845 ;
     RECT  2.304 33.541 2.712 35.939 ;
     RECT  30.912 35.269 30.936 35.939 ;
     RECT  51 35.315 51.912 35.939 ;
     RECT  7.68 35.363 9.24 35.941 ;
     RECT  20.544 34.931 20.568 35.941 ;
     RECT  20.544 35.941 20.808 35.987 ;
     RECT  3.936 35.413 4.2 36.085 ;
     RECT  5.472 35.797 6.264 36.085 ;
     RECT  0.144 35.269 0.264 36.131 ;
     RECT  3.936 36.085 6.264 36.131 ;
     RECT  46.896 35.267 47.016 36.275 ;
     RECT  2.4 35.939 2.712 36.421 ;
     RECT  7.68 35.941 9.384 36.421 ;
     RECT  7.68 36.421 9.864 36.563 ;
     RECT  0.192 36.131 0.264 36.611 ;
     RECT  37.632 35.845 38.712 36.661 ;
     RECT  37.488 36.661 38.712 36.707 ;
     RECT  46.992 36.275 47.016 36.803 ;
     RECT  0.192 36.611 0.216 36.851 ;
     RECT  12.288 35.795 14.088 36.949 ;
     RECT  17.904 34.931 19.08 36.949 ;
     RECT  59.28 36.085 59.304 36.949 ;
     RECT  60.288 35.459 62.112 36.949 ;
     RECT  40.08 35.701 41.208 36.997 ;
     RECT  45.6 34.259 45.912 37.045 ;
     RECT  4.176 36.131 6.264 37.091 ;
     RECT  17.904 36.949 19.416 37.091 ;
     RECT  40.08 36.997 42.168 37.091 ;
     RECT  4.176 37.091 5.688 37.139 ;
     RECT  40.08 37.091 40.512 37.285 ;
     RECT  56.4 32.195 57.336 37.285 ;
     RECT  39.984 37.285 40.512 37.427 ;
     RECT  2.4 36.421 3.144 37.429 ;
     RECT  4.176 37.139 5.496 37.429 ;
     RECT  12.288 36.949 14.376 37.573 ;
     RECT  15.648 35.077 16.632 37.573 ;
     RECT  22.752 35.845 26.136 37.573 ;
     RECT  37.488 36.707 37.656 37.619 ;
     RECT  12.288 37.573 16.632 37.667 ;
     RECT  21.792 37.573 26.136 37.667 ;
     RECT  42.144 37.091 42.168 37.667 ;
     RECT  40.08 37.427 40.512 37.715 ;
     RECT  13.2 37.667 16.632 38.195 ;
     RECT  59.28 36.949 62.112 38.243 ;
     RECT  2.4 37.429 5.496 38.245 ;
     RECT  52.416 36.325 52.44 38.387 ;
     RECT  54.288 35.747 54.792 38.483 ;
     RECT  37.632 37.619 37.656 38.581 ;
     RECT  38.688 36.707 38.712 38.581 ;
     RECT  14.592 38.195 16.632 38.627 ;
     RECT  37.632 38.581 38.712 38.627 ;
     RECT  48.816 32.387 48.84 38.629 ;
     RECT  21.792 37.667 21.816 38.675 ;
     RECT  51 35.939 51.312 38.677 ;
     RECT  2.4 38.245 5.928 38.725 ;
     RECT  18.48 37.091 19.416 38.771 ;
     RECT  34.8 35.555 35.352 38.819 ;
     RECT  7.8 36.563 9.864 38.915 ;
     RECT  2.4 38.725 6.456 38.963 ;
     RECT  0.144 37.957 0.168 39.011 ;
     RECT  53.232 38.917 53.256 39.059 ;
     RECT  23.136 37.667 26.136 39.205 ;
     RECT  44.016 34.835 44.04 39.253 ;
     RECT  37.632 38.627 38.472 39.299 ;
     RECT  2.4 38.963 5.304 39.347 ;
     RECT  43.056 39.253 44.04 39.395 ;
     RECT  7.8 38.915 9.672 39.491 ;
     RECT  13.2 38.195 13.512 39.589 ;
     RECT  14.592 38.627 14.712 39.589 ;
     RECT  58.896 39.061 58.92 39.635 ;
     RECT  60.096 38.243 62.112 39.733 ;
     RECT  16.032 38.627 16.632 39.781 ;
     RECT  12 38.725 12.024 39.877 ;
     RECT  13.2 39.589 14.712 39.877 ;
     RECT  16.032 39.781 17.208 39.877 ;
     RECT  18.6 38.771 19.416 39.877 ;
     RECT  51 38.677 51.912 39.877 ;
     RECT  2.4 39.347 5.208 39.923 ;
     RECT  32.256 36.421 32.28 40.019 ;
     RECT  48.672 38.629 48.84 40.019 ;
     RECT  54.288 38.483 54.696 40.019 ;
     RECT  40.2 37.715 40.512 40.069 ;
     RECT  12 39.877 14.712 40.115 ;
     RECT  7.8 39.491 9.384 40.165 ;
     RECT  43.056 39.395 43.08 40.211 ;
     RECT  23.136 39.205 27 40.259 ;
     RECT  0.144 40.069 0.168 40.355 ;
     RECT  7.68 40.165 9.384 40.355 ;
     RECT  40.2 40.069 41.208 40.403 ;
     RECT  23.136 40.259 26.136 40.693 ;
     RECT  18.6 39.877 19.656 40.739 ;
     RECT  60.096 39.733 62.664 40.835 ;
     RECT  12.528 40.115 14.712 40.885 ;
     RECT  15.696 39.877 17.208 40.885 ;
     RECT  44.16 39.637 44.184 41.027 ;
     RECT  45.264 37.045 45.912 41.075 ;
     RECT  7.68 40.355 8.376 41.171 ;
     RECT  37.056 40.117 37.08 41.363 ;
     RECT  12.528 40.885 17.208 41.507 ;
     RECT  51 39.877 52.152 41.557 ;
     RECT  12.672 41.507 17.208 41.603 ;
     RECT  12.672 41.603 16.632 41.651 ;
     RECT  54.288 40.019 54.312 41.651 ;
     RECT  22.224 40.693 26.136 41.749 ;
     RECT  40.2 40.403 40.512 41.749 ;
     RECT  9.36 40.355 9.384 41.893 ;
     RECT  10.464 41.461 10.488 41.893 ;
     RECT  2.4 39.923 4.968 41.939 ;
     RECT  9.36 41.893 10.488 41.939 ;
     RECT  31.68 41.365 31.704 41.939 ;
     RECT  20.784 35.987 20.808 41.941 ;
     RECT  4.176 41.939 4.968 41.987 ;
     RECT  56.4 37.285 57.432 41.989 ;
     RECT  9.36 41.939 9.672 42.035 ;
     RECT  59.76 42.133 59.784 42.181 ;
     RECT  61.008 40.835 62.664 42.181 ;
     RECT  22.224 41.749 26.472 42.227 ;
     RECT  59.76 42.181 62.664 42.275 ;
     RECT  15.504 41.651 16.632 42.323 ;
     RECT  12.672 41.651 14.04 42.517 ;
     RECT  45.36 41.075 45.912 42.565 ;
     RECT  6.432 38.963 6.456 42.709 ;
     RECT  18.6 40.739 19.416 42.709 ;
     RECT  20.784 41.941 21.144 42.709 ;
     RECT  28.752 35.363 29.712 42.709 ;
     RECT  33.264 34.547 33.288 42.709 ;
     RECT  48.816 40.019 48.84 42.709 ;
     RECT  40.08 41.749 40.512 42.755 ;
     RECT  12.528 42.517 14.04 42.851 ;
     RECT  27.552 42.709 27.576 42.949 ;
     RECT  59.76 42.275 62.112 43.043 ;
     RECT  11.232 42.133 11.256 43.093 ;
     RECT  12.528 42.851 13.512 43.093 ;
     RECT  9.648 42.035 9.672 43.285 ;
     RECT  51 41.557 52.248 43.331 ;
     RECT  15.504 42.323 16.584 43.573 ;
     RECT  60.096 43.043 62.112 43.619 ;
     RECT  14.784 43.573 16.584 43.621 ;
     RECT  4.944 41.987 4.968 43.813 ;
     RECT  38.448 39.299 38.472 43.813 ;
     RECT  40.2 42.755 40.512 43.813 ;
     RECT  45.264 42.565 45.912 43.813 ;
     RECT  2.4 41.939 3.192 43.861 ;
     RECT  4.224 43.813 4.968 43.861 ;
     RECT  6.288 42.709 6.456 44.005 ;
     RECT  7.8 41.171 8.376 44.005 ;
     RECT  45.264 43.813 46.776 44.005 ;
     RECT  48.816 42.709 49.608 44.051 ;
     RECT  6.288 44.005 8.376 44.053 ;
     RECT  9.648 43.285 9.72 44.053 ;
     RECT  38.448 43.813 40.512 44.101 ;
     RECT  55.392 43.573 55.416 44.101 ;
     RECT  56.4 41.989 57.624 44.101 ;
     RECT  6.288 44.053 9.72 44.147 ;
     RECT  23.136 42.227 26.472 44.149 ;
     RECT  27.456 42.949 27.576 44.149 ;
     RECT  60.096 43.619 60.12 44.195 ;
     RECT  2.4 43.861 4.968 44.197 ;
     RECT  6.288 44.147 6.456 44.197 ;
     RECT  55.392 44.101 57.624 44.243 ;
     RECT  7.8 44.147 9.72 44.387 ;
     RECT  28.752 42.709 30.072 44.435 ;
     RECT  45.024 44.005 46.776 44.435 ;
     RECT  33.168 42.709 33.288 44.437 ;
     RECT  48.816 44.051 48.84 44.437 ;
     RECT  11.232 43.093 13.512 44.483 ;
     RECT  18.6 42.709 21.144 44.483 ;
     RECT  23.136 44.149 27.576 44.483 ;
     RECT  37.104 41.557 37.128 44.483 ;
     RECT  53.328 43.861 53.352 44.483 ;
     RECT  61.68 43.619 62.112 44.531 ;
     RECT  14.784 43.621 16.872 44.579 ;
     RECT  12.144 44.483 13.512 44.627 ;
     RECT  18.6 44.483 21.096 44.627 ;
     RECT  18.6 44.627 19.896 44.677 ;
     RECT  28.752 44.435 29.976 44.771 ;
     RECT  38.448 44.101 40.728 44.773 ;
     RECT  27.552 44.483 27.576 44.915 ;
     RECT  0.192 43.717 0.216 44.963 ;
     RECT  15.504 44.579 16.872 44.965 ;
     RECT  9.12 44.387 9.72 45.011 ;
     RECT  15.504 44.965 17.448 45.011 ;
     RECT  54.288 44.821 54.312 45.013 ;
     RECT  55.392 44.243 55.416 45.013 ;
     RECT  2.4 44.197 6.456 45.059 ;
     RECT  9.216 45.011 9.72 45.059 ;
     RECT  12.144 44.627 12.168 45.107 ;
     RECT  38.448 44.773 40.968 45.107 ;
     RECT  23.136 44.483 26.472 45.299 ;
     RECT  33.072 44.437 33.288 45.347 ;
     RECT  4.944 45.059 6.456 45.443 ;
     RECT  18.48 44.677 19.896 45.539 ;
     RECT  38.448 45.107 38.808 45.539 ;
     RECT  4.992 45.443 6.36 45.635 ;
     RECT  21.072 44.627 21.096 45.635 ;
     RECT  45.264 44.435 46.776 45.635 ;
     RECT  51 43.331 52.152 45.635 ;
     RECT  13.2 44.627 13.512 45.637 ;
     RECT  40.2 45.107 40.968 45.733 ;
     RECT  2.4 45.059 3.624 46.019 ;
     RECT  12.192 45.637 13.512 46.067 ;
     RECT  13.104 46.067 13.512 46.069 ;
     RECT  40.2 45.733 41.496 46.115 ;
     RECT  28.752 44.771 29.712 46.117 ;
     RECT  48.672 44.437 48.84 46.117 ;
     RECT  13.104 46.069 14.28 46.163 ;
     RECT  31.056 44.725 31.08 46.163 ;
     RECT  38.784 45.539 38.808 46.499 ;
     RECT  54.288 45.013 55.416 46.499 ;
     RECT  42.816 45.109 42.84 46.501 ;
     RECT  51 45.635 51.312 46.549 ;
     RECT  42.48 46.501 42.84 46.741 ;
     RECT  13.2 46.163 14.28 46.787 ;
     RECT  7.8 44.387 8.112 46.837 ;
     RECT  9.216 45.059 9.24 46.837 ;
     RECT  0.144 45.733 0.168 46.885 ;
     RECT  4.992 45.635 5.016 46.885 ;
     RECT  6.336 45.635 6.36 46.885 ;
     RECT  7.8 46.837 9.24 47.075 ;
     RECT  31.68 47.029 31.704 47.171 ;
     RECT  54.576 46.499 55.416 47.171 ;
     RECT  9.12 47.075 9.24 47.267 ;
     RECT  11.952 47.029 11.976 47.267 ;
     RECT  4.992 46.885 6.36 47.315 ;
     RECT  2.4 46.019 3.432 47.363 ;
     RECT  15.696 45.011 17.448 47.363 ;
     RECT  27.936 46.117 29.712 47.363 ;
     RECT  41.616 46.741 42.84 47.363 ;
     RECT  48.624 46.117 48.84 47.363 ;
     RECT  56.4 44.243 57.624 47.363 ;
     RECT  0.144 46.885 0.408 47.411 ;
     RECT  41.616 47.363 41.64 47.555 ;
     RECT  23.664 45.299 26.472 47.653 ;
     RECT  15.696 47.363 16.536 47.699 ;
     RECT  21.072 47.653 21.096 47.795 ;
     RECT  9.216 47.267 9.24 47.845 ;
     RECT  40.2 46.115 40.632 47.845 ;
     RECT  55.392 47.171 55.416 47.845 ;
     RECT  56.4 47.363 56.712 47.845 ;
     RECT  4.992 47.315 5.016 47.893 ;
     RECT  36.432 47.269 36.456 47.987 ;
     RECT  6.336 47.315 6.36 48.131 ;
     RECT  23.424 47.653 26.472 48.181 ;
     RECT  40.2 47.845 40.776 48.229 ;
     RECT  11.568 47.845 11.592 48.275 ;
     RECT  7.8 47.075 8.112 48.373 ;
     RECT  39.84 48.229 40.776 48.707 ;
     RECT  48.816 47.363 48.84 48.709 ;
     RECT  43.968 47.845 43.992 48.851 ;
     RECT  9.216 47.845 9.576 48.949 ;
     RECT  15.696 47.699 16.296 48.949 ;
     RECT  28.8 47.363 29.712 48.949 ;
     RECT  9.12 48.949 9.576 48.995 ;
     RECT  18.6 45.539 19.896 48.997 ;
     RECT  37.632 47.845 37.656 48.997 ;
     RECT  21.168 48.901 21.192 49.043 ;
     RECT  48.816 48.709 49.08 49.043 ;
     RECT  2.4 47.363 2.856 49.045 ;
     RECT  34.8 38.819 35.256 49.045 ;
     RECT  4.56 47.893 5.016 49.091 ;
     RECT  37.296 48.997 37.656 49.475 ;
     RECT  22.224 48.421 22.248 49.477 ;
     RECT  23.424 48.181 26.76 49.477 ;
     RECT  13.2 46.787 13.512 49.525 ;
     RECT  42.816 47.363 42.84 49.573 ;
     RECT  22.224 49.477 26.76 49.619 ;
     RECT  55.392 47.845 56.712 49.619 ;
     RECT  17.712 48.997 19.896 49.763 ;
     RECT  0.384 47.411 0.408 49.765 ;
     RECT  37.296 49.475 37.32 49.861 ;
     RECT  42.816 49.573 43.176 49.907 ;
     RECT  45.264 45.635 45.912 49.909 ;
     RECT  50.4 46.549 51.312 49.909 ;
     RECT  52.416 47.797 52.44 49.909 ;
     RECT  31.344 48.229 31.368 49.955 ;
     RECT  50.4 49.909 52.44 49.955 ;
     RECT  44.928 49.909 45.912 50.005 ;
     RECT  36.864 49.861 37.32 50.099 ;
     RECT  56.304 49.619 56.712 50.101 ;
     RECT  58.128 49.333 58.152 50.101 ;
     RECT  56.304 50.101 58.152 50.147 ;
     RECT  28.272 48.949 29.712 50.243 ;
     RECT  0.144 49.765 0.408 50.339 ;
     RECT  4.992 49.091 5.016 50.341 ;
     RECT  9.12 48.995 9.144 50.531 ;
     RECT  22.656 49.619 26.76 50.531 ;
     RECT  48.816 49.043 48.84 50.533 ;
     RECT  4.992 50.341 5.16 50.579 ;
     RECT  39.84 48.707 40.512 50.581 ;
     RECT  59.184 48.229 59.208 50.581 ;
     RECT  44.928 50.005 46.152 50.675 ;
     RECT  18.384 49.763 19.896 50.677 ;
     RECT  39.84 50.581 41.448 50.677 ;
     RECT  42.816 49.907 42.84 50.677 ;
     RECT  22.944 50.531 26.76 50.723 ;
     RECT  50.4 49.955 52.104 50.723 ;
     RECT  39.84 50.677 42.84 50.819 ;
     RECT  15.696 48.949 16.584 50.821 ;
     RECT  2.4 49.045 3.432 50.965 ;
     RECT  53.568 50.677 53.592 50.965 ;
     RECT  18.384 50.677 19.944 51.013 ;
     RECT  25.392 50.723 26.76 51.059 ;
     RECT  34.8 49.045 35.496 51.109 ;
     RECT  18.384 51.013 20.904 51.155 ;
     RECT  14.832 50.821 16.584 51.251 ;
     RECT  7.296 48.373 8.112 51.253 ;
     RECT  12.816 49.525 13.512 51.253 ;
     RECT  48.816 50.533 48.936 51.299 ;
     RECT  59.184 50.581 59.784 51.299 ;
     RECT  0.24 50.339 0.408 51.301 ;
     RECT  25.392 51.059 26.472 51.347 ;
     RECT  37.296 50.099 37.32 51.349 ;
     RECT  0.192 51.301 0.408 51.397 ;
     RECT  18.384 51.155 19.944 51.443 ;
     RECT  33.264 45.347 33.288 51.541 ;
     RECT  34.8 51.109 35.688 51.541 ;
     RECT  32.4 51.541 33.288 51.587 ;
     RECT  50.4 50.723 51.864 51.635 ;
     RECT  12.528 51.253 13.512 51.685 ;
     RECT  7.296 51.253 8.28 51.733 ;
     RECT  56.304 50.147 57.432 51.779 ;
     RECT  51 51.635 51.864 51.781 ;
     RECT  28.8 50.243 29.712 51.829 ;
     RECT  34.8 51.541 35.784 51.875 ;
     RECT  40.2 50.819 42.84 51.875 ;
     RECT  36.96 51.349 37.32 51.923 ;
     RECT  38.832 50.773 38.856 51.923 ;
     RECT  42.816 51.875 42.84 51.925 ;
     RECT  0.144 51.397 0.408 52.021 ;
     RECT  53.424 50.965 53.592 52.021 ;
     RECT  53.424 52.021 54.168 52.067 ;
     RECT  59.76 51.299 59.784 52.069 ;
     RECT  11.184 51.973 11.208 52.115 ;
     RECT  25.392 51.347 25.704 52.115 ;
     RECT  12.288 51.685 13.512 52.117 ;
     RECT  4.992 50.579 5.016 52.165 ;
     RECT  36.96 51.923 36.984 52.165 ;
     RECT  15.696 51.251 16.584 52.259 ;
     RECT  51 51.781 52.2 52.307 ;
     RECT  34.8 51.875 35.592 52.451 ;
     RECT  15.936 52.259 16.584 52.597 ;
     RECT  21.312 52.405 21.336 52.693 ;
     RECT  22.944 50.723 24.408 52.693 ;
     RECT  18.432 51.443 19.944 52.739 ;
     RECT  0.144 52.021 0.504 52.741 ;
     RECT  15.936 52.597 17.16 52.787 ;
     RECT  4.992 52.165 5.112 52.789 ;
     RECT  51 52.307 51.672 52.789 ;
     RECT  0.144 52.741 1.176 52.883 ;
     RECT  32.4 51.587 32.952 52.979 ;
     RECT  42.816 51.925 43.608 52.979 ;
     RECT  12.288 52.117 13.656 52.981 ;
     RECT  27.936 51.829 29.712 52.981 ;
     RECT  40.2 51.875 41.448 52.981 ;
     RECT  0.384 52.883 1.176 53.027 ;
     RECT  45.264 50.675 45.912 53.075 ;
     RECT  15.936 52.787 15.96 53.123 ;
     RECT  27.936 52.981 30.216 53.123 ;
     RECT  50.736 52.789 51.672 53.123 ;
     RECT  61.8 44.531 62.112 53.173 ;
     RECT  36.72 52.165 36.984 53.219 ;
     RECT  12 52.981 13.656 53.267 ;
     RECT  21.312 52.693 24.408 53.267 ;
     RECT  56.4 51.779 57.432 53.269 ;
     RECT  47.568 51.781 47.592 53.365 ;
     RECT  61.8 53.173 62.808 53.507 ;
     RECT  13.2 53.267 13.656 53.509 ;
     RECT  32.4 52.979 32.424 53.557 ;
     RECT  45.408 53.075 45.912 53.557 ;
     RECT  4.992 52.789 5.688 53.797 ;
     RECT  7.296 51.733 8.328 53.797 ;
     RECT  51 53.123 51.672 54.085 ;
     RECT  53.52 52.067 54.168 54.085 ;
     RECT  40.2 52.981 41.64 54.131 ;
     RECT  28.56 53.123 30.216 54.179 ;
     RECT  2.4 50.965 3.672 54.371 ;
     RECT  20.64 53.413 20.664 54.371 ;
     RECT  33.6 53.557 33.624 54.371 ;
     RECT  36.624 54.181 36.648 54.371 ;
     RECT  59.76 52.069 59.88 54.371 ;
     RECT  13.2 53.509 14.28 54.373 ;
     RECT  63.216 53.557 63.24 54.515 ;
     RECT  12 53.267 12.024 54.611 ;
     RECT  0.384 53.027 0.408 54.661 ;
     RECT  51 54.085 51.864 54.661 ;
     RECT  61.8 53.507 62.112 54.661 ;
     RECT  0.192 54.661 0.408 54.707 ;
     RECT  31.68 53.557 32.424 54.707 ;
     RECT  45.408 53.557 46.344 54.707 ;
     RECT  47.472 53.365 47.592 54.707 ;
     RECT  18.432 52.739 19.608 54.709 ;
     RECT  37.68 53.269 37.704 54.709 ;
     RECT  42.816 52.979 42.84 54.709 ;
     RECT  48.816 51.299 48.84 54.709 ;
     RECT  42.816 54.709 42.984 54.755 ;
     RECT  48.816 54.709 48.936 54.755 ;
     RECT  13.104 54.373 14.28 54.899 ;
     RECT  4.992 53.797 8.328 55.187 ;
     RECT  40.2 54.131 41.448 55.187 ;
     RECT  47.568 54.707 47.592 55.237 ;
     RECT  17.616 54.709 19.608 55.283 ;
     RECT  59.76 54.371 59.784 55.283 ;
     RECT  13.104 54.899 14.184 55.285 ;
     RECT  56.4 53.269 57.768 55.331 ;
     RECT  53.52 54.085 54.696 55.427 ;
     RECT  50.544 54.661 51.864 55.475 ;
     RECT  2.4 54.371 3.528 55.667 ;
     RECT  13.008 55.285 14.184 55.667 ;
     RECT  37.68 54.709 38.376 55.667 ;
     RECT  13.104 55.667 14.184 55.763 ;
     RECT  17.904 55.283 19.608 55.763 ;
     RECT  47.568 55.237 47.88 55.955 ;
     RECT  4.992 55.187 5.688 56.003 ;
     RECT  61.8 54.661 62.28 56.051 ;
     RECT  13.2 55.763 14.184 56.243 ;
     RECT  38.352 55.667 38.376 56.243 ;
     RECT  42.864 54.755 42.984 56.243 ;
     RECT  17.904 55.763 19.08 56.341 ;
     RECT  34.8 52.451 35.256 56.341 ;
     RECT  53.52 55.427 54.408 56.389 ;
     RECT  33.552 55.237 33.576 56.483 ;
     RECT  45.408 54.707 45.912 56.533 ;
     RECT  57.744 55.331 57.768 56.533 ;
     RECT  45.408 56.533 46.152 56.579 ;
     RECT  34.8 56.341 35.352 56.773 ;
     RECT  34.224 56.773 35.352 56.963 ;
     RECT  40.2 55.187 41.304 56.965 ;
     RECT  47.568 55.955 47.592 56.965 ;
     RECT  50.544 55.475 51.312 56.965 ;
     RECT  53.52 56.389 54.696 56.965 ;
     RECT  32.4 54.707 32.424 57.013 ;
     RECT  53.328 56.965 54.696 57.013 ;
     RECT  3.84 56.437 3.864 57.059 ;
     RECT  48.912 54.755 48.936 57.059 ;
     RECT  22.224 53.267 24.408 57.299 ;
     RECT  40.08 56.965 41.304 57.347 ;
     RECT  40.08 57.347 41.064 57.397 ;
     RECT  56.4 55.331 56.712 57.445 ;
     RECT  7.392 55.187 8.328 57.541 ;
     RECT  47.328 56.965 47.592 57.541 ;
     RECT  56.208 57.445 56.712 57.541 ;
     RECT  43.968 55.813 43.992 57.587 ;
     RECT  52.464 57.013 54.696 57.587 ;
     RECT  50.16 56.965 51.312 57.635 ;
     RECT  4.992 56.003 5.112 57.685 ;
     RECT  47.328 57.541 48.504 57.875 ;
     RECT  61.8 56.051 62.112 57.877 ;
     RECT  6.912 57.541 8.328 57.971 ;
     RECT  52.464 57.587 53.544 58.115 ;
     RECT  4.992 57.685 5.352 58.117 ;
     RECT  13.2 56.243 13.608 58.117 ;
     RECT  42.96 56.243 42.984 58.117 ;
     RECT  45.6 56.579 46.152 58.117 ;
     RECT  56.112 57.541 56.712 58.117 ;
     RECT  57.744 56.533 58.152 58.117 ;
     RECT  7.392 57.971 8.328 58.163 ;
     RECT  53.328 58.115 53.544 58.163 ;
     RECT  56.112 58.117 58.152 58.163 ;
     RECT  47.568 57.875 48.504 58.355 ;
     RECT  56.112 58.163 57.288 58.355 ;
     RECT  42.96 58.117 43.896 58.451 ;
     RECT  17.664 56.341 19.08 58.547 ;
     RECT  4.608 58.117 5.352 58.691 ;
     RECT  32.4 57.013 33.096 58.739 ;
     RECT  34.8 56.963 35.352 58.739 ;
     RECT  54.576 57.587 54.696 58.739 ;
     RECT  56.112 58.355 56.808 58.739 ;
     RECT  39.456 57.397 41.064 58.931 ;
     RECT  43.872 58.451 43.896 59.123 ;
     RECT  22.224 57.299 24.312 59.171 ;
     RECT  18.6 58.547 19.08 59.173 ;
     RECT  2.4 55.667 2.712 59.221 ;
     RECT  61.2 57.877 62.112 59.221 ;
     RECT  4.608 58.691 5.112 59.267 ;
     RECT  22.272 59.171 24.312 59.315 ;
     RECT  18.6 59.173 19.416 59.461 ;
     RECT  20.688 54.565 20.712 59.461 ;
     RECT  15.264 57.109 15.288 59.605 ;
     RECT  25.392 52.115 25.608 59.605 ;
     RECT  4.608 59.267 4.632 59.891 ;
     RECT  13.2 58.117 13.704 59.891 ;
     RECT  25.344 59.605 26.232 60.229 ;
     RECT  28.8 54.179 30.216 60.275 ;
     RECT  32.4 58.739 32.568 60.275 ;
     RECT  22.752 59.315 24.312 60.323 ;
     RECT  25.344 60.229 26.76 60.323 ;
     RECT  29.088 60.275 30.216 60.323 ;
     RECT  2.304 59.221 2.712 60.373 ;
     RECT  11.664 58.117 11.688 60.373 ;
     RECT  56.112 58.739 56.712 60.373 ;
     RECT  57.984 59.221 58.008 60.373 ;
     RECT  10.8 60.373 11.688 60.467 ;
     RECT  45.408 58.117 46.152 60.467 ;
     RECT  2.304 60.373 2.856 60.563 ;
     RECT  14.736 59.605 15.288 60.563 ;
     RECT  18.6 59.461 20.712 60.611 ;
     RECT  10.8 60.467 11.448 60.661 ;
     RECT  40.2 58.931 41.064 60.661 ;
     RECT  42.288 59.605 42.312 60.661 ;
     RECT  18.6 60.611 19.896 60.709 ;
     RECT  40.2 60.661 42.312 60.709 ;
     RECT  40.2 60.709 42.696 60.755 ;
     RECT  7.392 58.163 8.112 60.851 ;
     RECT  40.2 60.755 41.592 60.901 ;
     RECT  47.568 58.355 47.592 60.901 ;
     RECT  47.568 60.901 47.832 60.947 ;
     RECT  54.576 58.739 54.6 60.997 ;
     RECT  53.52 58.163 53.544 61.043 ;
     RECT  60.384 59.221 62.112 61.043 ;
     RECT  63.168 60.373 63.192 61.043 ;
     RECT  56.112 60.373 58.008 61.091 ;
     RECT  13.2 59.891 13.608 61.285 ;
     RECT  10.704 60.661 11.448 61.333 ;
     RECT  56.112 61.091 57.048 61.379 ;
     RECT  45.6 60.467 46.152 61.429 ;
     RECT  2.4 60.563 2.856 61.571 ;
     RECT  10.272 61.333 11.448 61.619 ;
     RECT  48.816 59.029 48.84 61.619 ;
     RECT  34.8 58.739 35.256 61.717 ;
     RECT  22.944 60.323 24.312 61.765 ;
     RECT  33.744 60.853 33.768 61.907 ;
     RECT  13.2 61.285 13.656 62.003 ;
     RECT  32.4 60.275 32.424 62.101 ;
     RECT  13.2 62.003 13.608 62.149 ;
     RECT  34.8 61.717 35.352 62.195 ;
     RECT  39.936 60.901 41.592 62.195 ;
     RECT  42.672 60.755 42.696 62.195 ;
     RECT  25.392 60.323 26.76 62.339 ;
     RECT  45.36 61.429 46.152 62.341 ;
     RECT  47.808 60.947 47.832 62.341 ;
     RECT  51 57.635 51.312 62.341 ;
     RECT  39.936 62.195 41.064 62.579 ;
     RECT  0.192 54.707 0.216 62.725 ;
     RECT  11.424 61.619 11.448 62.725 ;
     RECT  12.528 62.149 13.608 62.725 ;
     RECT  31.776 62.101 32.424 62.725 ;
     RECT  3.696 62.053 3.72 62.771 ;
     RECT  22.08 61.765 24.312 62.771 ;
     RECT  11.424 62.725 13.608 63.013 ;
     RECT  15.264 60.563 15.288 63.013 ;
     RECT  18.48 60.709 19.896 63.013 ;
     RECT  18.432 63.013 19.896 63.155 ;
     RECT  7.44 60.851 8.112 63.205 ;
     RECT  11.424 63.013 15.288 63.205 ;
     RECT  29.232 60.323 30.216 63.205 ;
     RECT  54.576 60.997 54.744 63.205 ;
     RECT  11.376 63.205 15.288 63.251 ;
     RECT  31.776 62.725 33.048 63.251 ;
     RECT  39.936 62.579 40.968 63.347 ;
     RECT  51 62.341 52.2 63.349 ;
     RECT  60.048 62.149 60.072 63.491 ;
     RECT  10.272 61.619 10.296 63.493 ;
     RECT  11.376 63.251 11.928 63.493 ;
     RECT  28.896 63.205 30.216 63.493 ;
     RECT  0.192 62.725 0.408 63.541 ;
     RECT  2.4 61.571 2.712 63.541 ;
     RECT  10.272 63.493 11.928 63.587 ;
     RECT  18.48 63.155 19.896 63.587 ;
     RECT  18.6 63.587 19.896 63.637 ;
     RECT  53.952 63.205 54.744 63.637 ;
     RECT  56.112 61.379 56.712 63.637 ;
     RECT  34.8 62.195 35.256 63.685 ;
     RECT  36.672 62.677 36.696 63.685 ;
     RECT  10.608 63.587 11.928 63.731 ;
     RECT  28.896 63.493 30.312 63.731 ;
     RECT  13.2 63.251 15.288 63.827 ;
     RECT  27.888 63.253 27.912 63.827 ;
     RECT  51 63.349 52.248 63.827 ;
     RECT  61.2 61.043 62.112 63.827 ;
     RECT  49.056 62.821 49.08 63.875 ;
     RECT  40.2 63.347 40.968 63.923 ;
     RECT  28.896 63.731 29.832 64.021 ;
     RECT  7.44 63.205 8.712 64.067 ;
     RECT  14.592 63.827 15.288 64.067 ;
     RECT  53.952 63.637 56.712 64.069 ;
     RECT  2.4 63.541 2.808 64.163 ;
     RECT  25.488 62.339 26.76 64.357 ;
     RECT  16.992 63.157 17.016 64.453 ;
     RECT  18.6 63.637 20.376 64.453 ;
     RECT  34.8 63.685 36.696 64.501 ;
     RECT  18.6 64.453 21.048 64.595 ;
     RECT  32.4 63.251 32.52 64.595 ;
     RECT  34.8 64.501 37.08 64.643 ;
     RECT  16.992 64.453 17.16 64.691 ;
     RECT  15.264 64.067 15.288 64.837 ;
     RECT  22.944 62.771 24.312 64.883 ;
     RECT  40.2 63.923 40.632 64.883 ;
     RECT  28.512 64.021 29.832 64.933 ;
     RECT  53.952 64.069 56.904 64.981 ;
     RECT  11.04 63.731 11.928 65.027 ;
     RECT  16.992 64.691 17.112 65.027 ;
     RECT  42.72 62.293 42.744 65.027 ;
     RECT  52.32 64.069 52.344 65.027 ;
     RECT  59.808 63.781 59.832 65.123 ;
     RECT  53.952 64.981 57.624 65.171 ;
     RECT  51 63.827 51.312 65.173 ;
     RECT  6.384 65.077 6.408 65.267 ;
     RECT  11.568 65.027 11.928 65.269 ;
     RECT  13.2 63.827 13.608 65.269 ;
     RECT  4.032 64.981 4.056 65.365 ;
     RECT  21.024 64.595 21.048 65.365 ;
     RECT  11.568 65.269 13.608 65.411 ;
     RECT  2.4 64.163 2.712 65.413 ;
     RECT  51 65.173 51.816 65.459 ;
     RECT  23.328 64.883 24.312 65.461 ;
     RECT  25.488 64.357 26.952 65.461 ;
     RECT  9.12 65.173 9.144 65.507 ;
     RECT  53.952 65.171 54.744 65.509 ;
     RECT  61.632 63.827 62.112 65.509 ;
     RECT  63.12 64.741 63.144 65.509 ;
     RECT  66.816 64.933 66.84 65.509 ;
     RECT  2.4 65.413 2.808 65.555 ;
     RECT  7.44 64.067 8.112 65.555 ;
     RECT  11.568 65.411 11.928 65.555 ;
     RECT  53.712 65.509 54.744 65.555 ;
     RECT  63.12 65.509 64.104 65.555 ;
     RECT  45.36 62.341 47.832 65.603 ;
     RECT  34.8 64.643 36.696 65.605 ;
     RECT  27.936 64.933 30.216 65.651 ;
     RECT  29.04 65.651 30.216 65.699 ;
     RECT  15.264 64.837 16.008 65.939 ;
     RECT  16.992 65.027 17.016 66.035 ;
     RECT  32.4 64.595 32.424 66.037 ;
     RECT  5.856 65.941 5.88 66.083 ;
     RECT  15.264 65.939 15.672 66.083 ;
     RECT  61.104 65.509 62.112 66.085 ;
     RECT  56.112 65.171 57.624 66.131 ;
     RECT  32.4 66.037 32.472 66.229 ;
     RECT  15.264 66.083 15.336 66.277 ;
     RECT  32.4 66.229 33.096 66.277 ;
     RECT  18.6 64.595 19.896 66.325 ;
     RECT  23.328 65.461 26.952 66.371 ;
     RECT  15.216 66.277 15.336 66.419 ;
     RECT  34.8 65.605 37.416 66.419 ;
     RECT  4.032 65.365 4.536 66.467 ;
     RECT  31.632 66.277 33.096 66.515 ;
     RECT  42.72 66.277 42.744 66.515 ;
     RECT  13.2 65.411 13.608 66.517 ;
     RECT  11.568 65.555 11.592 66.661 ;
     RECT  29.04 65.699 29.712 66.901 ;
     RECT  21.024 65.365 21.192 67.141 ;
     RECT  32.4 66.515 33.096 67.141 ;
     RECT  53.712 65.555 54.6 67.141 ;
     RECT  56.112 66.131 56.904 67.189 ;
     RECT  0.144 63.541 0.408 67.237 ;
     RECT  53.712 67.141 55.032 67.237 ;
     RECT  56.112 67.189 57.288 67.237 ;
     RECT  4.512 66.467 4.536 67.283 ;
     RECT  23.328 66.371 25.608 67.283 ;
     RECT  32.4 67.141 33.192 67.283 ;
     RECT  64.08 65.555 64.104 67.283 ;
     RECT  11.376 66.661 11.592 67.285 ;
     RECT  13.2 66.517 14.328 67.285 ;
     RECT  15.312 66.419 15.336 67.285 ;
     RECT  0.144 67.237 1.128 67.331 ;
     RECT  18.6 66.325 19.944 67.331 ;
     RECT  0.384 67.331 1.128 67.427 ;
     RECT  36.672 66.419 37.416 67.523 ;
     RECT  15.312 67.285 15.384 67.619 ;
     RECT  51 65.459 51.312 67.717 ;
     RECT  11.376 67.285 14.328 67.859 ;
     RECT  36.672 67.523 36.696 67.859 ;
     RECT  45.36 65.603 46.968 67.859 ;
     RECT  50.64 67.717 51.312 67.957 ;
     RECT  12.576 67.859 14.328 68.003 ;
     RECT  11.376 67.859 11.592 68.099 ;
     RECT  40.2 64.883 40.512 68.101 ;
     RECT  29.04 66.901 30.456 68.243 ;
     RECT  53.712 67.237 57.288 68.243 ;
     RECT  61.008 66.085 62.112 68.245 ;
     RECT  45.36 67.859 46.008 68.341 ;
     RECT  56.4 68.243 57.288 68.387 ;
     RECT  23.328 67.283 24.504 68.389 ;
     RECT  25.488 67.283 25.608 68.389 ;
     RECT  43.392 66.661 43.416 68.389 ;
     RECT  44.448 68.341 46.008 68.389 ;
     RECT  23.328 68.389 25.608 68.435 ;
     RECT  43.392 68.389 46.008 68.435 ;
     RECT  24 68.435 25.608 68.531 ;
     RECT  43.632 68.435 46.008 68.531 ;
     RECT  0.384 67.427 0.408 68.869 ;
     RECT  17.184 66.997 17.208 68.915 ;
     RECT  7.8 65.555 8.112 68.917 ;
     RECT  10.272 65.989 10.296 68.917 ;
     RECT  11.376 68.099 11.544 68.917 ;
     RECT  26.592 66.371 26.952 68.917 ;
     RECT  27.936 65.651 27.96 68.917 ;
     RECT  26.592 68.917 27.96 68.965 ;
     RECT  29.04 68.243 29.712 68.965 ;
     RECT  40.2 68.101 41.064 68.965 ;
     RECT  34.8 66.419 35.352 69.011 ;
     RECT  61.008 68.245 62.52 69.011 ;
     RECT  13.2 68.003 14.328 69.013 ;
     RECT  0.288 68.869 0.408 69.061 ;
     RECT  40.2 68.965 41.16 69.107 ;
     RECT  13.104 69.013 14.328 69.155 ;
     RECT  21.024 67.141 21.672 69.155 ;
     RECT  21.024 69.155 21.096 69.203 ;
     RECT  26.592 68.965 29.712 69.203 ;
     RECT  10.272 68.917 11.544 69.251 ;
     RECT  13.104 69.155 14.232 69.251 ;
     RECT  50.64 67.957 51.432 69.301 ;
     RECT  53.712 68.243 55.032 69.347 ;
     RECT  6.288 69.205 6.312 69.443 ;
     RECT  61.8 69.011 62.52 69.491 ;
     RECT  11.376 69.251 11.544 69.493 ;
     RECT  13.2 69.251 14.232 69.539 ;
     RECT  34.8 69.011 35.304 69.587 ;
     RECT  15.312 67.619 15.336 69.637 ;
     RECT  28.656 69.203 29.712 69.731 ;
     RECT  25.584 68.531 25.608 69.781 ;
     RECT  26.592 69.203 27.048 69.781 ;
     RECT  15.312 69.637 16.104 69.827 ;
     RECT  0.288 69.061 0.552 69.829 ;
     RECT  7.8 68.917 8.232 69.875 ;
     RECT  32.4 67.283 32.424 70.019 ;
     RECT  24 68.531 24.504 70.021 ;
     RECT  50.64 69.301 52.296 70.067 ;
     RECT  23.376 70.021 24.504 70.069 ;
     RECT  44.448 68.531 46.008 70.069 ;
     RECT  50.88 70.067 52.296 70.069 ;
     RECT  53.712 69.347 54.6 70.069 ;
     RECT  56.4 68.387 57.24 70.069 ;
     RECT  25.584 69.781 27.048 70.115 ;
     RECT  44.448 70.069 46.056 70.163 ;
     RECT  22.608 70.069 24.504 70.259 ;
     RECT  10.272 69.251 10.296 70.261 ;
     RECT  11.376 69.493 11.88 70.261 ;
     RECT  18.6 67.331 19.896 70.261 ;
     RECT  21.072 69.203 21.096 70.261 ;
     RECT  40.2 69.107 40.512 70.261 ;
     RECT  47.424 70.021 47.448 70.357 ;
     RECT  50.88 70.069 54.6 70.357 ;
     RECT  40.2 70.261 40.728 70.403 ;
     RECT  7.8 69.875 8.112 70.405 ;
     RECT  50.88 70.357 54.984 70.499 ;
     RECT  13.2 69.539 13.896 70.645 ;
     RECT  24 70.259 24.504 70.645 ;
     RECT  25.584 70.115 25.608 70.645 ;
     RECT  10.272 70.261 11.88 70.691 ;
     RECT  18.6 70.261 21.096 70.739 ;
     RECT  36.432 69.829 36.456 70.739 ;
     RECT  66.096 65.509 66.84 70.739 ;
     RECT  29.232 69.731 29.712 70.835 ;
     RECT  47.088 70.357 47.448 70.835 ;
     RECT  22.608 70.259 22.632 70.837 ;
     RECT  7.44 70.405 8.112 71.029 ;
     RECT  2.4 65.555 2.712 71.173 ;
     RECT  12.96 70.645 13.896 71.221 ;
     RECT  15.312 69.827 15.48 71.221 ;
     RECT  26.592 70.115 27.048 71.221 ;
     RECT  50.88 70.499 54.6 71.221 ;
     RECT  6.72 71.029 8.112 71.267 ;
     RECT  12.96 71.221 15.48 71.269 ;
     RECT  7.44 71.267 8.112 71.315 ;
     RECT  21.648 70.837 22.632 71.315 ;
     RECT  50.16 71.221 54.6 71.315 ;
     RECT  50.16 71.315 53.592 71.363 ;
     RECT  12.96 71.269 15.528 71.411 ;
     RECT  48.624 71.317 48.648 71.459 ;
     RECT  22.608 71.315 22.632 71.603 ;
     RECT  45.36 70.163 46.056 71.605 ;
     RECT  12.96 71.411 15.48 71.651 ;
     RECT  45.36 71.605 47.016 71.651 ;
     RECT  24 70.645 25.608 71.701 ;
     RECT  26.592 71.221 27.912 71.701 ;
     RECT  0.144 69.829 0.552 71.747 ;
     RECT  18.6 70.739 20.232 71.749 ;
     RECT  17.616 71.749 20.232 71.843 ;
     RECT  66.24 70.739 66.264 71.843 ;
     RECT  11.568 70.691 11.88 71.891 ;
     RECT  7.8 71.315 8.112 71.989 ;
     RECT  9.12 71.797 9.144 71.989 ;
     RECT  11.856 71.891 11.88 71.989 ;
     RECT  12.96 71.651 15.336 71.989 ;
     RECT  0.144 71.747 0.408 72.035 ;
     RECT  7.8 71.989 9.144 72.083 ;
     RECT  43.92 71.173 43.944 72.179 ;
     RECT  54.576 71.315 54.6 72.179 ;
     RECT  40.2 70.403 40.512 72.181 ;
     RECT  7.8 72.083 9 72.227 ;
     RECT  0.24 72.035 0.408 72.275 ;
     RECT  7.8 72.227 8.904 72.275 ;
     RECT  11.856 71.989 15.336 72.275 ;
     RECT  24 71.701 27.912 72.323 ;
     RECT  10.272 70.691 10.296 72.325 ;
     RECT  26.928 72.323 27.912 72.325 ;
     RECT  45.6 71.651 47.016 72.419 ;
     RECT  50.16 71.363 51.312 72.419 ;
     RECT  53.184 71.363 53.592 72.419 ;
     RECT  53.568 72.419 53.592 72.421 ;
     RECT  2.4 71.173 2.904 72.467 ;
     RECT  34.8 69.587 35.112 72.517 ;
     RECT  7.8 72.275 8.112 72.853 ;
     RECT  5.856 72.325 5.88 72.901 ;
     RECT  38.352 71.989 38.376 72.947 ;
     RECT  17.616 71.843 20.136 72.995 ;
     RECT  56.4 70.069 57.624 73.043 ;
     RECT  29.28 70.835 29.712 73.091 ;
     RECT  12.96 72.275 15.336 73.093 ;
     RECT  32.832 72.325 32.856 73.141 ;
     RECT  33.984 72.517 35.112 73.141 ;
     RECT  32.832 73.141 35.112 73.187 ;
     RECT  6.912 72.853 8.112 73.333 ;
     RECT  24 72.323 25.896 73.379 ;
     RECT  59.28 73.189 59.304 73.475 ;
     RECT  60.384 72.325 60.408 73.475 ;
     RECT  18.6 72.995 20.136 73.477 ;
     RECT  21.216 72.565 21.24 73.477 ;
     RECT  33.024 73.187 35.112 73.477 ;
     RECT  40.08 72.181 40.512 73.477 ;
     RECT  41.52 72.421 41.544 73.477 ;
     RECT  18.6 73.477 21.24 73.523 ;
     RECT  25.344 73.379 25.896 73.571 ;
     RECT  12.96 73.093 15.384 73.811 ;
     RECT  43.872 72.757 43.896 73.813 ;
     RECT  43.344 73.813 43.896 73.859 ;
     RECT  61.8 69.491 62.112 73.861 ;
     RECT  40.08 73.477 41.544 73.955 ;
     RECT  13.104 73.811 15.384 74.003 ;
     RECT  61.152 73.861 62.112 74.051 ;
     RECT  5.712 72.901 5.88 74.053 ;
     RECT  6.912 73.333 8.568 74.053 ;
     RECT  38.688 73.957 38.712 74.053 ;
     RECT  33.024 73.477 35.688 74.147 ;
     RECT  5.712 74.053 8.568 74.243 ;
     RECT  40.2 73.955 41.544 74.291 ;
     RECT  56.4 73.043 56.712 74.389 ;
     RECT  24 73.379 24.312 74.581 ;
     RECT  25.344 73.571 25.704 74.581 ;
     RECT  59.472 74.053 59.496 74.581 ;
     RECT  55.776 74.389 56.712 74.627 ;
     RECT  0.384 72.275 0.408 74.629 ;
     RECT  5.712 74.243 8.112 74.629 ;
     RECT  0.192 74.629 0.408 74.675 ;
     RECT  26.928 72.325 28.056 74.723 ;
     RECT  33.024 74.147 33.048 74.723 ;
     RECT  0.192 74.675 0.312 74.771 ;
     RECT  48.96 74.101 48.984 74.819 ;
     RECT  56.4 74.627 56.712 74.965 ;
     RECT  3.84 74.053 3.864 75.011 ;
     RECT  43.344 73.859 43.368 75.109 ;
     RECT  18.6 73.523 20.568 75.157 ;
     RECT  40.2 74.291 40.512 75.157 ;
     RECT  53.568 72.421 54.12 75.157 ;
     RECT  43.344 75.109 44.04 75.251 ;
     RECT  52.752 75.157 54.12 75.299 ;
     RECT  59.232 74.581 59.496 75.301 ;
     RECT  37.824 74.053 38.712 75.395 ;
     RECT  46.992 72.419 47.016 75.397 ;
     RECT  46.992 75.397 47.208 75.443 ;
     RECT  58.512 75.301 59.496 75.443 ;
     RECT  58.608 75.443 59.496 75.587 ;
     RECT  24 74.581 25.704 75.637 ;
     RECT  34.224 74.147 35.688 75.685 ;
     RECT  34.224 75.685 36.072 75.731 ;
     RECT  5.616 74.629 8.112 75.733 ;
     RECT  16.416 74.965 16.44 75.733 ;
     RECT  10.272 72.325 10.344 75.779 ;
     RECT  0.288 74.771 0.312 75.781 ;
     RECT  11.376 75.205 11.4 75.781 ;
     RECT  28.032 74.723 28.056 75.781 ;
     RECT  32.256 75.541 32.28 75.781 ;
     RECT  5.616 75.733 8.232 75.875 ;
     RECT  16.416 75.733 17.4 75.875 ;
     RECT  50.88 72.419 51.312 75.875 ;
     RECT  56.4 74.965 57.48 75.875 ;
     RECT  0.288 75.781 0.6 75.971 ;
     RECT  0.288 75.971 0.552 76.021 ;
     RECT  51 75.875 51.312 76.213 ;
     RECT  52.752 75.299 53.928 76.213 ;
     RECT  5.616 75.875 5.64 76.261 ;
     RECT  40.08 75.157 40.512 76.261 ;
     RECT  41.52 74.291 41.544 76.261 ;
     RECT  0.144 76.021 0.552 76.307 ;
     RECT  5.376 76.261 5.64 76.307 ;
     RECT  27.888 75.781 28.056 76.309 ;
     RECT  29.4 73.091 29.712 76.309 ;
     RECT  47.184 75.443 47.208 76.309 ;
     RECT  40.08 76.261 41.544 76.355 ;
     RECT  27.888 76.309 29.712 76.357 ;
     RECT  59.232 75.587 59.496 76.403 ;
     RECT  47.184 76.309 47.304 76.453 ;
     RECT  48.48 76.309 48.504 76.453 ;
     RECT  3.936 75.781 3.96 76.499 ;
     RECT  59.232 76.403 59.256 76.499 ;
     RECT  0.288 76.307 0.552 76.547 ;
     RECT  5.376 76.307 5.4 76.597 ;
     RECT  10.272 75.779 10.296 76.643 ;
     RECT  51 76.213 53.928 76.691 ;
     RECT  34.8 75.731 36.072 76.693 ;
     RECT  40.2 76.355 41.544 76.693 ;
     RECT  47.184 76.453 48.504 76.693 ;
     RECT  34.8 76.693 36.216 76.739 ;
     RECT  11.376 75.781 11.448 76.741 ;
     RECT  18.6 75.157 20.808 76.741 ;
     RECT  27.408 76.357 29.712 76.741 ;
     RECT  17.376 75.875 17.4 76.787 ;
     RECT  24 75.637 26.088 76.787 ;
     RECT  14.88 74.003 15.384 76.835 ;
     RECT  36.192 76.739 36.216 76.835 ;
     RECT  40.2 76.693 42.12 76.835 ;
     RECT  47.184 76.693 48.6 76.835 ;
     RECT  38.688 75.395 38.712 76.837 ;
     RECT  45.6 72.419 46.008 76.837 ;
     RECT  13.104 74.003 13.896 76.885 ;
     RECT  14.88 76.835 15.288 76.885 ;
     RECT  11.376 76.741 11.64 76.931 ;
     RECT  11.376 76.931 11.4 76.933 ;
     RECT  11.088 76.933 11.4 76.979 ;
     RECT  31.344 75.781 32.28 76.979 ;
     RECT  45.6 76.837 46.056 76.981 ;
     RECT  47.184 76.835 47.304 76.981 ;
     RECT  38.016 76.837 38.712 77.027 ;
     RECT  42.096 76.835 42.12 77.317 ;
     RECT  43.344 75.251 43.368 77.317 ;
     RECT  0.288 76.547 0.312 77.413 ;
     RECT  61.8 74.051 62.112 77.413 ;
     RECT  18.48 76.741 20.808 77.459 ;
     RECT  40.2 76.835 40.728 77.459 ;
     RECT  13.104 76.885 15.288 77.555 ;
     RECT  26.064 76.787 26.088 77.555 ;
     RECT  48.48 76.835 48.6 77.555 ;
     RECT  22.896 74.053 22.92 77.557 ;
     RECT  24 76.787 25.032 77.557 ;
     RECT  22.896 77.557 25.032 77.603 ;
     RECT  51 76.691 52.776 77.603 ;
     RECT  6.912 75.875 8.232 77.653 ;
     RECT  51 77.603 51.312 77.653 ;
     RECT  52.416 77.603 52.776 77.797 ;
     RECT  53.808 76.691 53.928 77.797 ;
     RECT  6.864 77.653 8.76 77.891 ;
     RECT  39.12 77.749 39.144 77.939 ;
     RECT  50.016 77.653 51.312 77.939 ;
     RECT  52.416 77.797 53.928 77.939 ;
     RECT  0.144 77.413 0.312 77.989 ;
     RECT  33.36 77.893 33.384 78.035 ;
     RECT  52.416 77.939 52.68 78.035 ;
     RECT  23.184 77.603 25.032 78.037 ;
     RECT  42.096 77.317 43.368 78.037 ;
     RECT  4.512 76.597 5.4 78.131 ;
     RECT  42.096 78.037 43.656 78.131 ;
     RECT  0.144 77.989 0.552 78.179 ;
     RECT  18.48 77.459 20.664 78.229 ;
     RECT  48.48 77.555 48.504 78.323 ;
     RECT  17.184 78.133 17.208 78.325 ;
     RECT  27.408 76.741 30.312 78.419 ;
     RECT  14.88 77.555 15.288 78.421 ;
     RECT  18.192 78.229 20.664 78.421 ;
     RECT  45.6 76.981 47.304 78.421 ;
     RECT  53.808 77.939 53.928 78.467 ;
     RECT  42.096 78.131 42.12 78.469 ;
     RECT  23.184 78.037 25.8 78.517 ;
     RECT  27.408 78.419 27.96 78.517 ;
     RECT  9.12 78.421 9.144 78.563 ;
     RECT  17.088 78.325 17.208 78.611 ;
     RECT  52.416 78.035 52.44 78.613 ;
     RECT  18.192 78.421 21.24 78.661 ;
     RECT  40.2 77.459 40.512 78.661 ;
     RECT  41.904 78.469 42.12 78.661 ;
     RECT  23.184 78.517 27.96 78.707 ;
     RECT  61.248 77.413 62.112 78.755 ;
     RECT  40.2 78.661 42.12 78.803 ;
     RECT  17.664 78.661 21.24 78.851 ;
     RECT  0.192 78.179 0.552 79.045 ;
     RECT  11.088 76.979 11.112 79.045 ;
     RECT  51 77.939 51.312 79.045 ;
     RECT  38.016 77.027 38.04 79.139 ;
     RECT  58.224 77.413 58.248 79.139 ;
     RECT  14.88 78.421 15.528 79.141 ;
     RECT  16.56 78.949 16.584 79.141 ;
     RECT  14.88 79.141 16.584 79.187 ;
     RECT  34.8 76.739 35.112 79.189 ;
     RECT  40.2 78.803 40.512 79.189 ;
     RECT  59.712 78.085 59.736 79.189 ;
     RECT  32.256 76.979 32.28 79.237 ;
     RECT  4.512 78.131 4.536 79.283 ;
     RECT  32.016 79.237 32.28 79.283 ;
     RECT  0.192 79.045 0.84 79.333 ;
     RECT  2.4 72.467 2.712 79.477 ;
     RECT  27.936 78.707 27.96 79.477 ;
     RECT  28.992 78.419 30.312 79.477 ;
     RECT  61.8 78.755 62.112 79.525 ;
     RECT  50.688 79.045 51.312 79.571 ;
     RECT  10.608 79.045 11.112 79.573 ;
     RECT  27.936 79.477 30.312 79.715 ;
     RECT  59.328 79.189 59.736 79.715 ;
     RECT  56.4 75.875 56.712 79.717 ;
     RECT  34.8 79.189 35.928 79.765 ;
     RECT  17.664 78.851 21.096 79.859 ;
     RECT  27.936 79.715 29.712 79.859 ;
     RECT  41.904 78.803 42.12 79.859 ;
     RECT  45.6 78.421 47.88 79.859 ;
     RECT  61.8 79.525 62.712 79.859 ;
     RECT  5.616 78.613 5.64 79.955 ;
     RECT  34.8 79.765 36.456 79.957 ;
     RECT  13.104 77.555 13.656 80.005 ;
     RECT  52.368 78.613 52.44 80.099 ;
     RECT  10.608 79.573 11.4 80.101 ;
     RECT  12.48 80.005 13.656 80.101 ;
     RECT  14.88 79.187 16.536 80.147 ;
     RECT  34.704 79.957 36.456 80.147 ;
     RECT  48.96 79.333 48.984 80.147 ;
     RECT  2.4 79.477 3.192 80.197 ;
     RECT  14.88 80.147 16.104 80.291 ;
     RECT  17.664 79.859 20.424 80.291 ;
     RECT  23.184 78.707 26.472 80.339 ;
     RECT  37.584 79.765 37.608 80.339 ;
     RECT  10.608 80.101 13.656 80.341 ;
     RECT  40.08 79.189 40.512 80.341 ;
     RECT  42.096 79.859 42.12 80.387 ;
     RECT  40.08 80.341 41.064 80.579 ;
     RECT  10.56 80.341 13.656 80.629 ;
     RECT  9.648 80.629 13.656 80.675 ;
     RECT  55.824 79.717 56.712 80.677 ;
     RECT  45.6 79.859 47.304 80.819 ;
     RECT  28.896 79.859 29.712 80.821 ;
     RECT  26.448 80.339 26.472 80.917 ;
     RECT  54.96 80.677 56.712 80.917 ;
     RECT  6.864 77.891 8.112 81.011 ;
     RECT  58.176 79.189 58.2 81.011 ;
     RECT  52.416 80.099 52.44 81.013 ;
     RECT  53.808 78.467 53.832 81.013 ;
     RECT  49.008 80.869 49.032 81.059 ;
     RECT  54.96 80.917 56.856 81.107 ;
     RECT  26.448 80.917 26.712 81.155 ;
     RECT  52.416 81.013 53.832 81.203 ;
     RECT  9.648 80.675 11.112 81.205 ;
     RECT  9.36 81.205 11.112 81.251 ;
     RECT  68.928 81.061 68.952 81.251 ;
     RECT  28.896 80.821 30.216 81.395 ;
     RECT  34.8 80.147 36.456 81.395 ;
     RECT  26.448 81.155 26.472 81.397 ;
     RECT  26.208 81.397 26.472 81.443 ;
     RECT  15.072 80.291 16.104 81.445 ;
     RECT  43.632 78.131 43.656 81.445 ;
     RECT  15.072 81.445 16.296 81.491 ;
     RECT  28.992 81.395 30.216 81.491 ;
     RECT  2.4 80.197 3.432 81.539 ;
     RECT  22.08 80.101 22.104 81.779 ;
     RECT  45.6 80.819 46.152 81.779 ;
     RECT  36.144 81.395 36.456 81.875 ;
     RECT  40.2 80.579 41.064 81.877 ;
     RECT  17.664 80.291 20.376 82.019 ;
     RECT  10.56 81.251 11.112 82.021 ;
     RECT  15.072 81.491 15.144 82.021 ;
     RECT  23.184 80.339 25.032 82.115 ;
     RECT  5.088 80.917 5.112 82.117 ;
     RECT  50.88 79.571 51.312 82.117 ;
     RECT  23.472 82.115 25.032 82.213 ;
     RECT  47.28 80.819 47.304 82.213 ;
     RECT  29.04 81.491 30.216 82.259 ;
     RECT  49.008 82.069 49.032 82.259 ;
     RECT  10.56 82.021 11.352 82.261 ;
     RECT  12.336 80.675 13.656 82.261 ;
     RECT  50.736 82.117 51.312 82.355 ;
     RECT  43.632 81.445 44.04 82.357 ;
     RECT  38.64 80.869 38.664 82.403 ;
     RECT  47.28 82.213 47.496 82.403 ;
     RECT  7.632 81.011 8.112 82.405 ;
     RECT  9.36 81.251 9.384 82.405 ;
     RECT  16.224 81.491 16.296 82.405 ;
     RECT  18.192 82.019 20.376 82.405 ;
     RECT  26.208 81.443 26.232 82.453 ;
     RECT  40.2 81.877 41.448 82.453 ;
     RECT  32.016 79.283 32.04 82.549 ;
     RECT  40.08 82.453 41.448 82.595 ;
     RECT  5.088 82.117 5.688 82.597 ;
     RECT  50.832 82.355 51.312 82.643 ;
     RECT  31.968 82.549 32.04 82.691 ;
     RECT  33.744 81.733 33.768 82.691 ;
     RECT  52.416 81.203 52.44 82.691 ;
     RECT  53.808 81.203 53.832 82.691 ;
     RECT  14.784 82.021 15.144 82.739 ;
     RECT  29.04 82.259 29.712 82.741 ;
     RECT  0.144 79.333 0.84 82.787 ;
     RECT  16.224 82.405 17.16 82.787 ;
     RECT  31.968 82.691 31.992 82.787 ;
     RECT  54.96 81.107 56.712 82.787 ;
     RECT  15.12 82.739 15.144 82.837 ;
     RECT  16.224 82.787 16.296 82.837 ;
     RECT  10.56 82.261 13.656 82.883 ;
     RECT  23.472 82.213 25.08 82.885 ;
     RECT  26.208 82.453 26.28 82.885 ;
     RECT  4.944 82.597 5.688 82.933 ;
     RECT  4.848 82.933 5.688 83.029 ;
     RECT  28.512 82.741 29.712 83.029 ;
     RECT  43.632 82.357 44.472 83.075 ;
     RECT  15.12 82.837 16.296 83.123 ;
     RECT  18.192 82.405 21.672 83.125 ;
     RECT  28.464 83.029 29.712 83.125 ;
     RECT  7.632 82.405 9.384 83.173 ;
     RECT  10.56 82.883 11.736 83.173 ;
     RECT  18.192 83.125 22.008 83.173 ;
     RECT  23.472 82.885 26.28 83.173 ;
     RECT  28.272 83.125 29.712 83.173 ;
     RECT  40.2 82.595 41.448 83.173 ;
     RECT  13.056 82.883 13.656 83.219 ;
     RECT  18.192 83.173 26.28 83.219 ;
     RECT  44.448 83.075 44.472 83.267 ;
     RECT  54.96 82.787 54.984 83.267 ;
     RECT  18.192 83.219 20.376 83.315 ;
     RECT  21.648 83.219 26.28 83.363 ;
     RECT  4.752 83.029 5.688 83.365 ;
     RECT  13.104 83.219 13.656 83.411 ;
     RECT  24 83.363 26.28 83.461 ;
     RECT  28.176 83.173 29.712 83.461 ;
     RECT  7.632 83.173 11.736 83.555 ;
     RECT  3.984 83.365 5.688 83.603 ;
     RECT  21.648 83.363 22.968 83.603 ;
     RECT  3.984 83.603 4.008 83.651 ;
     RECT  7.632 83.555 11.688 83.699 ;
     RECT  24 83.461 27.144 83.749 ;
     RECT  49.056 82.981 49.08 83.749 ;
     RECT  2.4 81.539 2.856 83.795 ;
     RECT  7.632 83.699 11.64 83.795 ;
     RECT  38.784 83.509 38.808 83.843 ;
     RECT  53.568 82.741 53.592 83.843 ;
     RECT  24 83.749 27.192 83.939 ;
     RECT  32.016 83.749 32.04 83.941 ;
     RECT  60.528 82.597 60.552 83.989 ;
     RECT  27.12 83.939 27.192 84.035 ;
     RECT  60.528 83.989 60.648 84.035 ;
     RECT  34.8 81.395 35.112 84.037 ;
     RECT  36.144 81.875 36.168 84.037 ;
     RECT  45.6 81.779 46.008 84.037 ;
     RECT  13.2 83.411 13.656 84.131 ;
     RECT  40.2 83.173 41.784 84.181 ;
     RECT  44.976 84.037 46.008 84.181 ;
     RECT  15.12 83.123 15.144 84.325 ;
     RECT  27.168 84.035 27.192 84.325 ;
     RECT  28.176 83.461 30.216 84.325 ;
     RECT  34.8 84.037 36.168 84.325 ;
     RECT  49.056 83.749 49.128 84.325 ;
     RECT  50.88 82.643 51.312 84.325 ;
     RECT  34.176 84.325 36.168 84.419 ;
     RECT  4.992 83.603 5.688 84.563 ;
     RECT  7.632 83.795 11.592 84.563 ;
     RECT  7.632 84.563 8.232 84.611 ;
     RECT  9.312 84.563 11.592 84.611 ;
     RECT  0.144 82.787 0.504 84.659 ;
     RECT  7.8 84.611 8.232 84.659 ;
     RECT  16.272 83.123 16.296 84.709 ;
     RECT  34.176 84.419 35.352 84.709 ;
     RECT  49.056 84.325 49.224 84.709 ;
     RECT  21.648 83.603 22.872 84.755 ;
     RECT  49.056 84.709 49.56 84.755 ;
     RECT  16.272 84.709 17.112 84.851 ;
     RECT  18.192 83.315 19.608 84.851 ;
     RECT  47.28 82.403 47.304 84.851 ;
     RECT  50.88 84.325 52.248 84.853 ;
     RECT  56.4 82.787 56.712 84.853 ;
     RECT  33.648 84.709 35.352 84.899 ;
     RECT  59.328 79.715 59.352 84.901 ;
     RECT  0.192 84.659 0.504 84.947 ;
     RECT  4.992 84.563 5.064 84.995 ;
     RECT  16.272 84.851 16.296 84.995 ;
     RECT  10.56 84.611 11.592 85.043 ;
     RECT  50.832 84.853 52.248 85.043 ;
     RECT  32.016 83.941 32.616 85.091 ;
     RECT  60.624 84.035 60.648 85.091 ;
     RECT  9.312 84.611 9.336 85.139 ;
     RECT  27.168 84.325 30.216 85.139 ;
     RECT  10.848 85.043 11.592 85.141 ;
     RECT  13.2 84.131 13.608 85.141 ;
     RECT  0.288 84.947 0.504 85.187 ;
     RECT  10.848 85.141 13.608 85.237 ;
     RECT  14.736 84.325 15.144 85.237 ;
     RECT  59.232 84.901 59.352 85.237 ;
     RECT  5.04 84.995 5.064 85.475 ;
     RECT  10.848 85.237 15.144 85.475 ;
     RECT  44.976 84.181 46.056 85.523 ;
     RECT  61.8 79.859 62.112 85.525 ;
     RECT  32.016 85.091 32.04 85.621 ;
     RECT  45.6 85.523 46.056 85.667 ;
     RECT  50.88 85.043 52.248 85.669 ;
     RECT  18.192 84.851 18.912 85.715 ;
     RECT  14.736 85.475 15.144 85.957 ;
     RECT  49.2 84.755 49.56 85.957 ;
     RECT  31.344 85.621 32.04 86.003 ;
     RECT  49.2 85.957 49.896 86.005 ;
     RECT  54.816 85.957 54.84 86.005 ;
     RECT  22.08 84.755 22.872 86.051 ;
     RECT  33.648 84.899 35.112 86.099 ;
     RECT  32.016 86.003 32.04 86.149 ;
     RECT  32.016 86.149 32.424 86.195 ;
     RECT  34.176 86.099 35.112 86.195 ;
     RECT  14.736 85.957 15.864 86.483 ;
     RECT  56.112 84.853 56.712 86.483 ;
     RECT  24 83.939 25.992 86.485 ;
     RECT  26.976 85.429 27 86.485 ;
     RECT  18.48 85.715 18.912 86.579 ;
     RECT  68.928 86.293 68.952 86.579 ;
     RECT  0.48 85.187 0.504 86.581 ;
     RECT  2.4 83.795 2.712 86.581 ;
     RECT  0.192 86.581 0.504 86.627 ;
     RECT  14.736 86.483 14.76 86.627 ;
     RECT  10.848 85.475 11.352 86.675 ;
     RECT  24 86.485 27 86.675 ;
     RECT  48.432 86.005 49.896 86.675 ;
     RECT  50.88 85.669 53.16 86.675 ;
     RECT  58.128 86.005 58.152 86.675 ;
     RECT  13.2 85.475 13.608 86.771 ;
     RECT  19.968 86.581 19.992 86.771 ;
     RECT  49.872 86.675 49.896 86.771 ;
     RECT  11.328 86.675 11.352 86.963 ;
     RECT  59.232 85.237 60.216 87.011 ;
     RECT  47.232 84.901 47.256 87.107 ;
     RECT  54.672 86.005 54.84 87.251 ;
     RECT  34.8 86.195 35.112 87.253 ;
     RECT  61.68 85.525 62.112 87.253 ;
     RECT  34.176 87.253 35.112 87.395 ;
     RECT  22.08 86.051 22.344 87.397 ;
     RECT  40.2 84.181 42.168 87.397 ;
     RECT  21.936 87.397 22.344 87.493 ;
     RECT  24 86.675 24.504 87.493 ;
     RECT  28.128 85.139 30.216 87.541 ;
     RECT  32.4 86.195 32.424 87.541 ;
     RECT  32.016 87.541 32.424 87.587 ;
     RECT  59.952 87.011 60.216 87.637 ;
     RECT  21.936 87.493 24.504 87.685 ;
     RECT  25.968 86.675 27 87.685 ;
     RECT  15.84 86.483 15.864 87.733 ;
     RECT  36.96 85.765 36.984 87.733 ;
     RECT  48.432 86.675 48.456 87.779 ;
     RECT  28.128 87.541 30.744 87.781 ;
     RECT  39.504 87.397 42.168 87.781 ;
     RECT  44.448 86.581 44.472 87.781 ;
     RECT  36.96 87.733 37.464 87.827 ;
     RECT  39.504 87.781 44.472 87.827 ;
     RECT  63.408 85.909 63.432 87.827 ;
     RECT  56.304 86.483 56.712 87.875 ;
     RECT  28.128 87.781 30.84 87.923 ;
     RECT  0.192 86.627 0.216 88.019 ;
     RECT  7.8 84.659 8.112 88.069 ;
     RECT  13.2 86.771 13.512 88.069 ;
     RECT  13.104 88.069 13.512 88.211 ;
     RECT  21.936 87.685 27 88.355 ;
     RECT  39.504 87.827 43.944 88.355 ;
     RECT  66.48 85.093 66.504 88.403 ;
     RECT  15.84 87.733 16.68 88.453 ;
     RECT  43.104 88.355 43.944 88.595 ;
     RECT  50.88 86.675 52.248 88.597 ;
     RECT  59.952 87.637 60.36 88.597 ;
     RECT  50.88 88.597 53.016 88.739 ;
     RECT  56.4 87.875 56.712 88.741 ;
     RECT  15.744 88.453 16.68 88.837 ;
     RECT  32.016 87.587 32.04 88.883 ;
     RECT  56.4 88.741 56.808 88.883 ;
     RECT  7.8 88.069 8.328 88.885 ;
     RECT  10.08 88.837 10.104 88.885 ;
     RECT  11.376 87.157 11.4 88.885 ;
     RECT  22.176 88.355 27 88.931 ;
     RECT  43.92 88.595 43.944 88.931 ;
     RECT  22.32 88.931 27 88.933 ;
     RECT  28.176 87.923 30.84 88.933 ;
     RECT  15.744 88.837 17.544 88.979 ;
     RECT  22.32 88.933 30.84 88.979 ;
     RECT  2.4 86.581 3.288 89.171 ;
     RECT  26.976 88.979 30.84 89.171 ;
     RECT  26.976 89.171 30.216 89.219 ;
     RECT  34.8 87.395 35.112 89.317 ;
     RECT  15.744 88.979 15.768 89.461 ;
     RECT  59.952 88.597 60.408 89.603 ;
     RECT  50.88 88.739 52.872 89.699 ;
     RECT  39.504 88.355 41.448 89.747 ;
     RECT  45.6 85.667 46.008 89.747 ;
     RECT  50.88 89.699 52.296 89.747 ;
     RECT  27.648 89.219 30.216 89.795 ;
     RECT  39.504 89.747 40.512 89.795 ;
     RECT  24 88.979 25.416 89.843 ;
     RECT  27.648 89.795 28.248 89.843 ;
     RECT  18.6 86.579 18.912 89.845 ;
     RECT  19.968 88.357 19.992 89.845 ;
     RECT  5.76 88.885 5.784 89.987 ;
     RECT  22.32 88.979 22.488 89.989 ;
     RECT  45.6 89.747 45.912 89.989 ;
     RECT  13.2 88.211 13.512 90.037 ;
     RECT  59.952 89.603 59.976 90.037 ;
     RECT  10.08 88.885 11.4 90.083 ;
     RECT  17.52 88.979 17.544 90.083 ;
     RECT  38.496 88.165 38.52 90.083 ;
     RECT  61.584 87.253 62.112 90.083 ;
     RECT  63.552 89.269 63.576 90.083 ;
     RECT  27.648 89.843 27.672 90.227 ;
     RECT  7.8 88.885 8.952 90.275 ;
     RECT  25.392 89.843 25.416 90.275 ;
     RECT  29.4 89.795 30.216 90.371 ;
     RECT  34.8 89.317 35.448 90.373 ;
     RECT  18.6 89.845 19.992 90.421 ;
     RECT  21.408 89.989 22.488 90.515 ;
     RECT  26.496 90.325 26.52 90.565 ;
     RECT  7.8 90.275 8.568 90.659 ;
     RECT  15.36 89.461 15.768 90.659 ;
     RECT  34.464 90.373 35.448 90.659 ;
     RECT  13.2 90.037 13.608 90.709 ;
     RECT  15.744 90.659 15.768 90.755 ;
     RECT  13.104 90.709 14.088 90.851 ;
     RECT  44.64 89.989 45.912 90.901 ;
     RECT  44.64 90.901 46.008 90.947 ;
     RECT  59.856 90.037 59.976 90.947 ;
     RECT  45.6 90.947 46.008 91.189 ;
     RECT  18.6 90.421 20.328 91.235 ;
     RECT  32.736 90.229 32.76 91.235 ;
     RECT  47.664 89.461 47.688 91.235 ;
     RECT  51 89.747 52.296 91.235 ;
     RECT  54.816 87.251 54.84 91.379 ;
     RECT  26.496 90.565 27.48 91.571 ;
     RECT  21.408 90.515 22.344 91.667 ;
     RECT  13.2 90.851 14.088 91.717 ;
     RECT  31.584 90.325 31.608 91.717 ;
     RECT  61.8 90.083 62.112 91.717 ;
     RECT  19.968 91.235 20.328 91.763 ;
     RECT  56.4 88.883 56.712 91.813 ;
     RECT  11.376 90.083 11.4 91.859 ;
     RECT  45.6 91.189 46.584 91.859 ;
     RECT  57.936 88.741 57.96 91.859 ;
     RECT  26.496 91.571 26.52 91.907 ;
     RECT  13.2 91.717 14.856 92.003 ;
     RECT  34.464 90.659 35.112 92.003 ;
     RECT  31.104 91.717 31.608 92.147 ;
     RECT  37.44 87.827 37.464 92.147 ;
     RECT  14.832 92.003 14.856 92.291 ;
     RECT  5.136 91.717 5.16 92.339 ;
     RECT  31.104 92.147 31.128 92.339 ;
     RECT  19.968 91.763 19.992 92.387 ;
     RECT  22.32 91.667 22.344 92.387 ;
     RECT  45.6 91.859 46.008 92.387 ;
     RECT  59.952 90.947 59.976 92.387 ;
     RECT  61.8 91.717 62.664 92.387 ;
     RECT  51 91.235 52.056 92.435 ;
     RECT  40.08 89.795 40.512 92.531 ;
     RECT  10.08 90.083 10.104 92.675 ;
     RECT  56.4 91.813 56.808 92.723 ;
     RECT  42.48 91.429 42.504 92.819 ;
     RECT  2.4 89.171 2.712 92.889 ;
     RECT  7.8 90.659 8.112 92.889 ;
     RECT  13.2 92.003 13.512 92.889 ;
     RECT  18.6 91.235 18.912 92.889 ;
     RECT  24 89.843 24.312 92.889 ;
     RECT  29.4 90.371 29.712 92.889 ;
     RECT  34.8 92.003 35.112 92.889 ;
     RECT  40.2 92.531 40.512 92.889 ;
     RECT  45.6 92.387 45.912 92.889 ;
     RECT  51 92.435 51.312 92.889 ;
     RECT  56.4 92.723 56.712 92.889 ;
     RECT  61.8 92.387 62.112 92.889 ;
     RECT  2.4 92.889 2.52 92.903 ;
     RECT  7.8 92.889 7.92 92.903 ;
     RECT  13.2 92.889 13.32 92.903 ;
     RECT  18.6 92.889 18.72 92.903 ;
     RECT  24 92.889 24.12 92.903 ;
     RECT  29.4 92.889 29.52 92.903 ;
     RECT  34.8 92.889 34.92 92.903 ;
     RECT  40.2 92.889 40.32 92.903 ;
     RECT  45.6 92.889 45.72 92.903 ;
     RECT  51 92.889 51.12 92.903 ;
     RECT  56.4 92.889 56.52 92.903 ;
     RECT  61.8 92.889 61.92 92.903 ;
  END
END ot_s81_rate_match
END LIBRARY
